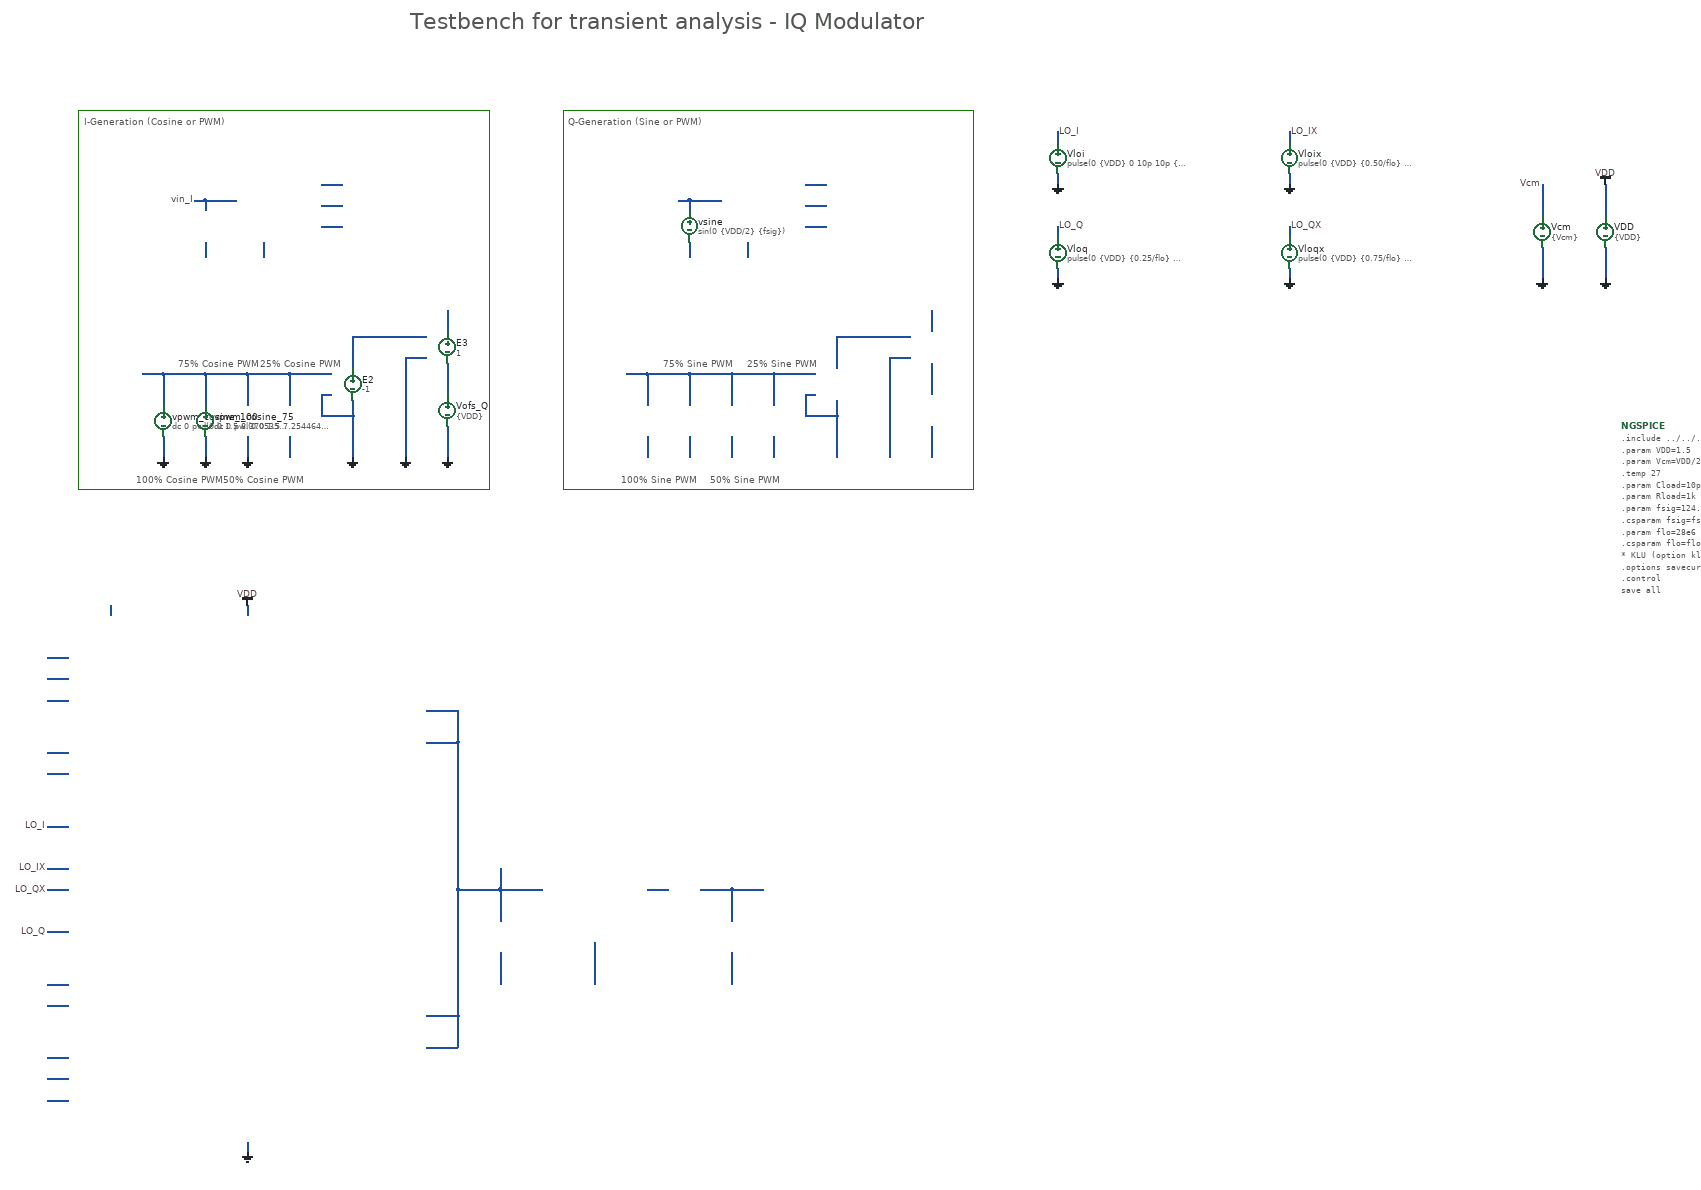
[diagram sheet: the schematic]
v {xschem version=3.4.8RC file_version=1.3}
G {}
K {}
V {}
S {}
F {}
E {}
B 2 1660 -1440 2460 -1040 {flags=graph
y1=-0.028
y2=2.632
ypos1=-0.028
ypos2=2.632
divy=5
subdivy=1
unity=1
x1=1.0032521e-05
x2=1.8057695e-05
divx=5
subdivx=1
xlabmag=1.0
ylabmag=1.0
node="LO_I
LO_Q
LO_IX
LO_QX"
color="4 7 12 21"
dataset=-1
unitx=1
logx=0
logy=0
linewidth_mult=3
autoload=0
digital=1}
B 2 1660 -1020 2460 -620 {flags=graph
y1=-0.39
y2=1.6
ypos1=0
ypos2=2
divy=5
subdivy=1
unity=1
x1=1.0032521e-05
x2=1.8057695e-05
divx=5
subdivx=1
xlabmag=1.0
ylabmag=1.0
node="vinp_I
vinn_I
vinp_Q
vinn_Q
vout_RF_filt"
color="4 7 12 18 21"
dataset=-1
unitx=1
logx=0
logy=0
linewidth_mult=3
autoload=0}
B 2 1660 -600 2460 -200 {flags=graph
y1=-0.052
y2=1.638
ypos1=0
ypos2=2
divy=5
subdivy=1
unity=1
x1=1.0032521e-05
x2=1.8057695e-05
divx=5
subdivx=1
xlabmag=1.0
ylabmag=1.0
node="vout_RF
vout_RF_filt"
color="4 7"
dataset=-1
unitx=1
logx=0
logy=0
linewidth_mult=3
autoload=0}
B 2 2540 -1440 3340 -1040 {flags=graph
y1=-0.086
y2=-0.0063
ypos1=0
ypos2=2
divy=5
subdivy=1
unity=1
x1=1.0032521e-05
x2=1.8057695e-05
divx=5
subdivx=1
xlabmag=1.0
ylabmag=1.0


dataset=-1
unitx=1
logx=0
logy=0
linewidth_mult=3
color=4
node=i(VDD)}
B 2 2540 -600 3340 -200 {flags=graph
y1=-0.00039
y2=0.00039
ypos1=0
ypos2=2
divy=5
subdivy=1
unity=1
x1=1.0032521e-05
x2=1.8057695e-05
divx=5
subdivx=1
xlabmag=1.0
ylabmag=1.0


dataset=-1
unitx=1
logx=0
logy=0
linewidth_mult=3
color=4
node=i(Vmeas)}
B 2 2540 -1020 3340 -620 {flags=graph
y1=0.25
y2=1.4
ypos1=0
ypos2=2
divy=5
subdivy=1
unity=1
x1=1.0032521e-05
x2=1.8057695e-05
divx=5
subdivx=1
xlabmag=1.0
ylabmag=1.0
node="x1.voutp_I_lpf
x1.voutn_I_lpf
x1.voutn_Q_lpf
x1.voutp_Q_lpf"
color="4 7 17 21"
dataset=-1
unitx=1
logx=0
logy=0
linewidth_mult=3
autoload=0}
B 4 240 -2200 1020 -1480 {fill = false
dash = 8}
B 4 1160 -2200 1940 -1480 {fill = false
dash = 8}
P 4 1 0 -2360 {}
T {Testbench for transient analysis - IQ Modulator} 870 -2380 0 0 1.5 1.5 {}
T {100% Cosine PWM} 350 -1510 0 0 0.25 0.25 {}
T {75% Cosine PWM} 430 -1730 0 0 0.25 0.25 {}
T {50% Cosine PWM} 515 -1510 0 0 0.25 0.25 {}
T {25% Cosine PWM} 585 -1730 0 0 0.25 0.25 {}
T {100% Sine PWM} 1270 -1510 0 0 0.25 0.25 {}
T {75% Sine PWM} 1350 -1730 0 0 0.25 0.25 {}
T {50% Sine PWM} 1440 -1510 0 0 0.25 0.25 {}
T {25% Sine PWM} 1510 -1730 0 0 0.25 0.25 {}
T {I-Generation (Cosine or PWM)} 250 -2190 0 0 0.4 0.4 {}
T {Q-Generation (Sine or PWM)} 1170 -2190 0 0 0.4 0.4 {}
N 560 -240 560 -220 {lab=GND}
N 180 -840 220 -840 {lab=LO_I}
N 180 -760 220 -760 {lab=LO_IX}
N 180 -640 220 -640 {lab=LO_Q}
N 180 -720 220 -720 {lab=LO_QX}
N 180 -500 220 -500 {lab=vinn_Q_sine}
N 180 -360 220 -360 {lab=vinp_Q_sine}
N 180 -1120 220 -1120 {lab=vinp_I_cosine}
N 180 -980 220 -980 {lab=vinn_I_cosine}
N 3140 -1940 3140 -1880 {lab=GND}
N 3140 -2060 3140 -2000 {lab=VDD}
N 3020 -1940 3020 -1880 {lab=GND}
N 3020 -2060 3020 -2000 {lab=Vcm}
N 2100 -1980 2100 -1960 {lab=LO_Q}
N 2100 -1900 2100 -1880 {lab=GND}
N 2540 -1980 2540 -1960 {lab=LO_QX}
N 2540 -1900 2540 -1880 {lab=GND}
N 2540 -2160 2540 -2140 {lab=LO_IX}
N 2540 -2080 2540 -2060 {lab=GND}
N 2100 -2160 2100 -2140 {lab=LO_I}
N 2100 -2080 2100 -2060 {lab=GND}
N 480 -1700 480 -1640 {lab=vinp_I_pwm}
N 480 -1580 480 -1540 {lab=GND}
N 400 -1580 400 -1540 {lab=GND}
N 400 -1700 400 -1640 {lab=vinp_I_pwm}
N 360 -1700 400 -1700 {lab=vinp_I_pwm}
N 400 -1700 480 -1700 {lab=vinp_I_pwm}
N 480 -1700 560 -1700 {lab=vinp_I_pwm}
N 760 -1620 760 -1540 {lab=GND}
N 700 -1660 720 -1660 {lab=GND}
N 700 -1660 700 -1620 {lab=GND}
N 700 -1620 760 -1620 {lab=GND}
N 940 -1820 940 -1780 {lab=vinn_I_pwm}
N 940 -1720 940 -1660 {lab=#net1}
N 940 -1600 940 -1540 {lab=GND}
N 860 -1730 900 -1730 {lab=GND}
N 860 -1730 860 -1540 {lab=GND}
N 760 -1770 900 -1770 {lab=#net2}
N 760 -1770 760 -1710 {lab=#net2}
N 560 -1700 560 -1640 {lab=vinp_I_pwm}
N 560 -1580 560 -1540 {lab=GND}
N 640 -1700 640 -1640 {lab=vinp_I_pwm}
N 640 -1580 640 -1540 {lab=GND}
N 560 -1700 640 -1700 {lab=vinp_I_pwm}
N 640 -1700 720 -1700 {lab=vinp_I_pwm}
N 1400 -1700 1400 -1640 {lab=vinp_Q_pwm}
N 1400 -1580 1400 -1540 {lab=GND}
N 1320 -1580 1320 -1540 {lab=GND}
N 1320 -1700 1320 -1640 {lab=vinp_Q_pwm}
N 1280 -1700 1320 -1700 {lab=vinp_Q_pwm}
N 1320 -1700 1400 -1700 {lab=vinp_Q_pwm}
N 1400 -1700 1480 -1700 {lab=vinp_Q_pwm}
N 1680 -1620 1680 -1540 {lab=GND}
N 1620 -1660 1640 -1660 {lab=GND}
N 1620 -1660 1620 -1620 {lab=GND}
N 1620 -1620 1680 -1620 {lab=GND}
N 1860 -1820 1860 -1780 {lab=vinn_Q_pwm}
N 1860 -1720 1860 -1660 {lab=#net3}
N 1860 -1600 1860 -1540 {lab=GND}
N 1780 -1730 1820 -1730 {lab=GND}
N 1780 -1730 1780 -1540 {lab=GND}
N 1680 -1770 1820 -1770 {lab=#net4}
N 1680 -1770 1680 -1710 {lab=#net4}
N 1480 -1700 1480 -1640 {lab=vinp_Q_pwm}
N 1480 -1580 1480 -1540 {lab=GND}
N 1560 -1700 1560 -1640 {lab=vinp_Q_pwm}
N 1560 -1580 1560 -1540 {lab=GND}
N 1480 -1700 1560 -1700 {lab=vinp_Q_pwm}
N 1560 -1700 1640 -1700 {lab=vinp_Q_pwm}
N 760 -1650 760 -1620 {lab=GND}
N 1680 -1650 1680 -1620 {lab=GND}
N 460 -2030 480 -2030 {lab=vin_I}
N 480 -2030 480 -2010 {lab=vin_I}
N 700 -2060 740 -2060 {lab=vinp_I_cosine}
N 700 -1980 740 -1980 {lab=vinn_I_cosine}
N 480 -2030 540 -2030 {lab=vin_I}
N 480 -1950 480 -1920 {lab=GND}
N 590 -1950 590 -1920 {lab=GND}
N 700 -2020 740 -2020 {lab=Vcm}
N 1380 -2030 1400 -2030 {lab=vin_Q}
N 1400 -2030 1400 -2010 {lab=vin_Q}
N 1620 -2060 1660 -2060 {lab=vinp_Q_sine}
N 1620 -1980 1660 -1980 {lab=vinn_Q_sine}
N 1400 -2030 1460 -2030 {lab=vin_Q}
N 1400 -1950 1400 -1920 {lab=GND}
N 1510 -1950 1510 -1920 {lab=GND}
N 1620 -2020 1660 -2020 {lab=Vcm}
N 1040 -760 1040 -720 {lab=vout_RF}
N 1220 -620 1220 -540 {lab=GND}
N 1480 -600 1480 -540 {lab=GND}
N 1480 -720 1480 -660 {lab=vout_RF_filt}
N 960 -720 1040 -720 {lab=vout_RF}
N 1040 -720 1040 -660 {lab=vout_RF}
N 1040 -600 1040 -540 {lab=GND}
N 1040 -720 1120 -720 {lab=vout_RF}
N 1320 -720 1360 -720 {lab=#net5}
N 1420 -720 1480 -720 {lab=vout_RF_filt}
N 1480 -720 1540 -720 {lab=vout_RF_filt}
N 560 -1260 560 -1240 {lab=VDD}
N 900 -1060 960 -1060 {lab=vout_RF}
N 960 -1000 960 -720 {lab=vout_RF}
N 900 -1000 960 -1000 {lab=vout_RF}
N 960 -1060 960 -1000 {lab=vout_RF}
N 900 -480 960 -480 {lab=vout_RF}
N 960 -720 960 -480 {lab=vout_RF}
N 900 -420 960 -420 {lab=vout_RF}
N 960 -480 960 -420 {lab=vout_RF}
N 300 -1260 300 -1240 {lab=VDD}
N 180 -1080 220 -1080 {lab=vinp_I_pwm}
N 180 -940 220 -940 {lab=vinn_I_pwm}
N 180 -540 220 -540 {lab=vinp_Q_pwm}
N 180 -400 220 -400 {lab=vinn_Q_pwm}
N 180 -320 220 -320 {lab=GND}
N 180 -1160 220 -1160 {lab=GND}
C {devices/code.sym} 3170 -1600 0 0 {name=NGSPICE
lock=false
only_toplevel=true 
value="
.include ../../../netlist/pex/iqmod_top_pex.spice
.param VDD=1.5
.param Vcm=VDD/2
.temp 27
.param Cload=10p
.param Rload=1k
.param fsig=124.600e3
.csparam fsig=fsig
.param flo=28e6
.csparam flo=flo
* KLU (option klu) did not converge on the old Magic full-RC PEX netlist with ngspice-47. On the KPEX 0.9.0 netlist KLU and Sparse 1.3 both converge
.options savecurrents method=gear reltol=1e-3 abstol=1e-12 gmin=1e-12 rshunt=1e12
.control

save all

* User Constants
* Increase tstop --> more FFT bins
* Decrease tstep --> higher fs/2 in FFT
let fmin = 0.1 * flo
let fmax = 5 * flo
let tstart = 1/fsig
let tstop = 2/fsig
let tstep = 0.1/flo

* Transient Operating Point Analysis
optran 0 0 0 $&tstep $&tstart 0

* Operating Point Analysis
* op
* remzerovec
* write @schname\\\\.raw
* set appendwrite

* Transient Analysis
tran $&tstep $&tstop $&tstart
write @schname\\\\.raw

* Plotting
plot vinp_I vinn_I vinp_Q vinn_Q
plot x1.voutp_I_lpf x1.voutn_I_lpf x1.voutp_Q_lpf x1.voutn_Q_lpf
plot LO_I LO_IX LO_Q LO_QX
plot vout_RF vout_RF_filt

* Calculation of Power Consumption & Efficiency
let PDD_inst = VDD * -i(VDD)
meas tran PDD_int INTEG PDD_inst from=tstart to=tstop
let PDD = 1/(tstop - tstart) * PDD_int * 1e3
echo PDD = $&PDD mW

let Pout_inst = v(vout_RF_filt) * i(Vmeas)
meas tran Pout_int INTEG Pout_inst from=tstart to=tstop
let Pout = 1/(tstop - tstart) * Pout_int * 1e3
echo Pout = $&Pout mW

let efficiency = Pout / PDD * 100
echo efficiency = $&efficiency %

* Write Data
unset appendwrite
set wr_vecnames
set wr_singlescale
wrdata ../plot_simulations/data/iqmod_top_tb_tran.txt v(vinp_Q) v(vinn_Q) v(vinp_I) v(vinn_I) v(LO_I) v(LO_IX) v(LO_Q) v(LO_QX) v(vout_RF) v(vout_RF_filt)

* FFT vout_RF
* setplot tran1
* linearize vout_RF
* set specwindow=hanning
* fft vout_RF
* setplot sp2

* let N = length(vout_RF)
* let fres = frequency[n-1]/n
* let fmin_idx = ceil(const.fmin/fres)
* let fmax_idx = ceil(const.fmax/fres)
* let vout_RF_spec = mag(vout_RF)
* let vout_RF_spec_slice = vout_RF_spec[fmin_idx,fmax_idx]
* let freq = frequency[fmin_idx,fmax_idx]
* meas sp vout_RF_max max vout_RF_spec_slice
* let vout_RF_spec_db = 20*log10(vout_RF_spec_slice/vout_RF_max)
* plot vout_RF_spec_db vs freq

* Write Data
* setscale freq
* unset appendwrite
* set wr_vecnames
* set wr_singlescale
* wrdata ../plot_simulations/data/iqmod_tb_tran_fft.txt v(vout_RF_spec_db)

* FFT vout_RF_filt
setplot tran1
linearize vout_RF_filt
set specwindow=hanning
fft vout_RF_filt
setplot sp2

let N = length(vout_RF_filt)
let fres = frequency[n-1]/n
let fmin_idx = ceil(const.fmin/fres)
let fmax_idx = ceil(const.fmax/fres)
let vout_RF_filt_spec = mag(vout_RF_filt)
let vout_RF_filt_spec_slice = vout_RF_filt_spec[fmin_idx,fmax_idx]
let freq = frequency[fmin_idx,fmax_idx]
meas sp vout_RF_filt_max max vout_RF_filt_spec_slice
let vout_RF_filt_spec_db = 20*log10(vout_RF_filt_spec_slice/vout_RF_filt_max)
plot vout_RF_filt_spec_db vs freq

* Write Data
setscale freq
unset appendwrite
set wr_vecnames
set wr_singlescale
wrdata ../plot_simulations/data/iqmod_tb_tran_fft_filt.txt v(vout_RF_filt_spec_db)

* Calc HD2, HD3
* let sig_idx = ceil(const.f_sig/fres)
* let hd2_idx = 2*sig_idx
* let hd3_idx = 3*sig_idx
* let sig_pwr = iod_spec[sig_idx-1]^2+iod_spec[sig_idx]^2+iod_spec[sig_idx+1]^2
* let hd2_pwr = iod_spec[hd2_idx-1]^2+iod_spec[hd2_idx]^2+iod_spec[hd2_idx+1]^2
* let hd3_pwr = iod_spec[hd3_idx-1]^2+iod_spec[hd3_idx]^2+iod_spec[hd3_idx+1]^2
* let hd2 = sqrt(hd2_pwr/sig_pwr)
* let hd3 = sqrt(hd3_pwr/sig_pwr)
* let hd2_dB = 20*log10(hd2)
* let hd3_dB = 20*log10(hd3)
* print hd2_dB
* print hd3_dB

*quit
.endc
"}
C {devices/launcher.sym} 2600 -1620 0 0 {name=h2
descr="Simulate" 
tclcommand="xschem save; xschem netlist; file mkdir $netlist_dir; write_data [save_params] $netlist_dir/[file rootname [file tail [xschem get current_name]]].save; xschem simulate"
}
C {devices/launcher.sym} 2600 -1500 0 0 {name=h1
descr="Load waves" 
tclcommand="xschem raw_read $netlist_dir/[file rootname [file tail [xschem get current_name]]].raw tran"
}
C {devices/launcher.sym} 2600 -1560 0 0 {name=h3
descr="Annotate OP" 
tclcommand="set show_hidden_texts 1; xschem annotate_op"
}
C {vdd.sym} 560 -1260 0 0 {name=l1 lab=VDD}
C {devices/gnd.sym} 560 -220 0 0 {name=l4 lab=GND}
C {devices/lab_wire.sym} 180 -840 0 0 {name=l11 sig_type=std_logic lab=LO_I}
C {devices/lab_wire.sym} 180 -760 0 0 {name=l12 sig_type=std_logic lab=LO_IX}
C {devices/lab_wire.sym} 180 -640 0 0 {name=l8 sig_type=std_logic lab=LO_Q}
C {devices/lab_wire.sym} 180 -720 0 0 {name=l22 sig_type=std_logic lab=LO_QX
}
C {devices/vsource.sym} 3140 -1970 0 0 {name=VDD value=\{VDD\}}
C {devices/gnd.sym} 3140 -1880 0 0 {name=l3 lab=GND}
C {vdd.sym} 3140 -2060 0 0 {name=l7 lab=VDD}
C {devices/gnd.sym} 2100 -2060 0 0 {name=l14 lab=GND}
C {devices/lab_wire.sym} 2100 -2160 0 1 {name=l15 sig_type=std_logic lab=LO_I}
C {devices/gnd.sym} 2540 -2060 0 0 {name=l9 lab=GND}
C {devices/lab_wire.sym} 2540 -2160 0 1 {name=l10 sig_type=std_logic lab=LO_IX}
C {devices/vsource.sym} 2100 -2110 0 0 {name=Vloi value="pulse(0 \{VDD\} 0 10p 10p \{0.25/flo\} \{1/flo\})"}
C {devices/vsource.sym} 2540 -2110 0 0 {name=Vloix value="pulse(0 \{VDD\} \{0.50/flo\} 10p 10p \{0.25/flo\} \{1/flo\})"}
C {devices/gnd.sym} 2100 -1880 0 0 {name=l23 lab=GND}
C {devices/lab_wire.sym} 2100 -1980 0 1 {name=l24 sig_type=std_logic lab=LO_Q}
C {devices/gnd.sym} 2540 -1880 0 0 {name=l27 lab=GND}
C {devices/lab_wire.sym} 2540 -1980 0 1 {name=l28 sig_type=std_logic lab=LO_QX}
C {devices/vsource.sym} 2540 -1930 0 0 {name=Vloqx value="pulse(0 \{VDD\} \{0.75/flo\} 10p 10p \{0.25/flo\} \{1/flo\})"}
C {devices/vsource.sym} 3020 -1970 0 0 {name=Vcm value=\{Vcm\}
}
C {devices/lab_pin.sym} 3020 -2060 1 0 {name=l34 sig_type=std_logic lab=Vcm}
C {devices/gnd.sym} 3020 -1880 0 0 {name=l40 lab=GND}
C {devices/vsource.sym} 2100 -1930 0 0 {name=Vloq value="pulse(0 \{VDD\} \{0.25/flo\} 10p 10p \{0.25/flo\} \{1/flo\})"}
C {devices/lab_pin.sym} 460 -2030 0 0 {name=l16 sig_type=std_logic lab=vin_I}
C {devices/vsource.sym} 1400 -1980 0 1 {name=vsine spice_ignore=false value="sin(0 \{VDD/2\} \{fsig\})"
}
C {devices/vcvs.sym} 760 -1680 0 0 {name=E2 value=-1}
C {devices/vsource.sym} 400 -1610 0 0 {name=vpwm_cosine_100 hide_texts=true value="dc 0 pwl(0.0 1.5 8.370535714285714e-09 1.5 8.928571428571428e-09 0.0 8.928571428571428e-09 0.0 9.486607142857142e-09 1.5 2.6227678571428568e-08 1.5 2.6785714285714285e-08 0.0 2.6785714285714285e-08 0.0 2.734375e-08 1.5 4.408482142857143e-08 1.5 4.464285714285714e-08 0.0 4.464285714285714e-08 0.0 4.5200892857142855e-08 1.5 6.194196428571429e-08 1.5 6.25e-08 0.0 6.25e-08 0.0 6.305803571428571e-08 1.5 7.979910714285714e-08 1.5 8.035714285714285e-08 0.0 8.035714285714285e-08 0.0 8.091517857142856e-08 1.5 9.765624999999999e-08 1.5 9.82142857142857e-08 0.0 9.82142857142857e-08 0.0 9.877232142857143e-08 1.5 1.1551339285714284e-07 1.5 1.1607142857142857e-07 0.0 1.1607142857142857e-07 0.0 1.1662946428571428e-07 1.5 1.333705357142857e-07 1.5 1.3392857142857142e-07 0.0 1.3392857142857142e-07 0.0 1.3448660714285714e-07 1.5 1.5122767857142855e-07 1.5 1.5178571428571427e-07 0.0 1.5178571428571427e-07 0.0 1.5234375e-07 1.5 1.6908482142857143e-07 1.5 1.6964285714285713e-07 0.0 1.6964285714285713e-07 0.0 1.7020089285714285e-07 1.5 1.8694196428571428e-07 1.5 1.8749999999999998e-07 0.0 1.8749999999999998e-07 0.0 1.880580357142857e-07 1.5 2.0479910714285713e-07 1.5 2.0535714285714283e-07 0.0 2.0535714285714283e-07 0.0 2.0591517857142855e-07 1.5 2.2265624999999999e-07 1.5 2.232142857142857e-07 0.0 2.232142857142857e-07 0.0 2.237723214285714e-07 1.5 2.4051339285714286e-07 1.5 2.4107142857142856e-07 0.0 2.4107142857142856e-07 0.0 2.4162946428571426e-07 1.5 2.583705357142857e-07 1.5 2.589285714285714e-07 0.0 2.589285714285714e-07 0.0 2.594866071428571e-07 1.5 2.7622767857142857e-07 1.5 2.7678571428571427e-07 0.0 2.7678571428571427e-07 0.0 2.7734374999999997e-07 1.5 2.940848214285714e-07 1.5 2.946428571428571e-07 0.0 2.946428571428571e-07 0.0 2.952008928571428e-07 1.5 3.119419642857143e-07 1.5 3.1249999999999997e-07 0.0 3.1249999999999997e-07 0.0 3.1305803571428567e-07 1.5 3.2979910714285713e-07 1.5 3.303571428571428e-07 0.0 3.303571428571428e-07 0.0 3.309151785714285e-07 1.5 3.4765625e-07 1.5 3.482142857142857e-07 0.0 3.482142857142857e-07 0.0 3.4877232142857143e-07 1.5 3.6551339285714283e-07 1.5 3.6607142857142853e-07 0.0 3.6607142857142853e-07 0.0 3.666294642857143e-07 1.5 3.833705357142857e-07 1.5 3.839285714285714e-07 0.0 3.839285714285714e-07 0.0 3.8448660714285713e-07 1.5 4.0122767857142854e-07 1.5 4.0178571428571424e-07 0.0 4.0178571428571424e-07 0.0 4.0234375e-07 1.5 4.190848214285714e-07 1.5 4.196428571428571e-07 0.0 4.196428571428571e-07 0.0 4.2020089285714284e-07 1.5 4.3694196428571424e-07 1.5 4.375e-07 0.0 4.375e-07 0.0 4.380580357142857e-07 1.5 4.547991071428571e-07 1.5 4.5535714285714285e-07 0.0 4.5535714285714285e-07 0.0 4.5591517857142854e-07 1.5 4.7265624999999995e-07 1.5 4.732142857142857e-07 0.0 4.732142857142857e-07 0.0 4.737723214285714e-07 1.5 4.905133928571428e-07 1.5 4.910714285714285e-07 0.0 4.910714285714285e-07 0.0 4.916294642857143e-07 1.5 5.083705357142857e-07 1.5 5.089285714285714e-07 0.0 5.089285714285714e-07 0.0 5.094866071428572e-07 1.5 5.262276785714285e-07 1.5 5.267857142857142e-07 0.0 5.267857142857142e-07 0.0 5.2734375e-07 1.5 5.440848214285714e-07 1.5 5.446428571428571e-07 0.0 5.446428571428571e-07 0.0 5.452008928571429e-07 1.5 5.619419642857142e-07 1.5 5.624999999999999e-07 0.0 5.624999999999999e-07 0.0 5.630580357142857e-07 1.5 5.797991071428571e-07 1.5 5.803571428571429e-07 0.0 5.803571428571429e-07 0.0 5.809151785714286e-07 1.5 5.976562499999999e-07 1.5 5.982142857142857e-07 0.0 5.982142857142857e-07 0.0 5.987723214285714e-07 1.5 6.155133928571428e-07 1.5 6.160714285714286e-07 0.0 6.160714285714286e-07 0.0 6.166294642857143e-07 1.5 6.333705357142856e-07 1.5 6.339285714285714e-07 0.0 6.339285714285714e-07 0.0 6.344866071428571e-07 1.5 6.506696428571428e-07 1.5 6.512276785714285e-07 0.0 6.5234375e-07 0.0 6.529017857142857e-07 1.5 6.685267857142856e-07 1.5 6.690848214285714e-07 0.0 6.702008928571428e-07 0.0 6.707589285714285e-07 1.5 6.863839285714285e-07 1.5 6.869419642857143e-07 0.0 6.880580357142857e-07 0.0 6.886160714285714e-07 1.5 7.042410714285713e-07 1.5 7.047991071428571e-07 0.0 7.059151785714285e-07 0.0 7.064732142857142e-07 1.5 7.220982142857142e-07 1.5 7.2265625e-07 0.0 7.237723214285714e-07 0.0 7.243303571428571e-07 1.5 7.39955357142857e-07 1.5 7.405133928571428e-07 0.0 7.416294642857142e-07 0.0 7.421874999999999e-07 1.5 7.578125e-07 1.5 7.583705357142857e-07 0.0 7.594866071428571e-07 0.0 7.600446428571428e-07 1.5 7.756696428571428e-07 1.5 7.762276785714285e-07 0.0 7.773437499999999e-07 0.0 7.779017857142856e-07 1.5 7.935267857142857e-07 1.5 7.940848214285714e-07 0.0 7.952008928571428e-07 0.0 7.957589285714285e-07 1.5 8.113839285714286e-07 1.5 8.119419642857143e-07 0.0 8.130580357142856e-07 0.0 8.136160714285713e-07 1.5 8.292410714285714e-07 1.5 8.297991071428571e-07 0.0 8.309151785714285e-07 0.0 8.314732142857142e-07 1.5 8.470982142857143e-07 1.5 8.4765625e-07 0.0 8.487723214285714e-07 0.0 8.49330357142857e-07 1.5 8.649553571428571e-07 1.5 8.655133928571428e-07 0.0 8.666294642857142e-07 0.0 8.671874999999999e-07 1.5 8.828125e-07 1.5 8.833705357142857e-07 0.0 8.844866071428571e-07 0.0 8.850446428571428e-07 1.5 9.006696428571428e-07 1.5 9.012276785714285e-07 0.0 9.023437499999999e-07 0.0 9.029017857142856e-07 1.5 9.185267857142857e-07 1.5 9.190848214285714e-07 0.0 9.202008928571428e-07 0.0 9.207589285714285e-07 1.5 9.358258928571428e-07 1.5 9.363839285714285e-07 0.0 9.386160714285713e-07 0.0 9.391741071428571e-07 1.5 9.536830357142856e-07 1.5 9.542410714285713e-07 0.0 9.564732142857143e-07 0.0 9.5703125e-07 1.5 9.715401785714285e-07 1.5 9.720982142857142e-07 0.0 9.74330357142857e-07 0.0 9.748883928571427e-07 1.5 9.893973214285713e-07 1.5 9.89955357142857e-07 0.0 9.921875e-07 0.0 9.927455357142857e-07 1.5 1.0072544642857142e-06 1.5 1.0078125e-06 0.0 1.0100446428571427e-06 0.0 1.0106026785714284e-06 1.5 1.025111607142857e-06 1.5 1.0256696428571427e-06 0.0 1.0279017857142857e-06 0.0 1.0284598214285714e-06 1.5 1.04296875e-06 1.5 1.0435267857142856e-06 0.0 1.0457589285714284e-06 0.0 1.0463169642857141e-06 1.5 1.0608258928571427e-06 1.5 1.0613839285714286e-06 0.0 1.0636160714285714e-06 0.0 1.064174107142857e-06 1.5 1.0786830357142856e-06 1.5 1.0792410714285713e-06 0.0 1.0814732142857141e-06 0.0 1.0820312499999998e-06 1.5 1.0965401785714284e-06 1.5 1.0970982142857143e-06 0.0 1.099330357142857e-06 0.0 1.0998883928571428e-06 1.5 1.1143973214285714e-06 1.5 1.114955357142857e-06 0.0 1.1171874999999998e-06 0.0 1.1177455357142855e-06 1.5 1.1322544642857143e-06 1.5 1.1328125e-06 0.0 1.1350446428571428e-06 0.0 1.1356026785714285e-06 1.5 1.1495535714285714e-06 1.5 1.150111607142857e-06 0.0 1.1534598214285712e-06 0.0 1.1540178571428572e-06 1.5 1.167410714285714e-06 1.5 1.16796875e-06 0.0 1.1713169642857142e-06 0.0 1.171875e-06 1.5 1.185267857142857e-06 1.5 1.1858258928571428e-06 0.0 1.1891741071428572e-06 0.0 1.1897321428571429e-06 1.5 1.2031249999999998e-06 1.5 1.2036830357142857e-06 0.0 1.20703125e-06 0.0 1.2075892857142856e-06 1.5 1.2209821428571428e-06 1.5 1.2215401785714285e-06 0.0 1.2248883928571429e-06 0.0 1.2254464285714286e-06 1.5 1.2388392857142857e-06 1.5 1.2393973214285714e-06 0.0 1.2427455357142856e-06 0.0 1.2433035714285713e-06 1.5 1.2566964285714285e-06 1.5 1.2572544642857142e-06 0.0 1.2606026785714286e-06 0.0 1.2611607142857143e-06 1.5 1.2745535714285714e-06 1.5 1.2751116071428571e-06 0.0 1.2784598214285713e-06 0.0 1.279017857142857e-06 1.5 1.2924107142857142e-06 1.5 1.2929687499999999e-06 0.0 1.2963169642857143e-06 0.0 1.296875e-06 1.5 1.3102678571428571e-06 1.5 1.3108258928571428e-06 0.0 1.314174107142857e-06 0.0 1.3147321428571427e-06 1.5 1.3281249999999999e-06 1.5 1.3286830357142856e-06 0.0 1.33203125e-06 0.0 1.3325892857142857e-06 1.5 1.3454241071428571e-06 1.5 1.3459821428571428e-06 0.0 1.3504464285714284e-06 0.0 1.3510044642857141e-06 1.5 1.3632812499999999e-06 1.5 1.3638392857142856e-06 0.0 1.3683035714285714e-06 0.0 1.368861607142857e-06 1.5 1.3811383928571428e-06 1.5 1.3816964285714285e-06 0.0 1.3861607142857141e-06 0.0 1.3867187499999998e-06 1.5 1.3989955357142856e-06 1.5 1.3995535714285713e-06 0.0 1.404017857142857e-06 0.0 1.4045758928571428e-06 1.5 1.4168526785714286e-06 1.5 1.4174107142857143e-06 0.0 1.4218749999999998e-06 0.0 1.4224330357142855e-06 1.5 1.4347098214285713e-06 1.5 1.435267857142857e-06 0.0 1.4397321428571428e-06 0.0 1.4402901785714285e-06 1.5 1.4525669642857143e-06 1.5 1.453125e-06 0.0 1.4575892857142855e-06 0.0 1.4581473214285712e-06 1.5 1.470424107142857e-06 1.5 1.4709821428571427e-06 0.0 1.4754464285714285e-06 0.0 1.4760044642857142e-06 1.5 1.48828125e-06 1.5 1.4888392857142857e-06 0.0 1.4933035714285712e-06 0.0 1.493861607142857e-06 1.5 1.5061383928571427e-06 1.5 1.5066964285714284e-06 0.0 1.5111607142857142e-06 0.0 1.51171875e-06 1.5 1.5234375e-06 1.5 1.5239955357142857e-06 0.0 1.5295758928571426e-06 0.0 1.5301339285714286e-06 1.5 1.5412946428571427e-06 1.5 1.5418526785714284e-06 0.0 1.5474330357142856e-06 0.0 1.5479910714285713e-06 1.5 1.5591517857142857e-06 1.5 1.5597098214285714e-06 0.0 1.5652901785714286e-06 0.0 1.5658482142857143e-06 1.5 1.5770089285714284e-06 1.5 1.5775669642857141e-06 0.0 1.5831473214285713e-06 0.0 1.583705357142857e-06 1.5 1.5948660714285714e-06 1.5 1.595424107142857e-06 0.0 1.6010044642857143e-06 0.0 1.6015625e-06 1.5 1.6127232142857141e-06 1.5 1.6132812499999998e-06 0.0 1.618861607142857e-06 0.0 1.6194196428571427e-06 1.5 1.630580357142857e-06 1.5 1.6311383928571428e-06 0.0 1.63671875e-06 0.0 1.6372767857142857e-06 1.5 1.6484374999999998e-06 1.5 1.6489955357142855e-06 0.0 1.6545758928571427e-06 0.0 1.6551339285714284e-06 1.5 1.6662946428571428e-06 1.5 1.6668526785714285e-06 0.0 1.6724330357142857e-06 0.0 1.6729910714285714e-06 1.5 1.6835937499999998e-06 1.5 1.6841517857142855e-06 0.0 1.6908482142857141e-06 0.0 1.6914062499999998e-06 1.5 1.7014508928571428e-06 1.5 1.7020089285714285e-06 0.0 1.708705357142857e-06 0.0 1.7092633928571428e-06 1.5 1.7193080357142855e-06 1.5 1.7198660714285712e-06 0.0 1.7265624999999998e-06 0.0 1.7271205357142855e-06 1.5 1.7371651785714285e-06 1.5 1.7377232142857142e-06 0.0 1.7444196428571428e-06 0.0 1.7449776785714285e-06 1.5 1.7550223214285713e-06 1.5 1.755580357142857e-06 0.0 1.7622767857142855e-06 0.0 1.7628348214285712e-06 1.5 1.7728794642857142e-06 1.5 1.7734375e-06 0.0 1.7801339285714285e-06 0.0 1.7806919642857142e-06 1.5 1.790736607142857e-06 1.5 1.7912946428571427e-06 0.0 1.7979910714285712e-06 0.0 1.798549107142857e-06 1.5 1.80859375e-06 1.5 1.8091517857142856e-06 0.0 1.8158482142857142e-06 0.0 1.8164062499999999e-06 1.5 1.8264508928571427e-06 1.5 1.8270089285714284e-06 0.0 1.833705357142857e-06 0.0 1.8342633928571426e-06 1.5 1.8443080357142856e-06 1.5 1.8448660714285713e-06 0.0 1.8521205357142856e-06 0.0 1.8526785714285713e-06 1.5 1.8616071428571427e-06 1.5 1.8621651785714284e-06 0.0 1.8699776785714283e-06 0.0 1.8705357142857143e-06 1.5 1.8794642857142856e-06 1.5 1.8800223214285713e-06 0.0 1.8878348214285713e-06 0.0 1.888392857142857e-06 1.5 1.8973214285714284e-06 1.5 1.897879464285714e-06 0.0 1.905691964285714e-06 0.0 1.90625e-06 1.5 1.9151785714285713e-06 1.5 1.915736607142857e-06 0.0 1.923549107142857e-06 0.0 1.924107142857143e-06 1.5 1.933035714285714e-06 1.5 1.93359375e-06 0.0 1.9414062499999998e-06 0.0 1.9419642857142857e-06 1.5 1.950892857142857e-06 1.5 1.9514508928571427e-06 0.0 1.959263392857143e-06 0.0 1.9598214285714284e-06 1.5 1.96875e-06 1.5 1.9693080357142855e-06 0.0 1.9771205357142857e-06 0.0 1.977678571428571e-06 1.5 1.9866071428571427e-06 1.5 1.9871651785714282e-06 0.0 1.9949776785714284e-06 0.0 1.9955357142857143e-06 1.5 2.0044642857142855e-06 1.5 2.0050223214285714e-06 0.0 2.013392857142857e-06 0.0 2.0139508928571426e-06 1.5 2.0217633928571428e-06 1.5 2.0223214285714282e-06 0.0 2.03125e-06 0.0 2.0318080357142857e-06 1.5 2.0396205357142855e-06 1.5 2.0401785714285714e-06 0.0 2.0491071428571426e-06 0.0 2.0496651785714285e-06 1.5 2.0574776785714282e-06 1.5 2.058035714285714e-06 0.0 2.0669642857142857e-06 0.0 2.0675223214285712e-06 1.5 2.0753348214285714e-06 1.5 2.075892857142857e-06 0.0 2.0848214285714285e-06 0.0 2.085379464285714e-06 1.5 2.093191964285714e-06 1.5 2.0937499999999996e-06 0.0 2.1026785714285712e-06 0.0 2.103236607142857e-06 1.5 2.111049107142857e-06 1.5 2.111607142857143e-06 0.0 2.120535714285714e-06 0.0 2.12109375e-06 1.5 2.1289062499999997e-06 1.5 2.1294642857142856e-06 0.0 2.138392857142857e-06 0.0 2.1389508928571426e-06 1.5 2.146763392857143e-06 1.5 2.1473214285714283e-06 0.0 2.15625e-06 0.0 2.1568080357142854e-06 1.5 2.1646205357142856e-06 1.5 2.1651785714285715e-06 0.0 2.1746651785714286e-06 0.0 2.175223214285714e-06 1.5 2.181919642857143e-06 1.5 2.1824776785714283e-06 0.0 2.1925223214285713e-06 0.0 2.1930803571428568e-06 1.5 2.1997767857142856e-06 1.5 2.200334821428571e-06 0.0 2.210379464285714e-06 0.0 2.2109375e-06 1.5 2.2176339285714283e-06 1.5 2.2181919642857142e-06 0.0 2.228236607142857e-06 0.0 2.2287946428571427e-06 1.5 2.235491071428571e-06 1.5 2.236049107142857e-06 0.0 2.24609375e-06 0.0 2.2466517857142854e-06 1.5 2.2533482142857142e-06 1.5 2.2539062499999997e-06 0.0 2.2639508928571427e-06 0.0 2.2645089285714286e-06 1.5 2.271205357142857e-06 1.5 2.271763392857143e-06 0.0 2.2818080357142855e-06 0.0 2.2823660714285714e-06 1.5 2.2890624999999997e-06 1.5 2.2896205357142856e-06 0.0 2.299665178571428e-06 0.0 2.300223214285714e-06 1.5 2.3069196428571425e-06 1.5 2.3074776785714284e-06 0.0 2.3175223214285714e-06 0.0 2.318080357142857e-06 1.5 2.3247767857142857e-06 1.5 2.325334821428571e-06 0.0 2.3359375e-06 0.0 2.3364955357142855e-06 1.5 2.3420758928571425e-06 1.5 2.3426339285714284e-06 0.0 2.3537946428571428e-06 0.0 2.3543526785714283e-06 1.5 2.3599330357142857e-06 1.5 2.360491071428571e-06 0.0 2.3716517857142855e-06 0.0 2.3722098214285714e-06 1.5 2.3777901785714284e-06 1.5 2.3783482142857143e-06 0.0 2.3895089285714283e-06 0.0 2.390066964285714e-06 1.5 2.395647321428571e-06 1.5 2.396205357142857e-06 0.0 2.4073660714285714e-06 0.0 2.407924107142857e-06 1.5 2.4135044642857143e-06 1.5 2.4140625e-06 0.0 2.425223214285714e-06 0.0 2.4257812499999997e-06 1.5 2.431361607142857e-06 1.5 2.4319196428571426e-06 0.0 2.443080357142857e-06 0.0 2.443638392857143e-06 1.5 2.44921875e-06 1.5 2.4497767857142857e-06 0.0 2.4609374999999997e-06 0.0 2.4614955357142856e-06 1.5 2.4670758928571426e-06 1.5 2.4676339285714285e-06 0.0 2.478794642857143e-06 0.0 2.4793526785714283e-06 1.5 2.4849330357142857e-06 1.5 2.4854910714285712e-06 0.0 2.4966517857142856e-06 0.0 2.497209821428571e-06 1.5 2.5022321428571426e-06 1.5 2.5027901785714285e-06 0.0 2.5150669642857143e-06 0.0 2.5156249999999997e-06 1.5 2.5200892857142857e-06 1.5 2.5206473214285712e-06 0.0 2.532924107142857e-06 0.0 2.5334821428571425e-06 1.5 2.5379464285714285e-06 1.5 2.538504464285714e-06 0.0 2.5507812499999997e-06 0.0 2.5513392857142857e-06 1.5 2.5558035714285712e-06 1.5 2.556361607142857e-06 0.0 2.5686383928571425e-06 0.0 2.5691964285714284e-06 1.5 2.573660714285714e-06 1.5 2.57421875e-06 0.0 2.5864955357142857e-06 0.0 2.587053571428571e-06 1.5 2.591517857142857e-06 1.5 2.5920758928571426e-06 0.0 2.6043526785714284e-06 0.0 2.604910714285714e-06 1.5 2.609375e-06 1.5 2.6099330357142854e-06 0.0 2.622209821428571e-06 0.0 2.622767857142857e-06 1.5 2.6272321428571426e-06 1.5 2.6277901785714286e-06 0.0 2.640066964285714e-06 0.0 2.640625e-06 1.5 2.6450892857142854e-06 1.5 2.6456473214285713e-06 0.0 2.657924107142857e-06 0.0 2.6584821428571426e-06 1.5 2.6629464285714286e-06 1.5 2.663504464285714e-06 0.0 2.6763392857142857e-06 0.0 2.6768973214285712e-06 1.5 2.6802455357142854e-06 1.5 2.6808035714285713e-06 0.0 2.6941964285714285e-06 0.0 2.694754464285714e-06 1.5 2.6981026785714286e-06 1.5 2.698660714285714e-06 0.0 2.7120535714285712e-06 0.0 2.712611607142857e-06 1.5 2.7159598214285713e-06 1.5 2.716517857142857e-06 0.0 2.729910714285714e-06 0.0 2.73046875e-06 1.5 2.733816964285714e-06 1.5 2.734375e-06 0.0 2.747767857142857e-06 0.0 2.7483258928571426e-06 1.5 2.751674107142857e-06 1.5 2.7522321428571427e-06 0.0 2.765625e-06 0.0 2.7661830357142854e-06 1.5 2.76953125e-06 1.5 2.7700892857142855e-06 0.0 2.7834821428571426e-06 0.0 2.7840401785714285e-06 1.5 2.7873883928571427e-06 1.5 2.7879464285714282e-06 0.0 2.8013392857142854e-06 0.0 2.8018973214285713e-06 1.5 2.8052455357142855e-06 1.5 2.8058035714285714e-06 0.0 2.8191964285714285e-06 0.0 2.819754464285714e-06 1.5 2.8231026785714282e-06 1.5 2.823660714285714e-06 0.0 2.8370535714285713e-06 0.0 2.8376116071428568e-06 1.5 2.8409598214285714e-06 1.5 2.841517857142857e-06 0.0 2.854910714285714e-06 0.0 2.85546875e-06 1.5 2.858816964285714e-06 1.5 2.8593749999999996e-06 0.0 2.8733258928571427e-06 0.0 2.873883928571428e-06 1.5 2.8761160714285714e-06 1.5 2.876674107142857e-06 0.0 2.8911830357142854e-06 0.0 2.8917410714285714e-06 1.5 2.893973214285714e-06 1.5 2.8945312499999996e-06 0.0 2.909040178571428e-06 0.0 2.909598214285714e-06 1.5 2.911830357142857e-06 1.5 2.912388392857143e-06 0.0 2.9268973214285714e-06 0.0 2.927455357142857e-06 1.5 2.9296874999999996e-06 1.5 2.9302455357142855e-06 0.0 2.944754464285714e-06 0.0 2.9453124999999996e-06 1.5 2.947544642857143e-06 1.5 2.9481026785714283e-06 0.0 2.962611607142857e-06 0.0 2.9631696428571428e-06 1.5 2.9654017857142856e-06 1.5 2.965959821428571e-06 0.0 2.9804687499999996e-06 0.0 2.9810267857142855e-06 1.5 2.9832589285714283e-06 1.5 2.983816964285714e-06 0.0 2.9983258928571428e-06 0.0 2.9988839285714283e-06 1.5 3.001116071428571e-06 1.5 3.001674107142857e-06 0.0 3.0161830357142855e-06 0.0 3.016741071428571e-06 1.5 3.0189732142857142e-06 1.5 3.0195312499999997e-06 0.0 3.0340401785714283e-06 0.0 3.034598214285714e-06 1.5 3.036830357142857e-06 1.5 3.0373883928571425e-06 0.0 3.051897321428571e-06 0.0 3.052455357142857e-06 1.5 3.0546874999999997e-06 1.5 3.0552455357142856e-06 0.0 3.069754464285714e-06 0.0 3.0703124999999997e-06 1.5 3.0725446428571425e-06 1.5 3.0731026785714284e-06 0.0 3.087611607142857e-06 0.0 3.088169642857143e-06 1.5 3.0898437499999997e-06 1.5 3.0904017857142856e-06 0.0 3.1060267857142856e-06 0.0 3.106584821428571e-06 1.5 3.1077008928571425e-06 1.5 3.1082589285714284e-06 0.0 3.1238839285714283e-06 0.0 3.1244419642857142e-06 1.5 3.1255580357142856e-06 1.5 3.126116071428571e-06 0.0 3.141741071428571e-06 0.0 3.142299107142857e-06 1.5 3.1434151785714284e-06 1.5 3.143973214285714e-06 0.0 3.1595982142857142e-06 0.0 3.1601562499999997e-06 1.5 3.161272321428571e-06 1.5 3.161830357142857e-06 0.0 3.177455357142857e-06 0.0 3.1780133928571425e-06 1.5 3.179129464285714e-06 1.5 3.1796874999999998e-06 0.0 3.1953124999999997e-06 0.0 3.1958705357142857e-06 1.5 3.196986607142857e-06 1.5 3.1975446428571425e-06 0.0 3.2131696428571425e-06 0.0 3.2137276785714284e-06 1.5 3.21484375e-06 1.5 3.2154017857142853e-06 0.0 3.2310267857142857e-06 0.0 3.231584821428571e-06 1.5 3.2327008928571425e-06 1.5 3.2332589285714284e-06 0.0 3.2488839285714284e-06 0.0 3.249441964285714e-06 1.5 3.2505580357142853e-06 1.5 3.251116071428571e-06 0.0 3.266741071428571e-06 0.0 3.267299107142857e-06 1.5 3.2684151785714285e-06 1.5 3.268973214285714e-06 0.0 3.284598214285714e-06 0.0 3.28515625e-06 1.5 3.286272321428571e-06 1.5 3.286830357142857e-06 0.0 3.302455357142857e-06 0.0 3.3030133928571426e-06 1.5 3.304129464285714e-06 1.5 3.3046875e-06 0.0 3.3203125e-06 0.0 3.3208705357142853e-06 1.5 3.3219866071428567e-06 1.5 3.3225446428571426e-06 0.0 3.3381696428571426e-06 0.0 3.3387276785714285e-06 1.5 3.33984375e-06 1.5 3.3404017857142854e-06 0.0 3.3560267857142853e-06 0.0 3.3565848214285712e-06 1.5 3.3577008928571426e-06 1.5 3.3582589285714285e-06 0.0 3.374441964285714e-06 0.0 3.375e-06 1.5 3.375e-06 1.5 3.3755580357142854e-06 0.0 3.3922991071428567e-06 0.0 3.3928571428571426e-06 1.5 3.3928571428571426e-06 1.5 3.3934151785714285e-06 0.0 3.41015625e-06 0.0 3.4107142857142854e-06 1.5 3.4107142857142854e-06 1.5 3.4112723214285713e-06 0.0 3.4280133928571426e-06 0.0 3.4285714285714285e-06 1.5 3.4285714285714285e-06 1.5 3.429129464285714e-06 0.0 3.4458705357142854e-06 0.0 3.4464285714285713e-06 1.5 3.4464285714285713e-06 1.5 3.4469866071428568e-06 0.0 3.463727678571428e-06 0.0 3.464285714285714e-06 1.5 3.464285714285714e-06 1.5 3.46484375e-06 0.0 3.4815848214285713e-06 0.0 3.4821428571428568e-06 1.5 3.4821428571428568e-06 1.5 3.4827008928571427e-06 0.0 3.499441964285714e-06 0.0 3.5e-06 1.5 3.5e-06 1.5 3.5005580357142854e-06 0.0 3.5172991071428568e-06 0.0 3.5178571428571427e-06 1.5 3.5178571428571427e-06 1.5 3.518415178571428e-06 0.0 3.53515625e-06 0.0 3.5357142857142854e-06 1.5 3.5357142857142854e-06 1.5 3.5362723214285714e-06 0.0 3.5530133928571427e-06 0.0 3.553571428571428e-06 1.5 3.553571428571428e-06 1.5 3.554129464285714e-06 0.0 3.5708705357142854e-06 0.0 3.5714285714285714e-06 1.5 3.5714285714285714e-06 1.5 3.571986607142857e-06 0.0 3.588727678571428e-06 0.0 3.589285714285714e-06 1.5 3.589285714285714e-06 1.5 3.5898437499999996e-06 0.0 3.6065848214285714e-06 0.0 3.607142857142857e-06 1.5 3.607142857142857e-06 1.5 3.6077008928571428e-06 0.0 3.624441964285714e-06 0.0 3.6249999999999996e-06 1.5 3.6249999999999996e-06 1.5 3.6255580357142855e-06 0.0 3.642299107142857e-06 0.0 3.6428571428571428e-06 1.5 3.6428571428571428e-06 1.5 3.6434151785714283e-06 0.0 3.6601562499999996e-06 0.0 3.6607142857142855e-06 1.5 3.6607142857142855e-06 1.5 3.661272321428571e-06 0.0 3.6780133928571428e-06 0.0 3.6785714285714283e-06 1.5 3.6785714285714283e-06 1.5 3.679129464285714e-06 0.0 3.6958705357142855e-06 0.0 3.696428571428571e-06 1.5 3.696428571428571e-06 1.5 3.696986607142857e-06 0.0 3.7137276785714283e-06 0.0 3.714285714285714e-06 1.5 3.714285714285714e-06 1.5 3.7148437499999997e-06 0.0 3.731584821428571e-06 0.0 3.732142857142857e-06 1.5 3.732142857142857e-06 1.5 3.7327008928571424e-06 0.0 3.749441964285714e-06 0.0 3.7499999999999997e-06 1.5 3.7499999999999997e-06 1.5 3.7505580357142856e-06 0.0 3.767299107142857e-06 0.0 3.7678571428571424e-06 1.5 3.7678571428571424e-06 1.5 3.7684151785714283e-06 0.0 3.7851562499999997e-06 0.0 3.7857142857142856e-06 1.5 3.7857142857142856e-06 1.5 3.786272321428571e-06 0.0 3.8030133928571424e-06 0.0 3.8035714285714283e-06 1.5 3.8035714285714283e-06 1.5 3.804129464285714e-06 0.0 3.820870535714286e-06 0.0 3.8214285714285715e-06 1.5 3.8214285714285715e-06 1.5 3.8219866071428566e-06 0.0 3.838727678571428e-06 0.0 3.839285714285714e-06 1.5 3.839285714285714e-06 1.5 3.83984375e-06 0.0 3.856584821428571e-06 0.0 3.857142857142857e-06 1.5 3.857142857142857e-06 1.5 3.857700892857143e-06 0.0 3.874441964285714e-06 0.0 3.874999999999999e-06 1.5 3.874999999999999e-06 1.5 3.875558035714285e-06 0.0 3.892299107142857e-06 0.0 3.8928571428571425e-06 1.5 3.8928571428571425e-06 1.5 3.893415178571428e-06 0.0 3.91015625e-06 0.0 3.910714285714286e-06 1.5 3.910714285714286e-06 1.5 3.9112723214285716e-06 0.0 3.928013392857143e-06 0.0 3.928571428571428e-06 1.5 3.928571428571428e-06 1.5 3.929129464285714e-06 0.0 3.945870535714285e-06 0.0 3.946428571428571e-06 1.5 3.946428571428571e-06 1.5 3.946986607142857e-06 0.0 3.963727678571428e-06 0.0 3.964285714285714e-06 1.5 3.964285714285714e-06 1.5 3.964843749999999e-06 0.0 3.981584821428571e-06 0.0 3.982142857142857e-06 1.5 3.982142857142857e-06 1.5 3.9827008928571426e-06 0.0 3.999441964285714e-06 0.0 4e-06 1.5 4e-06 1.5 4.000558035714286e-06 0.0 4.017299107142857e-06 0.0 4.017857142857143e-06 1.5 4.017857142857143e-06 1.5 4.018415178571428e-06 0.0 4.035156249999999e-06 0.0 4.035714285714285e-06 1.5 4.035714285714285e-06 1.5 4.036272321428571e-06 0.0 4.0530133928571426e-06 0.0 4.0535714285714285e-06 1.5 4.0535714285714285e-06 1.5 4.054129464285714e-06 0.0 4.070870535714286e-06 0.0 4.071428571428571e-06 1.5 4.071428571428571e-06 1.5 4.071986607142857e-06 0.0 4.088727678571428e-06 0.0 4.089285714285714e-06 1.5 4.089285714285714e-06 1.5 4.08984375e-06 0.0 4.106584821428571e-06 0.0 4.107142857142857e-06 1.5 4.107142857142857e-06 1.5 4.107700892857142e-06 0.0 4.124441964285714e-06 0.0 4.1249999999999995e-06 1.5 4.1249999999999995e-06 1.5 4.125558035714285e-06 0.0 4.142299107142857e-06 0.0 4.142857142857143e-06 1.5 4.142857142857143e-06 1.5 4.1434151785714285e-06 0.0 4.16015625e-06 0.0 4.160714285714286e-06 1.5 4.160714285714286e-06 1.5 4.161272321428571e-06 0.0 4.178013392857142e-06 0.0 4.178571428571428e-06 1.5 4.178571428571428e-06 1.5 4.179129464285714e-06 0.0 4.195870535714285e-06 0.0 4.196428571428571e-06 1.5 4.196428571428571e-06 1.5 4.196986607142857e-06 0.0 4.2137276785714286e-06 0.0 4.214285714285714e-06 1.5 4.214285714285714e-06 1.5 4.2148437499999995e-06 0.0 4.231584821428571e-06 0.0 4.232142857142857e-06 1.5 4.232142857142857e-06 1.5 4.232700892857143e-06 0.0 4.249441964285714e-06 0.0 4.25e-06 1.5 4.25e-06 1.5 4.250558035714285e-06 0.0 4.267299107142857e-06 0.0 4.267857142857142e-06 1.5 4.267857142857142e-06 1.5 4.268415178571428e-06 0.0 4.2851562499999996e-06 0.0 4.2857142857142855e-06 1.5 4.2857142857142855e-06 1.5 4.286272321428571e-06 0.0 4.303013392857143e-06 0.0 4.303571428571429e-06 1.5 4.303571428571429e-06 1.5 4.304129464285714e-06 0.0 4.320870535714285e-06 0.0 4.321428571428571e-06 1.5 4.321428571428571e-06 1.5 4.321986607142857e-06 0.0 4.338727678571428e-06 0.0 4.339285714285714e-06 1.5 4.339285714285714e-06 1.5 4.33984375e-06 0.0 4.356584821428571e-06 0.0 4.3571428571428564e-06 1.5 4.3571428571428564e-06 1.5 4.357700892857142e-06 0.0 4.374441964285714e-06 0.0 4.375e-06 1.5 4.375e-06 1.5 4.3755580357142855e-06 0.0 4.392299107142857e-06 0.0 4.392857142857143e-06 1.5 4.392857142857143e-06 1.5 4.393415178571428e-06 0.0 4.41015625e-06 0.0 4.410714285714285e-06 1.5 4.410714285714285e-06 1.5 4.411272321428571e-06 0.0 4.428013392857142e-06 0.0 4.428571428571428e-06 1.5 4.428571428571428e-06 1.5 4.429129464285714e-06 0.0 4.4458705357142855e-06 0.0 4.4464285714285715e-06 1.5 4.4464285714285715e-06 1.5 4.4469866071428565e-06 0.0 4.463727678571428e-06 0.0 4.464285714285714e-06 1.5 4.464285714285714e-06 1.5 4.46484375e-06 0.0 4.481584821428571e-06 0.0 4.482142857142857e-06 1.5 4.482142857142857e-06 1.5 4.482700892857143e-06 0.0 4.499441964285714e-06 0.0 4.499999999999999e-06 1.5 4.499999999999999e-06 1.5 4.500558035714285e-06 0.0 4.5172991071428565e-06 0.0 4.5178571428571424e-06 1.5 4.5178571428571424e-06 1.5 4.518415178571428e-06 0.0 4.53515625e-06 0.0 4.535714285714286e-06 1.5 4.535714285714286e-06 1.5 4.5362723214285715e-06 0.0 4.553013392857143e-06 0.0 4.553571428571428e-06 1.5 4.553571428571428e-06 1.5 4.554129464285714e-06 0.0 4.570870535714285e-06 0.0 4.571428571428571e-06 1.5 4.571428571428571e-06 1.5 4.571986607142857e-06 0.0 4.588727678571428e-06 0.0 4.589285714285714e-06 1.5 4.589285714285714e-06 1.5 4.589843749999999e-06 0.0 4.606584821428571e-06 0.0 4.607142857142857e-06 1.5 4.607142857142857e-06 1.5 4.6077008928571425e-06 0.0 4.624441964285714e-06 0.0 4.625e-06 1.5 4.625e-06 1.5 4.625558035714286e-06 0.0 4.642299107142857e-06 0.0 4.642857142857143e-06 1.5 4.642857142857143e-06 1.5 4.643415178571428e-06 0.0 4.659598214285714e-06 0.0 4.660156249999999e-06 1.5 4.661272321428571e-06 1.5 4.661830357142857e-06 0.0 4.677455357142857e-06 0.0 4.6780133928571425e-06 1.5 4.679129464285714e-06 1.5 4.679687499999999e-06 0.0 4.6953125e-06 0.0 4.695870535714286e-06 1.5 4.696986607142857e-06 1.5 4.6975446428571426e-06 0.0 4.713169642857142e-06 0.0 4.713727678571428e-06 1.5 4.71484375e-06 1.5 4.715401785714286e-06 0.0 4.731026785714285e-06 0.0 4.731584821428571e-06 1.5 4.732700892857142e-06 1.5 4.733258928571428e-06 0.0 4.7488839285714284e-06 0.0 4.749441964285714e-06 1.5 4.750558035714285e-06 1.5 4.751116071428571e-06 0.0 4.766741071428571e-06 0.0 4.767299107142857e-06 1.5 4.7684151785714285e-06 1.5 4.7689732142857136e-06 0.0 4.784598214285714e-06 0.0 4.78515625e-06 1.5 4.786272321428571e-06 1.5 4.786830357142857e-06 0.0 4.802455357142857e-06 0.0 4.803013392857142e-06 1.5 4.804129464285714e-06 1.5 4.8046875e-06 0.0 4.8203124999999994e-06 0.0 4.820870535714285e-06 1.5 4.821986607142857e-06 1.5 4.822544642857142e-06 0.0 4.838169642857143e-06 0.0 4.8387276785714285e-06 1.5 4.8398437499999995e-06 1.5 4.840401785714285e-06 0.0 4.856026785714286e-06 0.0 4.856584821428571e-06 1.5 4.857700892857143e-06 1.5 4.8582589285714286e-06 0.0 4.873883928571428e-06 0.0 4.874441964285714e-06 1.5 4.875558035714285e-06 1.5 4.876116071428571e-06 0.0 4.891741071428571e-06 0.0 4.892299107142857e-06 1.5 4.893415178571428e-06 1.5 4.893973214285714e-06 0.0 4.909598214285714e-06 0.0 4.9101562499999995e-06 1.5 4.911272321428571e-06 1.5 4.911830357142856e-06 0.0 4.927455357142857e-06 0.0 4.928013392857143e-06 1.5 4.929129464285714e-06 1.5 4.9296874999999995e-06 0.0 4.944754464285714e-06 0.0 4.9453125e-06 1.5 4.947544642857143e-06 1.5 4.948102678571429e-06 0.0 4.962611607142857e-06 0.0 4.963169642857142e-06 1.5 4.965401785714285e-06 1.5 4.965959821428571e-06 0.0 4.9804687499999995e-06 0.0 4.981026785714285e-06 1.5 4.983258928571428e-06 1.5 4.983816964285714e-06 0.0 4.998325892857143e-06 0.0 4.998883928571429e-06 1.5 5.001116071428571e-06 1.5 5.0016741071428564e-06 0.0 5.016183035714285e-06 0.0 5.016741071428571e-06 1.5 5.018973214285714e-06 1.5 5.01953125e-06 0.0 5.034040178571428e-06 0.0 5.034598214285714e-06 1.5 5.036830357142857e-06 1.5 5.037388392857143e-06 0.0 5.051897321428571e-06 0.0 5.052455357142856e-06 1.5 5.0546875e-06 1.5 5.055245535714285e-06 0.0 5.069754464285714e-06 0.0 5.0703125e-06 1.5 5.072544642857142e-06 1.5 5.073102678571428e-06 0.0 5.087611607142857e-06 0.0 5.088169642857143e-06 1.5 5.0904017857142855e-06 1.5 5.0909598214285714e-06 0.0 5.10546875e-06 0.0 5.106026785714285e-06 1.5 5.108258928571428e-06 1.5 5.108816964285714e-06 0.0 5.123325892857142e-06 0.0 5.123883928571428e-06 1.5 5.126116071428571e-06 1.5 5.126674107142857e-06 0.0 5.1411830357142855e-06 0.0 5.141741071428571e-06 1.5 5.143973214285714e-06 1.5 5.144531249999999e-06 0.0 5.158482142857143e-06 0.0 5.159040178571428e-06 1.5 5.1623883928571424e-06 1.5 5.162946428571428e-06 0.0 5.176339285714285e-06 0.0 5.176897321428571e-06 1.5 5.180245535714286e-06 1.5 5.180803571428571e-06 0.0 5.194196428571428e-06 0.0 5.194754464285714e-06 1.5 5.198102678571428e-06 1.5 5.198660714285714e-06 0.0 5.2120535714285714e-06 0.0 5.2126116071428565e-06 1.5 5.215959821428571e-06 1.5 5.216517857142857e-06 0.0 5.229910714285714e-06 0.0 5.23046875e-06 1.5 5.233816964285714e-06 1.5 5.234374999999999e-06 0.0 5.247767857142857e-06 0.0 5.248325892857143e-06 1.5 5.251674107142857e-06 1.5 5.2522321428571425e-06 0.0 5.265624999999999e-06 0.0 5.266183035714285e-06 1.5 5.26953125e-06 1.5 5.270089285714286e-06 0.0 5.283482142857142e-06 0.0 5.284040178571428e-06 1.5 5.287388392857142e-06 1.5 5.287946428571428e-06 0.0 5.301339285714286e-06 0.0 5.301897321428571e-06 1.5 5.305245535714285e-06 1.5 5.305803571428571e-06 0.0 5.319196428571428e-06 0.0 5.319754464285714e-06 1.5 5.3231026785714284e-06 1.5 5.3236607142857135e-06 0.0 5.337053571428571e-06 0.0 5.337611607142857e-06 1.5 5.340959821428571e-06 1.5 5.341517857142857e-06 0.0 5.354352678571428e-06 0.0 5.354910714285714e-06 1.5 5.359375e-06 1.5 5.359933035714286e-06 0.0 5.372209821428571e-06 0.0 5.3727678571428566e-06 1.5 5.377232142857142e-06 1.5 5.377790178571428e-06 0.0 5.390066964285714e-06 0.0 5.390625e-06 1.5 5.395089285714285e-06 1.5 5.395647321428571e-06 0.0 5.407924107142857e-06 0.0 5.408482142857142e-06 1.5 5.4129464285714285e-06 1.5 5.4135044642857136e-06 0.0 5.425781249999999e-06 0.0 5.426339285714285e-06 1.5 5.430803571428571e-06 1.5 5.431361607142857e-06 0.0 5.4436383928571425e-06 0.0 5.444196428571428e-06 1.5 5.448660714285714e-06 1.5 5.44921875e-06 0.0 5.461495535714286e-06 0.0 5.462053571428571e-06 1.5 5.466517857142857e-06 1.5 5.467075892857142e-06 0.0 5.479352678571428e-06 0.0 5.479910714285714e-06 1.5 5.4843749999999995e-06 1.5 5.484933035714285e-06 0.0 5.497209821428571e-06 0.0 5.497767857142857e-06 1.5 5.502232142857143e-06 1.5 5.5027901785714286e-06 0.0 5.5150669642857135e-06 0.0 5.515624999999999e-06 1.5 5.520089285714285e-06 1.5 5.520647321428571e-06 0.0 5.532366071428571e-06 0.0 5.532924107142857e-06 1.5 5.538504464285714e-06 1.5 5.5390625e-06 0.0 5.550223214285714e-06 0.0 5.55078125e-06 1.5 5.556361607142856e-06 1.5 5.556919642857142e-06 0.0 5.568080357142857e-06 0.0 5.568638392857142e-06 1.5 5.5742187499999995e-06 1.5 5.5747767857142855e-06 0.0 5.585937499999999e-06 0.0 5.586495535714285e-06 1.5 5.592075892857143e-06 1.5 5.592633928571428e-06 0.0 5.6037946428571426e-06 0.0 5.6043526785714285e-06 1.5 5.609933035714285e-06 1.5 5.610491071428571e-06 0.0 5.621651785714285e-06 0.0 5.622209821428571e-06 1.5 5.627790178571428e-06 1.5 5.628348214285714e-06 0.0 5.639508928571428e-06 0.0 5.640066964285714e-06 1.5 5.645647321428571e-06 1.5 5.6462053571428564e-06 0.0 5.657366071428571e-06 0.0 5.657924107142857e-06 1.5 5.663504464285714e-06 1.5 5.6640625e-06 0.0 5.6752232142857136e-06 0.0 5.6757812499999995e-06 1.5 5.681361607142857e-06 1.5 5.681919642857143e-06 0.0 5.693080357142857e-06 0.0 5.693638392857143e-06 1.5 5.699776785714285e-06 1.5 5.700334821428571e-06 0.0 5.710379464285714e-06 0.0 5.7109375e-06 1.5 5.717633928571428e-06 1.5 5.718191964285714e-06 0.0 5.728236607142856e-06 0.0 5.728794642857142e-06 1.5 5.735491071428571e-06 1.5 5.7360491071428565e-06 0.0 5.7460937499999995e-06 0.0 5.746651785714285e-06 1.5 5.753348214285714e-06 1.5 5.75390625e-06 0.0 5.763950892857143e-06 0.0 5.7645089285714286e-06 1.5 5.771205357142857e-06 1.5 5.771763392857143e-06 0.0 5.781808035714285e-06 0.0 5.782366071428571e-06 1.5 5.789062499999999e-06 1.5 5.789620535714285e-06 0.0 5.799665178571428e-06 0.0 5.800223214285714e-06 1.5 5.8069196428571424e-06 1.5 5.807477678571428e-06 0.0 5.817522321428571e-06 0.0 5.818080357142856e-06 1.5 5.824776785714286e-06 1.5 5.825334821428571e-06 0.0 5.835379464285714e-06 0.0 5.8359374999999996e-06 1.5 5.842633928571428e-06 1.5 5.843191964285714e-06 0.0 5.853236607142857e-06 0.0 5.853794642857143e-06 1.5 5.861049107142857e-06 1.5 5.861607142857142e-06 0.0 5.870535714285714e-06 0.0 5.87109375e-06 1.5 5.878906249999999e-06 1.5 5.879464285714285e-06 0.0 5.888392857142856e-06 0.0 5.888950892857142e-06 1.5 5.8967633928571425e-06 1.5 5.897321428571428e-06 0.0 5.9062499999999996e-06 0.0 5.9068080357142855e-06 1.5 5.914620535714286e-06 1.5 5.915178571428571e-06 0.0 5.924107142857143e-06 0.0 5.924665178571428e-06 1.5 5.932477678571428e-06 1.5 5.933035714285714e-06 0.0 5.941964285714285e-06 0.0 5.942522321428571e-06 1.5 5.950334821428571e-06 1.5 5.950892857142857e-06 0.0 5.959821428571428e-06 0.0 5.960379464285714e-06 1.5 5.9681919642857135e-06 1.5 5.968749999999999e-06 0.0 5.977678571428571e-06 0.0 5.9782366071428565e-06 1.5 5.986049107142857e-06 1.5 5.9866071428571426e-06 0.0 5.995535714285714e-06 0.0 5.99609375e-06 1.5 6.00390625e-06 1.5 6.004464285714285e-06 0.0 6.013392857142857e-06 0.0 6.013950892857143e-06 1.5 6.022321428571428e-06 1.5 6.022879464285714e-06 0.0 6.030691964285714e-06 0.0 6.031249999999999e-06 1.5 6.040178571428571e-06 1.5 6.040736607142856e-06 0.0 6.0485491071428565e-06 0.0 6.049107142857142e-06 1.5 6.0580357142857135e-06 1.5 6.0585937499999995e-06 0.0 6.06640625e-06 0.0 6.0669642857142856e-06 1.5 6.075892857142857e-06 1.5 6.076450892857143e-06 0.0 6.084263392857143e-06 0.0 6.084821428571428e-06 1.5 6.09375e-06 1.5 6.094308035714285e-06 0.0 6.102120535714285e-06 0.0 6.102678571428571e-06 1.5 6.111607142857142e-06 1.5 6.112165178571428e-06 0.0 6.119977678571428e-06 0.0 6.120535714285714e-06 1.5 6.129464285714285e-06 1.5 6.130022321428571e-06 0.0 6.137834821428571e-06 0.0 6.1383928571428565e-06 1.5 6.1473214285714286e-06 1.5 6.147879464285714e-06 0.0 6.155691964285714e-06 0.0 6.15625e-06 1.5 6.165178571428571e-06 1.5 6.165736607142857e-06 0.0 6.173549107142857e-06 0.0 6.174107142857142e-06 1.5 6.18359375e-06 1.5 6.184151785714285e-06 0.0 6.190848214285714e-06 0.0 6.191406249999999e-06 1.5 6.201450892857142e-06 1.5 6.202008928571428e-06 0.0 6.2087053571428566e-06 0.0 6.2092633928571425e-06 1.5 6.2193080357142854e-06 1.5 6.219866071428571e-06 0.0 6.2265625e-06 0.0 6.227120535714286e-06 1.5 6.237165178571428e-06 1.5 6.237723214285714e-06 0.0 6.244419642857142e-06 0.0 6.244977678571428e-06 1.5 6.255022321428571e-06 1.5 6.255580357142857e-06 0.0 6.262276785714285e-06 0.0 6.262834821428571e-06 1.5 6.272879464285714e-06 1.5 6.273437499999999e-06 0.0 6.280133928571428e-06 0.0 6.2806919642857135e-06 1.5 6.2907366071428564e-06 1.5 6.291294642857142e-06 0.0 6.297991071428571e-06 0.0 6.298549107142857e-06 1.5 6.30859375e-06 1.5 6.3091517857142855e-06 0.0 6.315848214285714e-06 0.0 6.31640625e-06 1.5 6.326450892857143e-06 1.5 6.327008928571428e-06 0.0 6.333705357142857e-06 0.0 6.334263392857142e-06 1.5 6.344866071428571e-06 1.5 6.345424107142857e-06 0.0 6.3510044642857135e-06 0.0 6.351562499999999e-06 1.5 6.362723214285714e-06 1.5 6.363281249999999e-06 0.0 6.368861607142857e-06 0.0 6.3694196428571426e-06 1.5 6.3805803571428565e-06 1.5 6.381138392857142e-06 0.0 6.38671875e-06 0.0 6.387276785714285e-06 1.5 6.3984375e-06 1.5 6.398995535714286e-06 0.0 6.404575892857142e-06 0.0 6.405133928571428e-06 1.5 6.416294642857142e-06 1.5 6.416852678571428e-06 0.0 6.422433035714285e-06 0.0 6.422991071428571e-06 1.5 6.434151785714285e-06 1.5 6.434709821428571e-06 0.0 6.4402901785714285e-06 0.0 6.4408482142857135e-06 1.5 6.452008928571428e-06 1.5 6.452566964285714e-06 0.0 6.458147321428571e-06 0.0 6.458705357142857e-06 1.5 6.469866071428571e-06 1.5 6.4704241071428566e-06 0.0 6.476004464285714e-06 0.0 6.4765625e-06 1.5 6.487723214285714e-06 1.5 6.48828125e-06 0.0 6.493861607142856e-06 0.0 6.494419642857142e-06 1.5 6.505580357142857e-06 1.5 6.506138392857142e-06 0.0 6.5111607142857136e-06 0.0 6.5117187499999995e-06 1.5 6.523995535714285e-06 1.5 6.524553571428571e-06 0.0 6.529017857142857e-06 0.0 6.529575892857143e-06 1.5 6.541852678571428e-06 1.5 6.5424107142857135e-06 0.0 6.546875e-06 0.0 6.547433035714285e-06 1.5 6.559709821428571e-06 1.5 6.560267857142857e-06 0.0 6.564732142857142e-06 0.0 6.565290178571428e-06 1.5 6.577566964285714e-06 1.5 6.578125e-06 0.0 6.582589285714285e-06 0.0 6.583147321428571e-06 1.5 6.595424107142857e-06 1.5 6.595982142857142e-06 0.0 6.600446428571428e-06 0.0 6.601004464285714e-06 1.5 6.613281249999999e-06 1.5 6.613839285714285e-06 0.0 6.618303571428571e-06 0.0 6.618861607142857e-06 1.5 6.6311383928571426e-06 1.5 6.6316964285714285e-06 0.0 6.636160714285714e-06 0.0 6.636718749999999e-06 1.5 6.648995535714285e-06 1.5 6.649553571428571e-06 0.0 6.654017857142856e-06 0.0 6.654575892857142e-06 1.5 6.666852678571428e-06 1.5 6.667410714285714e-06 0.0 6.6718749999999995e-06 0.0 6.6724330357142855e-06 1.5 6.684709821428571e-06 1.5 6.685267857142856e-06 0.0 6.689174107142857e-06 0.0 6.689732142857143e-06 1.5 6.7031249999999995e-06 1.5 6.703683035714285e-06 0.0 6.707031249999999e-06 0.0 6.707589285714285e-06 1.5 6.720982142857143e-06 1.5 6.721540178571428e-06 0.0 6.724888392857142e-06 0.0 6.725446428571428e-06 1.5 6.738839285714285e-06 1.5 6.739397321428571e-06 0.0 6.7427455357142855e-06 0.0 6.7433035714285705e-06 1.5 6.756696428571428e-06 1.5 6.757254464285714e-06 0.0 6.760602678571428e-06 0.0 6.761160714285714e-06 1.5 6.774553571428571e-06 1.5 6.775111607142856e-06 0.0 6.778459821428571e-06 0.0 6.779017857142857e-06 1.5 6.792410714285714e-06 1.5 6.7929687499999995e-06 0.0 6.796316964285714e-06 0.0 6.796874999999999e-06 1.5 6.810267857142857e-06 1.5 6.810825892857143e-06 0.0 6.8141741071428565e-06 0.0 6.814732142857142e-06 1.5 6.828124999999999e-06 1.5 6.828683035714285e-06 0.0 6.83203125e-06 0.0 6.8325892857142855e-06 1.5 6.845982142857142e-06 1.5 6.846540178571428e-06 0.0 6.849888392857142e-06 0.0 6.850446428571428e-06 1.5 6.8638392857142854e-06 1.5 6.864397321428571e-06 0.0 6.867745535714285e-06 0.0 6.868303571428571e-06 1.5 6.882254464285714e-06 1.5 6.8828125e-06 0.0 6.885044642857142e-06 0.0 6.885602678571428e-06 1.5 6.900111607142857e-06 1.5 6.900669642857143e-06 0.0 6.9029017857142855e-06 0.0 6.903459821428571e-06 1.5 6.917968749999999e-06 1.5 6.918526785714285e-06 0.0 6.920758928571428e-06 0.0 6.921316964285714e-06 1.5 6.935825892857142e-06 1.5 6.936383928571428e-06 0.0 6.938616071428571e-06 0.0 6.939174107142857e-06 1.5 6.9536830357142855e-06 1.5 6.9542410714285706e-06 0.0 6.956473214285713e-06 0.0 6.957031249999999e-06 1.5 6.971540178571428e-06 1.5 6.972098214285714e-06 0.0 6.9743303571428565e-06 0.0 6.9748883928571424e-06 1.5 6.989397321428571e-06 1.5 6.989955357142857e-06 0.0 6.9921875e-06 0.0 6.992745535714286e-06 1.5 7.007254464285714e-06 1.5 7.007812499999999e-06 0.0 7.010044642857142e-06 0.0 7.010602678571428e-06 1.5 7.0251116071428565e-06 1.5 7.025669642857142e-06 0.0 7.027901785714285e-06 0.0 7.028459821428571e-06 1.5 7.04296875e-06 1.5 7.043526785714286e-06 0.0 7.045758928571428e-06 0.0 7.0463169642857134e-06 1.5 7.060825892857142e-06 1.5 7.061383928571428e-06 0.0 7.063616071428571e-06 0.0 7.064174107142857e-06 1.5 7.078683035714285e-06 1.5 7.079241071428571e-06 0.0 7.081473214285714e-06 0.0 7.08203125e-06 1.5 7.096540178571428e-06 1.5 7.097098214285713e-06 0.0 7.099330357142857e-06 0.0 7.099888392857142e-06 1.5 7.1149553571428566e-06 1.5 7.1155133928571425e-06 0.0 7.1166294642857134e-06 0.0 7.117187499999999e-06 1.5 7.1328125e-06 1.5 7.133370535714285e-06 0.0 7.134486607142857e-06 0.0 7.1350446428571425e-06 1.5 7.150669642857142e-06 1.5 7.151227678571428e-06 0.0 7.15234375e-06 0.0 7.152901785714285e-06 1.5 7.168526785714285e-06 1.5 7.169084821428571e-06 0.0 7.170200892857142e-06 0.0 7.170758928571428e-06 1.5 7.186383928571428e-06 1.5 7.1869419642857135e-06 0.0 7.188058035714285e-06 0.0 7.188616071428571e-06 1.5 7.204241071428571e-06 1.5 7.204799107142857e-06 0.0 7.2059151785714284e-06 0.0 7.2064732142857135e-06 1.5 7.222098214285714e-06 1.5 7.22265625e-06 0.0 7.223772321428571e-06 0.0 7.224330357142857e-06 1.5 7.239955357142856e-06 1.5 7.240513392857142e-06 0.0 7.241629464285714e-06 0.0 7.2421875e-06 1.5 7.257812499999999e-06 1.5 7.258370535714285e-06 0.0 7.259486607142856e-06 0.0 7.260044642857142e-06 1.5 7.2756696428571426e-06 1.5 7.2762276785714285e-06 0.0 7.2773437499999994e-06 0.0 7.277901785714285e-06 1.5 7.293526785714285e-06 1.5 7.294084821428571e-06 0.0 7.295200892857143e-06 0.0 7.295758928571428e-06 1.5 7.311383928571428e-06 1.5 7.311941964285714e-06 0.0 7.313058035714285e-06 0.0 7.313616071428571e-06 1.5 7.329241071428571e-06 1.5 7.329799107142856e-06 0.0 7.330915178571428e-06 0.0 7.331473214285714e-06 1.5 7.3470982142857135e-06 1.5 7.3476562499999995e-06 0.0 7.348772321428571e-06 0.0 7.349330357142856e-06 1.5 7.364955357142857e-06 1.5 7.365513392857143e-06 0.0 7.366629464285714e-06 0.0 7.3671874999999995e-06 1.5 7.383370535714285e-06 1.5 7.383928571428571e-06 0.0 7.383928571428571e-06 0.0 7.384486607142857e-06 1.5 7.401227678571428e-06 1.5 7.401785714285714e-06 0.0 7.401785714285714e-06 0.0 7.402343749999999e-06 1.5 7.419084821428571e-06 1.5 7.419642857142856e-06 0.0 7.419642857142856e-06 0.0 7.420200892857142e-06 1.5 7.436941964285714e-06 1.5 7.4374999999999995e-06 0.0 7.4374999999999995e-06 0.0 7.4380580357142854e-06 1.5 7.454799107142857e-06 1.5 7.455357142857143e-06 0.0 7.455357142857143e-06 0.0 7.455915178571428e-06 1.5 7.472656249999999e-06 1.5 7.473214285714285e-06 0.0 7.473214285714285e-06 0.0 7.473772321428571e-06 1.5 7.490513392857142e-06 1.5 7.491071428571428e-06 0.0 7.491071428571428e-06 0.0 7.491629464285714e-06 1.5 7.5083705357142854e-06 1.5 7.5089285714285705e-06 0.0 7.5089285714285705e-06 0.0 7.509486607142856e-06 1.5 7.526227678571428e-06 1.5 7.526785714285714e-06 0.0 7.526785714285714e-06 0.0 7.52734375e-06 1.5 7.544084821428571e-06 1.5 7.544642857142857e-06 0.0 7.544642857142857e-06 0.0 7.545200892857142e-06 1.5 7.561941964285714e-06 1.5 7.562499999999999e-06 0.0 7.562499999999999e-06 0.0 7.563058035714285e-06 1.5 7.5797991071428564e-06 1.5 7.580357142857142e-06 0.0 7.580357142857142e-06 0.0 7.580915178571428e-06 1.5 7.59765625e-06 1.5 7.5982142857142855e-06 0.0 7.5982142857142855e-06 0.0 7.5987723214285706e-06 1.5 7.615513392857142e-06 1.5 7.616071428571428e-06 0.0 7.616071428571428e-06 0.0 7.616629464285714e-06 1.5 7.633370535714285e-06 1.5 7.63392857142857e-06 0.0 7.63392857142857e-06 0.0 7.634486607142857e-06 1.5 7.651227678571427e-06 1.5 7.651785714285714e-06 0.0 7.651785714285714e-06 0.0 7.65234375e-06 1.5 7.669084821428571e-06 1.5 7.669642857142856e-06 0.0 7.669642857142856e-06 0.0 7.670200892857142e-06 1.5 7.686941964285714e-06 1.5 7.687499999999999e-06 0.0 7.687499999999999e-06 0.0 7.688058035714286e-06 1.5 7.704799107142856e-06 1.5 7.705357142857143e-06 0.0 7.705357142857143e-06 0.0 7.705915178571428e-06 1.5 7.72265625e-06 1.5 7.723214285714285e-06 0.0 7.723214285714285e-06 0.0 7.72377232142857e-06 1.5 7.740513392857142e-06 1.5 7.741071428571427e-06 0.0 7.741071428571427e-06 0.0 7.741629464285714e-06 1.5 7.758370535714285e-06 1.5 7.758928571428571e-06 0.0 7.758928571428571e-06 0.0 7.759486607142857e-06 1.5 7.776227678571429e-06 1.5 7.776785714285714e-06 0.0 7.776785714285714e-06 0.0 7.777343749999999e-06 1.5 7.794084821428571e-06 1.5 7.794642857142856e-06 0.0 7.794642857142856e-06 0.0 7.795200892857143e-06 1.5 7.811941964285713e-06 1.5 7.8125e-06 0.0 7.8125e-06 0.0 7.813058035714285e-06 1.5 7.829799107142857e-06 1.5 7.830357142857142e-06 0.0 7.830357142857142e-06 0.0 7.830915178571428e-06 1.5 7.84765625e-06 1.5 7.848214285714285e-06 0.0 7.848214285714285e-06 0.0 7.848772321428572e-06 1.5 7.865513392857142e-06 1.5 7.866071428571429e-06 0.0 7.866071428571429e-06 0.0 7.866629464285714e-06 1.5 7.883370535714284e-06 1.5 7.883928571428571e-06 0.0 7.883928571428571e-06 0.0 7.884486607142856e-06 1.5 7.901227678571428e-06 1.5 7.901785714285713e-06 0.0 7.901785714285713e-06 0.0 7.90234375e-06 1.5 7.91908482142857e-06 1.5 7.919642857142856e-06 0.0 7.919642857142856e-06 0.0 7.920200892857143e-06 1.5 7.936941964285713e-06 1.5 7.9375e-06 0.0 7.9375e-06 0.0 7.938058035714285e-06 1.5 7.954799107142857e-06 1.5 7.955357142857142e-06 0.0 7.955357142857142e-06 0.0 7.955915178571427e-06 1.5 7.97265625e-06 1.5 7.973214285714284e-06 0.0 7.973214285714284e-06 0.0 7.973772321428571e-06 1.5 7.990513392857142e-06 1.5 7.991071428571428e-06 0.0 7.991071428571428e-06 0.0 7.991629464285714e-06 1.5 8.008370535714286e-06 1.5 8.00892857142857e-06 0.0 8.00892857142857e-06 0.0 8.009486607142856e-06 1.5 8.026227678571428e-06 1.5 8.026785714285713e-06 0.0 8.026785714285713e-06 0.0 8.02734375e-06 1.5 8.04408482142857e-06 1.5 8.044642857142857e-06 0.0 8.044642857142857e-06 0.0 8.045200892857142e-06 1.5 8.061941964285714e-06 1.5 8.0625e-06 0.0 8.0625e-06 0.0 8.063058035714285e-06 1.5 8.079799107142857e-06 1.5 8.080357142857142e-06 0.0 8.080357142857142e-06 0.0 8.080915178571429e-06 1.5 8.097656249999999e-06 1.5 8.098214285714286e-06 0.0 8.098214285714286e-06 0.0 8.098772321428571e-06 1.5 8.115513392857143e-06 1.5 8.116071428571428e-06 0.0 8.116071428571428e-06 0.0 8.116629464285713e-06 1.5 8.133370535714285e-06 1.5 8.13392857142857e-06 0.0 8.13392857142857e-06 0.0 8.134486607142857e-06 1.5 8.151227678571428e-06 1.5 8.151785714285714e-06 0.0 8.151785714285714e-06 0.0 8.15234375e-06 1.5 8.16908482142857e-06 1.5 8.169642857142857e-06 0.0 8.169642857142857e-06 0.0 8.170200892857142e-06 1.5 8.186941964285714e-06 1.5 8.187499999999999e-06 0.0 8.187499999999999e-06 0.0 8.188058035714286e-06 1.5 8.204799107142856e-06 1.5 8.205357142857141e-06 0.0 8.205357142857141e-06 0.0 8.205915178571428e-06 1.5 8.222656249999999e-06 1.5 8.223214285714285e-06 0.0 8.223214285714285e-06 0.0 8.22377232142857e-06 1.5 8.240513392857143e-06 1.5 8.241071428571428e-06 0.0 8.241071428571428e-06 0.0 8.241629464285715e-06 1.5 8.258370535714285e-06 1.5 8.25892857142857e-06 0.0 8.25892857142857e-06 0.0 8.259486607142857e-06 1.5 8.276227678571427e-06 1.5 8.276785714285714e-06 0.0 8.276785714285714e-06 0.0 8.27734375e-06 1.5 8.294084821428571e-06 1.5 8.294642857142856e-06 0.0 8.294642857142856e-06 0.0 8.295200892857142e-06 1.5 8.311941964285714e-06 1.5 8.312499999999999e-06 0.0 8.312499999999999e-06 0.0 8.313058035714286e-06 1.5 8.329799107142856e-06 1.5 8.330357142857143e-06 0.0 8.330357142857143e-06 0.0 8.330915178571428e-06 1.5 8.34765625e-06 1.5 8.348214285714285e-06 0.0 8.348214285714285e-06 0.0 8.34877232142857e-06 1.5 8.365513392857142e-06 1.5 8.366071428571427e-06 0.0 8.366071428571427e-06 0.0 8.366629464285714e-06 1.5 8.383370535714285e-06 1.5 8.383928571428571e-06 0.0 8.383928571428571e-06 0.0 8.384486607142857e-06 1.5 8.401227678571429e-06 1.5 8.401785714285714e-06 0.0 8.401785714285714e-06 0.0 8.402343749999999e-06 1.5 8.419084821428571e-06 1.5 8.419642857142856e-06 0.0 8.419642857142856e-06 0.0 8.420200892857143e-06 1.5 8.436941964285713e-06 1.5 8.4375e-06 0.0 8.4375e-06 0.0 8.438058035714285e-06 1.5 8.454799107142857e-06 1.5 8.455357142857142e-06 0.0 8.455357142857142e-06 0.0 8.455915178571427e-06 1.5 8.47265625e-06 1.5 8.473214285714285e-06 0.0 8.473214285714285e-06 0.0 8.473772321428572e-06 1.5 8.490513392857142e-06 1.5 8.491071428571429e-06 0.0 8.491071428571429e-06 0.0 8.491629464285714e-06 1.5 8.508370535714284e-06 1.5 8.508928571428571e-06 0.0 8.508928571428571e-06 0.0 8.509486607142856e-06 1.5 8.526227678571428e-06 1.5 8.526785714285713e-06 0.0 8.526785714285713e-06 0.0 8.52734375e-06 1.5 8.54408482142857e-06 1.5 8.544642857142856e-06 0.0 8.544642857142856e-06 0.0 8.545200892857142e-06 1.5 8.561941964285713e-06 1.5 8.5625e-06 0.0 8.5625e-06 0.0 8.563058035714285e-06 1.5 8.579799107142857e-06 1.5 8.580357142857142e-06 0.0 8.580357142857142e-06 0.0 8.580915178571427e-06 1.5 8.59765625e-06 1.5 8.598214285714284e-06 0.0 8.598214285714284e-06 0.0 8.598772321428571e-06 1.5 8.615513392857142e-06 1.5 8.616071428571428e-06 0.0 8.616071428571428e-06 0.0 8.616629464285713e-06 1.5 8.633370535714286e-06 1.5 8.63392857142857e-06 0.0 8.63392857142857e-06 0.0 8.634486607142856e-06 1.5 8.651227678571428e-06 1.5 8.651785714285713e-06 0.0 8.651785714285713e-06 0.0 8.65234375e-06 1.5 8.66908482142857e-06 1.5 8.669642857142857e-06 0.0 8.669642857142857e-06 0.0 8.670200892857142e-06 1.5 8.686383928571428e-06 1.5 8.686941964285714e-06 0.0 8.688058035714284e-06 0.0 8.688616071428571e-06 1.5 8.704241071428572e-06 1.5 8.704799107142857e-06 0.0 8.705915178571428e-06 0.0 8.706473214285714e-06 1.5 8.722098214285714e-06 1.5 8.722656249999999e-06 0.0 8.72377232142857e-06 0.0 8.724330357142856e-06 1.5 8.739955357142856e-06 1.5 8.740513392857143e-06 0.0 8.741629464285713e-06 0.0 8.7421875e-06 1.5 8.757812499999999e-06 1.5 8.758370535714285e-06 0.0 8.759486607142857e-06 0.0 8.760044642857142e-06 1.5 8.775669642857143e-06 1.5 8.776227678571428e-06 0.0 8.77734375e-06 0.0 8.777901785714285e-06 1.5 8.793526785714285e-06 1.5 8.79408482142857e-06 0.0 8.795200892857142e-06 0.0 8.795758928571429e-06 1.5 8.811383928571427e-06 1.5 8.811941964285714e-06 0.0 8.813058035714286e-06 0.0 8.813616071428571e-06 1.5 8.829241071428571e-06 1.5 8.829799107142856e-06 0.0 8.830915178571428e-06 0.0 8.831473214285713e-06 1.5 8.847098214285714e-06 1.5 8.847656249999999e-06 0.0 8.84877232142857e-06 0.0 8.849330357142857e-06 1.5 8.864955357142856e-06 1.5 8.865513392857143e-06 0.0 8.866629464285714e-06 0.0 8.8671875e-06 1.5 8.8828125e-06 1.5 8.883370535714285e-06 0.0 8.884486607142857e-06 0.0 8.885044642857142e-06 1.5 8.900669642857142e-06 1.5 8.901227678571427e-06 0.0 8.902343749999999e-06 0.0 8.902901785714286e-06 1.5 8.918526785714285e-06 1.5 8.919084821428571e-06 0.0 8.920200892857141e-06 0.0 8.920758928571428e-06 1.5 8.936383928571429e-06 1.5 8.936941964285714e-06 0.0 8.938058035714285e-06 0.0 8.93861607142857e-06 1.5 8.953683035714286e-06 1.5 8.954241071428571e-06 0.0 8.956473214285713e-06 0.0 8.95703125e-06 1.5 8.971540178571428e-06 1.5 8.972098214285713e-06 0.0 8.974330357142857e-06 0.0 8.974888392857142e-06 1.5 8.98939732142857e-06 1.5 8.989955357142857e-06 0.0 8.9921875e-06 0.0 8.992745535714284e-06 1.5 9.007254464285713e-06 1.5 9.0078125e-06 0.0 9.010044642857142e-06 0.0 9.010602678571428e-06 1.5 9.025111607142857e-06 1.5 9.025669642857142e-06 0.0 9.027901785714286e-06 0.0 9.02845982142857e-06 1.5 9.04296875e-06 1.5 9.043526785714286e-06 0.0 9.045758928571428e-06 0.0 9.046316964285713e-06 1.5 9.060825892857141e-06 1.5 9.061383928571428e-06 0.0 9.06361607142857e-06 0.0 9.064174107142857e-06 1.5 9.078683035714285e-06 1.5 9.07924107142857e-06 0.0 9.081473214285714e-06 0.0 9.08203125e-06 1.5 9.096540178571428e-06 1.5 9.097098214285713e-06 0.0 9.099330357142857e-06 0.0 9.099888392857142e-06 1.5 9.11439732142857e-06 1.5 9.114955357142857e-06 0.0 9.117187499999999e-06 0.0 9.117745535714286e-06 1.5 9.132254464285714e-06 1.5 9.1328125e-06 0.0 9.135044642857143e-06 0.0 9.135602678571428e-06 1.5 9.150111607142856e-06 1.5 9.150669642857142e-06 0.0 9.152901785714285e-06 0.0 9.15345982142857e-06 1.5 9.167968749999999e-06 1.5 9.168526785714286e-06 0.0 9.171316964285714e-06 0.0 9.171875e-06 1.5 9.185267857142856e-06 1.5 9.185825892857143e-06 0.0 9.189174107142857e-06 0.0 9.189732142857142e-06 1.5 9.203125e-06 1.5 9.203683035714285e-06 0.0 9.207031249999999e-06 0.0 9.207589285714286e-06 1.5 9.220982142857142e-06 1.5 9.221540178571427e-06 0.0 9.224888392857143e-06 0.0 9.225446428571428e-06 1.5 9.238839285714285e-06 1.5 9.239397321428571e-06 0.0 9.242745535714285e-06 0.0 9.24330357142857e-06 1.5 9.256696428571429e-06 1.5 9.257254464285714e-06 0.0 9.260602678571428e-06 0.0 9.261160714285714e-06 1.5 9.274553571428571e-06 1.5 9.275111607142856e-06 0.0 9.278459821428572e-06 0.0 9.279017857142857e-06 1.5 9.292410714285713e-06 1.5 9.29296875e-06 0.0 9.296316964285714e-06 0.0 9.296874999999999e-06 1.5 9.310267857142856e-06 1.5 9.310825892857142e-06 0.0 9.314174107142856e-06 0.0 9.314732142857143e-06 1.5 9.328125e-06 1.5 9.328683035714285e-06 0.0 9.332031249999999e-06 0.0 9.332589285714285e-06 1.5 9.345982142857142e-06 1.5 9.346540178571427e-06 0.0 9.349888392857143e-06 0.0 9.350446428571428e-06 1.5 9.36328125e-06 1.5 9.363839285714284e-06 0.0 9.36830357142857e-06 0.0 9.368861607142857e-06 1.5 9.381138392857142e-06 1.5 9.381696428571428e-06 0.0 9.386160714285714e-06 0.0 9.386718749999999e-06 1.5 9.398995535714286e-06 1.5 9.39955357142857e-06 0.0 9.404017857142856e-06 0.0 9.404575892857141e-06 1.5 9.416852678571428e-06 1.5 9.417410714285713e-06 0.0 9.421874999999999e-06 0.0 9.422433035714285e-06 1.5 9.43470982142857e-06 1.5 9.435267857142857e-06 0.0 9.439732142857143e-06 0.0 9.440290178571428e-06 1.5 9.452566964285714e-06 1.5 9.453125e-06 0.0 9.457589285714285e-06 0.0 9.45814732142857e-06 1.5 9.470424107142857e-06 1.5 9.470982142857142e-06 0.0 9.475446428571427e-06 0.0 9.476004464285714e-06 1.5 9.488281249999999e-06 1.5 9.488839285714286e-06 0.0 9.493303571428571e-06 0.0 9.493861607142856e-06 1.5 9.506138392857143e-06 1.5 9.506696428571428e-06 0.0 9.511160714285714e-06 0.0 9.511718749999999e-06 1.5 9.523995535714285e-06 1.5 9.52455357142857e-06 0.0 9.529017857142856e-06 0.0 9.529575892857143e-06 1.5 9.541294642857143e-06 1.5 9.541852678571428e-06 0.0 9.547433035714285e-06 0.0 9.54799107142857e-06 1.5 9.559151785714285e-06 1.5 9.55970982142857e-06 0.0 9.565290178571427e-06 0.0 9.565848214285714e-06 1.5 9.577008928571427e-06 1.5 9.577566964285714e-06 0.0 9.583147321428571e-06 0.0 9.583705357142856e-06 1.5 9.594866071428571e-06 1.5 9.595424107142856e-06 0.0 9.601004464285714e-06 0.0 9.601562499999999e-06 1.5 9.612723214285714e-06 1.5 9.613281249999999e-06 0.0 9.618861607142856e-06 0.0 9.619419642857143e-06 1.5 9.630580357142856e-06 1.5 9.631138392857143e-06 0.0 9.63671875e-06 0.0 9.637276785714285e-06 1.5 9.6484375e-06 1.5 9.648995535714285e-06 0.0 9.654575892857142e-06 0.0 9.655133928571427e-06 1.5 9.666294642857142e-06 1.5 9.666852678571427e-06 0.0 9.672433035714285e-06 0.0 9.672991071428571e-06 1.5 9.684151785714285e-06 1.5 9.684709821428571e-06 0.0 9.690290178571429e-06 0.0 9.690848214285714e-06 1.5 9.702008928571429e-06 1.5 9.702566964285714e-06 0.0 9.708147321428571e-06 0.0 9.708705357142856e-06 1.5 9.719308035714286e-06 1.5 9.719866071428571e-06 0.0 9.7265625e-06 0.0 9.727120535714285e-06 1.5 9.737165178571428e-06 1.5 9.737723214285713e-06 0.0 9.744419642857142e-06 0.0 9.744977678571427e-06 1.5 9.75502232142857e-06 1.5 9.755580357142857e-06 0.0 9.762276785714285e-06 0.0 9.762834821428572e-06 1.5 9.772879464285713e-06 1.5 9.7734375e-06 0.0 9.780133928571427e-06 0.0 9.780691964285714e-06 1.5 9.790736607142857e-06 1.5 9.791294642857142e-06 0.0 9.797991071428571e-06 0.0 9.798549107142856e-06 1.5 9.808593749999999e-06 1.5 9.809151785714284e-06 0.0 9.815848214285713e-06 0.0 9.816406249999998e-06 1.5 9.826450892857141e-06 1.5 9.827008928571428e-06 0.0 9.833705357142856e-06 0.0 9.834263392857142e-06 1.5 9.844308035714285e-06 1.5 9.84486607142857e-06 0.0 9.8515625e-06 0.0 9.852120535714285e-06 1.5 9.862165178571428e-06 1.5 9.862723214285713e-06 0.0 9.869419642857142e-06 0.0 9.869977678571427e-06 1.5 9.879464285714285e-06 1.5 9.88002232142857e-06 0.0 9.887834821428571e-06 0.0 9.888392857142856e-06 1.5 9.897321428571427e-06 1.5 9.897879464285714e-06 0.0 9.905691964285713e-06 0.0 9.906249999999999e-06 1.5 9.915178571428571e-06 1.5 9.915736607142856e-06 0.0 9.923549107142856e-06 0.0 9.924107142857143e-06 1.5 9.933035714285714e-06 1.5 9.933593749999999e-06 0.0 9.94140625e-06 0.0 9.941964285714285e-06 1.5 9.950892857142856e-06 1.5 9.951450892857143e-06 0.0 9.959263392857142e-06 0.0 9.959821428571427e-06 1.5 9.96875e-06 1.5 9.969308035714285e-06 0.0 9.977120535714284e-06 0.0 9.977678571428571e-06 1.5 9.986607142857142e-06 1.5 9.987165178571427e-06 0.0 9.994977678571428e-06 0.0 9.995535714285714e-06 1.5 1.0004464285714285e-05 1.5 1.0005022321428571e-05 0.0 1.001283482142857e-05 0.0 1.0013392857142856e-05 1.5 1.0022321428571427e-05 1.5 1.0022879464285714e-05 0.0 1.0030691964285713e-05 0.0 1.003125e-05 1.5 1.0039620535714284e-05 1.5 1.0040178571428571e-05 0.0 1.0049107142857142e-05 0.0 1.0049665178571427e-05 1.5 1.0057477678571428e-05 1.5 1.0058035714285713e-05 0.0 1.0066964285714285e-05 0.0 1.0067522321428571e-05 1.5 1.007533482142857e-05 1.5 1.0075892857142856e-05 0.0 1.0084821428571429e-05 0.0 1.0085379464285714e-05 1.5 1.0093191964285713e-05 1.5 1.009375e-05 0.0 1.0102678571428571e-05 0.0 1.0103236607142856e-05 1.5 1.0111049107142857e-05 1.5 1.0111607142857142e-05 0.0 1.0120535714285713e-05 0.0 1.012109375e-05 1.5 1.012890625e-05 1.5 1.0129464285714284e-05 0.0 1.0138392857142857e-05 0.0 1.0138950892857142e-05 1.5 1.0146763392857142e-05 1.5 1.0147321428571428e-05 0.0 1.015625e-05 0.0 1.0156808035714285e-05 1.5 1.0164620535714286e-05 1.5 1.016517857142857e-05 0.0 1.0174107142857142e-05 0.0 1.0174665178571429e-05 1.5 1.0182477678571428e-05 1.5 1.0183035714285713e-05 0.0 1.0192522321428571e-05 0.0 1.0193080357142856e-05 1.5 1.0199776785714285e-05 1.5 1.020033482142857e-05 0.0 1.0210379464285713e-05 0.0 1.02109375e-05 1.5 1.0217633928571428e-05 1.5 1.0218191964285714e-05 0.0 1.0228236607142856e-05 0.0 1.0228794642857142e-05 1.5 1.023549107142857e-05 1.5 1.0236049107142857e-05 0.0 1.024609375e-05 0.0 1.0246651785714285e-05 1.5 1.0253348214285714e-05 1.5 1.0253906249999999e-05 0.0 1.0263950892857142e-05 0.0 1.0264508928571429e-05 1.5 1.0271205357142856e-05 1.5 1.0271763392857143e-05 0.0 1.0281808035714284e-05 0.0 1.0282366071428571e-05 1.5 1.0289062499999999e-05 1.5 1.0289620535714285e-05 0.0 1.0299665178571428e-05 0.0 1.0300223214285713e-05 1.5 1.0306919642857143e-05 1.5 1.0307477678571428e-05 0.0 1.031752232142857e-05 0.0 1.0318080357142856e-05 1.5 1.0324776785714285e-05 1.5 1.032533482142857e-05 0.0 1.0335379464285713e-05 0.0 1.03359375e-05 1.5 1.0342633928571427e-05 1.5 1.0343191964285714e-05 0.0 1.0353236607142857e-05 0.0 1.0353794642857142e-05 1.5 1.0359933035714284e-05 1.5 1.0360491071428571e-05 0.0 1.0371651785714284e-05 0.0 1.0372209821428571e-05 1.5 1.0377790178571428e-05 1.5 1.0378348214285714e-05 0.0 1.0389508928571428e-05 0.0 1.0390066964285713e-05 1.5 1.039564732142857e-05 1.5 1.0396205357142856e-05 0.0 1.040736607142857e-05 0.0 1.0407924107142856e-05 1.5 1.0413504464285713e-05 1.5 1.04140625e-05 0.0 1.0425223214285713e-05 0.0 1.042578125e-05 1.5 1.0431361607142857e-05 1.5 1.0431919642857142e-05 0.0 1.0443080357142857e-05 0.0 1.0443638392857142e-05 1.5 1.044921875e-05 1.5 1.0449776785714285e-05 0.0 1.04609375e-05 0.0 1.0461495535714284e-05 1.5 1.0467075892857142e-05 1.5 1.0467633928571429e-05 0.0 1.0478794642857142e-05 0.0 1.0479352678571428e-05 1.5 1.0484933035714286e-05 1.5 1.0485491071428571e-05 0.0 1.0496651785714286e-05 0.0 1.049720982142857e-05 1.5 1.0502790178571428e-05 1.5 1.0503348214285713e-05 0.0 1.0514508928571428e-05 0.0 1.0515066964285713e-05 1.5 1.052064732142857e-05 1.5 1.0521205357142857e-05 0.0 1.0532924107142857e-05 0.0 1.0533482142857142e-05 1.5 1.0537946428571428e-05 1.5 1.0538504464285713e-05 0.0 1.055078125e-05 0.0 1.0551339285714284e-05 1.5 1.055580357142857e-05 1.5 1.0556361607142857e-05 0.0 1.0568638392857142e-05 0.0 1.0569196428571428e-05 1.5 1.0573660714285714e-05 1.5 1.0574218749999999e-05 0.0 1.0586495535714286e-05 0.0 1.058705357142857e-05 1.5 1.0591517857142856e-05 1.5 1.0592075892857141e-05 0.0 1.0604352678571428e-05 0.0 1.0604910714285713e-05 1.5 1.0609374999999999e-05 1.5 1.0609933035714285e-05 0.0 1.062220982142857e-05 0.0 1.0622767857142857e-05 1.5 1.0627232142857143e-05 1.5 1.0627790178571428e-05 0.0 1.0640066964285713e-05 0.0 1.0640625e-05 1.5 1.0645089285714285e-05 1.5 1.064564732142857e-05 0.0 1.0657924107142857e-05 0.0 1.0658482142857142e-05 1.5 1.0662946428571427e-05 1.5 1.0663504464285714e-05 0.0 1.0675781249999999e-05 0.0 1.0676339285714286e-05 1.5 1.0680803571428571e-05 1.5 1.0681361607142856e-05 0.0 1.0693638392857141e-05 0.0 1.0694196428571428e-05 1.5 1.0698660714285714e-05 1.5 1.0699218749999999e-05 0.0 1.071205357142857e-05 0.0 1.0712611607142857e-05 1.5 1.0715959821428571e-05 1.5 1.0716517857142856e-05 0.0 1.0729910714285713e-05 0.0 1.073046875e-05 1.5 1.0733816964285713e-05 1.5 1.0734375e-05 0.0 1.0747767857142857e-05 0.0 1.0748325892857142e-05 1.5 1.0751674107142856e-05 1.5 1.0752232142857142e-05 0.0 1.0765624999999999e-05 0.0 1.0766183035714284e-05 1.5 1.076953125e-05 1.5 1.0770089285714285e-05 0.0 1.0783482142857141e-05 0.0 1.0784040178571428e-05 1.5 1.0787388392857142e-05 1.5 1.0787946428571427e-05 0.0 1.0801339285714285e-05 0.0 1.080189732142857e-05 1.5 1.0805245535714284e-05 1.5 1.0805803571428571e-05 0.0 1.0819196428571428e-05 0.0 1.0819754464285713e-05 1.5 1.0823102678571428e-05 1.5 1.0823660714285713e-05 0.0 1.083705357142857e-05 0.0 1.0837611607142857e-05 1.5 1.084095982142857e-05 1.5 1.0841517857142856e-05 0.0 1.0854910714285714e-05 0.0 1.085546875e-05 1.5 1.0858816964285713e-05 1.5 1.0859375e-05 0.0 1.0872767857142856e-05 0.0 1.0873325892857141e-05 1.5 1.0876674107142857e-05 1.5 1.0877232142857142e-05 0.0 1.0890624999999999e-05 0.0 1.0891183035714286e-05 1.5 1.0893973214285714e-05 1.5 1.089453125e-05 0.0 1.0909040178571428e-05 0.0 1.0909598214285713e-05 1.5 1.0911830357142857e-05 1.5 1.0912388392857142e-05 0.0 1.092689732142857e-05 0.0 1.0927455357142857e-05 1.5 1.0929687499999999e-05 1.5 1.0930245535714286e-05 0.0 1.0944754464285714e-05 0.0 1.09453125e-05 1.5 1.0947544642857143e-05 1.5 1.0948102678571428e-05 0.0 1.0962611607142856e-05 0.0 1.0963169642857142e-05 1.5 1.0965401785714285e-05 1.5 1.096595982142857e-05 0.0 1.0980468749999999e-05 0.0 1.0981026785714286e-05 1.5 1.0983258928571428e-05 1.5 1.0983816964285714e-05 0.0 1.0998325892857143e-05 0.0 1.0998883928571428e-05 1.5 1.100111607142857e-05 1.5 1.1001674107142857e-05 0.0 1.1016183035714285e-05 0.0 1.101674107142857e-05 1.5 1.1018973214285714e-05 1.5 1.1019531249999999e-05 0.0 1.1034040178571427e-05 0.0 1.1034598214285714e-05 1.5 1.1036830357142856e-05 1.5 1.1037388392857141e-05 0.0 1.105189732142857e-05 0.0 1.1052455357142857e-05 1.5 1.1054687499999999e-05 1.5 1.1055245535714285e-05 0.0 1.1069754464285714e-05 0.0 1.1070312499999999e-05 1.5 1.1072544642857143e-05 1.5 1.1073102678571428e-05 0.0 1.1087611607142856e-05 0.0 1.1088169642857143e-05 1.5 1.1090401785714285e-05 1.5 1.109095982142857e-05 0.0 1.1105468749999998e-05 0.0 1.1106026785714285e-05 1.5 1.1108258928571427e-05 1.5 1.1108816964285714e-05 0.0 1.1123883928571428e-05 0.0 1.1124441964285714e-05 1.5 1.1125558035714284e-05 1.5 1.1126116071428571e-05 0.0 1.114174107142857e-05 0.0 1.1142299107142857e-05 1.5 1.1143415178571428e-05 1.5 1.1143973214285714e-05 0.0 1.1159598214285714e-05 0.0 1.1160156249999999e-05 1.5 1.116127232142857e-05 1.5 1.1161830357142856e-05 0.0 1.1177455357142856e-05 0.0 1.1178013392857141e-05 1.5 1.1179129464285713e-05 1.5 1.11796875e-05 0.0 1.1195312499999999e-05 0.0 1.1195870535714285e-05 1.5 1.1196986607142857e-05 1.5 1.1197544642857142e-05 0.0 1.1213169642857143e-05 0.0 1.1213727678571428e-05 1.5 1.121484375e-05 1.5 1.1215401785714284e-05 0.0 1.1231026785714285e-05 0.0 1.123158482142857e-05 1.5 1.1232700892857142e-05 1.5 1.1233258928571429e-05 0.0 1.1248883928571427e-05 0.0 1.1249441964285714e-05 1.5 1.1250558035714284e-05 1.5 1.125111607142857e-05 0.0 1.1266741071428571e-05 0.0 1.1267299107142856e-05 1.5 1.1268415178571428e-05 1.5 1.1268973214285713e-05 0.0 1.1284598214285714e-05 0.0 1.1285156249999999e-05 1.5 1.128627232142857e-05 1.5 1.1286830357142857e-05 0.0 1.1302455357142856e-05 0.0 1.1303013392857143e-05 1.5 1.1304129464285713e-05 1.5 1.13046875e-05 0.0 1.13203125e-05 0.0 1.1320870535714285e-05 1.5 1.1321986607142857e-05 1.5 1.1322544642857142e-05 0.0 1.1338169642857142e-05 0.0 1.1338727678571427e-05 1.5 1.1339843749999999e-05 1.5 1.1340401785714284e-05 0.0 1.1356026785714285e-05 0.0 1.1356584821428571e-05 1.5 1.1357700892857141e-05 1.5 1.1358258928571428e-05 0.0 1.1373883928571429e-05 0.0 1.1374441964285714e-05 1.5 1.1375558035714285e-05 1.5 1.137611607142857e-05 0.0 1.1391741071428571e-05 0.0 1.1392299107142856e-05 1.5 1.1392857142857143e-05 1.5 1.1393415178571428e-05 0.0 1.141015625e-05 0.0 1.1410714285714285e-05 1.5 1.1410714285714285e-05 1.5 1.141127232142857e-05 0.0 1.1428013392857142e-05 0.0 1.1428571428571427e-05 1.5 1.1428571428571427e-05 1.5 1.1429129464285714e-05 0.0 1.1445870535714285e-05 0.0 1.1446428571428571e-05 1.5 1.1446428571428571e-05 1.5 1.1446986607142856e-05 0.0 1.1463727678571427e-05 0.0 1.1464285714285714e-05 1.5 1.1464285714285714e-05 1.5 1.1464843749999999e-05 0.0 1.1481584821428571e-05 0.0 1.1482142857142856e-05 1.5 1.1482142857142856e-05 1.5 1.1482700892857143e-05 0.0 1.1499441964285713e-05 0.0 1.15e-05 1.5 1.15e-05 1.5 1.1500558035714285e-05 0.0 1.1517299107142856e-05 0.0 1.1517857142857142e-05 1.5 1.1517857142857142e-05 1.5 1.1518415178571427e-05 0.0 1.153515625e-05 0.0 1.1535714285714285e-05 1.5 1.1535714285714285e-05 1.5 1.1536272321428571e-05 0.0 1.1553013392857142e-05 0.0 1.1553571428571427e-05 1.5 1.1553571428571427e-05 1.5 1.1554129464285714e-05 0.0 1.1570870535714284e-05 0.0 1.1571428571428571e-05 1.5 1.1571428571428571e-05 1.5 1.1571986607142856e-05 0.0 1.1588727678571428e-05 0.0 1.1589285714285713e-05 1.5 1.1589285714285713e-05 1.5 1.1589843749999998e-05 0.0 1.160658482142857e-05 0.0 1.1607142857142856e-05 1.5 1.1607142857142856e-05 1.5 1.1607700892857142e-05 0.0 1.1624441964285713e-05 0.0 1.1625e-05 1.5 1.1625e-05 1.5 1.1625558035714285e-05 0.0 1.1642299107142857e-05 0.0 1.1642857142857142e-05 1.5 1.1642857142857142e-05 1.5 1.1643415178571427e-05 0.0 1.166015625e-05 0.0 1.1660714285714284e-05 1.5 1.1660714285714284e-05 1.5 1.1661272321428571e-05 0.0 1.1678013392857142e-05 0.0 1.1678571428571428e-05 1.5 1.1678571428571428e-05 1.5 1.1679129464285713e-05 0.0 1.1695870535714286e-05 0.0 1.169642857142857e-05 1.5 1.169642857142857e-05 1.5 1.1696986607142856e-05 0.0 1.1713727678571428e-05 0.0 1.1714285714285713e-05 1.5 1.1714285714285713e-05 1.5 1.171484375e-05 0.0 1.173158482142857e-05 0.0 1.1732142857142857e-05 1.5 1.1732142857142857e-05 1.5 1.1732700892857142e-05 0.0 1.1749441964285714e-05 0.0 1.175e-05 1.5 1.175e-05 1.5 1.1750558035714284e-05 0.0 1.1767299107142857e-05 0.0 1.1767857142857142e-05 1.5 1.1767857142857142e-05 1.5 1.1768415178571428e-05 0.0 1.1785156249999999e-05 0.0 1.1785714285714286e-05 1.5 1.1785714285714286e-05 1.5 1.178627232142857e-05 0.0 1.1803013392857141e-05 0.0 1.1803571428571428e-05 1.5 1.1803571428571428e-05 1.5 1.1804129464285713e-05 0.0 1.1820870535714285e-05 0.0 1.182142857142857e-05 1.5 1.182142857142857e-05 1.5 1.1821986607142857e-05 0.0 1.1838727678571428e-05 0.0 1.1839285714285713e-05 1.5 1.1839285714285713e-05 1.5 1.183984375e-05 0.0 1.185658482142857e-05 0.0 1.1857142857142857e-05 1.5 1.1857142857142857e-05 1.5 1.1857700892857142e-05 0.0 1.1874441964285714e-05 0.0 1.1874999999999999e-05 1.5 1.1874999999999999e-05 1.5 1.1875558035714284e-05 0.0 1.1892299107142856e-05 0.0 1.1892857142857141e-05 1.5 1.1892857142857141e-05 1.5 1.1893415178571428e-05 0.0 1.1910156249999999e-05 0.0 1.1910714285714285e-05 1.5 1.1910714285714285e-05 1.5 1.191127232142857e-05 0.0 1.1928013392857143e-05 0.0 1.1928571428571428e-05 1.5 1.1928571428571428e-05 1.5 1.1929129464285713e-05 0.0 1.1945870535714285e-05 0.0 1.194642857142857e-05 1.5 1.194642857142857e-05 1.5 1.1946986607142857e-05 0.0 1.1963727678571427e-05 0.0 1.1964285714285714e-05 1.5 1.1964285714285714e-05 1.5 1.1964843749999999e-05 0.0 1.1981584821428571e-05 0.0 1.1982142857142856e-05 1.5 1.1982142857142856e-05 1.5 1.1982700892857141e-05 0.0 1.1999441964285714e-05 0.0 1.1999999999999999e-05 1.5 1.1999999999999999e-05 1.5 1.2000558035714285e-05 0.0 1.2017299107142856e-05 0.0 1.2017857142857143e-05 1.5 1.2017857142857143e-05 1.5 1.2018415178571428e-05 0.0 1.203515625e-05 0.0 1.2035714285714285e-05 1.5 1.2035714285714285e-05 1.5 1.203627232142857e-05 0.0 1.2053013392857142e-05 0.0 1.2053571428571427e-05 1.5 1.2053571428571427e-05 1.5 1.2054129464285714e-05 0.0 1.2070870535714285e-05 0.0 1.2071428571428571e-05 1.5 1.2071428571428571e-05 1.5 1.2071986607142856e-05 0.0 1.2088727678571427e-05 0.0 1.2089285714285714e-05 1.5 1.2089285714285714e-05 1.5 1.2089843749999999e-05 0.0 1.2106584821428571e-05 0.0 1.2107142857142856e-05 1.5 1.2107142857142856e-05 1.5 1.2107700892857143e-05 0.0 1.2124441964285713e-05 0.0 1.2125e-05 1.5 1.2125e-05 1.5 1.2125558035714285e-05 0.0 1.2142299107142856e-05 0.0 1.2142857142857142e-05 1.5 1.2142857142857142e-05 1.5 1.2143415178571427e-05 0.0 1.216015625e-05 0.0 1.2160714285714285e-05 1.5 1.2160714285714285e-05 1.5 1.2161272321428571e-05 0.0 1.2178013392857142e-05 0.0 1.2178571428571427e-05 1.5 1.2178571428571427e-05 1.5 1.2179129464285714e-05 0.0 1.2195870535714284e-05 0.0 1.2196428571428571e-05 1.5 1.2196428571428571e-05 1.5 1.2196986607142856e-05 0.0 1.2213727678571428e-05 0.0 1.2214285714285713e-05 1.5 1.2214285714285713e-05 1.5 1.2214843749999998e-05 0.0 1.223158482142857e-05 0.0 1.2232142857142856e-05 1.5 1.2232142857142856e-05 1.5 1.2232700892857142e-05 0.0 1.2249441964285713e-05 0.0 1.225e-05 1.5 1.225e-05 1.5 1.2250558035714285e-05 0.0 1.2267299107142857e-05 0.0 1.2267857142857142e-05 1.5 1.2267857142857142e-05 1.5 1.2268415178571427e-05 0.0 1.228515625e-05 0.0 1.2285714285714284e-05 1.5 1.2285714285714284e-05 1.5 1.2286272321428571e-05 0.0 1.2303013392857142e-05 0.0 1.2303571428571428e-05 1.5 1.2303571428571428e-05 1.5 1.2304129464285713e-05 0.0 1.2320870535714286e-05 0.0 1.232142857142857e-05 1.5 1.232142857142857e-05 1.5 1.2321986607142856e-05 0.0 1.2338727678571428e-05 0.0 1.2339285714285713e-05 1.5 1.2339285714285713e-05 1.5 1.233984375e-05 0.0 1.235658482142857e-05 0.0 1.2357142857142857e-05 1.5 1.2357142857142857e-05 1.5 1.2357700892857142e-05 0.0 1.2374441964285714e-05 0.0 1.2375e-05 1.5 1.2375e-05 1.5 1.2375558035714284e-05 0.0 1.2392299107142857e-05 0.0 1.2392857142857142e-05 1.5 1.2392857142857142e-05 1.5 1.2393415178571428e-05 0.0 1.2410156249999999e-05 0.0 1.2410714285714286e-05 1.5 1.2410714285714286e-05 1.5 1.241127232142857e-05 0.0 1.2428013392857141e-05 0.0 1.2428571428571428e-05 1.5 1.2428571428571428e-05 1.5 1.2429129464285713e-05 0.0 1.2445870535714285e-05 0.0 1.244642857142857e-05 1.5 1.244642857142857e-05 1.5 1.2446986607142857e-05 0.0 1.2463727678571428e-05 0.0 1.2464285714285713e-05 1.5 1.2464285714285713e-05 1.5 1.246484375e-05 0.0 1.248158482142857e-05 0.0 1.2482142857142857e-05 1.5 1.2482142857142857e-05 1.5 1.2482700892857142e-05 0.0 1.2499441964285714e-05 0.0 1.2499999999999999e-05 1.5 1.2499999999999999e-05 1.5 1.2500558035714286e-05 0.0 1.2517299107142856e-05 0.0 1.2517857142857141e-05 1.5 1.2517857142857141e-05 1.5 1.2518415178571428e-05 0.0 1.2535156249999998e-05 0.0 1.2535714285714285e-05 1.5 1.2535714285714285e-05 1.5 1.253627232142857e-05 0.0 1.2553013392857143e-05 0.0 1.2553571428571428e-05 1.5 1.2553571428571428e-05 1.5 1.2554129464285713e-05 0.0 1.2570870535714285e-05 0.0 1.257142857142857e-05 1.5 1.257142857142857e-05 1.5 1.2571986607142857e-05 0.0 1.2588727678571427e-05 0.0 1.2589285714285714e-05 1.5 1.2589285714285714e-05 1.5 1.2589843749999999e-05 0.0 1.2606584821428571e-05 0.0 1.2607142857142856e-05 1.5 1.2607142857142856e-05 1.5 1.2607700892857141e-05 0.0 1.2624441964285713e-05 0.0 1.2624999999999999e-05 1.5 1.2624999999999999e-05 1.5 1.2625558035714285e-05 0.0 1.2642299107142856e-05 0.0 1.2642857142857143e-05 1.5 1.2642857142857143e-05 1.5 1.2643415178571428e-05 0.0 1.266015625e-05 0.0 1.2660714285714285e-05 1.5 1.2660714285714285e-05 1.5 1.266127232142857e-05 0.0 1.2678013392857142e-05 0.0 1.2678571428571427e-05 1.5 1.2678571428571427e-05 1.5 1.2679129464285714e-05 0.0 1.26953125e-05 0.0 1.2695870535714284e-05 1.5 1.2696986607142856e-05 1.5 1.2697544642857141e-05 0.0 1.2713169642857142e-05 0.0 1.2713727678571428e-05 1.5 1.2714843749999999e-05 1.5 1.2715401785714285e-05 0.0 1.2731026785714284e-05 0.0 1.273158482142857e-05 1.5 1.2732700892857143e-05 1.5 1.2733258928571428e-05 0.0 1.2748883928571428e-05 0.0 1.2749441964285713e-05 1.5 1.2750558035714285e-05 1.5 1.275111607142857e-05 0.0 1.276674107142857e-05 0.0 1.2767299107142855e-05 1.5 1.2768415178571427e-05 1.5 1.2768973214285714e-05 0.0 1.2784598214285713e-05 0.0 1.278515625e-05 1.5 1.2786272321428571e-05 1.5 1.2786830357142856e-05 0.0 1.2802455357142857e-05 0.0 1.2803013392857142e-05 1.5 1.2804129464285714e-05 1.5 1.2804687499999999e-05 0.0 1.2820312499999999e-05 0.0 1.2820870535714284e-05 1.5 1.2821986607142856e-05 1.5 1.2822544642857143e-05 0.0 1.2838169642857141e-05 0.0 1.2838727678571428e-05 1.5 1.2839843749999998e-05 1.5 1.2840401785714285e-05 0.0 1.2856026785714285e-05 0.0 1.285658482142857e-05 1.5 1.2857700892857142e-05 1.5 1.2858258928571427e-05 0.0 1.2873883928571428e-05 0.0 1.2874441964285713e-05 1.5 1.2875558035714285e-05 1.5 1.287611607142857e-05 0.0 1.289174107142857e-05 0.0 1.2892299107142857e-05 1.5 1.2893415178571427e-05 1.5 1.2893973214285714e-05 0.0 1.2909598214285714e-05 0.0 1.2910156249999999e-05 1.5 1.2911272321428571e-05 1.5 1.2911830357142856e-05 0.0 1.2927455357142856e-05 0.0 1.2928013392857141e-05 1.5 1.2929129464285713e-05 1.5 1.2929687499999998e-05 0.0 1.2945312499999999e-05 0.0 1.2945870535714285e-05 1.5 1.2946986607142856e-05 1.5 1.2947544642857142e-05 0.0 1.2962611607142856e-05 0.0 1.2963169642857143e-05 1.5 1.2965401785714285e-05 1.5 1.296595982142857e-05 0.0 1.2980468749999998e-05 0.0 1.2981026785714285e-05 1.5 1.2983258928571427e-05 1.5 1.2983816964285714e-05 0.0 1.2998325892857142e-05 0.0 1.2998883928571427e-05 1.5 1.3001116071428571e-05 1.5 1.3001674107142856e-05 0.0 1.3016183035714285e-05 0.0 1.301674107142857e-05 1.5 1.3018973214285713e-05 1.5 1.3019531249999998e-05 0.0 1.3034040178571427e-05 0.0 1.3034598214285714e-05 1.5 1.3036830357142856e-05 1.5 1.3037388392857142e-05 0.0 1.3051897321428571e-05 0.0 1.3052455357142856e-05 1.5 1.30546875e-05 1.5 1.3055245535714285e-05 0.0 1.3069754464285713e-05 0.0 1.3070312499999998e-05 1.5 1.3072544642857142e-05 1.5 1.3073102678571427e-05 0.0 1.3087611607142856e-05 0.0 1.3088169642857142e-05 1.5 1.3090401785714284e-05 1.5 1.3090959821428571e-05 0.0 1.310546875e-05 0.0 1.3106026785714285e-05 1.5 1.3108258928571428e-05 1.5 1.3108816964285713e-05 0.0 1.3123325892857142e-05 0.0 1.3123883928571427e-05 1.5 1.312611607142857e-05 1.5 1.3126674107142856e-05 0.0 1.3141183035714284e-05 0.0 1.3141741071428571e-05 1.5 1.3143973214285713e-05 1.5 1.314453125e-05 0.0 1.3159040178571428e-05 0.0 1.3159598214285713e-05 1.5 1.3161830357142857e-05 1.5 1.3162388392857142e-05 0.0 1.317689732142857e-05 0.0 1.3177455357142856e-05 1.5 1.31796875e-05 1.5 1.3180245535714284e-05 0.0 1.3194196428571428e-05 0.0 1.3194754464285713e-05 1.5 1.3198102678571428e-05 1.5 1.3198660714285713e-05 0.0 1.321205357142857e-05 0.0 1.3212611607142857e-05 1.5 1.321595982142857e-05 1.5 1.3216517857142856e-05 0.0 1.3229910714285713e-05 0.0 1.323046875e-05 1.5 1.3233816964285713e-05 1.5 1.3234375e-05 0.0 1.3247767857142857e-05 0.0 1.3248325892857142e-05 1.5 1.3251674107142855e-05 1.5 1.3252232142857142e-05 0.0 1.3265624999999999e-05 0.0 1.3266183035714284e-05 1.5 1.326953125e-05 1.5 1.3270089285714284e-05 0.0 1.3283482142857141e-05 0.0 1.3284040178571428e-05 1.5 1.3287388392857142e-05 1.5 1.3287946428571427e-05 0.0 1.3301339285714285e-05 0.0 1.330189732142857e-05 1.5 1.3305245535714284e-05 1.5 1.330580357142857e-05 0.0 1.3319196428571428e-05 0.0 1.3319754464285713e-05 1.5 1.3323102678571428e-05 1.5 1.3323660714285713e-05 0.0 1.333705357142857e-05 0.0 1.3337611607142857e-05 1.5 1.334095982142857e-05 1.5 1.3341517857142855e-05 0.0 1.3354910714285714e-05 0.0 1.3355468749999999e-05 1.5 1.3358816964285713e-05 1.5 1.3359375e-05 0.0 1.3372767857142856e-05 0.0 1.3373325892857141e-05 1.5 1.3377232142857142e-05 1.5 1.3377790178571427e-05 0.0 1.3390066964285713e-05 0.0 1.3390624999999999e-05 1.5 1.3395089285714284e-05 1.5 1.3395647321428571e-05 0.0 1.3407924107142856e-05 0.0 1.3408482142857143e-05 1.5 1.3412946428571428e-05 1.5 1.3413504464285713e-05 0.0 1.342578125e-05 0.0 1.3426339285714285e-05 1.5 1.343080357142857e-05 1.5 1.3431361607142856e-05 0.0 1.3443638392857142e-05 0.0 1.3444196428571427e-05 1.5 1.3448660714285713e-05 1.5 1.344921875e-05 0.0 1.3461495535714284e-05 0.0 1.3462053571428571e-05 1.5 1.3466517857142857e-05 1.5 1.3467075892857142e-05 0.0 1.3479352678571427e-05 0.0 1.3479910714285714e-05 1.5 1.3484374999999999e-05 1.5 1.3484933035714284e-05 0.0 1.349720982142857e-05 0.0 1.3497767857142856e-05 1.5 1.3502232142857141e-05 1.5 1.3502790178571428e-05 0.0 1.3515066964285713e-05 0.0 1.3515625e-05 1.5 1.3520089285714285e-05 1.5 1.352064732142857e-05 0.0 1.3532924107142855e-05 0.0 1.3533482142857142e-05 1.5 1.3537946428571428e-05 1.5 1.3538504464285713e-05 0.0 1.355078125e-05 0.0 1.3551339285714285e-05 1.5 1.3556361607142857e-05 1.5 1.3556919642857142e-05 0.0 1.3568080357142857e-05 0.0 1.3568638392857142e-05 1.5 1.357421875e-05 1.5 1.3574776785714284e-05 0.0 1.3585937499999999e-05 0.0 1.3586495535714284e-05 1.5 1.3592075892857142e-05 1.5 1.3592633928571428e-05 0.0 1.3603794642857141e-05 0.0 1.3604352678571428e-05 1.5 1.3609933035714286e-05 1.5 1.361049107142857e-05 0.0 1.3621651785714285e-05 0.0 1.362220982142857e-05 1.5 1.3627790178571428e-05 1.5 1.3628348214285713e-05 0.0 1.3639508928571428e-05 0.0 1.3640066964285713e-05 1.5 1.364564732142857e-05 1.5 1.3646205357142857e-05 0.0 1.365736607142857e-05 0.0 1.3657924107142857e-05 1.5 1.3663504464285712e-05 1.5 1.36640625e-05 0.0 1.3675223214285714e-05 0.0 1.3675781249999999e-05 1.5 1.3681361607142857e-05 1.5 1.3681919642857142e-05 0.0 1.3693080357142856e-05 0.0 1.3693638392857141e-05 1.5 1.3699218749999999e-05 1.5 1.3699776785714284e-05 0.0 1.3710937499999999e-05 0.0 1.3711495535714285e-05 1.5 1.3717075892857141e-05 1.5 1.3717633928571428e-05 0.0 1.3728236607142856e-05 0.0 1.3728794642857143e-05 1.5 1.373549107142857e-05 1.5 1.3736049107142857e-05 0.0 1.3746093749999998e-05 0.0 1.3746651785714285e-05 1.5 1.3753348214285713e-05 1.5 1.375390625e-05 0.0 1.3763950892857142e-05 0.0 1.3764508928571427e-05 1.5 1.3771205357142857e-05 1.5 1.3771763392857142e-05 0.0 1.3781808035714285e-05 0.0 1.378236607142857e-05 1.5 1.3789062499999999e-05 1.5 1.3789620535714284e-05 0.0 1.3799665178571427e-05 0.0 1.3800223214285714e-05 1.5 1.3806919642857141e-05 1.5 1.3807477678571428e-05 0.0 1.3817522321428571e-05 0.0 1.3818080357142856e-05 1.5 1.3824776785714285e-05 1.5 1.382533482142857e-05 0.0 1.3835379464285713e-05 0.0 1.3835937499999998e-05 1.5 1.3842633928571428e-05 1.5 1.3843191964285713e-05 0.0 1.3853236607142856e-05 0.0 1.3853794642857142e-05 1.5 1.386049107142857e-05 1.5 1.3861049107142857e-05 0.0 1.387109375e-05 0.0 1.3871651785714285e-05 1.5 1.3878348214285714e-05 1.5 1.3878906249999999e-05 0.0 1.3888392857142857e-05 0.0 1.3888950892857142e-05 1.5 1.3896763392857141e-05 1.5 1.3897321428571428e-05 0.0 1.390625e-05 0.0 1.3906808035714284e-05 1.5 1.3914620535714285e-05 1.5 1.391517857142857e-05 0.0 1.3924107142857142e-05 0.0 1.3924665178571428e-05 1.5 1.3932477678571428e-05 1.5 1.3933035714285713e-05 0.0 1.3941964285714286e-05 0.0 1.394252232142857e-05 1.5 1.395033482142857e-05 1.5 1.3950892857142857e-05 0.0 1.3959821428571428e-05 0.0 1.3960379464285713e-05 1.5 1.3968191964285714e-05 1.5 1.3968749999999999e-05 0.0 1.397767857142857e-05 0.0 1.3978236607142857e-05 1.5 1.3986049107142856e-05 1.5 1.3986607142857141e-05 0.0 1.3995535714285713e-05 0.0 1.399609375e-05 1.5 1.4003906249999999e-05 1.5 1.4004464285714285e-05 0.0 1.4013392857142857e-05 0.0 1.4013950892857142e-05 1.5 1.4021763392857143e-05 1.5 1.4022321428571428e-05 0.0 1.4031249999999999e-05 0.0 1.4031808035714284e-05 1.5 1.4039620535714285e-05 1.5 1.404017857142857e-05 0.0 1.4048549107142856e-05 0.0 1.4049107142857141e-05 1.5 1.4058035714285714e-05 1.5 1.4058593749999999e-05 0.0 1.4066406249999998e-05 0.0 1.4066964285714285e-05 1.5 1.4075892857142856e-05 1.5 1.4076450892857141e-05 0.0 1.4084263392857142e-05 0.0 1.4084821428571428e-05 1.5 1.4093749999999999e-05 1.5 1.4094308035714285e-05 0.0 1.4102120535714285e-05 0.0 1.410267857142857e-05 1.5 1.4111607142857141e-05 1.5 1.4112165178571428e-05 0.0 1.4119977678571427e-05 0.0 1.4120535714285714e-05 1.5 1.4129464285714285e-05 1.5 1.413002232142857e-05 0.0 1.4137834821428571e-05 0.0 1.4138392857142856e-05 1.5 1.4147321428571427e-05 1.5 1.4147879464285714e-05 0.0 1.4155691964285713e-05 0.0 1.4156249999999999e-05 1.5 1.416517857142857e-05 1.5 1.4165736607142856e-05 0.0 1.4173549107142856e-05 0.0 1.4174107142857143e-05 1.5 1.4183035714285714e-05 1.5 1.4183593749999999e-05 0.0 1.419140625e-05 0.0 1.4191964285714285e-05 1.5 1.4200892857142856e-05 1.5 1.4201450892857141e-05 0.0 1.4208705357142855e-05 0.0 1.4209263392857142e-05 1.5 1.4219308035714285e-05 1.5 1.421986607142857e-05 0.0 1.42265625e-05 0.0 1.4227120535714284e-05 1.5 1.4237165178571427e-05 1.5 1.4237723214285712e-05 0.0 1.4244419642857142e-05 0.0 1.4244977678571427e-05 1.5 1.425502232142857e-05 1.5 1.4255580357142856e-05 0.0 1.4262276785714284e-05 0.0 1.426283482142857e-05 1.5 1.4272879464285714e-05 1.5 1.4273437499999999e-05 0.0 1.4280133928571428e-05 0.0 1.4280691964285713e-05 1.5 1.4290736607142856e-05 1.5 1.4291294642857141e-05 0.0 1.429799107142857e-05 0.0 1.4298549107142855e-05 1.5 1.4308593749999998e-05 1.5 1.4309151785714285e-05 0.0 1.4315848214285713e-05 0.0 1.431640625e-05 1.5 1.4326450892857142e-05 1.5 1.4327008928571427e-05 0.0 1.4333705357142857e-05 0.0 1.4334263392857142e-05 1.5 1.4344308035714285e-05 1.5 1.434486607142857e-05 0.0 1.4351562499999999e-05 0.0 1.4352120535714284e-05 1.5 1.4362165178571427e-05 1.5 1.4362723214285714e-05 0.0 1.4368861607142856e-05 0.0 1.4369419642857141e-05 1.5 1.4380580357142856e-05 1.5 1.4381138392857141e-05 0.0 1.4386718749999999e-05 0.0 1.4387276785714285e-05 1.5 1.4398437499999998e-05 1.5 1.4398995535714285e-05 0.0 1.4404575892857143e-05 0.0 1.4405133928571428e-05 1.5 1.4416294642857142e-05 1.5 1.4416852678571428e-05 0.0 1.4422433035714285e-05 0.0 1.442299107142857e-05 1.5 1.4434151785714285e-05 1.5 1.443470982142857e-05 0.0 1.4440290178571427e-05 0.0 1.4440848214285714e-05 1.5 1.4452008928571427e-05 1.5 1.4452566964285714e-05 0.0 1.445814732142857e-05 0.0 1.4458705357142856e-05 1.5 1.4469866071428571e-05 1.5 1.4470424107142856e-05 0.0 1.4476004464285714e-05 0.0 1.4476562499999999e-05 1.5 1.4487723214285713e-05 1.5 1.4488281249999999e-05 0.0 1.4493861607142856e-05 0.0 1.4494419642857141e-05 1.5 1.4505580357142856e-05 1.5 1.4506138392857143e-05 0.0 1.4511718749999998e-05 0.0 1.4512276785714285e-05 1.5 1.4523437499999998e-05 1.5 1.4523995535714285e-05 0.0 1.4529575892857142e-05 0.0 1.4530133928571427e-05 1.5 1.4541852678571427e-05 1.5 1.4542410714285714e-05 0.0 1.4546875e-05 0.0 1.4547433035714285e-05 1.5 1.4559709821428571e-05 1.5 1.4560267857142856e-05 0.0 1.4564732142857142e-05 0.0 1.4565290178571427e-05 1.5 1.4577566964285714e-05 1.5 1.4578124999999999e-05 0.0 1.4582589285714284e-05 0.0 1.4583147321428571e-05 1.5 1.4595424107142856e-05 1.5 1.4595982142857143e-05 0.0 1.4600446428571428e-05 0.0 1.4601004464285713e-05 1.5 1.4613281249999998e-05 1.5 1.4613839285714285e-05 0.0 1.461830357142857e-05 0.0 1.4618861607142856e-05 1.5 1.4631138392857142e-05 1.5 1.4631696428571427e-05 0.0 1.4636160714285713e-05 0.0 1.463671875e-05 1.5 1.4648995535714285e-05 1.5 1.464955357142857e-05 0.0 1.4654017857142857e-05 0.0 1.4654575892857142e-05 1.5 1.4666852678571427e-05 1.5 1.4667410714285714e-05 0.0 1.4671875e-05 0.0 1.4672433035714284e-05 1.5 1.4684709821428571e-05 1.5 1.4685267857142856e-05 0.0 1.4689732142857142e-05 0.0 1.4690290178571428e-05 1.5 1.4702566964285713e-05 1.5 1.4703124999999998e-05 0.0 1.4707589285714284e-05 0.0 1.470814732142857e-05 1.5 1.4720982142857142e-05 1.5 1.4721540178571427e-05 0.0 1.4724888392857141e-05 0.0 1.4725446428571428e-05 1.5 1.4738839285714285e-05 1.5 1.473939732142857e-05 0.0 1.4742745535714285e-05 0.0 1.474330357142857e-05 1.5 1.4756696428571427e-05 1.5 1.4757254464285714e-05 0.0 1.4760602678571427e-05 0.0 1.4761160714285712e-05 1.5 1.4774553571428571e-05 1.5 1.4775111607142856e-05 0.0 1.477845982142857e-05 0.0 1.4779017857142857e-05 1.5 1.4792410714285713e-05 1.5 1.4792968749999998e-05 0.0 1.4796316964285714e-05 0.0 1.4796874999999999e-05 1.5 1.4810267857142856e-05 1.5 1.4810825892857142e-05 0.0 1.4814174107142856e-05 0.0 1.4814732142857141e-05 1.5 1.4828125e-05 1.5 1.4828683035714285e-05 0.0 1.4832031249999998e-05 0.0 1.4832589285714285e-05 1.5 1.4845982142857142e-05 1.5 1.4846540178571427e-05 0.0 1.4849888392857142e-05 0.0 1.4850446428571427e-05 1.5 1.4863839285714284e-05 1.5 1.4864397321428571e-05 0.0 1.4867745535714285e-05 0.0 1.486830357142857e-05 1.5 1.4881696428571428e-05 1.5 1.4882254464285713e-05 0.0 1.4885602678571427e-05 0.0 1.4886160714285714e-05 1.5 1.489955357142857e-05 1.5 1.4900111607142856e-05 0.0 1.4903459821428571e-05 0.0 1.4904017857142856e-05 1.5 1.491796875e-05 1.5 1.4918526785714285e-05 0.0 1.4920758928571427e-05 0.0 1.4921316964285713e-05 1.5 1.4935825892857142e-05 1.5 1.4936383928571427e-05 0.0 1.493861607142857e-05 0.0 1.4939174107142856e-05 1.5 1.4953683035714284e-05 1.5 1.4954241071428571e-05 0.0 1.4956473214285713e-05 0.0 1.495703125e-05 1.5 1.4971540178571428e-05 1.5 1.4972098214285713e-05 0.0 1.4974330357142855e-05 0.0 1.4974888392857142e-05 1.5 1.498939732142857e-05 1.5 1.4989955357142856e-05 0.0 1.49921875e-05 0.0 1.4992745535714284e-05 1.5 1.5007254464285713e-05 1.5 1.50078125e-05 0.0 1.5010044642857142e-05 0.0 1.5010602678571427e-05 1.5 1.5025111607142855e-05 1.5 1.5025669642857142e-05 0.0 1.5027901785714284e-05 0.0 1.502845982142857e-05 1.5 1.504296875e-05 1.5 1.5043526785714284e-05 0.0 1.5045758928571428e-05 0.0 1.5046316964285713e-05 1.5 1.5060825892857142e-05 1.5 1.5061383928571427e-05 0.0 1.506361607142857e-05 0.0 1.5064174107142855e-05 1.5 1.5078683035714284e-05 1.5 1.507924107142857e-05 0.0 1.5081473214285713e-05 0.0 1.508203125e-05 1.5 1.5096540178571428e-05 1.5 1.5097098214285713e-05 0.0 1.5099330357142857e-05 0.0 1.5099888392857142e-05 1.5 1.511439732142857e-05 1.5 1.5114955357142855e-05 0.0 1.5117187499999999e-05 0.0 1.5117745535714284e-05 1.5 1.51328125e-05 1.5 1.5133370535714284e-05 0.0 1.5134486607142856e-05 0.0 1.5135044642857141e-05 1.5 1.5150669642857142e-05 1.5 1.5151227678571427e-05 0.0 1.5152343749999999e-05 0.0 1.5152901785714285e-05 1.5 1.5168526785714284e-05 1.5 1.516908482142857e-05 0.0 1.5170200892857143e-05 0.0 1.5170758928571428e-05 1.5 1.5186383928571428e-05 1.5 1.5186941964285713e-05 0.0 1.5188058035714285e-05 0.0 1.518861607142857e-05 1.5 1.520424107142857e-05 1.5 1.5204799107142855e-05 0.0 1.5205915178571427e-05 0.0 1.5206473214285714e-05 1.5 1.5222098214285713e-05 1.5 1.522265625e-05 0.0 1.522377232142857e-05 0.0 1.5224330357142856e-05 1.5 1.5239955357142857e-05 1.5 1.5240513392857142e-05 0.0 1.5241629464285714e-05 0.0 1.5242187499999999e-05 1.5 1.5257812499999999e-05 1.5 1.5258370535714284e-05 0.0 1.5259486607142856e-05 0.0 1.5260044642857143e-05 1.5 1.527566964285714e-05 1.5 1.5276227678571428e-05 0.0 1.5277343749999998e-05 0.0 1.5277901785714285e-05 1.5 1.5293526785714284e-05 1.5 1.529408482142857e-05 0.0 1.529520089285714e-05 0.0 1.5295758928571427e-05 1.5 1.5311383928571426e-05 1.5 1.5311941964285713e-05 0.0 1.5313058035714286e-05 0.0 1.531361607142857e-05 1.5 1.5329241071428572e-05 1.5 1.5329799107142855e-05 0.0 1.533091517857143e-05 0.0 1.5331473214285712e-05 1.5 1.5347098214285714e-05 1.5 1.5347656249999997e-05 0.0 1.534877232142857e-05 0.0 1.5349330357142858e-05 1.5 1.5364955357142856e-05 1.5 1.5365513392857143e-05 0.0 1.5366629464285713e-05 0.0 1.53671875e-05 1.5 1.53828125e-05 1.5 1.5383370535714285e-05 0.0 1.5384486607142856e-05 0.0 1.5385044642857142e-05 1.5 1.540066964285714e-05 1.5 1.5401227678571428e-05 0.0 1.5402343749999998e-05 0.0 1.5402901785714285e-05 1.5 1.541908482142857e-05 1.5 1.5419642857142857e-05 0.0 1.5419642857142857e-05 0.0 1.542020089285714e-05 1.5 1.5436941964285712e-05 1.5 1.54375e-05 0.0 1.54375e-05 0.0 1.5438058035714286e-05 1.5 1.5454799107142855e-05 1.5 1.545535714285714e-05 0.0 1.545535714285714e-05 0.0 1.5455915178571428e-05 1.5 1.547265625e-05 1.5 1.5473214285714284e-05 0.0 1.5473214285714284e-05 0.0 1.547377232142857e-05 1.5 1.5490513392857143e-05 1.5 1.5491071428571426e-05 0.0 1.5491071428571426e-05 0.0 1.5491629464285713e-05 1.5 1.5508370535714285e-05 1.5 1.5508928571428572e-05 0.0 1.5508928571428572e-05 0.0 1.5509486607142855e-05 1.5 1.5526227678571427e-05 1.5 1.5526785714285714e-05 0.0 1.5526785714285714e-05 0.0 1.5527343749999998e-05 1.5 1.554408482142857e-05 1.5 1.5544642857142856e-05 0.0 1.5544642857142856e-05 0.0 1.5545200892857143e-05 1.5 1.5561941964285712e-05 1.5 1.55625e-05 0.0 1.55625e-05 0.0 1.5563058035714286e-05 1.5 1.5579799107142854e-05 1.5 1.558035714285714e-05 0.0 1.558035714285714e-05 0.0 1.5580915178571428e-05 1.5 1.559765625e-05 1.5 1.5598214285714283e-05 0.0 1.5598214285714283e-05 0.0 1.559877232142857e-05 1.5 1.5615513392857142e-05 1.5 1.5616071428571426e-05 0.0 1.5616071428571426e-05 0.0 1.5616629464285713e-05 1.5 1.5633370535714285e-05 1.5 1.563392857142857e-05 0.0 1.563392857142857e-05 0.0 1.5634486607142855e-05 1.5 1.5651227678571427e-05 1.5 1.5651785714285714e-05 0.0 1.5651785714285714e-05 0.0 1.565234375e-05 1.5 1.566908482142857e-05 1.5 1.5669642857142856e-05 0.0 1.5669642857142856e-05 0.0 1.5670200892857143e-05 1.5 1.5686941964285712e-05 1.5 1.56875e-05 0.0 1.56875e-05 0.0 1.5688058035714285e-05 1.5 1.5704799107142857e-05 1.5 1.570535714285714e-05 0.0 1.570535714285714e-05 0.0 1.5705915178571428e-05 1.5 1.572265625e-05 1.5 1.5723214285714283e-05 0.0 1.5723214285714283e-05 0.0 1.572377232142857e-05 1.5 1.5740513392857142e-05 1.5 1.574107142857143e-05 0.0 1.574107142857143e-05 0.0 1.5741629464285712e-05 1.5 1.5758370535714284e-05 1.5 1.575892857142857e-05 0.0 1.575892857142857e-05 0.0 1.5759486607142855e-05 1.5 1.5776227678571427e-05 1.5 1.5776785714285713e-05 0.0 1.5776785714285713e-05 0.0 1.577734375e-05 1.5 1.579408482142857e-05 1.5 1.5794642857142856e-05 0.0 1.5794642857142856e-05 0.0 1.5795200892857143e-05 1.5 1.5811941964285715e-05 1.5 1.5812499999999998e-05 0.0 1.5812499999999998e-05 0.0 1.5813058035714285e-05 1.5 1.5829799107142857e-05 1.5 1.583035714285714e-05 0.0 1.583035714285714e-05 0.0 1.5830915178571427e-05 1.5 1.584765625e-05 1.5 1.5848214285714286e-05 0.0 1.5848214285714286e-05 0.0 1.584877232142857e-05 1.5 1.5865513392857142e-05 1.5 1.586607142857143e-05 0.0 1.586607142857143e-05 0.0 1.5866629464285712e-05 1.5 1.5883370535714284e-05 1.5 1.588392857142857e-05 0.0 1.588392857142857e-05 0.0 1.5884486607142858e-05 1.5 1.5901227678571426e-05 1.5 1.5901785714285713e-05 0.0 1.5901785714285713e-05 0.0 1.590234375e-05 1.5 1.591908482142857e-05 1.5 1.5919642857142855e-05 0.0 1.5919642857142855e-05 0.0 1.5920200892857142e-05 1.5 1.5936941964285714e-05 1.5 1.5937499999999998e-05 0.0 1.5937499999999998e-05 0.0 1.5938058035714285e-05 1.5 1.5954799107142857e-05 1.5 1.595535714285714e-05 0.0 1.595535714285714e-05 0.0 1.5955915178571427e-05 1.5 1.597265625e-05 1.5 1.5973214285714286e-05 0.0 1.5973214285714286e-05 0.0 1.597377232142857e-05 1.5 1.599051339285714e-05 1.5 1.5991071428571428e-05 0.0 1.5991071428571428e-05 0.0 1.599162946428571e-05 1.5 1.6008370535714284e-05 1.5 1.600892857142857e-05 0.0 1.600892857142857e-05 0.0 1.6009486607142857e-05 1.5 1.6026227678571426e-05 1.5 1.6026785714285713e-05 0.0 1.6026785714285713e-05 0.0 1.602734375e-05 1.5 1.6044084821428572e-05 1.5 1.6044642857142855e-05 0.0 1.6044642857142855e-05 0.0 1.6045200892857142e-05 1.5 1.6061941964285714e-05 1.5 1.6062499999999997e-05 0.0 1.6062499999999997e-05 0.0 1.6063058035714284e-05 1.5 1.6079799107142856e-05 1.5 1.6080357142857143e-05 0.0 1.6080357142857143e-05 0.0 1.6080915178571426e-05 1.5 1.609765625e-05 1.5 1.6098214285714285e-05 0.0 1.6098214285714285e-05 0.0 1.609877232142857e-05 1.5 1.611551339285714e-05 1.5 1.6116071428571428e-05 0.0 1.6116071428571428e-05 0.0 1.6116629464285715e-05 1.5 1.6133370535714283e-05 1.5 1.613392857142857e-05 0.0 1.613392857142857e-05 0.0 1.6134486607142857e-05 1.5 1.615122767857143e-05 1.5 1.6151785714285712e-05 0.0 1.6151785714285712e-05 0.0 1.615234375e-05 1.5 1.616908482142857e-05 1.5 1.6169642857142855e-05 0.0 1.6169642857142855e-05 0.0 1.617020089285714e-05 1.5 1.6186941964285714e-05 1.5 1.61875e-05 0.0 1.61875e-05 0.0 1.6188058035714284e-05 1.5 1.6204799107142856e-05 1.5 1.6205357142857143e-05 0.0 1.6205357142857143e-05 0.0 1.6205915178571426e-05 1.5 1.622265625e-05 1.5 1.6223214285714285e-05 0.0 1.6223214285714285e-05 0.0 1.6223772321428572e-05 1.5 1.624051339285714e-05 1.5 1.6241071428571427e-05 0.0 1.6241071428571427e-05 0.0 1.6241629464285714e-05 1.5 1.6258370535714283e-05 1.5 1.625892857142857e-05 0.0 1.625892857142857e-05 0.0 1.6259486607142856e-05 1.5 1.627622767857143e-05 1.5 1.6276785714285712e-05 0.0 1.6276785714285712e-05 0.0 1.627734375e-05 1.5 1.629408482142857e-05 1.5 1.6294642857142854e-05 0.0 1.6294642857142854e-05 0.0 1.629520089285714e-05 1.5 1.6311941964285713e-05 1.5 1.63125e-05 0.0 1.63125e-05 0.0 1.6313058035714283e-05 1.5 1.6329799107142856e-05 1.5 1.6330357142857142e-05 0.0 1.6330357142857142e-05 0.0 1.6330915178571426e-05 1.5 1.6347656249999998e-05 1.5 1.6348214285714285e-05 0.0 1.6348214285714285e-05 0.0 1.634877232142857e-05 1.5 1.636551339285714e-05 1.5 1.6366071428571427e-05 0.0 1.6366071428571427e-05 0.0 1.6366629464285714e-05 1.5 1.6383370535714286e-05 1.5 1.638392857142857e-05 0.0 1.638392857142857e-05 0.0 1.6384486607142856e-05 1.5 1.640122767857143e-05 1.5 1.6401785714285712e-05 0.0 1.6401785714285712e-05 0.0 1.640234375e-05 1.5 1.641908482142857e-05 1.5 1.6419642857142857e-05 0.0 1.6419642857142857e-05 0.0 1.642020089285714e-05 1.5 1.6436941964285713e-05 1.5 1.64375e-05 0.0 1.64375e-05 0.0 1.6438058035714283e-05 1.5 1.6454799107142855e-05 1.5 1.6455357142857142e-05 0.0 1.6455357142857142e-05 0.0 1.645591517857143e-05 1.5 1.6472656249999998e-05 1.5 1.6473214285714284e-05 0.0 1.6473214285714284e-05 0.0 1.647377232142857e-05 1.5 1.6490513392857143e-05 1.5 1.6491071428571427e-05 0.0 1.6491071428571427e-05 0.0 1.6491629464285713e-05 1.5 1.6508370535714286e-05 1.5 1.650892857142857e-05 0.0 1.650892857142857e-05 0.0 1.6509486607142856e-05 1.5 1.6526227678571428e-05 1.5 1.6526785714285715e-05 0.0 1.6526785714285715e-05 0.0 1.6527343749999998e-05 1.5 1.654408482142857e-05 1.5 1.6544642857142857e-05 0.0 1.6544642857142857e-05 0.0 1.654520089285714e-05 1.5 1.6561941964285713e-05 1.5 1.65625e-05 0.0 1.65625e-05 0.0 1.6563058035714286e-05 1.5 1.6579799107142855e-05 1.5 1.6580357142857142e-05 0.0 1.6580357142857142e-05 0.0 1.658091517857143e-05 1.5 1.6597656249999997e-05 1.5 1.6598214285714284e-05 0.0 1.6598214285714284e-05 0.0 1.659877232142857e-05 1.5 1.6615513392857143e-05 1.5 1.6616071428571426e-05 0.0 1.6616071428571426e-05 0.0 1.6616629464285713e-05 1.5 1.6633370535714285e-05 1.5 1.663392857142857e-05 0.0 1.663392857142857e-05 0.0 1.6634486607142855e-05 1.5 1.6651227678571428e-05 1.5 1.6651785714285714e-05 0.0 1.6651785714285714e-05 0.0 1.6652343749999998e-05 1.5 1.666908482142857e-05 1.5 1.6669642857142857e-05 0.0 1.6669642857142857e-05 0.0 1.667020089285714e-05 1.5 1.6686941964285712e-05 1.5 1.66875e-05 0.0 1.66875e-05 0.0 1.6688058035714286e-05 1.5 1.670424107142857e-05 1.5 1.6704799107142855e-05 0.0 1.6705915178571428e-05 0.0 1.670647321428571e-05 1.5 1.6722098214285714e-05 1.5 1.672265625e-05 0.0 1.672377232142857e-05 0.0 1.6724330357142857e-05 1.5 1.6739955357142856e-05 1.5 1.6740513392857143e-05 0.0 1.6741629464285713e-05 0.0 1.67421875e-05 1.5 1.6757812499999998e-05 1.5 1.6758370535714285e-05 0.0 1.6759486607142855e-05 0.0 1.6760044642857142e-05 1.5 1.677566964285714e-05 1.5 1.6776227678571427e-05 0.0 1.6777343749999997e-05 0.0 1.6777901785714284e-05 1.5 1.6793526785714283e-05 1.5 1.679408482142857e-05 0.0 1.6795200892857143e-05 0.0 1.6795758928571426e-05 1.5 1.681138392857143e-05 1.5 1.6811941964285712e-05 0.0 1.6813058035714285e-05 0.0 1.681361607142857e-05 1.5 1.682924107142857e-05 1.5 1.6829799107142854e-05 0.0 1.6830915178571428e-05 0.0 1.6831473214285715e-05 1.5 1.6847098214285713e-05 1.5 1.684765625e-05 0.0 1.684877232142857e-05 0.0 1.6849330357142857e-05 1.5 1.6864955357142856e-05 1.5 1.6865513392857142e-05 0.0 1.6866629464285712e-05 0.0 1.68671875e-05 1.5 1.6882812499999998e-05 1.5 1.6883370535714285e-05 0.0 1.6884486607142855e-05 0.0 1.688504464285714e-05 1.5 1.690066964285714e-05 1.5 1.6901227678571427e-05 0.0 1.690234375e-05 0.0 1.6902901785714284e-05 1.5 1.6918526785714286e-05 1.5 1.691908482142857e-05 0.0 1.6920200892857143e-05 0.0 1.6920758928571426e-05 1.5 1.6936383928571428e-05 1.5 1.693694196428571e-05 0.0 1.6938058035714285e-05 0.0 1.6938616071428572e-05 1.5 1.695424107142857e-05 1.5 1.6954799107142857e-05 0.0 1.6955915178571427e-05 0.0 1.6956473214285714e-05 1.5 1.6972098214285713e-05 1.5 1.697265625e-05 0.0 1.697377232142857e-05 0.0 1.6974330357142857e-05 1.5 1.6989397321428572e-05 1.5 1.6989955357142855e-05 0.0 1.69921875e-05 0.0 1.6992745535714286e-05 1.5 1.7007254464285714e-05 1.5 1.7007812499999998e-05 0.0 1.701004464285714e-05 0.0 1.7010602678571428e-05 1.5 1.7025111607142856e-05 1.5 1.7025669642857143e-05 0.0 1.7027901785714283e-05 0.0 1.702845982142857e-05 1.5 1.704296875e-05 1.5 1.7043526785714286e-05 0.0 1.7045758928571426e-05 0.0 1.7046316964285713e-05 1.5 1.706082589285714e-05 1.5 1.7061383928571428e-05 0.0 1.706361607142857e-05 0.0 1.7064174107142855e-05 1.5 1.7078683035714283e-05 1.5 1.707924107142857e-05 0.0 1.7081473214285714e-05 0.0 1.7082031249999997e-05 1.5 1.7096540178571426e-05 1.5 1.7097098214285713e-05 0.0 1.7099330357142856e-05 0.0 1.7099888392857143e-05 1.5 1.711439732142857e-05 1.5 1.7114955357142855e-05 0.0 1.71171875e-05 0.0 1.7117745535714285e-05 1.5 1.7132254464285714e-05 1.5 1.7132812499999997e-05 0.0 1.713504464285714e-05 0.0 1.7135602678571428e-05 1.5 1.7150111607142856e-05 1.5 1.7150669642857143e-05 0.0 1.7152901785714283e-05 0.0 1.715345982142857e-05 1.5 1.716796875e-05 1.5 1.7168526785714285e-05 0.0 1.717075892857143e-05 0.0 1.7171316964285712e-05 1.5 1.718582589285714e-05 1.5 1.7186383928571428e-05 0.0 1.718861607142857e-05 0.0 1.7189174107142855e-05 1.5 1.7203125e-05 1.5 1.7203683035714283e-05 0.0 1.720703125e-05 0.0 1.7207589285714284e-05 1.5 1.7220982142857142e-05 1.5 1.722154017857143e-05 0.0 1.7224888392857143e-05 0.0 1.7225446428571426e-05 1.5 1.7238839285714284e-05 1.5 1.723939732142857e-05 0.0 1.7242745535714285e-05 0.0 1.724330357142857e-05 1.5 1.7256696428571427e-05 1.5 1.7257254464285713e-05 0.0 1.7260602678571427e-05 0.0 1.7261160714285714e-05 1.5 1.727455357142857e-05 1.5 1.7275111607142856e-05 0.0 1.727845982142857e-05 0.0 1.7279017857142856e-05 1.5 1.7292410714285715e-05 1.5 1.7292968749999998e-05 0.0 1.7296316964285712e-05 0.0 1.7296875e-05 1.5 1.7310267857142857e-05 1.5 1.731082589285714e-05 0.0 1.7314174107142858e-05 0.0 1.731473214285714e-05 1.5 1.7328125e-05 1.5 1.7328683035714286e-05 0.0 1.733203125e-05 0.0 1.7332589285714283e-05 1.5 1.7345982142857142e-05 1.5 1.734654017857143e-05 0.0 1.7349888392857142e-05 0.0 1.735044642857143e-05 1.5 1.7363839285714284e-05 1.5 1.736439732142857e-05 0.0 1.7367745535714285e-05 0.0 1.736830357142857e-05 1.5 1.7381696428571426e-05 1.5 1.7382254464285713e-05 0.0 1.7385602678571427e-05 0.0 1.7386160714285714e-05 1.5 1.7398995535714285e-05 1.5 1.739955357142857e-05 0.0 1.7404017857142856e-05 0.0 1.7404575892857143e-05 1.5 1.7416852678571428e-05 1.5 1.7417410714285714e-05 0.0 1.7421874999999998e-05 0.0 1.7422433035714285e-05 1.5 1.743470982142857e-05 1.5 1.7435267857142857e-05 0.0 1.743973214285714e-05 0.0 1.7440290178571427e-05 1.5 1.7452566964285712e-05 1.5 1.7453125e-05 0.0 1.7457589285714283e-05 0.0 1.745814732142857e-05 1.5 1.7470424107142855e-05 1.5 1.747098214285714e-05 0.0 1.747544642857143e-05 0.0 1.7476004464285712e-05 1.5 1.748828125e-05 1.5 1.7488839285714284e-05 0.0 1.749330357142857e-05 0.0 1.7493861607142854e-05 1.5 1.7506138392857143e-05 1.5 1.7506696428571426e-05 0.0 1.7511160714285713e-05 0.0 1.751171875e-05 1.5 1.7523995535714285e-05 1.5 1.7524553571428572e-05 0.0 1.7529017857142856e-05 0.0 1.7529575892857142e-05 1.5 1.7541852678571427e-05 1.5 1.7542410714285714e-05 0.0 1.7546874999999998e-05 0.0 1.7547433035714285e-05 1.5 1.755970982142857e-05 1.5 1.7560267857142856e-05 0.0 1.756473214285714e-05 0.0 1.7565290178571427e-05 1.5 1.757700892857143e-05 1.5 1.7577566964285712e-05 0.0 1.758314732142857e-05 0.0 1.7583705357142856e-05 1.5 1.759486607142857e-05 1.5 1.7595424107142854e-05 0.0 1.760100446428571e-05 0.0 1.76015625e-05 1.5 1.7612723214285713e-05 1.5 1.761328125e-05 0.0 1.7618861607142857e-05 0.0 1.761941964285714e-05 1.5 1.7630580357142856e-05 1.5 1.7631138392857142e-05 0.0 1.763671875e-05 0.0 1.7637276785714283e-05 1.5 1.7648437499999998e-05 1.5 1.7648995535714285e-05 0.0 1.7654575892857142e-05 0.0 1.765513392857143e-05 1.5 1.766629464285714e-05 1.5 1.7666852678571427e-05 0.0 1.7672433035714284e-05 0.0 1.767299107142857e-05 1.5 1.7684151785714286e-05 1.5 1.768470982142857e-05 0.0 1.7690290178571427e-05 0.0 1.7690848214285713e-05 1.5 1.7702008928571428e-05 1.5 1.770256696428571e-05 0.0 1.770814732142857e-05 0.0 1.7708705357142856e-05 1.5 1.771986607142857e-05 1.5 1.7720424107142857e-05 0.0 1.7726004464285715e-05 0.0 1.7726562499999998e-05 1.5 1.7737165178571426e-05 1.5 1.7737723214285713e-05 0.0 1.774441964285714e-05 0.0 1.7744977678571427e-05 1.5 1.7755022321428572e-05 1.5 1.7755580357142855e-05 0.0 1.7762276785714286e-05 0.0 1.776283482142857e-05 1.5 1.7772879464285714e-05 1.5 1.7773437499999997e-05 0.0 1.778013392857143e-05 0.0 1.7780691964285712e-05 1.5 1.7790736607142856e-05 1.5 1.7791294642857143e-05 0.0 1.779799107142857e-05 0.0 1.7798549107142857e-05 1.5 1.780859375e-05 1.5 1.7809151785714286e-05 0.0 1.7815848214285713e-05 0.0 1.781640625e-05 1.5 1.782645089285714e-05 1.5 1.7827008928571428e-05 0.0 1.7833705357142855e-05 0.0 1.7834263392857142e-05 1.5 1.7844308035714283e-05 1.5 1.784486607142857e-05 0.0 1.7851562499999998e-05 0.0 1.7852120535714284e-05 1.5 1.7862165178571426e-05 1.5 1.7862723214285712e-05 0.0 1.786941964285714e-05 0.0 1.7869977678571427e-05 1.5 1.788002232142857e-05 1.5 1.7880580357142855e-05 0.0 1.7887276785714286e-05 0.0 1.788783482142857e-05 1.5 1.7897321428571427e-05 1.5 1.7897879464285714e-05 0.0 1.790569196428571e-05 0.0 1.7906249999999998e-05 1.5 1.791517857142857e-05 1.5 1.7915736607142856e-05 0.0 1.7923549107142857e-05 0.0 1.792410714285714e-05 1.5 1.793303571428571e-05 1.5 1.793359375e-05 0.0 1.794140625e-05 0.0 1.7941964285714283e-05 1.5 1.7950892857142857e-05 1.5 1.795145089285714e-05 0.0 1.7959263392857142e-05 0.0 1.795982142857143e-05 1.5 1.796875e-05 1.5 1.7969308035714283e-05 0.0 1.7977120535714284e-05 0.0 1.797767857142857e-05 1.5 1.7986607142857142e-05 1.5 1.798716517857143e-05 0.0 1.7994977678571426e-05 0.0 1.7995535714285713e-05 1.5 1.8004464285714284e-05 1.5 1.800502232142857e-05 0.0 1.801283482142857e-05 0.0 1.8013392857142856e-05 1.5 1.8022321428571427e-05 1.5 1.8022879464285713e-05 0.0 1.8030691964285714e-05 0.0 1.8031249999999998e-05 1.5 1.804017857142857e-05 1.5 1.8040736607142856e-05 0.0 1.8048549107142857e-05 0.0 1.804910714285714e-05 1.5 1.8057477678571428e-05 1.5 1.805803571428571e-05 0.0 1.8066964285714286e-05 0.0 1.806752232142857e-05 1.5 1.807533482142857e-05 1.5 1.8075892857142857e-05 0.0 1.8084821428571428e-05 0.0 1.808537946428571e-05 1.5 1.8093191964285713e-05 1.5 1.809375e-05 0.0 1.810267857142857e-05 0.0 1.8103236607142857e-05 1.5 1.8111049107142855e-05 1.5 1.811160714285714e-05 0.0 1.8120535714285713e-05 0.0 1.812109375e-05 1.5 1.8128906249999997e-05 1.5 1.8129464285714284e-05 0.0 1.8138392857142855e-05 0.0 1.8138950892857142e-05 1.5 1.8146763392857143e-05 1.5 1.8147321428571426e-05 0.0 1.8156249999999997e-05 0.0 1.8156808035714284e-05 1.5 1.8164620535714285e-05 1.5 1.816517857142857e-05 0.0 1.8174107142857143e-05 0.0 1.8174665178571427e-05 1.5 1.8182477678571428e-05 1.5 1.8183035714285714e-05 0.0 1.8191964285714286e-05 0.0 1.819252232142857e-05 1.5 1.820033482142857e-05 1.5 1.8200892857142857e-05 0.0 1.8209821428571428e-05 0.0 1.8210379464285715e-05 1.5 1.821763392857143e-05 1.5 1.8218191964285712e-05 0.0 1.8228236607142857e-05 0.0 1.822879464285714e-05 1.5 1.823549107142857e-05 1.5 1.8236049107142855e-05 0.0 1.824609375e-05 0.0 1.8246651785714286e-05 1.5 1.8253348214285714e-05 1.5 1.825390625e-05 0.0 1.826395089285714e-05 0.0 1.826450892857143e-05 1.5 1.8271205357142856e-05 1.5 1.8271763392857143e-05 0.0 1.8281808035714284e-05 0.0 1.828236607142857e-05 1.5 1.8289062499999998e-05 1.5 1.8289620535714285e-05 0.0 1.8299665178571426e-05 0.0 1.8300223214285713e-05 1.5 1.830691964285714e-05 1.5 1.8307477678571427e-05 0.0 1.831752232142857e-05 0.0 1.8318080357142855e-05 1.5 1.8324776785714283e-05 1.5 1.832533482142857e-05 0.0 1.8335379464285714e-05 0.0 1.8335937499999998e-05 1.5 1.834263392857143e-05 1.5 1.8343191964285712e-05 0.0 1.8353236607142857e-05 0.0 1.835379464285714e-05 1.5 1.836049107142857e-05 1.5 1.8361049107142854e-05 0.0 1.837109375e-05 0.0 1.8371651785714286e-05 1.5 1.8378348214285713e-05 1.5 1.837890625e-05 0.0 1.8389508928571428e-05 0.0 1.839006696428571e-05 1.5 1.839564732142857e-05 1.5 1.8396205357142855e-05 0.0 1.840736607142857e-05 0.0 1.8407924107142857e-05 1.5 1.8413504464285714e-05 1.5 1.8414062499999998e-05 0.0 1.8425223214285713e-05 0.0 1.842578125e-05 1.5 1.8431361607142857e-05 1.5 1.843191964285714e-05 0.0 1.8443080357142855e-05 0.0 1.844363839285714e-05 1.5 1.844921875e-05 1.5 1.8449776785714286e-05 0.0 1.8460937499999997e-05 0.0 1.8461495535714284e-05 1.5 1.846707589285714e-05 1.5 1.8467633928571428e-05 0.0 1.8478794642857143e-05 0.0 1.8479352678571426e-05 1.5 1.8484933035714284e-05 1.5 1.848549107142857e-05 0.0 1.8496651785714285e-05 0.0 1.849720982142857e-05 1.5 1.8502790178571426e-05 1.5 1.8503348214285713e-05 0.0 1.8514508928571428e-05 0.0 1.8515066964285714e-05 1.5 1.8520647321428572e-05 1.5 1.8521205357142855e-05 0.0 1.853236607142857e-05 0.0 1.8532924107142857e-05 1.5 1.8538504464285714e-05 1.5 1.8539062499999997e-05 0.0 1.855078125e-05 0.0 1.8551339285714286e-05 1.5 1.855580357142857e-05 1.5 1.8556361607142856e-05 0.0 1.856863839285714e-05 0.0 1.8569196428571428e-05 1.5 1.8573660714285712e-05 1.5 1.857421875e-05 0.0 1.8586495535714284e-05 0.0 1.858705357142857e-05 1.5 1.8591517857142854e-05 1.5 1.859207589285714e-05 0.0 1.8604352678571426e-05 0.0 1.8604910714285713e-05 1.5 1.8609375e-05 1.5 1.8609933035714283e-05 0.0 1.8622209821428572e-05 0.0 1.8622767857142855e-05 1.5 1.8627232142857142e-05 1.5 1.8627790178571426e-05 0.0 1.8640066964285714e-05 0.0 1.8640624999999997e-05 1.5 1.8645089285714285e-05 1.5 1.864564732142857e-05 0.0 1.8657924107142856e-05 0.0 1.8658482142857143e-05 1.5 1.8662946428571427e-05 1.5 1.8663504464285714e-05 0.0 1.867578125e-05 0.0 1.8676339285714285e-05 1.5 1.868080357142857e-05 1.5 1.8681361607142856e-05 0.0 1.869363839285714e-05 0.0 1.8694196428571428e-05 1.5 1.869866071428571e-05 1.5 1.869921875e-05 0.0 1.8711495535714283e-05 0.0 1.871205357142857e-05 1.5 1.8716517857142857e-05 1.5 1.871707589285714e-05 0.0 1.8729910714285712e-05 0.0 1.873046875e-05 1.5 1.8733816964285713e-05 1.5 1.8734375e-05 0.0 1.8747767857142855e-05 0.0 1.874832589285714e-05 1.5 1.8751674107142855e-05 1.5 1.8752232142857142e-05 0.0 1.8765624999999997e-05 0.0 1.8766183035714284e-05 1.5 1.8769531249999998e-05 1.5 1.8770089285714284e-05 0.0 1.8783482142857143e-05 0.0 1.8784040178571426e-05 1.5 1.878738839285714e-05 1.5 1.8787946428571427e-05 0.0 1.8801339285714285e-05 0.0 1.880189732142857e-05 1.5 1.8805245535714286e-05 1.5 1.880580357142857e-05 0.0 1.8819196428571427e-05 0.0 1.8819754464285714e-05 1.5 1.8823102678571428e-05 1.5 1.882366071428571e-05 0.0 1.883705357142857e-05 0.0 1.8837611607142856e-05 1.5 1.884095982142857e-05 1.5 1.8841517857142857e-05 0.0 1.8854910714285712e-05 0.0 1.885546875e-05 1.5 1.8858816964285713e-05 1.5 1.8859375e-05 0.0 1.8872767857142854e-05 0.0 1.887332589285714e-05 1.5 1.8876674107142855e-05 1.5 1.887723214285714e-05 0.0 1.8890625e-05 0.0 1.8891183035714283e-05 1.5 1.8894531249999997e-05 1.5 1.8895089285714284e-05 0.0 1.8908482142857142e-05 0.0 1.8909040178571426e-05 1.5 1.8912388392857143e-05 1.5 1.8912946428571426e-05 0.0 1.892689732142857e-05 0.0 1.8927455357142855e-05 1.5 1.89296875e-05 1.5 1.8930245535714285e-05 0.0 1.8944754464285714e-05 0.0 1.8945312499999997e-05 1.5 1.894754464285714e-05 1.5 1.8948102678571428e-05 0.0 1.8962611607142856e-05 0.0 1.8963169642857143e-05 1.5 1.8965401785714283e-05 1.5 1.896595982142857e-05 0.0 1.898046875e-05 0.0 1.8981026785714285e-05 1.5 1.898325892857143e-05 1.5 1.8983816964285712e-05 0.0 1.899832589285714e-05 0.0 1.8998883928571428e-05 1.5 1.900111607142857e-05 1.5 1.9001674107142855e-05 0.0 1.9016183035714283e-05 0.0 1.901674107142857e-05 1.5 1.9018973214285713e-05 1.5 1.901953125e-05 0.0 1.903404017857143e-05 0.0 1.9034598214285712e-05 1.5 1.9036830357142856e-05 1.5 1.9037388392857143e-05 0.0 1.905189732142857e-05 0.0 1.9052455357142855e-05 1.5 1.9054687499999998e-05 1.5 1.9055245535714285e-05 0.0 1.9069754464285713e-05 0.0 1.90703125e-05 1.5 1.907254464285714e-05 1.5 1.9073102678571427e-05 0.0 1.9087611607142856e-05 0.0 1.9088169642857143e-05 1.5 1.9090401785714283e-05 1.5 1.909095982142857e-05 0.0 1.9105468749999998e-05 0.0 1.9106026785714285e-05 1.5 1.910825892857143e-05 1.5 1.9108816964285712e-05 0.0 1.912332589285714e-05 0.0 1.9123883928571427e-05 1.5 1.912611607142857e-05 1.5 1.9126674107142854e-05 0.0 1.914174107142857e-05 0.0 1.9142299107142856e-05 1.5 1.9143415178571426e-05 1.5 1.9143973214285713e-05 0.0 1.9159598214285712e-05 0.0 1.916015625e-05 1.5 1.916127232142857e-05 1.5 1.9161830357142855e-05 0.0 1.9177455357142854e-05 0.0 1.917801339285714e-05 1.5 1.9179129464285714e-05 1.5 1.9179687499999998e-05 0.0 1.91953125e-05 0.0 1.9195870535714283e-05 1.5 1.9196986607142857e-05 1.5 1.919754464285714e-05 0.0 1.9213169642857142e-05 0.0 1.9213727678571426e-05 1.5 1.921484375e-05 1.5 1.9215401785714286e-05 0.0 1.9231026785714285e-05 0.0 1.923158482142857e-05 1.5 1.923270089285714e-05 1.5 1.9233258928571428e-05 0.0 1.9248883928571427e-05 0.0 1.9249441964285714e-05 1.5 1.9250558035714284e-05 1.5 1.925111607142857e-05 0.0 1.926674107142857e-05 0.0 1.9267299107142856e-05 1.5 1.9268415178571426e-05 1.5 1.9268973214285713e-05 0.0 1.928459821428571e-05 0.0 1.9285156249999998e-05 1.5 1.928627232142857e-05 1.5 1.9286830357142855e-05 0.0 1.9302455357142857e-05 0.0 1.930301339285714e-05 1.5 1.9304129464285714e-05 1.5 1.9304687499999997e-05 0.0 1.93203125e-05 0.0 1.9320870535714283e-05 1.5 1.9321986607142856e-05 1.5 1.9322544642857143e-05 0.0 1.9338169642857142e-05 0.0 1.933872767857143e-05 1.5 1.933984375e-05 1.5 1.9340401785714285e-05 0.0 1.9356026785714284e-05 0.0 1.935658482142857e-05 1.5 1.935770089285714e-05 1.5 1.9358258928571428e-05 0.0 1.9373883928571426e-05 0.0 1.9374441964285713e-05 1.5 1.9375558035714283e-05 1.5 1.937611607142857e-05 0.0 1.939174107142857e-05 0.0 1.9392299107142856e-05 1.5 1.9393415178571426e-05 1.5 1.9393973214285712e-05 0.0 1.9409598214285715e-05 0.0 1.9410156249999998e-05 1.5 1.941127232142857e-05 1.5 1.9411830357142855e-05 0.0 1.942801339285714e-05 0.0 1.9428571428571427e-05 1.5 1.9428571428571427e-05 1.5 1.9429129464285714e-05 0.0 1.9445870535714286e-05 0.0 1.944642857142857e-05 1.5 1.944642857142857e-05 1.5 1.9446986607142856e-05 0.0 1.9463727678571428e-05 0.0 1.946428571428571e-05 1.5 1.946428571428571e-05 1.5 1.946484375e-05 0.0 1.948158482142857e-05 0.0 1.9482142857142857e-05 1.5 1.9482142857142857e-05 1.5 1.948270089285714e-05 0.0 1.9499441964285713e-05 0.0 1.95e-05 1.5 1.95e-05 1.5 1.9500558035714283e-05 0.0 1.9517299107142855e-05 0.0 1.9517857142857142e-05 1.5 1.9517857142857142e-05 1.5 1.951841517857143e-05 0.0 1.9535156249999998e-05 0.0 1.9535714285714284e-05 1.5 1.9535714285714284e-05 1.5 1.953627232142857e-05 0.0 1.955301339285714e-05 0.0 1.9553571428571427e-05 1.5 1.9553571428571427e-05 1.5 1.9554129464285713e-05 0.0 1.9570870535714286e-05 0.0 1.957142857142857e-05 1.5 1.957142857142857e-05 1.5 1.9571986607142856e-05 0.0 1.9588727678571428e-05 0.0 1.958928571428571e-05 1.5 1.958928571428571e-05 1.5 1.9589843749999998e-05 0.0 1.960658482142857e-05 0.0 1.9607142857142857e-05 1.5 1.9607142857142857e-05 1.5 1.960770089285714e-05 0.0 1.9624441964285713e-05 0.0 1.9625e-05 1.5 1.9625e-05 1.5 1.9625558035714283e-05 0.0 1.9642299107142855e-05 0.0 1.964285714285714e-05 1.5 1.964285714285714e-05 1.5 1.964341517857143e-05 0.0 1.9660156249999997e-05 0.0 1.9660714285714284e-05 1.5 1.9660714285714284e-05 1.5 1.966127232142857e-05 0.0 1.9678013392857143e-05 0.0 1.9678571428571426e-05 1.5 1.9678571428571426e-05 1.5 1.9679129464285713e-05 0.0 1.9695870535714285e-05 0.0 1.969642857142857e-05 1.5 1.969642857142857e-05 1.5 1.9696986607142855e-05 0.0 1.9713727678571428e-05 0.0 1.9714285714285714e-05 1.5 1.9714285714285714e-05 1.5 1.9714843749999998e-05 0.0 1.973158482142857e-05 0.0 1.9732142857142857e-05 1.5 1.9732142857142857e-05 1.5 1.973270089285714e-05 0.0 1.9749441964285712e-05 0.0 1.975e-05 1.5 1.975e-05 1.5 1.9750558035714286e-05 0.0 1.9767299107142855e-05 0.0 1.976785714285714e-05 1.5 1.976785714285714e-05 1.5 1.9768415178571428e-05 0.0 1.978515625e-05 0.0 1.9785714285714284e-05 1.5 1.9785714285714284e-05 1.5 1.978627232142857e-05 0.0 1.9803013392857143e-05 0.0 1.9803571428571426e-05 1.5 1.9803571428571426e-05 1.5 1.9804129464285713e-05 0.0 1.9820870535714285e-05 0.0 1.982142857142857e-05 1.5 1.982142857142857e-05 1.5 1.9821986607142855e-05 0.0 1.9838727678571427e-05 0.0 1.9839285714285714e-05 1.5 1.9839285714285714e-05 1.5 1.9839843749999997e-05 0.0 1.985658482142857e-05 0.0 1.9857142857142856e-05 1.5 1.9857142857142856e-05 1.5 1.9857700892857143e-05 0.0 1.9874441964285712e-05 0.0 1.9875e-05 1.5 1.9875e-05 1.5 1.9875558035714285e-05 0.0 1.9892299107142854e-05 0.0 1.989285714285714e-05 1.5 1.989285714285714e-05 1.5 1.9893415178571428e-05 0.0 1.991015625e-05 0.0 1.9910714285714283e-05 1.5 1.9910714285714283e-05 1.5 1.991127232142857e-05 0.0 1.9928013392857142e-05 0.0 1.9928571428571426e-05 1.5 1.9928571428571426e-05 1.5 1.9929129464285712e-05 0.0 1.9945870535714285e-05 0.0 1.994642857142857e-05 1.5 1.994642857142857e-05 1.5 1.9946986607142855e-05 0.0 1.9963727678571427e-05 0.0 1.9964285714285714e-05 1.5 1.9964285714285714e-05 1.5 1.9964843749999997e-05 0.0 1.998158482142857e-05 0.0 1.9982142857142856e-05 1.5 1.9982142857142856e-05 1.5 1.9982700892857143e-05 0.0 1.999944196428571e-05 0.0 1.9999999999999998e-05 1.5 1.9999999999999998e-05 1.5 2.0000558035714285e-05 0.0 2.0017299107142857e-05 0.0 2.001785714285714e-05 1.5 2.001785714285714e-05 1.5 2.0018415178571427e-05 0.0 2.003515625e-05 0.0 2.0035714285714283e-05 1.5 2.0035714285714283e-05 1.5 2.003627232142857e-05 0.0 2.0053013392857142e-05 0.0 2.005357142857143e-05 1.5 2.005357142857143e-05 1.5 2.0054129464285712e-05 0.0 2.0070870535714284e-05 0.0 2.007142857142857e-05 1.5 2.007142857142857e-05 1.5 2.0071986607142854e-05 0.0 2.0088727678571426e-05 0.0 2.0089285714285713e-05 1.5 2.0089285714285713e-05 1.5 2.008984375e-05 0.0 2.010658482142857e-05 0.0 2.0107142857142856e-05 1.5 2.0107142857142856e-05 1.5 2.0107700892857142e-05 0.0 2.0124441964285715e-05 0.0 2.0124999999999998e-05 1.5 2.0124999999999998e-05 1.5 2.0125558035714285e-05 0.0 2.0142299107142857e-05 0.0 2.014285714285714e-05 1.5 2.014285714285714e-05 1.5 2.0143415178571427e-05 0.0 2.016015625e-05 0.0 2.0160714285714286e-05 1.5 2.0160714285714286e-05 1.5 2.016127232142857e-05 0.0 2.017801339285714e-05 0.0 2.0178571428571428e-05 1.5 2.0178571428571428e-05 1.5 2.017912946428571e-05 0.0 2.0195870535714284e-05 0.0 2.019642857142857e-05 1.5 2.019642857142857e-05 1.5 2.0196986607142857e-05 0.0 2.0213727678571426e-05 0.0 2.0214285714285713e-05 1.5 2.0214285714285713e-05 1.5 2.021484375e-05 0.0 2.023158482142857e-05 0.0 2.0232142857142855e-05 1.5 2.0232142857142855e-05 1.5 2.0232700892857142e-05 0.0 2.0249441964285714e-05 0.0 2.0249999999999998e-05 1.5 2.0249999999999998e-05 1.5 2.0250558035714284e-05 0.0 2.0267299107142857e-05 0.0 2.026785714285714e-05 1.5 2.026785714285714e-05 1.5 2.0268415178571427e-05 0.0 2.028515625e-05 0.0 2.0285714285714286e-05 1.5 2.0285714285714286e-05 1.5 2.028627232142857e-05 0.0 2.030301339285714e-05 0.0 2.0303571428571428e-05 1.5 2.0303571428571428e-05 1.5 2.030412946428571e-05 0.0 2.0320870535714283e-05 0.0 2.032142857142857e-05 1.5 2.032142857142857e-05 1.5 2.0321986607142857e-05 0.0 2.0338727678571426e-05 0.0 2.0339285714285713e-05 1.5 2.0339285714285713e-05 1.5 2.033984375e-05 0.0 2.035658482142857e-05 0.0 2.0357142857142855e-05 1.5 2.0357142857142855e-05 1.5 2.035770089285714e-05 0.0 2.0374441964285714e-05 0.0 2.0374999999999997e-05 1.5 2.0374999999999997e-05 1.5 2.0375558035714284e-05 0.0 2.0392299107142856e-05 0.0 2.0392857142857143e-05 1.5 2.0392857142857143e-05 1.5 2.0393415178571426e-05 0.0 2.041015625e-05 0.0 2.0410714285714285e-05 1.5 2.0410714285714285e-05 1.5 2.041127232142857e-05 0.0 2.042801339285714e-05 0.0 2.0428571428571428e-05 1.5 2.0428571428571428e-05 1.5 2.0429129464285714e-05 0.0 2.0445870535714283e-05 0.0 2.044642857142857e-05 1.5 2.044642857142857e-05 1.5 2.0446986607142857e-05 0.0 2.0463727678571425e-05 0.0 2.0464285714285712e-05 1.5 2.0464285714285712e-05 1.5 2.046484375e-05 0.0 2.048158482142857e-05 0.0 2.0482142857142855e-05 1.5 2.0482142857142855e-05 1.5 2.048270089285714e-05 0.0 2.0499441964285713e-05 0.0 2.0499999999999997e-05 1.5 2.0499999999999997e-05 1.5 2.0500558035714284e-05 0.0 2.0517299107142856e-05 0.0 2.0517857142857143e-05 1.5 2.0517857142857143e-05 1.5 2.0518415178571426e-05 0.0 2.0535156249999998e-05 0.0 2.0535714285714285e-05 1.5 2.0535714285714285e-05 1.5 2.053627232142857e-05 0.0 2.055301339285714e-05 0.0 2.0553571428571427e-05 1.5 2.0553571428571427e-05 1.5 2.0554129464285714e-05 0.0 2.0570870535714283e-05 0.0 2.057142857142857e-05 1.5 2.057142857142857e-05 1.5 2.0571986607142856e-05 0.0 2.058872767857143e-05 0.0 2.0589285714285712e-05 1.5 2.0589285714285712e-05 1.5 2.058984375e-05 0.0 2.060658482142857e-05 0.0 2.0607142857142854e-05 1.5 2.0607142857142854e-05 1.5 2.060770089285714e-05 0.0 2.0624441964285713e-05 0.0 2.0625e-05 1.5 2.0625e-05 1.5 2.0625558035714283e-05 0.0 2.0642299107142855e-05 0.0 2.0642857142857142e-05 1.5 2.0642857142857142e-05 1.5 2.0643415178571426e-05 0.0 2.0660156249999998e-05 0.0 2.0660714285714285e-05 1.5 2.0660714285714285e-05 1.5 2.066127232142857e-05 0.0 2.067801339285714e-05 0.0 2.0678571428571427e-05 1.5 2.0678571428571427e-05 1.5 2.0679129464285714e-05 0.0 2.0695870535714286e-05 0.0 2.069642857142857e-05 1.5 2.069642857142857e-05 1.5 2.0696986607142856e-05 0.0 2.071316964285714e-05 0.0 2.0713727678571428e-05 1.5 2.0714843749999998e-05 1.5 2.0715401785714285e-05 0.0 2.0731026785714284e-05 0.0 2.073158482142857e-05 1.5 2.073270089285714e-05 1.5 2.0733258928571427e-05 0.0 2.0748883928571426e-05 0.0 2.0749441964285713e-05 1.5 2.0750558035714283e-05 1.5 2.075111607142857e-05 0.0 2.076674107142857e-05 0.0 2.0767299107142855e-05 1.5 2.076841517857143e-05 1.5 2.0768973214285712e-05 0.0 2.0784598214285714e-05 0.0 2.0785156249999997e-05 1.5 2.078627232142857e-05 1.5 2.0786830357142854e-05 0.0 2.0802455357142856e-05 0.0 2.080301339285714e-05 1.5 2.0804129464285713e-05 1.5 2.08046875e-05 0.0 2.08203125e-05 0.0 2.0820870535714285e-05 1.5 2.0821986607142856e-05 1.5 2.0822544642857142e-05 0.0 2.083816964285714e-05 0.0 2.0838727678571428e-05 1.5 2.0839843749999998e-05 1.5 2.0840401785714285e-05 0.0 2.0856026785714283e-05 0.0 2.085658482142857e-05 1.5 2.085770089285714e-05 1.5 2.0858258928571427e-05 0.0 2.0873883928571426e-05 0.0 2.0874441964285712e-05 1.5 2.0875558035714283e-05 1.5 2.087611607142857e-05 0.0 2.089174107142857e-05 0.0 2.0892299107142855e-05 1.5 2.0893415178571428e-05 1.5 2.089397321428571e-05 0.0 2.0909598214285714e-05 0.0 2.0910156249999997e-05 1.5 2.091127232142857e-05 1.5 2.0911830357142854e-05 0.0 2.0927455357142856e-05 0.0 2.0928013392857143e-05 1.5 2.0929129464285713e-05 1.5 2.09296875e-05 0.0 2.09453125e-05 0.0 2.0945870535714285e-05 1.5 2.0946986607142855e-05 1.5 2.0947544642857142e-05 0.0 2.096316964285714e-05 0.0 2.0963727678571427e-05 1.5 2.0964843749999998e-05 1.5 2.0965401785714284e-05 0.0 2.0981026785714283e-05 0.0 2.098158482142857e-05 1.5 2.098270089285714e-05 1.5 2.0983258928571427e-05 0.0 2.0998325892857142e-05 0.0 2.099888392857143e-05 1.5 2.100111607142857e-05 1.5 2.1001674107142856e-05 0.0 2.1016183035714284e-05 0.0 2.101674107142857e-05 1.5 2.101897321428571e-05 1.5 2.1019531249999998e-05 0.0 2.1034040178571427e-05 0.0 2.1034598214285713e-05 1.5 2.1036830357142857e-05 1.5 2.103738839285714e-05 0.0 2.105189732142857e-05 0.0 2.1052455357142856e-05 1.5 2.10546875e-05 1.5 2.1055245535714283e-05 0.0 2.106975446428571e-05 0.0 2.1070312499999998e-05 1.5 2.107254464285714e-05 1.5 2.107310267857143e-05 0.0 2.1087611607142857e-05 0.0 2.108816964285714e-05 1.5 2.1090401785714284e-05 1.5 2.109095982142857e-05 0.0 2.110546875e-05 0.0 2.1106026785714283e-05 1.5 2.1108258928571426e-05 1.5 2.1108816964285713e-05 0.0 2.112332589285714e-05 0.0 2.112388392857143e-05 1.5 2.112611607142857e-05 1.5 2.1126674107142855e-05 0.0 2.1141183035714284e-05 0.0 2.114174107142857e-05 1.5 2.1143973214285714e-05 1.5 2.1144531249999998e-05 0.0 2.1159040178571426e-05 0.0 2.1159598214285713e-05 1.5 2.1161830357142857e-05 1.5 2.116238839285714e-05 0.0 2.117689732142857e-05 0.0 2.1177455357142855e-05 1.5 2.11796875e-05 1.5 2.1180245535714286e-05 0.0 2.1194754464285714e-05 0.0 2.1195312499999998e-05 1.5 2.119754464285714e-05 1.5 2.1198102678571428e-05 0.0 2.121205357142857e-05 0.0 2.1212611607142857e-05 1.5 2.121595982142857e-05 1.5 2.1216517857142857e-05 0.0 2.1229910714285712e-05 0.0 2.123046875e-05 1.5 2.1233816964285713e-05 1.5 2.1234375e-05 0.0 2.1247767857142855e-05 0.0 2.124832589285714e-05 1.5 2.1251674107142855e-05 1.5 2.1252232142857142e-05 0.0 2.1265624999999997e-05 0.0 2.1266183035714284e-05 1.5 2.1269531249999997e-05 1.5 2.1270089285714284e-05 0.0 2.1283482142857143e-05 0.0 2.1284040178571426e-05 1.5 2.128738839285714e-05 1.5 2.1287946428571426e-05 0.0 2.1301339285714285e-05 0.0 2.1301897321428568e-05 1.5 2.1305245535714285e-05 1.5 2.130580357142857e-05 0.0 2.1319196428571427e-05 0.0 2.1319754464285714e-05 1.5 2.1323102678571428e-05 1.5 2.132366071428571e-05 0.0 2.133705357142857e-05 0.0 2.1337611607142856e-05 1.5 2.134095982142857e-05 1.5 2.1341517857142857e-05 0.0 2.1354910714285712e-05 0.0 2.135546875e-05 1.5 2.1358816964285712e-05 1.5 2.1359375e-05 0.0 2.1372767857142854e-05 0.0 2.137332589285714e-05 1.5 2.1376674107142855e-05 1.5 2.137723214285714e-05 0.0 2.1390625e-05 0.0 2.1391183035714283e-05 1.5 2.1394531249999997e-05 1.5 2.1395089285714284e-05 0.0 2.1407924107142855e-05 0.0 2.1408482142857142e-05 1.5 2.1412946428571426e-05 1.5 2.1413504464285713e-05 0.0 2.1425781249999998e-05 0.0 2.1426339285714285e-05 1.5 2.143080357142857e-05 1.5 2.1431361607142855e-05 0.0 2.144363839285714e-05 0.0 2.1444196428571427e-05 1.5 2.1448660714285714e-05 1.5 2.1449218749999997e-05 0.0 2.1461495535714286e-05 0.0 2.146205357142857e-05 1.5 2.1466517857142856e-05 1.5 2.146707589285714e-05 0.0 2.1479352678571428e-05 0.0 2.147991071428571e-05 1.5 2.1484375e-05 1.5 2.1484933035714286e-05 0.0 2.149720982142857e-05 0.0 2.1497767857142857e-05 1.5 2.150223214285714e-05 1.5 2.1502790178571428e-05 0.0 2.1515066964285713e-05 0.0 2.1515625e-05 1.5 2.1520089285714283e-05 1.5 2.152064732142857e-05 0.0 2.1532924107142855e-05 0.0 2.1533482142857142e-05 1.5 2.1537946428571426e-05 1.5 2.1538504464285712e-05 0.0 2.1550781249999997e-05 0.0 2.1551339285714284e-05 1.5 2.155580357142857e-05 1.5 2.1556361607142855e-05 0.0 2.156863839285714e-05 0.0 2.1569196428571426e-05 1.5 2.1573660714285714e-05 1.5 2.1574218749999997e-05 0.0 2.15859375e-05 0.0 2.1586495535714285e-05 1.5 2.1592075892857143e-05 1.5 2.1592633928571426e-05 0.0 2.160379464285714e-05 0.0 2.1604352678571428e-05 1.5 2.1609933035714285e-05 1.5 2.161049107142857e-05 0.0 2.1621651785714283e-05 0.0 2.162220982142857e-05 1.5 2.1627790178571427e-05 1.5 2.1628348214285714e-05 0.0 2.1639508928571426e-05 0.0 2.1640066964285712e-05 1.5 2.164564732142857e-05 1.5 2.1646205357142857e-05 0.0 2.165736607142857e-05 0.0 2.1657924107142855e-05 1.5 2.1663504464285712e-05 1.5 2.16640625e-05 0.0 2.1675223214285714e-05 0.0 2.1675781249999997e-05 1.5 2.1681361607142854e-05 1.5 2.168191964285714e-05 0.0 2.1693080357142856e-05 0.0 2.1693638392857143e-05 1.5 2.1699218749999997e-05 1.5 2.1699776785714284e-05 0.0 2.17109375e-05 0.0 2.1711495535714285e-05 1.5 2.1717075892857142e-05 1.5 2.1717633928571426e-05 0.0 2.172879464285714e-05 0.0 2.1729352678571427e-05 1.5 2.1734933035714285e-05 1.5 2.1735491071428568e-05 0.0 2.1746651785714283e-05 0.0 2.174720982142857e-05 1.5 2.1753348214285714e-05 1.5 2.1753906249999997e-05 0.0 2.1763950892857142e-05 0.0 2.176450892857143e-05 1.5 2.1771205357142856e-05 1.5 2.1771763392857143e-05 0.0 2.1781808035714284e-05 0.0 2.178236607142857e-05 1.5 2.17890625e-05 1.5 2.1789620535714285e-05 0.0 2.1799665178571427e-05 0.0 2.1800223214285713e-05 1.5 2.180691964285714e-05 1.5 2.1807477678571428e-05 0.0 2.181752232142857e-05 0.0 2.1818080357142856e-05 1.5 2.1824776785714283e-05 1.5 2.182533482142857e-05 0.0 2.183537946428571e-05 0.0 2.1835937499999998e-05 1.5 2.1842633928571426e-05 1.5 2.1843191964285712e-05 0.0 2.1853236607142857e-05 0.0 2.185379464285714e-05 1.5 2.186049107142857e-05 1.5 2.1861049107142855e-05 0.0 2.187109375e-05 0.0 2.1871651785714283e-05 1.5 2.1878348214285714e-05 1.5 2.1878906249999997e-05 0.0 2.188895089285714e-05 0.0 2.188950892857143e-05 1.5 2.1896205357142856e-05 1.5 2.1896763392857143e-05 0.0 2.1906808035714284e-05 0.0 2.190736607142857e-05 1.5 2.1914620535714285e-05 1.5 2.191517857142857e-05 0.0 2.1924107142857143e-05 0.0 2.1924665178571426e-05 1.5 2.1932477678571427e-05 1.5 2.1933035714285714e-05 0.0 2.1941964285714285e-05 0.0 2.194252232142857e-05 1.5 2.195033482142857e-05 1.5 2.1950892857142856e-05 0.0 2.1959821428571428e-05 0.0 2.1960379464285714e-05 1.5 2.1968191964285712e-05 1.5 2.196875e-05 0.0 2.197767857142857e-05 0.0 2.1978236607142857e-05 1.5 2.1986049107142854e-05 1.5 2.198660714285714e-05 0.0 2.1995535714285712e-05 0.0 2.199609375e-05 1.5 2.200390625e-05 1.5 2.2004464285714283e-05 0.0 2.2013392857142854e-05 0.0 2.201395089285714e-05 1.5 2.2021763392857142e-05 1.5 2.2022321428571426e-05 0.0 2.2031249999999997e-05 0.0 2.2031808035714284e-05 1.5 2.2039620535714285e-05 1.5 2.204017857142857e-05 0.0 2.2049107142857143e-05 0.0 2.2049665178571426e-05 1.5 2.2057477678571427e-05 1.5 2.2058035714285714e-05 0.0 2.2066964285714285e-05 0.0 2.2067522321428568e-05 1.5 2.2075892857142856e-05 1.5 2.2076450892857143e-05 0.0 2.208426339285714e-05 0.0 2.2084821428571427e-05 1.5 2.209375e-05 1.5 2.2094308035714285e-05 0.0 2.2102120535714283e-05 0.0 2.210267857142857e-05 1.5 2.211160714285714e-05 1.5 2.2112165178571427e-05 0.0 2.211997767857143e-05 0.0 2.2120535714285712e-05 1.5 2.2129464285714283e-05 1.5 2.213002232142857e-05 0.0 2.213783482142857e-05 0.0 2.2138392857142854e-05 1.5 2.214732142857143e-05 1.5 2.2147879464285712e-05 0.0 2.2155691964285713e-05 0.0 2.215625e-05 1.5 2.216517857142857e-05 1.5 2.2165736607142854e-05 0.0 2.2173549107142855e-05 0.0 2.2174107142857142e-05 1.5 2.2183035714285713e-05 1.5 2.218359375e-05 0.0 2.2191406249999998e-05 0.0 2.2191964285714284e-05 1.5 2.2200892857142856e-05 1.5 2.2201450892857142e-05 0.0 2.220926339285714e-05 0.0 2.2209821428571427e-05 1.5 2.2218749999999998e-05 1.5 2.2219308035714285e-05 0.0 2.2227120535714286e-05 0.0 2.222767857142857e-05 1.5 2.2237165178571427e-05 1.5 2.2237723214285714e-05 0.0 2.224441964285714e-05 0.0 2.2244977678571428e-05 1.5 2.225502232142857e-05 1.5 2.2255580357142856e-05 0.0 2.2262276785714284e-05 0.0 2.226283482142857e-05 1.5 2.2272879464285712e-05 1.5 2.22734375e-05 0.0 2.2280133928571426e-05 0.0 2.2280691964285713e-05 1.5 2.2290736607142854e-05 1.5 2.229129464285714e-05 0.0 2.2297991071428568e-05 0.0 2.2298549107142855e-05 1.5 2.230859375e-05 1.5 2.2309151785714283e-05 0.0 2.2315848214285714e-05 0.0 2.2316406249999997e-05 1.5 2.2326450892857142e-05 1.5 2.2327008928571425e-05 0.0 2.2333705357142856e-05 0.0 2.233426339285714e-05 1.5 2.2344308035714284e-05 1.5 2.234486607142857e-05 0.0 2.23515625e-05 0.0 2.2352120535714285e-05 1.5 2.2362165178571427e-05 1.5 2.2362723214285713e-05 0.0 2.236941964285714e-05 0.0 2.2369977678571428e-05 1.5 2.238002232142857e-05 1.5 2.2380580357142856e-05 0.0 2.2387276785714283e-05 0.0 2.238783482142857e-05 1.5 2.2398437499999998e-05 1.5 2.2398995535714285e-05 0.0 2.2404575892857142e-05 0.0 2.2405133928571426e-05 1.5 2.241629464285714e-05 1.5 2.2416852678571427e-05 0.0 2.2422433035714285e-05 0.0 2.242299107142857e-05 1.5 2.2434151785714283e-05 1.5 2.243470982142857e-05 0.0 2.2440290178571427e-05 0.0 2.2440848214285714e-05 1.5 2.245200892857143e-05 1.5 2.2452566964285712e-05 0.0 2.245814732142857e-05 0.0 2.2458705357142856e-05 1.5 2.246986607142857e-05 1.5 2.2470424107142854e-05 0.0 2.247600446428571e-05 0.0 2.24765625e-05 1.5 2.2487723214285713e-05 1.5 2.248828125e-05 0.0 2.2493861607142854e-05 0.0 2.249441964285714e-05 1.5 2.2505580357142855e-05 1.5 2.2506138392857142e-05 0.0 2.251171875e-05 0.0 2.2512276785714283e-05 1.5 2.2523437499999998e-05 1.5 2.2523995535714285e-05 0.0 2.2529575892857142e-05 0.0 2.2530133928571425e-05 1.5 2.254129464285714e-05 1.5 2.2541852678571427e-05 0.0 2.2547433035714284e-05 0.0 2.254799107142857e-05 1.5 2.2559151785714286e-05 1.5 2.255970982142857e-05 0.0 2.256473214285714e-05 0.0 2.2565290178571427e-05 1.5 2.257756696428571e-05 1.5 2.2578124999999998e-05 0.0 2.2582589285714286e-05 0.0 2.258314732142857e-05 1.5 2.2595424107142857e-05 1.5 2.259598214285714e-05 0.0 2.2600446428571428e-05 0.0 2.260100446428571e-05 1.5 2.261328125e-05 1.5 2.2613839285714283e-05 0.0 2.261830357142857e-05 0.0 2.2618861607142857e-05 1.5 2.2631138392857142e-05 1.5 2.263169642857143e-05 0.0 2.2636160714285712e-05 0.0 2.263671875e-05 1.5 2.2648995535714284e-05 1.5 2.264955357142857e-05 0.0 2.2654017857142855e-05 0.0 2.265457589285714e-05 1.5 2.2666852678571426e-05 1.5 2.2667410714285713e-05 0.0 2.2671874999999997e-05 0.0 2.2672433035714284e-05 1.5 2.268470982142857e-05 1.5 2.2685267857142856e-05 0.0 2.2689732142857143e-05 0.0 2.2690290178571426e-05 1.5 2.270256696428571e-05 1.5 2.2703124999999998e-05 0.0 2.2707589285714285e-05 0.0 2.270814732142857e-05 1.5 2.2720424107142857e-05 1.5 2.272098214285714e-05 0.0 2.2725446428571427e-05 0.0 2.2726004464285714e-05 1.5 2.273828125e-05 1.5 2.2738839285714283e-05 0.0 2.2742745535714283e-05 0.0 2.274330357142857e-05 1.5 2.2756696428571428e-05 1.5 2.275725446428571e-05 0.0 2.2760602678571425e-05 0.0 2.2761160714285712e-05 1.5 2.277455357142857e-05 1.5 2.2775111607142854e-05 0.0 2.277845982142857e-05 0.0 2.2779017857142854e-05 1.5 2.2792410714285713e-05 1.5 2.279296875e-05 0.0 2.2796316964285713e-05 0.0 2.2796874999999997e-05 1.5 2.2810267857142855e-05 1.5 2.2810825892857142e-05 0.0 2.2814174107142856e-05 0.0 2.2814732142857142e-05 1.5 2.2828124999999998e-05 1.5 2.2828683035714284e-05 0.0 2.2832031249999998e-05 0.0 2.2832589285714285e-05 1.5 2.284598214285714e-05 1.5 2.2846540178571427e-05 0.0 2.284988839285714e-05 0.0 2.2850446428571427e-05 1.5 2.2863839285714286e-05 1.5 2.286439732142857e-05 0.0 2.2867745535714283e-05 0.0 2.286830357142857e-05 1.5 2.2881696428571428e-05 1.5 2.288225446428571e-05 0.0 2.288560267857143e-05 0.0 2.2886160714285712e-05 1.5 2.289955357142857e-05 1.5 2.2900111607142857e-05 0.0 2.290345982142857e-05 0.0 2.2904017857142854e-05 1.5 2.2917410714285713e-05 1.5 2.291796875e-05 0.0 2.2921316964285713e-05 0.0 2.2921875e-05 1.5 2.293582589285714e-05 1.5 2.293638392857143e-05 0.0 2.293861607142857e-05 0.0 2.2939174107142855e-05 1.5 2.2953683035714284e-05 1.5 2.295424107142857e-05 0.0 2.295647321428571e-05 0.0 2.2957031249999998e-05 1.5 2.2971540178571426e-05 1.5 2.2972098214285713e-05 0.0 2.2974330357142857e-05 0.0 2.297488839285714e-05 1.5 2.298939732142857e-05 1.5 2.2989955357142855e-05 0.0 2.29921875e-05 0.0 2.2992745535714286e-05 1.5 2.3007254464285714e-05 1.5 2.3007812499999998e-05 0.0 2.301004464285714e-05 0.0 2.3010602678571428e-05 1.5 2.3025111607142857e-05 1.5 2.302566964285714e-05 0.0 2.3027901785714284e-05 0.0 2.302845982142857e-05 1.5 2.304296875e-05 1.5 2.3043526785714286e-05 0.0 2.3045758928571426e-05 0.0 2.3046316964285713e-05 1.5 2.306082589285714e-05 1.5 2.3061383928571428e-05 0.0 2.3063616071428568e-05 0.0 2.3064174107142855e-05 1.5 2.3078683035714284e-05 1.5 2.307924107142857e-05 0.0 2.3081473214285714e-05 0.0 2.3082031249999997e-05 1.5 2.3096540178571426e-05 1.5 2.3097098214285713e-05 0.0 2.3099330357142856e-05 0.0 2.309988839285714e-05 1.5 2.3114397321428568e-05 1.5 2.3114955357142855e-05 0.0 2.31171875e-05 0.0 2.3117745535714285e-05 1.5 2.3132254464285714e-05 1.5 2.3132812499999997e-05 0.0 2.313504464285714e-05 0.0 2.3135602678571428e-05 1.5 2.3150111607142856e-05 1.5 2.315066964285714e-05 0.0 2.3152901785714283e-05 0.0 2.315345982142857e-05 1.5 2.3168526785714285e-05 1.5 2.316908482142857e-05 0.0 2.3170200892857142e-05 0.0 2.3170758928571426e-05 1.5 2.3186383928571428e-05 1.5 2.318694196428571e-05 0.0 2.3188058035714285e-05 0.0 2.318861607142857e-05 1.5 2.320424107142857e-05 1.5 2.3204799107142857e-05 0.0 2.3205915178571427e-05 0.0 2.3206473214285714e-05 1.5 2.3222098214285712e-05 1.5 2.322265625e-05 0.0 2.322377232142857e-05 0.0 2.3224330357142856e-05 1.5 2.3239955357142855e-05 1.5 2.324051339285714e-05 0.0 2.324162946428571e-05 0.0 2.3242187499999998e-05 1.5 2.3257812499999997e-05 1.5 2.3258370535714284e-05 0.0 2.3259486607142854e-05 0.0 2.326004464285714e-05 1.5 2.3275669642857143e-05 1.5 2.3276227678571426e-05 0.0 2.327734375e-05 0.0 2.3277901785714283e-05 1.5 2.3293526785714285e-05 1.5 2.329408482142857e-05 0.0 2.3295200892857142e-05 0.0 2.3295758928571425e-05 1.5 2.3311383928571427e-05 1.5 2.3311941964285714e-05 0.0 2.3313058035714284e-05 0.0 2.331361607142857e-05 1.5 2.332924107142857e-05 1.5 2.3329799107142856e-05 0.0 2.3330915178571427e-05 0.0 2.3331473214285713e-05 1.5 2.3347098214285712e-05 1.5 2.334765625e-05 0.0 2.334877232142857e-05 0.0 2.3349330357142856e-05 1.5 2.3364955357142854e-05 1.5 2.336551339285714e-05 0.0 2.336662946428571e-05 0.0 2.3367187499999998e-05 1.5 2.33828125e-05 1.5 2.3383370535714283e-05 0.0 2.3384486607142857e-05 0.0 2.338504464285714e-05 1.5 2.3400669642857142e-05 1.5 2.3401227678571426e-05 0.0 2.340234375e-05 0.0 2.3402901785714283e-05 1.5 2.3418526785714285e-05 1.5 2.341908482142857e-05 0.0 2.342020089285714e-05 0.0 2.3420758928571428e-05 1.5 2.3436941964285714e-05 1.5 2.3437499999999997e-05 0.0 2.3437499999999997e-05 0.0 2.3438058035714284e-05 1.5 2.3454799107142856e-05 1.5 2.3455357142857143e-05 0.0 2.3455357142857143e-05 0.0 2.3455915178571426e-05 1.5 2.347265625e-05 1.5 2.3473214285714285e-05 0.0 2.3473214285714285e-05 0.0 2.347377232142857e-05 1.5 2.349051339285714e-05 1.5 2.3491071428571427e-05 0.0 2.3491071428571427e-05 0.0 2.3491629464285714e-05 1.5 2.3508370535714283e-05 1.5 2.350892857142857e-05 0.0 2.350892857142857e-05 0.0 2.3509486607142857e-05 1.5 2.3526227678571425e-05 1.5 2.3526785714285712e-05 0.0 2.3526785714285712e-05 0.0 2.352734375e-05 1.5 2.354408482142857e-05 1.5 2.3544642857142854e-05 0.0 2.3544642857142854e-05 0.0 2.354520089285714e-05 1.5 2.3561941964285713e-05 1.5 2.3562499999999997e-05 0.0 2.3562499999999997e-05 0.0 2.3563058035714284e-05 1.5 2.3579799107142856e-05 1.5 2.3580357142857142e-05 0.0 2.3580357142857142e-05 0.0 2.3580915178571426e-05 1.5 2.3597656249999998e-05 1.5 2.3598214285714285e-05 0.0 2.3598214285714285e-05 0.0 2.3598772321428568e-05 1.5 2.361551339285714e-05 1.5 2.3616071428571427e-05 0.0 2.3616071428571427e-05 0.0 2.3616629464285714e-05 1.5 2.3633370535714283e-05 1.5 2.363392857142857e-05 0.0 2.363392857142857e-05 0.0 2.3634486607142856e-05 1.5 2.365122767857143e-05 1.5 2.3651785714285712e-05 0.0 2.3651785714285712e-05 0.0 2.365234375e-05 1.5 2.366908482142857e-05 1.5 2.3669642857142854e-05 0.0 2.3669642857142854e-05 0.0 2.367020089285714e-05 1.5 2.3686941964285713e-05 1.5 2.36875e-05 0.0 2.36875e-05 0.0 2.3688058035714283e-05 1.5 2.3704799107142855e-05 1.5 2.3705357142857142e-05 0.0 2.3705357142857142e-05 0.0 2.3705915178571425e-05 1.5 2.3722656249999998e-05 1.5 2.3723214285714284e-05 0.0 2.3723214285714284e-05 0.0 2.372377232142857e-05 1.5 2.374051339285714e-05 1.5 2.3741071428571427e-05 0.0 2.3741071428571427e-05 0.0 2.3741629464285714e-05 1.5 2.3758370535714282e-05 1.5 2.375892857142857e-05 0.0 2.375892857142857e-05 0.0 2.3759486607142856e-05 1.5 2.3776227678571428e-05 1.5 2.377678571428571e-05 0.0 2.377678571428571e-05 0.0 2.3777343749999998e-05 1.5 2.379408482142857e-05 1.5 2.3794642857142857e-05 0.0 2.3794642857142857e-05 0.0 2.379520089285714e-05 1.5 2.3811941964285713e-05 1.5 2.38125e-05 0.0 2.38125e-05 0.0 2.3813058035714283e-05 1.5 2.3829799107142855e-05 1.5 2.3830357142857142e-05 0.0 2.3830357142857142e-05 0.0 2.383091517857143e-05 1.5 2.3847656249999997e-05 1.5 2.3848214285714284e-05 0.0 2.3848214285714284e-05 0.0 2.384877232142857e-05 1.5 2.386551339285714e-05 1.5 2.3866071428571426e-05 0.0 2.3866071428571426e-05 0.0 2.3866629464285713e-05 1.5 2.3883370535714285e-05 1.5 2.388392857142857e-05 0.0 2.388392857142857e-05 0.0 2.3884486607142855e-05 1.5 2.3901227678571428e-05 1.5 2.390178571428571e-05 0.0 2.390178571428571e-05 0.0 2.3902343749999998e-05 1.5 2.391908482142857e-05 1.5 2.3919642857142857e-05 0.0 2.3919642857142857e-05 0.0 2.392020089285714e-05 1.5 2.3936941964285712e-05 1.5 2.39375e-05 0.0 2.39375e-05 0.0 2.3938058035714282e-05 1.5 2.3954799107142855e-05 1.5 2.395535714285714e-05 0.0 2.395535714285714e-05 0.0 2.3955915178571428e-05 1.5 2.3972656249999997e-05 1.5 2.3973214285714284e-05 0.0 2.3973214285714284e-05 0.0 2.397377232142857e-05 1.5 2.3990513392857143e-05 1.5 2.3991071428571426e-05 0.0 2.3991071428571426e-05 0.0 2.3991629464285713e-05 1.5 2.4008370535714285e-05 1.5 2.400892857142857e-05 0.0 2.400892857142857e-05 0.0 2.4009486607142855e-05 1.5 2.4026227678571427e-05 1.5 2.4026785714285714e-05 0.0 2.4026785714285714e-05 0.0 2.4027343749999997e-05 1.5 2.404408482142857e-05 1.5 2.4044642857142856e-05 0.0 2.4044642857142856e-05 0.0 2.404520089285714e-05 1.5 2.4061941964285712e-05 1.5 2.40625e-05 0.0 2.40625e-05 0.0 2.4063058035714285e-05 1.5 2.4079799107142854e-05 1.5 2.408035714285714e-05 0.0 2.408035714285714e-05 0.0 2.4080915178571428e-05 1.5 2.4097656249999997e-05 1.5 2.4098214285714283e-05 0.0 2.4098214285714283e-05 0.0 2.409877232142857e-05 1.5 2.4115513392857142e-05 1.5 2.4116071428571426e-05 0.0 2.4116071428571426e-05 0.0 2.4116629464285712e-05 1.5 2.4133370535714285e-05 1.5 2.4133928571428568e-05 0.0 2.4133928571428568e-05 0.0 2.4134486607142855e-05 1.5 2.4151227678571427e-05 1.5 2.4151785714285714e-05 0.0 2.4151785714285714e-05 0.0 2.4152343749999997e-05 1.5 2.416908482142857e-05 1.5 2.4169642857142856e-05 0.0 2.4169642857142856e-05 0.0 2.417020089285714e-05 1.5 2.418694196428571e-05 1.5 2.41875e-05 0.0 2.41875e-05 0.0 2.4188058035714285e-05 1.5 2.4204799107142854e-05 1.5 2.420535714285714e-05 0.0 2.420535714285714e-05 0.0 2.4205915178571427e-05 1.5 2.422265625e-05 1.5 2.4223214285714283e-05 0.0 2.4223214285714283e-05 0.0 2.422377232142857e-05 1.5 2.4240513392857142e-05 1.5 2.4241071428571425e-05 0.0 2.4241071428571425e-05 0.0 2.4241629464285712e-05 1.5 2.4258370535714284e-05 1.5 2.425892857142857e-05 0.0 2.425892857142857e-05 0.0 2.4259486607142854e-05 1.5 2.4276227678571427e-05 1.5 2.4276785714285713e-05 0.0 2.4276785714285713e-05 0.0 2.4277343749999997e-05 1.5 2.429408482142857e-05 1.5 2.4294642857142856e-05 0.0 2.4294642857142856e-05 0.0 2.4295200892857142e-05 1.5 2.431194196428571e-05 1.5 2.4312499999999998e-05 0.0 2.4312499999999998e-05 0.0 2.4313058035714285e-05 1.5 2.4329799107142857e-05 1.5 2.433035714285714e-05 0.0 2.433035714285714e-05 0.0 2.4330915178571427e-05 1.5 2.434765625e-05 1.5 2.4348214285714283e-05 0.0 2.4348214285714283e-05 0.0 2.434877232142857e-05 1.5 2.436551339285714e-05 1.5 2.436607142857143e-05 0.0 2.436607142857143e-05 0.0 2.4366629464285712e-05 1.5 2.4383370535714284e-05 1.5 2.438392857142857e-05 0.0 2.438392857142857e-05 0.0 2.4384486607142854e-05 1.5 2.4401227678571426e-05 1.5 2.4401785714285713e-05 0.0 2.4401785714285713e-05 0.0 2.440234375e-05 1.5 2.441908482142857e-05 1.5 2.4419642857142855e-05 0.0 2.4419642857142855e-05 0.0 2.4420200892857142e-05 1.5 2.443694196428571e-05 1.5 2.4437499999999998e-05 0.0 2.4437499999999998e-05 0.0 2.4438058035714284e-05 1.5 2.4454799107142857e-05 1.5 2.445535714285714e-05 0.0 2.445535714285714e-05 0.0 2.4455915178571427e-05 1.5 2.447265625e-05 1.5 2.4473214285714282e-05 0.0 2.4473214285714282e-05 0.0 2.447377232142857e-05 1.5 2.449051339285714e-05 1.5 2.4491071428571428e-05 0.0 2.4491071428571428e-05 0.0 2.449162946428571e-05 1.5 2.4508370535714284e-05 1.5 2.450892857142857e-05 0.0 2.450892857142857e-05 0.0 2.4509486607142854e-05 1.5 2.4526227678571426e-05 1.5 2.4526785714285713e-05 0.0 2.4526785714285713e-05 0.0 2.452734375e-05 1.5 2.4544084821428568e-05 1.5 2.4544642857142855e-05 0.0 2.4544642857142855e-05 0.0 2.4545200892857142e-05 1.5 2.4561941964285714e-05 1.5 2.4562499999999997e-05 0.0 2.4562499999999997e-05 0.0 2.4563058035714284e-05 1.5 2.4579799107142856e-05 1.5 2.458035714285714e-05 0.0 2.458035714285714e-05 0.0 2.4580915178571426e-05 1.5 2.459765625e-05 1.5 2.4598214285714285e-05 0.0 2.4598214285714285e-05 0.0 2.459877232142857e-05 1.5 2.461551339285714e-05 1.5 2.4616071428571428e-05 0.0 2.4616071428571428e-05 0.0 2.461662946428571e-05 1.5 2.4633370535714283e-05 1.5 2.463392857142857e-05 0.0 2.463392857142857e-05 0.0 2.4634486607142857e-05 1.5 2.4651227678571426e-05 1.5 2.4651785714285712e-05 0.0 2.4651785714285712e-05 0.0 2.465234375e-05 1.5 2.466908482142857e-05 1.5 2.4669642857142855e-05 0.0 2.4669642857142855e-05 0.0 2.467020089285714e-05 1.5 2.4686941964285714e-05 1.5 2.4687499999999997e-05 0.0 2.4687499999999997e-05 0.0 2.4688058035714284e-05 1.5 2.4704799107142856e-05 1.5 2.4705357142857143e-05 0.0 2.4705357142857143e-05 0.0 2.4705915178571426e-05 1.5 2.472209821428571e-05 1.5 2.4722656249999998e-05 0.0 2.472377232142857e-05 0.0 2.4724330357142855e-05 1.5 2.4739955357142854e-05 1.5 2.474051339285714e-05 0.0 2.4741629464285714e-05 0.0 2.4742187499999997e-05 1.5 2.47578125e-05 1.5 2.4758370535714283e-05 0.0 2.4759486607142856e-05 0.0 2.476004464285714e-05 1.5 2.4775669642857142e-05 1.5 2.4776227678571425e-05 0.0 2.477734375e-05 0.0 2.4777901785714286e-05 1.5 2.4793526785714284e-05 1.5 2.479408482142857e-05 0.0 2.479520089285714e-05 0.0 2.4795758928571428e-05 1.5 2.4811383928571427e-05 1.5 2.4811941964285713e-05 0.0 2.4813058035714283e-05 0.0 2.481361607142857e-05 1.5 2.482924107142857e-05 1.5 2.4829799107142856e-05 0.0 2.4830915178571426e-05 0.0 2.4831473214285712e-05 1.5 2.484709821428571e-05 1.5 2.4847656249999998e-05 0.0 2.4848772321428568e-05 0.0 2.4849330357142855e-05 1.5 2.4864955357142857e-05 1.5 2.486551339285714e-05 0.0 2.4866629464285714e-05 0.0 2.4867187499999997e-05 1.5 2.48828125e-05 1.5 2.4883370535714283e-05 0.0 2.4884486607142856e-05 0.0 2.488504464285714e-05 1.5 2.490066964285714e-05 1.5 2.4901227678571428e-05 0.0 2.490234375e-05 0.0 2.4902901785714285e-05 1.5 2.4918526785714284e-05 1.5 2.491908482142857e-05 0.0 2.492020089285714e-05 0.0 2.4920758928571427e-05 1.5 2.4936383928571426e-05 1.5 2.4936941964285713e-05 0.0 2.4938058035714283e-05 0.0 2.493861607142857e-05 1.5 2.495424107142857e-05 1.5 2.4954799107142855e-05 0.0 2.4955915178571425e-05 0.0 2.4956473214285712e-05 1.5 2.497209821428571e-05 1.5 2.4972656249999998e-05 0.0 2.497377232142857e-05 0.0 2.4974330357142854e-05 1.5 2.4989955357142857e-05 1.5 2.499051339285714e-05 0.0 2.4991629464285713e-05 0.0 2.4992187499999997e-05 1.5 2.5007254464285712e-05 1.5 2.50078125e-05 0.0 2.5010044642857142e-05 0.0 2.5010602678571426e-05 1.5 2.5025111607142854e-05 1.5 2.502566964285714e-05 0.0 2.5027901785714285e-05 0.0 2.5028459821428568e-05 1.5 2.5042968749999997e-05 1.5 2.5043526785714283e-05 0.0 2.5045758928571427e-05 0.0 2.5046316964285714e-05 1.5 2.5060825892857142e-05 1.5 2.5061383928571426e-05 0.0 2.506361607142857e-05 0.0 2.5064174107142856e-05 1.5 2.5078683035714285e-05 1.5 2.5079241071428568e-05 0.0 2.5081473214285712e-05 0.0 2.508203125e-05 1.5 2.5096540178571427e-05 1.5 2.5097098214285714e-05 0.0 2.5099330357142854e-05 0.0 2.509988839285714e-05 1.5 2.511439732142857e-05 1.5 2.5114955357142856e-05 0.0 2.51171875e-05 0.0 2.5117745535714283e-05 1.5 2.5132254464285712e-05 1.5 2.51328125e-05 0.0 2.5135044642857142e-05 0.0 2.5135602678571426e-05 1.5 2.5150111607142854e-05 1.5 2.515066964285714e-05 0.0 2.5152901785714284e-05 0.0 2.515345982142857e-05 1.5 2.516796875e-05 1.5 2.5168526785714283e-05 0.0 2.5170758928571427e-05 0.0 2.5171316964285714e-05 1.5 2.5185825892857142e-05 1.5 2.5186383928571425e-05 0.0 2.518861607142857e-05 0.0 2.5189174107142856e-05 1.5 2.5203683035714284e-05 1.5 2.520424107142857e-05 0.0 2.520647321428571e-05 0.0 2.5207031249999998e-05 1.5 2.522098214285714e-05 1.5 2.5221540178571427e-05 0.0 2.522488839285714e-05 0.0 2.5225446428571427e-05 1.5 2.5238839285714282e-05 1.5 2.523939732142857e-05 0.0 2.5242745535714283e-05 0.0 2.524330357142857e-05 1.5 2.5256696428571428e-05 1.5 2.525725446428571e-05 0.0 2.5260602678571425e-05 0.0 2.5261160714285712e-05 1.5 2.527455357142857e-05 1.5 2.5275111607142854e-05 0.0 2.527845982142857e-05 0.0 2.5279017857142854e-05 1.5 2.5292410714285713e-05 1.5 2.529296875e-05 0.0 2.5296316964285713e-05 0.0 2.5296874999999997e-05 1.5 2.5310267857142855e-05 1.5 2.5310825892857142e-05 0.0 2.5314174107142856e-05 0.0 2.5314732142857142e-05 1.5 2.5328124999999997e-05 1.5 2.5328683035714284e-05 0.0 2.5332031249999998e-05 0.0 2.5332589285714285e-05 1.5 2.534598214285714e-05 1.5 2.5346540178571426e-05 0.0 2.534988839285714e-05 0.0 2.5350446428571427e-05 1.5 2.5363839285714285e-05 1.5 2.536439732142857e-05 0.0 2.5367745535714282e-05 0.0 2.536830357142857e-05 1.5 2.5381696428571428e-05 1.5 2.538225446428571e-05 0.0 2.5385602678571428e-05 0.0 2.538616071428571e-05 1.5 2.539955357142857e-05 1.5 2.5400111607142857e-05 0.0 2.540345982142857e-05 0.0 2.5404017857142854e-05 1.5 2.5416852678571426e-05 1.5 2.5417410714285712e-05 0.0 2.5421875e-05 0.0 2.5422433035714283e-05 1.5 2.543470982142857e-05 1.5 2.5435267857142855e-05 0.0 2.5439732142857142e-05 0.0 2.5440290178571425e-05 1.5 2.5452566964285714e-05 1.5 2.5453124999999997e-05 0.0 2.5457589285714284e-05 0.0 2.545814732142857e-05 1.5 2.5470424107142856e-05 1.5 2.5470982142857143e-05 0.0 2.5475446428571427e-05 0.0 2.5476004464285713e-05 1.5 2.5488281249999998e-05 1.5 2.5488839285714285e-05 0.0 2.549330357142857e-05 0.0 2.5493861607142856e-05 1.5 2.550613839285714e-05 1.5 2.5506696428571427e-05 0.0 2.551116071428571e-05 0.0 2.5511718749999998e-05 1.5 2.5523995535714283e-05 1.5 2.552455357142857e-05 0.0 2.5529017857142857e-05 0.0 2.552957589285714e-05 1.5 2.5541852678571425e-05 1.5 2.5542410714285712e-05 0.0 2.5546875e-05 0.0 2.5547433035714283e-05 1.5 2.555970982142857e-05 1.5 2.5560267857142854e-05 0.0 2.556473214285714e-05 0.0 2.556529017857143e-05 1.5 2.5577566964285713e-05 1.5 2.5578124999999997e-05 0.0 2.5582589285714284e-05 0.0 2.558314732142857e-05 1.5 2.559486607142857e-05 1.5 2.5595424107142856e-05 0.0 2.5601004464285713e-05 0.0 2.56015625e-05 1.5 2.561272321428571e-05 1.5 2.5613281249999998e-05 0.0 2.5618861607142855e-05 0.0 2.5619419642857142e-05 1.5 2.5630580357142857e-05 1.5 2.563113839285714e-05 0.0 2.5636718749999998e-05 0.0 2.5637276785714284e-05 1.5 2.56484375e-05 1.5 2.5648995535714283e-05 0.0 2.565457589285714e-05 0.0 2.5655133928571427e-05 1.5 2.566629464285714e-05 1.5 2.5666852678571428e-05 0.0 2.5672433035714282e-05 0.0 2.567299107142857e-05 1.5 2.5684151785714284e-05 1.5 2.568470982142857e-05 0.0 2.5690290178571428e-05 0.0 2.569084821428571e-05 1.5 2.5702008928571426e-05 1.5 2.5702566964285713e-05 0.0 2.570814732142857e-05 0.0 2.5708705357142854e-05 1.5 2.571986607142857e-05 1.5 2.5720424107142855e-05 0.0 2.5726004464285713e-05 0.0 2.57265625e-05 1.5 2.573772321428571e-05 1.5 2.5738281249999998e-05 0.0 2.5743861607142855e-05 0.0 2.5744419642857142e-05 1.5 2.5755580357142856e-05 1.5 2.575613839285714e-05 0.0 2.5762276785714284e-05 0.0 2.576283482142857e-05 1.5 2.5772879464285712e-05 1.5 2.57734375e-05 0.0 2.5780133928571426e-05 0.0 2.5780691964285713e-05 1.5 2.5790736607142854e-05 1.5 2.579129464285714e-05 0.0 2.579799107142857e-05 0.0 2.5798549107142855e-05 1.5 2.5808593749999997e-05 1.5 2.5809151785714283e-05 0.0 2.581584821428571e-05 0.0 2.5816406249999998e-05 1.5 2.5826450892857142e-05 1.5 2.5827008928571426e-05 0.0 2.5833705357142857e-05 0.0 2.583426339285714e-05 1.5 2.5844308035714285e-05 1.5 2.5844866071428568e-05 0.0 2.58515625e-05 0.0 2.5852120535714282e-05 1.5 2.5862165178571427e-05 1.5 2.5862723214285714e-05 0.0 2.586941964285714e-05 0.0 2.5869977678571428e-05 1.5 2.588002232142857e-05 1.5 2.5880580357142856e-05 0.0 2.5887276785714284e-05 0.0 2.588783482142857e-05 1.5 2.5897879464285712e-05 1.5 2.58984375e-05 0.0 2.5905133928571426e-05 0.0 2.5905691964285713e-05 1.5 2.5915736607142854e-05 1.5 2.591629464285714e-05 0.0 2.5923549107142855e-05 0.0 2.5924107142857142e-05 1.5 2.5933035714285713e-05 1.5 2.593359375e-05 0.0 2.5941406249999997e-05 0.0 2.5941964285714284e-05 1.5 2.5950892857142855e-05 1.5 2.5951450892857142e-05 0.0 2.595926339285714e-05 0.0 2.5959821428571426e-05 1.5 2.5968749999999998e-05 1.5 2.5969308035714284e-05 0.0 2.5977120535714285e-05 0.0 2.597767857142857e-05 1.5 2.598660714285714e-05 1.5 2.5987165178571427e-05 0.0 2.5994977678571428e-05 0.0 2.599553571428571e-05 1.5 2.6004464285714282e-05 1.5 2.600502232142857e-05 0.0 2.601283482142857e-05 0.0 2.6013392857142857e-05 1.5 2.6022321428571428e-05 1.5 2.602287946428571e-05 0.0 2.6030691964285712e-05 0.0 2.603125e-05 1.5 2.604017857142857e-05 1.5 2.6040736607142854e-05 0.0 2.6048549107142855e-05 0.0 2.604910714285714e-05 1.5 2.6058035714285713e-05 1.5 2.605859375e-05 0.0 2.6066406249999997e-05 0.0 2.6066964285714284e-05 1.5 2.6075892857142855e-05 1.5 2.6076450892857142e-05 0.0 2.6084821428571426e-05 0.0 2.6085379464285713e-05 1.5 2.6093191964285714e-05 1.5 2.6093749999999997e-05 0.0 2.610267857142857e-05 0.0 2.6103236607142855e-05 1.5 2.6111049107142856e-05 1.5 2.611160714285714e-05 0.0 2.612053571428571e-05 0.0 2.6121093749999998e-05 1.5 2.612890625e-05 1.5 2.6129464285714285e-05 0.0 2.6138392857142856e-05 0.0 2.613895089285714e-05 1.5 2.614676339285714e-05 1.5 2.6147321428571428e-05 0.0 2.615625e-05 0.0 2.6156808035714282e-05 1.5 2.6164620535714283e-05 1.5 2.616517857142857e-05 0.0 2.617410714285714e-05 0.0 2.6174665178571428e-05 1.5 2.6182477678571426e-05 1.5 2.6183035714285712e-05 0.0 2.6191964285714283e-05 0.0 2.619252232142857e-05 1.5 2.6200334821428568e-05 1.5 2.6200892857142855e-05 0.0 2.6209821428571426e-05 0.0 2.6210379464285713e-05 1.5 2.6218191964285714e-05 1.5 2.6218749999999997e-05 0.0 2.6227678571428568e-05 0.0 2.6228236607142855e-05 1.5 2.6236049107142856e-05 1.5 2.6236607142857143e-05 0.0 2.6246093749999997e-05 0.0 2.6246651785714284e-05 1.5 2.625334821428571e-05 1.5 2.6253906249999998e-05 0.0 2.626395089285714e-05 0.0 2.6264508928571426e-05 1.5 2.6271205357142854e-05 1.5 2.627176339285714e-05 0.0 2.6281808035714285e-05 0.0 2.628236607142857e-05 1.5 2.62890625e-05 1.5 2.6289620535714283e-05 0.0 2.6299665178571428e-05 0.0 2.630022321428571e-05 1.5 2.6306919642857142e-05 1.5 2.6307477678571425e-05 0.0 2.631752232142857e-05 0.0 2.6318080357142857e-05 1.5 2.6324776785714284e-05 1.5 2.632533482142857e-05 0.0 2.6335379464285712e-05 0.0 2.63359375e-05 1.5 2.6342633928571426e-05 1.5 2.6343191964285713e-05 0.0 2.6353236607142855e-05 0.0 2.635379464285714e-05 1.5 2.636049107142857e-05 1.5 2.6361049107142856e-05 0.0 2.6371093749999997e-05 0.0 2.6371651785714284e-05 1.5 2.637834821428571e-05 1.5 2.6378906249999998e-05 0.0 2.6388950892857143e-05 0.0 2.6389508928571426e-05 1.5 2.6396205357142857e-05 1.5 2.639676339285714e-05 0.0 2.6407366071428568e-05 0.0 2.6407924107142855e-05 1.5 2.6413504464285712e-05 1.5 2.64140625e-05 0.0 2.6425223214285714e-05 0.0 2.6425781249999997e-05 1.5 2.6431361607142855e-05 1.5 2.643191964285714e-05 0.0 2.6443080357142856e-05 0.0 2.644363839285714e-05 1.5 2.6449218749999997e-05 1.5 2.6449776785714284e-05 0.0 2.64609375e-05 0.0 2.6461495535714285e-05 1.5 2.646707589285714e-05 1.5 2.6467633928571426e-05 0.0 2.647879464285714e-05 0.0 2.6479352678571428e-05 1.5 2.6484933035714285e-05 1.5 2.648549107142857e-05 0.0 2.6496651785714283e-05 0.0 2.649720982142857e-05 1.5 2.6502790178571427e-05 1.5 2.650334821428571e-05 0.0 2.6514508928571426e-05 0.0 2.6515066964285712e-05 1.5 2.652064732142857e-05 1.5 2.6521205357142856e-05 0.0 2.6532366071428568e-05 0.0 2.6532924107142855e-05 1.5 2.6538504464285712e-05 1.5 2.65390625e-05 0.0 2.6550223214285714e-05 0.0 2.6550781249999997e-05 1.5 2.6556361607142854e-05 1.5 2.655691964285714e-05 0.0 2.6568080357142856e-05 0.0 2.656863839285714e-05 1.5 2.6574218749999997e-05 1.5 2.6574776785714283e-05 0.0 2.6586495535714285e-05 0.0 2.658705357142857e-05 1.5 2.6591517857142856e-05 1.5 2.6592075892857142e-05 0.0 2.6604352678571427e-05 0.0 2.660491071428571e-05 1.5 2.6609374999999998e-05 1.5 2.6609933035714285e-05 0.0 2.662220982142857e-05 0.0 2.6622767857142856e-05 1.5 2.662723214285714e-05 1.5 2.6627790178571427e-05 0.0 2.6640066964285712e-05 0.0 2.6640625e-05 1.5 2.6645089285714283e-05 1.5 2.664564732142857e-05 0.0 2.6657924107142854e-05 0.0 2.665848214285714e-05 1.5 2.666294642857143e-05 1.5 2.666350446428571e-05 0.0 2.6675781249999997e-05 0.0 2.6676339285714283e-05 1.5 2.668080357142857e-05 1.5 2.6681361607142854e-05 0.0 2.6693638392857142e-05 0.0 2.6694196428571426e-05 1.5 2.6698660714285713e-05 1.5 2.669921875e-05 0.0 2.6711495535714285e-05 0.0 2.6712053571428568e-05 1.5 2.6716517857142855e-05 1.5 2.6717075892857142e-05 0.0 2.6729352678571427e-05 0.0 2.6729910714285714e-05 1.5 2.6734374999999998e-05 1.5 2.6734933035714284e-05 0.0 2.674720982142857e-05 0.0 2.6747767857142856e-05 1.5 2.675223214285714e-05 1.5 2.6752790178571427e-05 0.0 2.6765625e-05 0.0 2.6766183035714285e-05 1.5 2.676953125e-05 1.5 2.6770089285714282e-05 0.0 2.678348214285714e-05 0.0 2.6784040178571427e-05 1.5 2.678738839285714e-05 1.5 2.6787946428571428e-05 0.0 2.6801339285714283e-05 0.0 2.680189732142857e-05 1.5 2.6805245535714284e-05 1.5 2.680580357142857e-05 0.0 2.6819196428571425e-05 0.0 2.6819754464285712e-05 1.5 2.6823102678571426e-05 1.5 2.6823660714285713e-05 0.0 2.683705357142857e-05 0.0 2.6837611607142854e-05 1.5 2.6840959821428568e-05 1.5 2.6841517857142855e-05 0.0 2.6854910714285713e-05 0.0 2.6855468749999997e-05 1.5 2.6858816964285714e-05 1.5 2.6859374999999997e-05 0.0 2.6872767857142856e-05 0.0 2.6873325892857142e-05 1.5 2.6876674107142856e-05 1.5 2.687723214285714e-05 0.0 2.6890624999999998e-05 0.0 2.6891183035714285e-05 1.5 2.689453125e-05 1.5 2.6895089285714285e-05 0.0 2.690848214285714e-05 0.0 2.6909040178571427e-05 1.5 2.691238839285714e-05 1.5 2.6912946428571428e-05 0.0 2.6926339285714283e-05 0.0 2.692689732142857e-05 1.5 2.6930245535714283e-05 1.5 2.693080357142857e-05 0.0 2.6944196428571425e-05 0.0 2.6944754464285712e-05 1.5 2.6947544642857142e-05 1.5 2.6948102678571426e-05 0.0 2.6962611607142854e-05 0.0 2.696316964285714e-05 1.5 2.6965401785714284e-05 1.5 2.6965959821428568e-05 0.0 2.6980468749999996e-05 0.0 2.6981026785714283e-05 1.5 2.6983258928571427e-05 1.5 2.6983816964285714e-05 0.0 2.6998325892857142e-05 0.0 2.6998883928571425e-05 1.5 2.700111607142857e-05 1.5 2.7001674107142856e-05 0.0 2.7016183035714284e-05 0.0 2.7016741071428568e-05 1.5 2.701897321428571e-05 1.5 2.7019531249999998e-05 0.0 2.7034040178571427e-05 0.0 2.7034598214285714e-05 1.5 2.7036830357142854e-05 1.5 2.703738839285714e-05 0.0 2.705189732142857e-05 0.0 2.7052455357142856e-05 1.5 2.70546875e-05 1.5 2.7055245535714283e-05 0.0 2.706975446428571e-05 0.0 2.7070312499999998e-05 1.5 2.7072544642857142e-05 1.5 2.7073102678571425e-05 0.0 2.7087611607142854e-05 0.0 2.708816964285714e-05 1.5 2.7090401785714284e-05 1.5 2.709095982142857e-05 0.0 2.710546875e-05 0.0 2.7106026785714283e-05 1.5 2.7108258928571426e-05 1.5 2.7108816964285713e-05 0.0 2.7123325892857142e-05 0.0 2.7123883928571425e-05 1.5 2.712611607142857e-05 1.5 2.7126674107142856e-05 0.0 2.7141183035714284e-05 0.0 2.714174107142857e-05 1.5 2.714397321428571e-05 1.5 2.7144531249999998e-05 0.0 2.7159040178571426e-05 0.0 2.7159598214285713e-05 1.5 2.7161830357142857e-05 1.5 2.716238839285714e-05 0.0 2.7177455357142855e-05 0.0 2.7178013392857142e-05 1.5 2.7179129464285712e-05 1.5 2.71796875e-05 0.0 2.7195312499999998e-05 0.0 2.7195870535714285e-05 1.5 2.7196986607142855e-05 1.5 2.719754464285714e-05 0.0 2.721316964285714e-05 0.0 2.7213727678571427e-05 1.5 2.7214843749999997e-05 1.5 2.7215401785714284e-05 0.0 2.7231026785714282e-05 0.0 2.723158482142857e-05 1.5 2.723270089285714e-05 1.5 2.7233258928571426e-05 0.0 2.7248883928571428e-05 0.0 2.724944196428571e-05 1.5 2.7250558035714285e-05 1.5 2.725111607142857e-05 0.0 2.726674107142857e-05 0.0 2.7267299107142854e-05 1.5 2.7268415178571427e-05 1.5 2.726897321428571e-05 0.0 2.7284598214285713e-05 0.0 2.728515625e-05 1.5 2.728627232142857e-05 1.5 2.7286830357142856e-05 0.0 2.7302455357142855e-05 0.0 2.7303013392857142e-05 1.5 2.7304129464285712e-05 1.5 2.73046875e-05 0.0 2.7320312499999997e-05 0.0 2.7320870535714284e-05 1.5 2.7321986607142854e-05 1.5 2.732254464285714e-05 0.0 2.733816964285714e-05 0.0 2.7338727678571427e-05 1.5 2.7339843749999997e-05 1.5 2.7340401785714283e-05 0.0 2.7356026785714282e-05 0.0 2.735658482142857e-05 1.5 2.7357700892857142e-05 1.5 2.7358258928571426e-05 0.0 2.7373883928571428e-05 0.0 2.737444196428571e-05 1.5 2.7375558035714285e-05 1.5 2.7376116071428568e-05 0.0 2.739174107142857e-05 0.0 2.7392299107142854e-05 1.5 2.7393415178571427e-05 1.5 2.7393973214285714e-05 0.0 2.7409598214285712e-05 0.0 2.741015625e-05 1.5 2.741127232142857e-05 1.5 2.7411830357142856e-05 0.0 2.7427455357142855e-05 0.0 2.742801339285714e-05 1.5 2.742912946428571e-05 1.5 2.74296875e-05 0.0 2.7445870535714284e-05 0.0 2.744642857142857e-05 1.5 2.744642857142857e-05 1.5 2.7446986607142854e-05 0.0 2.7463727678571426e-05 0.0 2.7464285714285713e-05 1.5 2.7464285714285713e-05 1.5 2.746484375e-05 0.0 2.748158482142857e-05 0.0 2.7482142857142855e-05 1.5 2.7482142857142855e-05 1.5 2.7482700892857142e-05 0.0 2.749944196428571e-05 0.0 2.7499999999999998e-05 1.5 2.7499999999999998e-05 1.5 2.7500558035714284e-05 0.0 2.7517299107142857e-05 0.0 2.751785714285714e-05 1.5 2.751785714285714e-05 1.5 2.7518415178571427e-05 0.0 2.753515625e-05 0.0 2.7535714285714282e-05 1.5 2.7535714285714282e-05 1.5 2.753627232142857e-05 0.0 2.755301339285714e-05 0.0 2.7553571428571428e-05 1.5 2.7553571428571428e-05 1.5 2.755412946428571e-05 0.0 2.7570870535714284e-05 0.0 2.757142857142857e-05 1.5 2.757142857142857e-05 1.5 2.7571986607142854e-05 0.0 2.7588727678571426e-05 0.0 2.7589285714285713e-05 1.5 2.7589285714285713e-05 1.5 2.758984375e-05 0.0 2.7606584821428568e-05 0.0 2.7607142857142855e-05 1.5 2.7607142857142855e-05 1.5 2.760770089285714e-05 0.0 2.7624441964285714e-05 0.0 2.7624999999999997e-05 1.5 2.7624999999999997e-05 1.5 2.7625558035714284e-05 0.0 2.7642299107142856e-05 0.0 2.764285714285714e-05 1.5 2.764285714285714e-05 1.5 2.7643415178571426e-05 0.0 2.766015625e-05 0.0 2.7660714285714285e-05 1.5 2.7660714285714285e-05 1.5 2.766127232142857e-05 0.0 2.767801339285714e-05 0.0 2.7678571428571428e-05 1.5 2.7678571428571428e-05 1.5 2.767912946428571e-05 0.0 2.7695870535714283e-05 0.0 2.769642857142857e-05 1.5 2.769642857142857e-05 1.5 2.7696986607142857e-05 0.0 2.7713727678571425e-05 0.0 2.7714285714285712e-05 1.5 2.7714285714285712e-05 1.5 2.771484375e-05 0.0 2.7731584821428568e-05 0.0 2.7732142857142855e-05 1.5 2.7732142857142855e-05 1.5 2.773270089285714e-05 0.0 2.7749441964285714e-05 0.0 2.7749999999999997e-05 1.5 2.7749999999999997e-05 1.5 2.7750558035714284e-05 0.0 2.7767299107142856e-05 0.0 2.776785714285714e-05 1.5 2.776785714285714e-05 1.5 2.7768415178571426e-05 0.0 2.7785156249999998e-05 0.0 2.7785714285714285e-05 1.5 2.7785714285714285e-05 1.5 2.7786272321428568e-05 0.0 2.780301339285714e-05 0.0 2.7803571428571427e-05 1.5 2.7803571428571427e-05 1.5 2.780412946428571e-05 0.0 2.7820870535714283e-05 0.0 2.782142857142857e-05 1.5 2.782142857142857e-05 1.5 2.7821986607142856e-05 0.0 2.7838727678571425e-05 0.0 2.7839285714285712e-05 1.5 2.7839285714285712e-05 1.5 2.783984375e-05 0.0 2.785658482142857e-05 0.0 2.7857142857142854e-05 1.5 2.7857142857142854e-05 1.5 2.785770089285714e-05 0.0 2.7874441964285713e-05 0.0 2.7874999999999997e-05 1.5 2.7874999999999997e-05 1.5 2.7875558035714283e-05 0.0 2.7892299107142855e-05 0.0 2.7892857142857142e-05 1.5 2.7892857142857142e-05 1.5 2.7893415178571426e-05 0.0 2.7910156249999998e-05 0.0 2.7910714285714285e-05 1.5 2.7910714285714285e-05 1.5 2.7911272321428568e-05 0.0 2.792801339285714e-05 0.0 2.7928571428571427e-05 1.5 2.7928571428571427e-05 1.5 2.7929129464285714e-05 0.0 2.7945870535714282e-05 0.0 2.794642857142857e-05 1.5 2.794642857142857e-05 1.5 2.7946986607142856e-05 0.0 2.7963727678571428e-05 0.0 2.796428571428571e-05 1.5 2.796428571428571e-05 1.5 2.7964843749999998e-05 0.0 2.798158482142857e-05 0.0 2.7982142857142854e-05 1.5 2.7982142857142854e-05 1.5 2.798270089285714e-05 0.0 2.7999441964285713e-05 0.0 2.8e-05 1.5 2.8e-05 1.5 2.8000558035714283e-05 0.0 2.8017299107142855e-05 0.0 2.8017857142857142e-05 1.5 2.8017857142857142e-05 1.5 2.8018415178571425e-05 0.0 2.8035156249999997e-05 0.0 2.8035714285714284e-05 1.5 2.8035714285714284e-05 1.5 2.803627232142857e-05 0.0 2.805301339285714e-05 0.0 2.8053571428571427e-05 1.5 2.8053571428571427e-05 1.5 2.8054129464285713e-05 0.0 2.8070870535714282e-05 0.0 2.807142857142857e-05 1.5 2.807142857142857e-05 1.5 2.8071986607142856e-05 0.0 2.8088727678571428e-05 0.0 2.808928571428571e-05 1.5 2.808928571428571e-05 1.5 2.8089843749999998e-05 0.0 2.810658482142857e-05 0.0 2.8107142857142854e-05 1.5 2.8107142857142854e-05 1.5 2.810770089285714e-05 0.0 2.8124441964285712e-05 0.0 2.8125e-05 1.5 2.8125e-05 1.5 2.8125558035714283e-05 0.0 2.8142299107142855e-05 0.0 2.814285714285714e-05 1.5 2.814285714285714e-05 1.5 2.8143415178571425e-05 0.0 2.8160156249999997e-05 0.0 2.8160714285714284e-05 1.5 2.8160714285714284e-05 1.5 2.816127232142857e-05 0.0 2.817801339285714e-05 0.0 2.8178571428571426e-05 1.5 2.8178571428571426e-05 1.5 2.8179129464285713e-05 0.0 2.8195870535714285e-05 0.0 2.819642857142857e-05 1.5 2.819642857142857e-05 1.5 2.8196986607142855e-05 0.0 2.8213727678571427e-05 0.0 2.821428571428571e-05 1.5 2.821428571428571e-05 1.5 2.8214843749999998e-05 0.0 2.823158482142857e-05 0.0 2.8232142857142857e-05 1.5 2.8232142857142857e-05 1.5 2.823270089285714e-05 0.0 2.8249441964285712e-05 0.0 2.825e-05 1.5 2.825e-05 1.5 2.8250558035714282e-05 0.0 2.8267299107142854e-05 0.0 2.826785714285714e-05 1.5 2.826785714285714e-05 1.5 2.8268415178571428e-05 0.0 2.8285156249999997e-05 0.0 2.8285714285714284e-05 1.5 2.8285714285714284e-05 1.5 2.828627232142857e-05 0.0 2.8303013392857142e-05 0.0 2.8303571428571426e-05 1.5 2.8303571428571426e-05 1.5 2.8304129464285713e-05 0.0 2.8320870535714285e-05 0.0 2.8321428571428568e-05 1.5 2.8321428571428568e-05 1.5 2.8321986607142855e-05 0.0 2.8338727678571427e-05 0.0 2.8339285714285714e-05 1.5 2.8339285714285714e-05 1.5 2.8339843749999997e-05 0.0 2.835658482142857e-05 0.0 2.8357142857142856e-05 1.5 2.8357142857142856e-05 1.5 2.835770089285714e-05 0.0 2.8374441964285712e-05 0.0 2.8375e-05 1.5 2.8375e-05 1.5 2.8375558035714285e-05 0.0 2.8392299107142854e-05 0.0 2.839285714285714e-05 1.5 2.839285714285714e-05 1.5 2.8393415178571428e-05 0.0 2.8410156249999996e-05 0.0 2.8410714285714283e-05 1.5 2.8410714285714283e-05 1.5 2.841127232142857e-05 0.0 2.8428013392857142e-05 0.0 2.8428571428571426e-05 1.5 2.8428571428571426e-05 1.5 2.8429129464285712e-05 0.0 2.8445870535714284e-05 0.0 2.8446428571428568e-05 1.5 2.8446428571428568e-05 1.5 2.8446986607142855e-05 0.0 2.8463727678571427e-05 0.0 2.8464285714285714e-05 1.5 2.8464285714285714e-05 1.5 2.8464843749999997e-05 0.0 2.848158482142857e-05 0.0 2.8482142857142856e-05 1.5 2.8482142857142856e-05 1.5 2.848270089285714e-05 0.0 2.849944196428571e-05 0.0 2.8499999999999998e-05 1.5 2.8499999999999998e-05 1.5 2.8500558035714285e-05 0.0 2.8517299107142854e-05 0.0 2.851785714285714e-05 1.5 2.851785714285714e-05 1.5 2.8518415178571427e-05 0.0 2.853515625e-05 0.0 2.8535714285714283e-05 1.5 2.8535714285714283e-05 1.5 2.853627232142857e-05 0.0 2.8553013392857142e-05 0.0 2.8553571428571425e-05 1.5 2.8553571428571425e-05 1.5 2.8554129464285712e-05 0.0 2.8570870535714284e-05 0.0 2.857142857142857e-05 1.5 2.857142857142857e-05 1.5 2.8571986607142854e-05 0.0 2.8588727678571426e-05 0.0 2.8589285714285713e-05 1.5 2.8589285714285713e-05 1.5 2.8589843749999997e-05 0.0 2.860658482142857e-05 0.0 2.8607142857142856e-05 1.5 2.8607142857142856e-05 1.5 2.8607700892857142e-05 0.0 2.862444196428571e-05 0.0 2.8624999999999998e-05 1.5 2.8624999999999998e-05 1.5 2.8625558035714285e-05 0.0 2.8642299107142853e-05 0.0 2.864285714285714e-05 1.5 2.864285714285714e-05 1.5 2.8643415178571427e-05 0.0 2.866015625e-05 0.0 2.8660714285714282e-05 1.5 2.8660714285714282e-05 1.5 2.866127232142857e-05 0.0 2.867801339285714e-05 0.0 2.8678571428571428e-05 1.5 2.8678571428571428e-05 1.5 2.867912946428571e-05 0.0 2.8695870535714284e-05 0.0 2.869642857142857e-05 1.5 2.869642857142857e-05 1.5 2.8696986607142854e-05 0.0 2.8713727678571426e-05 0.0 2.8714285714285713e-05 1.5 2.8714285714285713e-05 1.5 2.871484375e-05 0.0 2.873158482142857e-05 0.0 2.8732142857142855e-05 1.5 2.8732142857142855e-05 1.5 2.8732700892857142e-05 0.0 2.8748883928571427e-05 0.0 2.874944196428571e-05 1.5 2.8750558035714284e-05 1.5 2.875111607142857e-05 0.0 2.876674107142857e-05 0.0 2.8767299107142856e-05 1.5 2.8768415178571427e-05 1.5 2.8768973214285713e-05 0.0 2.8784598214285712e-05 0.0 2.878515625e-05 1.5 2.878627232142857e-05 1.5 2.8786830357142856e-05 0.0 2.8802455357142854e-05 0.0 2.880301339285714e-05 1.5 2.880412946428571e-05 1.5 2.8804687499999998e-05 0.0 2.8820312499999997e-05 0.0 2.8820870535714283e-05 1.5 2.8821986607142854e-05 1.5 2.882254464285714e-05 0.0 2.8838169642857142e-05 0.0 2.8838727678571426e-05 1.5 2.883984375e-05 1.5 2.8840401785714283e-05 0.0 2.8856026785714285e-05 0.0 2.8856584821428568e-05 1.5 2.885770089285714e-05 1.5 2.8858258928571425e-05 0.0 2.8873883928571427e-05 0.0 2.8874441964285714e-05 1.5 2.8875558035714284e-05 1.5 2.887611607142857e-05 0.0 2.889174107142857e-05 0.0 2.8892299107142856e-05 1.5 2.8893415178571426e-05 1.5 2.8893973214285713e-05 0.0 2.890959821428571e-05 0.0 2.891015625e-05 1.5 2.891127232142857e-05 1.5 2.8911830357142855e-05 0.0 2.8927455357142854e-05 0.0 2.892801339285714e-05 1.5 2.892912946428571e-05 1.5 2.8929687499999998e-05 0.0 2.8945312499999996e-05 0.0 2.8945870535714283e-05 1.5 2.8946986607142857e-05 1.5 2.894754464285714e-05 0.0 2.8963169642857142e-05 0.0 2.8963727678571425e-05 1.5 2.896484375e-05 1.5 2.8965401785714282e-05 0.0 2.8981026785714284e-05 0.0 2.8981584821428568e-05 1.5 2.898270089285714e-05 1.5 2.8983258928571428e-05 0.0 2.8998883928571427e-05 0.0 2.8999441964285713e-05 1.5 2.9000558035714284e-05 1.5 2.900111607142857e-05 0.0 2.9016183035714282e-05 0.0 2.901674107142857e-05 1.5 2.9018973214285713e-05 1.5 2.901953125e-05 0.0 2.9034040178571428e-05 0.0 2.903459821428571e-05 1.5 2.9036830357142855e-05 1.5 2.9037388392857142e-05 0.0 2.905189732142857e-05 0.0 2.9052455357142854e-05 1.5 2.9054687499999997e-05 1.5 2.9055245535714284e-05 0.0 2.9069754464285713e-05 0.0 2.90703125e-05 1.5 2.907254464285714e-05 1.5 2.9073102678571426e-05 0.0 2.9087611607142855e-05 0.0 2.908816964285714e-05 1.5 2.9090401785714285e-05 1.5 2.909095982142857e-05 0.0 2.9105468749999997e-05 0.0 2.9106026785714284e-05 1.5 2.9108258928571428e-05 1.5 2.910881696428571e-05 0.0 2.912332589285714e-05 0.0 2.9123883928571426e-05 1.5 2.912611607142857e-05 1.5 2.9126674107142857e-05 0.0 2.9141183035714285e-05 0.0 2.914174107142857e-05 1.5 2.9143973214285712e-05 1.5 2.914453125e-05 0.0 2.9159040178571428e-05 0.0 2.915959821428571e-05 1.5 2.9161830357142855e-05 1.5 2.916238839285714e-05 0.0 2.917689732142857e-05 0.0 2.9177455357142857e-05 1.5 2.9179687499999997e-05 1.5 2.9180245535714284e-05 0.0 2.9194754464285712e-05 0.0 2.91953125e-05 1.5 2.919754464285714e-05 1.5 2.9198102678571426e-05 0.0 2.9212611607142855e-05 0.0 2.921316964285714e-05 1.5 2.9215401785714285e-05 1.5 2.921595982142857e-05 0.0 2.9230468749999997e-05 0.0 2.9231026785714284e-05 1.5 2.9233258928571427e-05 1.5 2.923381696428571e-05 0.0 2.9247767857142856e-05 0.0 2.924832589285714e-05 1.5 2.9251674107142856e-05 1.5 2.925223214285714e-05 0.0 2.9265624999999998e-05 0.0 2.9266183035714285e-05 1.5 2.926953125e-05 1.5 2.9270089285714282e-05 0.0 2.928348214285714e-05 0.0 2.9284040178571427e-05 1.5 2.928738839285714e-05 1.5 2.9287946428571428e-05 0.0 2.9301339285714283e-05 0.0 2.930189732142857e-05 1.5 2.9305245535714283e-05 1.5 2.930580357142857e-05 0.0 2.9319196428571425e-05 0.0 2.9319754464285712e-05 1.5 2.9323102678571426e-05 1.5 2.9323660714285712e-05 0.0 2.933705357142857e-05 0.0 2.9337611607142854e-05 1.5 2.9340959821428568e-05 1.5 2.9341517857142855e-05 0.0 2.9354910714285713e-05 0.0 2.9355468749999997e-05 1.5 2.9358816964285714e-05 1.5 2.9359374999999997e-05 0.0 2.9372767857142855e-05 0.0 2.9373325892857142e-05 1.5 2.9376674107142856e-05 1.5 2.937723214285714e-05 0.0 2.9390624999999998e-05 0.0 2.9391183035714285e-05 1.5 2.939453125e-05 1.5 2.9395089285714285e-05 0.0 2.940848214285714e-05 0.0 2.9409040178571427e-05 1.5 2.941238839285714e-05 1.5 2.9412946428571427e-05 0.0 2.9426339285714282e-05 0.0 2.942689732142857e-05 1.5 2.943080357142857e-05 1.5 2.9431361607142856e-05 0.0 2.944363839285714e-05 0.0 2.9444196428571425e-05 1.5 2.9448660714285712e-05 1.5 2.944921875e-05 0.0 2.9461495535714284e-05 0.0 2.946205357142857e-05 1.5 2.9466517857142854e-05 1.5 2.946707589285714e-05 0.0 2.9479352678571426e-05 0.0 2.9479910714285713e-05 1.5 2.9484374999999997e-05 1.5 2.9484933035714283e-05 0.0 2.949720982142857e-05 0.0 2.9497767857142855e-05 1.5 2.9502232142857142e-05 1.5 2.9502790178571426e-05 0.0 2.951506696428571e-05 0.0 2.9515624999999997e-05 1.5 2.9520089285714285e-05 1.5 2.9520647321428568e-05 0.0 2.9532924107142856e-05 0.0 2.953348214285714e-05 1.5 2.9537946428571427e-05 1.5 2.9538504464285714e-05 0.0 2.955078125e-05 0.0 2.9551339285714282e-05 1.5 2.955580357142857e-05 1.5 2.9556361607142856e-05 0.0 2.956863839285714e-05 0.0 2.9569196428571428e-05 1.5 2.9573660714285712e-05 1.5 2.957421875e-05 0.0 2.9586495535714283e-05 0.0 2.958705357142857e-05 1.5 2.9591517857142854e-05 1.5 2.959207589285714e-05 0.0 2.9604352678571426e-05 0.0 2.9604910714285712e-05 1.5 2.9609933035714283e-05 1.5 2.961049107142857e-05 0.0 2.9621651785714285e-05 0.0 2.9622209821428568e-05 1.5 2.9627790178571425e-05 1.5 2.9628348214285712e-05 0.0 2.9639508928571427e-05 0.0 2.9640066964285714e-05 1.5 2.9645647321428568e-05 1.5 2.9646205357142855e-05 0.0 2.965736607142857e-05 0.0 2.9657924107142856e-05 1.5 2.9663504464285713e-05 1.5 2.9664062499999997e-05 0.0 2.967522321428571e-05 0.0 2.967578125e-05 1.5 2.9681361607142856e-05 1.5 2.968191964285714e-05 0.0 2.9693080357142854e-05 0.0 2.969363839285714e-05 1.5 2.9699218749999998e-05 1.5 2.9699776785714285e-05 0.0 2.9710937499999996e-05 0.0 2.9711495535714283e-05 1.5 2.971707589285714e-05 1.5 2.9717633928571427e-05 0.0 2.9728794642857142e-05 0.0 2.9729352678571425e-05 1.5 2.9734933035714283e-05 1.5 2.973549107142857e-05 0.0 2.9746651785714284e-05 0.0 2.9747209821428568e-05 1.5 2.9752790178571425e-05 1.5 2.9753348214285712e-05 0.0 2.9764508928571427e-05 0.0 2.9765066964285713e-05 1.5 2.977064732142857e-05 1.5 2.9771205357142854e-05 0.0 2.9781808035714282e-05 0.0 2.978236607142857e-05 1.5 2.9789062499999996e-05 1.5 2.9789620535714283e-05 0.0 2.9799665178571428e-05 0.0 2.980022321428571e-05 1.5 2.9806919642857142e-05 1.5 2.9807477678571426e-05 0.0 2.981752232142857e-05 0.0 2.9818080357142854e-05 1.5 2.9824776785714285e-05 1.5 2.9825334821428568e-05 0.0 2.9835379464285713e-05 0.0 2.98359375e-05 1.5 2.9842633928571427e-05 1.5 2.9843191964285714e-05 0.0 2.9853236607142855e-05 0.0 2.985379464285714e-05 1.5 2.986049107142857e-05 1.5 2.9861049107142856e-05 0.0 2.9871093749999997e-05 0.0 2.9871651785714284e-05 1.5 2.987834821428571e-05 1.5 2.9878906249999998e-05 0.0 2.988895089285714e-05 0.0 2.9889508928571426e-05 1.5 2.9896205357142854e-05 1.5 2.989676339285714e-05 0.0 2.9906808035714285e-05 0.0 2.990736607142857e-05 1.5 2.99140625e-05 1.5 2.9914620535714283e-05 0.0 2.9924665178571428e-05 0.0 2.992522321428571e-05 1.5 2.9931919642857142e-05 1.5 2.9932477678571425e-05 0.0 2.9941964285714283e-05 0.0 2.994252232142857e-05 1.5 2.995033482142857e-05 1.5 2.9950892857142854e-05 0.0 2.9959821428571425e-05 0.0 2.9960379464285712e-05 1.5 2.9968191964285713e-05 1.5 2.9968749999999997e-05 0.0 2.9977678571428568e-05 0.0 2.9978236607142855e-05 1.5 2.9986049107142856e-05 1.5 2.9986607142857142e-05 0.0 2.9995535714285713e-05 0.0 2.9996093749999997e-05 1.5 3.0003906249999998e-05 1.5 3.0004464285714285e-05 0.0 3.0013392857142856e-05 0.0 3.001395089285714e-05 1.5 3.002176339285714e-05 1.5 3.0022321428571427e-05 0.0 3.0031249999999998e-05 0.0 3.0031808035714285e-05 1.5 3.0039620535714283e-05 1.5 3.004017857142857e-05 0.0 3.004910714285714e-05 0.0 3.0049665178571427e-05 1.5 3.0057477678571425e-05 1.5 3.005803571428571e-05 0.0 3.0066964285714283e-05 0.0 3.006752232142857e-05 1.5 3.007533482142857e-05 1.5 3.0075892857142854e-05 0.0 3.0084821428571425e-05 0.0 3.0085379464285712e-05 1.5 3.0093191964285713e-05 1.5 3.0093749999999996e-05 0.0 3.0102120535714284e-05 0.0 3.010267857142857e-05 1.5 3.0111607142857142e-05 1.5 3.0112165178571425e-05 0.0 3.0119977678571426e-05 0.0 3.0120535714285713e-05 1.5 3.0129464285714284e-05 1.5 3.0130022321428568e-05 0.0 3.013783482142857e-05 0.0 3.0138392857142855e-05 1.5 3.0147321428571427e-05 1.5 3.0147879464285713e-05 0.0 3.015569196428571e-05 0.0 3.0156249999999998e-05 1.5 3.016517857142857e-05 1.5 3.0165736607142856e-05 0.0 3.0173549107142853e-05 0.0 3.017410714285714e-05 1.5 3.018303571428571e-05 1.5 3.0183593749999998e-05 0.0 3.019140625e-05 0.0 3.0191964285714282e-05 1.5 3.0200892857142854e-05 1.5 3.020145089285714e-05 0.0 3.020926339285714e-05 0.0 3.0209821428571425e-05 1.5 3.021875e-05 1.5 3.0219308035714283e-05 0.0 3.0227120535714284e-05 0.0 3.022767857142857e-05 1.5 3.023660714285714e-05 1.5 3.0237165178571425e-05 0.0 3.0244977678571426e-05 0.0 3.0245535714285713e-05 1.5 3.0254464285714284e-05 1.5 3.025502232142857e-05 0.0 3.0262276785714285e-05 0.0 3.026283482142857e-05 1.5 3.0272879464285713e-05 1.5 3.0273437499999996e-05 0.0 3.0280133928571427e-05 0.0 3.028069196428571e-05 1.5 3.0290736607142855e-05 1.5 3.0291294642857142e-05 0.0 3.029799107142857e-05 0.0 3.0298549107142856e-05 1.5 3.0308593749999998e-05 1.5 3.0309151785714284e-05 0.0 3.0315848214285712e-05 0.0 3.031640625e-05 1.5 3.032645089285714e-05 1.5 3.0327008928571427e-05 0.0 3.0333705357142854e-05 0.0 3.033426339285714e-05 1.5 3.0344308035714282e-05 1.5 3.034486607142857e-05 0.0 3.0351562499999997e-05 0.0 3.0352120535714283e-05 1.5 3.0362165178571428e-05 1.5 3.036272321428571e-05 0.0 3.0369419642857142e-05 0.0 3.0369977678571426e-05 1.5 3.038002232142857e-05 1.5 3.0380580357142854e-05 0.0 3.0387276785714285e-05 0.0 3.0387834821428568e-05 1.5 3.0397879464285713e-05 1.5 3.03984375e-05 0.0 3.0405133928571427e-05 0.0 3.0405691964285714e-05 1.5 3.0415736607142855e-05 1.5 3.0416294642857142e-05 0.0 3.0422433035714283e-05 0.0 3.042299107142857e-05 1.5 3.0434151785714284e-05 1.5 3.043470982142857e-05 0.0 3.0440290178571425e-05 0.0 3.044084821428571e-05 1.5 3.0452008928571426e-05 1.5 3.0452566964285713e-05 0.0 3.045814732142857e-05 0.0 3.0458705357142854e-05 1.5 3.046986607142857e-05 1.5 3.0470424107142855e-05 0.0 3.0476004464285713e-05 0.0 3.0476562499999996e-05 1.5 3.048772321428571e-05 1.5 3.0488281249999998e-05 0.0 3.0493861607142855e-05 0.0 3.0494419642857142e-05 1.5 3.0505580357142853e-05 1.5 3.050613839285714e-05 0.0 3.0511718749999998e-05 0.0 3.0512276785714284e-05 1.5 3.05234375e-05 1.5 3.052399553571428e-05 0.0 3.052957589285714e-05 0.0 3.0530133928571427e-05 1.5 3.054129464285714e-05 1.5 3.0541852678571425e-05 0.0 3.0547433035714286e-05 0.0 3.054799107142857e-05 1.5 3.0559151785714284e-05 1.5 3.055970982142857e-05 0.0 3.056529017857143e-05 0.0 3.056584821428571e-05 1.5 3.0577008928571426e-05 1.5 3.057756696428571e-05 0.0 3.058314732142857e-05 0.0 3.0583705357142854e-05 1.5 3.059542410714285e-05 1.5 3.059598214285714e-05 0.0 3.060044642857143e-05 0.0 3.060100446428571e-05 1.5 3.061328125e-05 1.5 3.0613839285714284e-05 0.0 3.061830357142857e-05 0.0 3.0618861607142855e-05 1.5 3.063113839285714e-05 1.5 3.0631696428571427e-05 0.0 3.0636160714285714e-05 0.0 3.063671875e-05 1.5 3.0648995535714285e-05 1.5 3.064955357142857e-05 0.0 3.0654017857142856e-05 0.0 3.065457589285714e-05 1.5 3.066685267857143e-05 1.5 3.066741071428571e-05 0.0 3.0671875e-05 0.0 3.067243303571428e-05 1.5 3.068470982142857e-05 1.5 3.0685267857142854e-05 0.0 3.068973214285714e-05 0.0 3.0690290178571424e-05 1.5 3.070256696428571e-05 1.5 3.0703124999999996e-05 0.0 3.070758928571428e-05 0.0 3.0708147321428566e-05 1.5 3.0720424107142855e-05 1.5 3.072098214285714e-05 0.0 3.0725446428571425e-05 0.0 3.072600446428571e-05 1.5 3.073828125e-05 1.5 3.073883928571428e-05 0.0 3.074330357142857e-05 0.0 3.074386160714286e-05 1.5 3.075613839285714e-05 1.5 3.075669642857143e-05 0.0 3.076116071428571e-05 0.0 3.076171875e-05 1.5 3.077455357142857e-05 1.5 3.0775111607142855e-05 0.0 3.077845982142857e-05 0.0 3.077901785714285e-05 1.5 3.0792410714285714e-05 1.5 3.079296875e-05 0.0 3.079631696428571e-05 0.0 3.0796874999999995e-05 1.5 3.0810267857142857e-05 1.5 3.081082589285714e-05 0.0 3.0814174107142854e-05 0.0 3.0814732142857144e-05 1.5 3.0828125e-05 1.5 3.082868303571428e-05 0.0 3.0832031249999996e-05 0.0 3.0832589285714286e-05 1.5 3.084598214285714e-05 1.5 3.0846540178571425e-05 0.0 3.084988839285714e-05 0.0 3.085044642857143e-05 1.5 3.0863839285714284e-05 1.5 3.086439732142857e-05 0.0 3.086774553571428e-05 0.0 3.086830357142857e-05 1.5 3.0881696428571426e-05 1.5 3.088225446428571e-05 0.0 3.088560267857143e-05 0.0 3.088616071428571e-05 1.5 3.089955357142857e-05 1.5 3.090011160714286e-05 0.0 3.090345982142857e-05 0.0 3.0904017857142855e-05 1.5 3.091741071428571e-05 1.5 3.091796875e-05 0.0 3.0921316964285714e-05 0.0 3.0921875e-05 1.5 3.093526785714285e-05 1.5 3.093582589285714e-05 0.0 3.093917410714286e-05 0.0 3.093973214285714e-05 1.5 3.0953124999999995e-05 1.5 3.0953683035714285e-05 0.0 3.095703125e-05 0.0 3.095758928571428e-05 1.5 3.097154017857143e-05 1.5 3.097209821428571e-05 0.0 3.097433035714286e-05 0.0 3.097488839285714e-05 1.5 3.098939732142857e-05 1.5 3.098995535714285e-05 0.0 3.09921875e-05 0.0 3.0992745535714284e-05 1.5 3.100725446428571e-05 1.5 3.1007812499999996e-05 0.0 3.101004464285714e-05 0.0 3.1010602678571426e-05 1.5 3.1025111607142855e-05 1.5 3.102566964285714e-05 0.0 3.1027901785714285e-05 0.0 3.102845982142857e-05 1.5 3.104296875e-05 1.5 3.104352678571428e-05 0.0 3.104575892857143e-05 0.0 3.104631696428571e-05 1.5 3.106082589285714e-05 1.5 3.106138392857143e-05 0.0 3.106361607142857e-05 0.0 3.106417410714285e-05 1.5 3.107868303571428e-05 1.5 3.107924107142857e-05 0.0 3.108147321428571e-05 0.0 3.1082031249999995e-05 1.5 3.1096540178571424e-05 1.5 3.1097098214285714e-05 0.0 3.1099330357142854e-05 0.0 3.109988839285714e-05 1.5 3.1114397321428566e-05 1.5 3.1114955357142856e-05 0.0 3.1117187499999997e-05 0.0 3.111774553571429e-05 1.5 3.1132254464285715e-05 1.5 3.11328125e-05 0.0 3.113504464285714e-05 0.0 3.113560267857143e-05 1.5 3.115011160714286e-05 1.5 3.115066964285714e-05 0.0 3.115290178571428e-05 0.0 3.115345982142857e-05 1.5 3.116796875e-05 1.5 3.116852678571428e-05 0.0 3.1170758928571424e-05 0.0 3.1171316964285714e-05 1.5 3.1186383928571426e-05 1.5 3.118694196428571e-05 0.0 3.118805803571428e-05 0.0 3.1188616071428566e-05 1.5 3.120424107142857e-05 1.5 3.120479910714286e-05 0.0 3.1205915178571425e-05 0.0 3.1206473214285715e-05 1.5 3.122209821428571e-05 1.5 3.122265625e-05 0.0 3.122377232142857e-05 0.0 3.122433035714286e-05 1.5 3.123995535714285e-05 1.5 3.124051339285714e-05 0.0 3.124162946428571e-05 0.0 3.12421875e-05 1.5 3.1257812499999995e-05 1.5 3.1258370535714285e-05 0.0 3.125948660714285e-05 0.0 3.126004464285714e-05 1.5 3.127566964285714e-05 1.5 3.127622767857143e-05 0.0 3.127734375e-05 0.0 3.1277901785714284e-05 1.5 3.1293526785714286e-05 1.5 3.129408482142857e-05 0.0 3.129520089285714e-05 0.0 3.1295758928571427e-05 1.5 3.131138392857143e-05 1.5 3.131194196428571e-05 0.0 3.1313058035714286e-05 0.0 3.131361607142857e-05 1.5 3.132924107142857e-05 1.5 3.1329799107142854e-05 0.0 3.133091517857143e-05 0.0 3.133147321428571e-05 1.5 3.134709821428571e-05 1.5 3.134765625e-05 0.0 3.134877232142857e-05 0.0 3.1349330357142854e-05 1.5 3.1364955357142856e-05 1.5 3.136551339285714e-05 0.0 3.136662946428571e-05 0.0 3.1367187499999996e-05 1.5 3.13828125e-05 1.5 3.138337053571428e-05 0.0 3.1384486607142855e-05 0.0 3.138504464285714e-05 1.5 3.140066964285714e-05 1.5 3.1401227678571424e-05 0.0 3.140234375e-05 0.0 3.140290178571428e-05 1.5 3.141852678571428e-05 1.5 3.1419084821428566e-05 0.0 3.142020089285714e-05 0.0 3.142075892857143e-05 1.5 3.1436383928571425e-05 1.5 3.1436941964285715e-05 0.0 3.143805803571428e-05 0.0 3.143861607142857e-05 1.5 3.145424107142857e-05 1.5 3.145479910714286e-05 0.0 3.1455915178571424e-05 0.0 3.1456473214285714e-05 1.5 3.147265625e-05 1.5 3.147321428571428e-05 0.0 3.147321428571428e-05 0.0 3.1473772321428566e-05 1.5 3.149051339285714e-05 1.5 3.1491071428571425e-05 0.0 3.1491071428571425e-05 0.0 3.149162946428571e-05 1.5 3.1508370535714284e-05 1.5 3.150892857142857e-05 0.0 3.150892857142857e-05 0.0 3.150948660714286e-05 1.5 3.152622767857143e-05 1.5 3.152678571428571e-05 0.0 3.152678571428571e-05 0.0 3.152734375e-05 1.5 3.154408482142857e-05 1.5 3.154464285714285e-05 0.0 3.154464285714285e-05 0.0 3.154520089285714e-05 1.5 3.156194196428571e-05 1.5 3.1562499999999995e-05 0.0 3.1562499999999995e-05 0.0 3.1563058035714285e-05 1.5 3.1579799107142854e-05 1.5 3.1580357142857144e-05 0.0 3.1580357142857144e-05 0.0 3.158091517857143e-05 1.5 3.1597656249999996e-05 1.5 3.1598214285714286e-05 0.0 3.1598214285714286e-05 0.0 3.159877232142857e-05 1.5 3.161551339285714e-05 1.5 3.161607142857143e-05 0.0 3.161607142857143e-05 0.0 3.161662946428571e-05 1.5 3.163337053571428e-05 1.5 3.163392857142857e-05 0.0 3.163392857142857e-05 0.0 3.1634486607142854e-05 1.5 3.165122767857142e-05 1.5 3.165178571428571e-05 0.0 3.165178571428571e-05 0.0 3.1652343749999996e-05 1.5 3.166908482142857e-05 1.5 3.1669642857142855e-05 0.0 3.1669642857142855e-05 0.0 3.167020089285714e-05 1.5 3.1686941964285714e-05 1.5 3.16875e-05 0.0 3.16875e-05 0.0 3.168805803571428e-05 1.5 3.170479910714286e-05 1.5 3.170535714285714e-05 0.0 3.170535714285714e-05 0.0 3.1705915178571423e-05 1.5 3.172265625e-05 1.5 3.172321428571428e-05 0.0 3.172321428571428e-05 0.0 3.172377232142857e-05 1.5 3.174051339285714e-05 1.5 3.1741071428571425e-05 0.0 3.1741071428571425e-05 0.0 3.1741629464285715e-05 1.5 3.1758370535714284e-05 1.5 3.175892857142857e-05 0.0 3.175892857142857e-05 0.0 3.175948660714286e-05 1.5 3.1776227678571426e-05 1.5 3.177678571428571e-05 0.0 3.177678571428571e-05 0.0 3.177734375e-05 1.5 3.179408482142857e-05 1.5 3.179464285714285e-05 0.0 3.179464285714285e-05 0.0 3.179520089285714e-05 1.5 3.181194196428571e-05 1.5 3.18125e-05 0.0 3.18125e-05 0.0 3.1813058035714284e-05 1.5 3.182979910714285e-05 1.5 3.183035714285714e-05 0.0 3.183035714285714e-05 0.0 3.1830915178571426e-05 1.5 3.1847656249999995e-05 1.5 3.1848214285714285e-05 0.0 3.1848214285714285e-05 0.0 3.184877232142857e-05 1.5 3.186551339285714e-05 1.5 3.186607142857143e-05 0.0 3.186607142857143e-05 0.0 3.186662946428571e-05 1.5 3.188337053571429e-05 1.5 3.188392857142857e-05 0.0 3.188392857142857e-05 0.0 3.1884486607142853e-05 1.5 3.190122767857143e-05 1.5 3.190178571428571e-05 0.0 3.190178571428571e-05 0.0 3.1902343749999996e-05 1.5 3.191908482142857e-05 1.5 3.1919642857142855e-05 0.0 3.1919642857142855e-05 0.0 3.192020089285714e-05 1.5 3.1936941964285714e-05 1.5 3.19375e-05 0.0 3.19375e-05 0.0 3.193805803571428e-05 1.5 3.1954799107142856e-05 1.5 3.195535714285714e-05 0.0 3.195535714285714e-05 0.0 3.195591517857143e-05 1.5 3.197265625e-05 1.5 3.197321428571428e-05 0.0 3.197321428571428e-05 0.0 3.197377232142857e-05 1.5 3.199051339285714e-05 1.5 3.1991071428571424e-05 0.0 3.1991071428571424e-05 0.0 3.1991629464285714e-05 1.5 3.200837053571428e-05 1.5 3.2008928571428566e-05 0.0 3.2008928571428566e-05 0.0 3.2009486607142856e-05 1.5 3.2026227678571425e-05 1.5 3.202678571428571e-05 0.0 3.202678571428571e-05 0.0 3.202734375e-05 1.5 3.204408482142857e-05 1.5 3.204464285714286e-05 0.0 3.204464285714286e-05 0.0 3.204520089285714e-05 1.5 3.206194196428571e-05 1.5 3.20625e-05 0.0 3.20625e-05 0.0 3.2063058035714283e-05 1.5 3.207979910714285e-05 1.5 3.208035714285714e-05 0.0 3.208035714285714e-05 0.0 3.2080915178571426e-05 1.5 3.2097656249999995e-05 1.5 3.2098214285714285e-05 0.0 3.2098214285714285e-05 0.0 3.209877232142857e-05 1.5 )"
}
C {devices/vsource.sym} 480 -1610 0 0 {name=vpwm_cosine_75 hide_texts=true value="dc 0 pwl(0.0 1.5 7.2544642857142855e-09 1.5 7.8125e-09 0.0 1.0044642857142856e-08 0.0 1.060267857142857e-08 1.5 2.511160714285714e-08 1.5 2.5669642857142854e-08 0.0 2.7901785714285714e-08 0.0 2.8459821428571428e-08 1.5 4.296875e-08 1.5 4.352678571428571e-08 0.0 4.5758928571428566e-08 0.0 4.6316964285714284e-08 1.5 6.082589285714285e-08 1.5 6.138392857142856e-08 0.0 6.361607142857142e-08 0.0 6.417410714285714e-08 1.5 7.86830357142857e-08 1.5 7.924107142857143e-08 0.0 8.147321428571428e-08 0.0 8.203125e-08 1.5 9.654017857142857e-08 1.5 9.709821428571428e-08 0.0 9.933035714285714e-08 0.0 9.988839285714285e-08 1.5 1.1439732142857142e-07 1.5 1.1495535714285713e-07 0.0 1.1718749999999999e-07 0.0 1.177455357142857e-07 1.5 1.3225446428571427e-07 1.5 1.328125e-07 0.0 1.3504464285714284e-07 0.0 1.3560267857142857e-07 1.5 1.5011160714285713e-07 1.5 1.5066964285714285e-07 0.0 1.529017857142857e-07 0.0 1.5345982142857142e-07 1.5 1.6796874999999998e-07 1.5 1.685267857142857e-07 0.0 1.7075892857142855e-07 0.0 1.7131696428571427e-07 1.5 1.8582589285714283e-07 1.5 1.8638392857142856e-07 0.0 1.8861607142857143e-07 0.0 1.8917410714285712e-07 1.5 2.036830357142857e-07 1.5 2.042410714285714e-07 0.0 2.0647321428571428e-07 0.0 2.0703124999999998e-07 1.5 2.2154017857142856e-07 1.5 2.2209821428571426e-07 0.0 2.2433035714285713e-07 0.0 2.2488839285714283e-07 1.5 2.393973214285714e-07 1.5 2.399553571428571e-07 0.0 2.4218749999999996e-07 0.0 2.427455357142857e-07 1.5 2.5725446428571427e-07 1.5 2.5781249999999997e-07 0.0 2.6004464285714286e-07 0.0 2.6060267857142856e-07 1.5 2.751116071428571e-07 1.5 2.756696428571428e-07 0.0 2.779017857142857e-07 0.0 2.784598214285714e-07 1.5 2.9296875e-07 1.5 2.9352678571428567e-07 0.0 2.9575892857142857e-07 0.0 2.9631696428571427e-07 1.5 3.1082589285714283e-07 1.5 3.113839285714285e-07 0.0 3.136160714285714e-07 0.0 3.141741071428571e-07 1.5 3.286830357142857e-07 1.5 3.2924107142857143e-07 0.0 3.3147321428571427e-07 0.0 3.3203124999999997e-07 1.5 3.4654017857142853e-07 1.5 3.470982142857143e-07 0.0 3.493303571428571e-07 0.0 3.498883928571428e-07 1.5 3.643973214285714e-07 1.5 3.6495535714285714e-07 0.0 3.671875e-07 0.0 3.677455357142857e-07 1.5 3.8225446428571424e-07 1.5 3.828125e-07 0.0 3.8504464285714283e-07 0.0 3.8560267857142853e-07 1.5 4.001116071428571e-07 1.5 4.0066964285714284e-07 0.0 4.029017857142857e-07 0.0 4.034598214285714e-07 1.5 4.1796875e-07 1.5 4.185267857142857e-07 0.0 4.2075892857142854e-07 0.0 4.2131696428571423e-07 1.5 4.3582589285714285e-07 1.5 4.3638392857142855e-07 0.0 4.386160714285714e-07 0.0 4.391741071428571e-07 1.5 4.536830357142857e-07 1.5 4.542410714285714e-07 0.0 4.5647321428571424e-07 0.0 4.5703125e-07 1.5 4.7154017857142855e-07 1.5 4.7209821428571425e-07 0.0 4.743303571428571e-07 0.0 4.7488839285714284e-07 1.5 4.893973214285714e-07 1.5 4.899553571428571e-07 0.0 4.921875e-07 0.0 4.927455357142857e-07 1.5 5.072544642857143e-07 1.5 5.078125e-07 0.0 5.100446428571429e-07 0.0 5.106026785714285e-07 1.5 5.251116071428571e-07 1.5 5.256696428571428e-07 0.0 5.279017857142857e-07 0.0 5.284598214285714e-07 1.5 5.4296875e-07 1.5 5.435267857142857e-07 0.0 5.457589285714286e-07 0.0 5.463169642857143e-07 1.5 5.608258928571428e-07 1.5 5.613839285714285e-07 0.0 5.636160714285714e-07 0.0 5.641741071428571e-07 1.5 5.786830357142857e-07 1.5 5.792410714285714e-07 0.0 5.814732142857143e-07 0.0 5.8203125e-07 1.5 5.965401785714285e-07 1.5 5.970982142857142e-07 0.0 5.993303571428571e-07 0.0 5.998883928571428e-07 1.5 6.143973214285714e-07 1.5 6.149553571428571e-07 0.0 6.171875e-07 0.0 6.177455357142857e-07 1.5 6.322544642857142e-07 1.5 6.328124999999999e-07 0.0 6.350446428571428e-07 0.0 6.356026785714285e-07 1.5 6.501116071428571e-07 1.5 6.506696428571428e-07 0.0 6.529017857142857e-07 0.0 6.534598214285714e-07 1.5 6.679687499999999e-07 1.5 6.685267857142856e-07 0.0 6.707589285714285e-07 0.0 6.713169642857142e-07 1.5 6.858258928571428e-07 1.5 6.863839285714285e-07 0.0 6.886160714285714e-07 0.0 6.891741071428571e-07 1.5 7.036830357142856e-07 1.5 7.042410714285713e-07 0.0 7.064732142857142e-07 0.0 7.070312499999999e-07 1.5 7.215401785714285e-07 1.5 7.220982142857142e-07 0.0 7.243303571428571e-07 0.0 7.248883928571428e-07 1.5 7.393973214285713e-07 1.5 7.39955357142857e-07 0.0 7.421874999999999e-07 0.0 7.427455357142856e-07 1.5 7.566964285714285e-07 1.5 7.572544642857142e-07 0.0 7.606026785714285e-07 0.0 7.611607142857142e-07 1.5 7.745535714285713e-07 1.5 7.75111607142857e-07 0.0 7.784598214285713e-07 0.0 7.79017857142857e-07 1.5 7.924107142857142e-07 1.5 7.929687499999999e-07 0.0 7.963169642857142e-07 0.0 7.96875e-07 1.5 8.102678571428571e-07 1.5 8.108258928571428e-07 0.0 8.14174107142857e-07 0.0 8.147321428571428e-07 1.5 8.281249999999999e-07 1.5 8.286830357142856e-07 0.0 8.320312499999999e-07 0.0 8.325892857142857e-07 1.5 8.459821428571428e-07 1.5 8.465401785714286e-07 0.0 8.498883928571427e-07 0.0 8.504464285714286e-07 1.5 8.638392857142856e-07 1.5 8.643973214285714e-07 0.0 8.677455357142856e-07 0.0 8.683035714285714e-07 1.5 8.816964285714285e-07 1.5 8.822544642857143e-07 0.0 8.856026785714286e-07 0.0 8.861607142857143e-07 1.5 8.995535714285713e-07 1.5 9.001116071428571e-07 0.0 9.034598214285714e-07 0.0 9.040178571428571e-07 1.5 9.174107142857142e-07 1.5 9.1796875e-07 0.0 9.213169642857143e-07 0.0 9.21875e-07 1.5 9.352678571428571e-07 1.5 9.358258928571428e-07 0.0 9.391741071428571e-07 0.0 9.397321428571428e-07 1.5 9.53125e-07 1.5 9.536830357142856e-07 0.0 9.5703125e-07 0.0 9.575892857142857e-07 1.5 9.709821428571428e-07 1.5 9.715401785714285e-07 0.0 9.748883928571427e-07 0.0 9.754464285714284e-07 1.5 9.888392857142856e-07 1.5 9.893973214285713e-07 0.0 9.927455357142857e-07 0.0 9.933035714285714e-07 1.5 1.0066964285714285e-06 1.5 1.0072544642857142e-06 0.0 1.0106026785714284e-06 0.0 1.0111607142857141e-06 1.5 1.0245535714285713e-06 1.5 1.025111607142857e-06 0.0 1.0284598214285714e-06 0.0 1.029017857142857e-06 1.5 1.0424107142857142e-06 1.5 1.04296875e-06 0.0 1.0463169642857141e-06 0.0 1.0468749999999998e-06 1.5 1.060267857142857e-06 1.5 1.0608258928571427e-06 0.0 1.064174107142857e-06 0.0 1.0647321428571428e-06 1.5 1.0775669642857143e-06 1.5 1.078125e-06 0.0 1.0825892857142857e-06 0.0 1.0831473214285714e-06 1.5 1.095424107142857e-06 1.5 1.0959821428571427e-06 0.0 1.1004464285714285e-06 0.0 1.1010044642857142e-06 1.5 1.11328125e-06 1.5 1.1138392857142857e-06 0.0 1.1183035714285714e-06 0.0 1.1188616071428571e-06 1.5 1.1311383928571427e-06 1.5 1.1316964285714284e-06 0.0 1.1361607142857142e-06 0.0 1.1367187499999999e-06 1.5 1.1489955357142857e-06 1.5 1.1495535714285714e-06 0.0 1.1540178571428572e-06 0.0 1.1545758928571428e-06 1.5 1.1668526785714284e-06 1.5 1.167410714285714e-06 0.0 1.171875e-06 0.0 1.1724330357142856e-06 1.5 1.1847098214285714e-06 1.5 1.185267857142857e-06 0.0 1.1897321428571429e-06 0.0 1.1902901785714286e-06 1.5 1.2025669642857141e-06 1.5 1.2031249999999998e-06 0.0 1.2075892857142856e-06 0.0 1.2081473214285713e-06 1.5 1.220424107142857e-06 1.5 1.2209821428571428e-06 0.0 1.2254464285714286e-06 0.0 1.2260044642857143e-06 1.5 1.2382812499999998e-06 1.5 1.2388392857142857e-06 0.0 1.2433035714285713e-06 0.0 1.243861607142857e-06 1.5 1.2561383928571428e-06 1.5 1.2566964285714285e-06 0.0 1.2611607142857143e-06 0.0 1.26171875e-06 1.5 1.2739955357142855e-06 1.5 1.2745535714285714e-06 0.0 1.279017857142857e-06 0.0 1.2795758928571427e-06 1.5 1.2918526785714285e-06 1.5 1.2924107142857142e-06 0.0 1.296875e-06 0.0 1.2974330357142857e-06 1.5 1.3097098214285714e-06 1.5 1.3102678571428571e-06 0.0 1.3147321428571427e-06 0.0 1.3152901785714284e-06 1.5 1.3275669642857142e-06 1.5 1.3281249999999999e-06 0.0 1.3325892857142857e-06 0.0 1.3331473214285714e-06 1.5 1.3448660714285712e-06 1.5 1.3454241071428571e-06 0.0 1.3510044642857141e-06 0.0 1.3515624999999998e-06 1.5 1.3627232142857142e-06 1.5 1.3632812499999999e-06 0.0 1.368861607142857e-06 0.0 1.3694196428571428e-06 1.5 1.380580357142857e-06 1.5 1.3811383928571428e-06 0.0 1.3867187499999998e-06 0.0 1.3872767857142855e-06 1.5 1.3984375e-06 1.5 1.3989955357142856e-06 0.0 1.4045758928571428e-06 0.0 1.4051339285714285e-06 1.5 1.4162946428571429e-06 1.5 1.4168526785714286e-06 0.0 1.4224330357142855e-06 0.0 1.4229910714285712e-06 1.5 1.4341517857142856e-06 1.5 1.4347098214285713e-06 0.0 1.4402901785714285e-06 0.0 1.4408482142857142e-06 1.5 1.4520089285714286e-06 1.5 1.4525669642857143e-06 0.0 1.4581473214285712e-06 0.0 1.458705357142857e-06 1.5 1.4698660714285713e-06 1.5 1.470424107142857e-06 0.0 1.4760044642857142e-06 0.0 1.4765624999999999e-06 1.5 1.4877232142857143e-06 1.5 1.48828125e-06 0.0 1.493861607142857e-06 0.0 1.4944196428571429e-06 1.5 1.505580357142857e-06 1.5 1.5061383928571427e-06 0.0 1.51171875e-06 0.0 1.5122767857142856e-06 1.5 1.5234375e-06 1.5 1.5239955357142857e-06 0.0 1.5295758928571426e-06 0.0 1.5301339285714286e-06 1.5 1.5412946428571427e-06 1.5 1.5418526785714284e-06 0.0 1.5474330357142856e-06 0.0 1.5479910714285713e-06 1.5 1.5591517857142857e-06 1.5 1.5597098214285714e-06 0.0 1.5652901785714286e-06 0.0 1.5658482142857143e-06 1.5 1.5764508928571427e-06 1.5 1.5770089285714284e-06 0.0 1.583705357142857e-06 0.0 1.5842633928571427e-06 1.5 1.5943080357142857e-06 1.5 1.5948660714285714e-06 0.0 1.6015625e-06 0.0 1.6021205357142857e-06 1.5 1.6121651785714284e-06 1.5 1.6127232142857141e-06 0.0 1.6194196428571427e-06 0.0 1.6199776785714284e-06 1.5 1.6300223214285714e-06 1.5 1.630580357142857e-06 0.0 1.6372767857142857e-06 0.0 1.6378348214285714e-06 1.5 1.6478794642857141e-06 1.5 1.6484374999999998e-06 0.0 1.6551339285714284e-06 0.0 1.6556919642857141e-06 1.5 1.665736607142857e-06 1.5 1.6662946428571428e-06 0.0 1.6729910714285714e-06 0.0 1.673549107142857e-06 1.5 1.6835937499999998e-06 1.5 1.6841517857142855e-06 0.0 1.6908482142857141e-06 0.0 1.6914062499999998e-06 1.5 1.7014508928571428e-06 1.5 1.7020089285714285e-06 0.0 1.708705357142857e-06 0.0 1.7092633928571428e-06 1.5 1.7193080357142855e-06 1.5 1.7198660714285712e-06 0.0 1.7265624999999998e-06 0.0 1.7271205357142855e-06 1.5 1.7371651785714285e-06 1.5 1.7377232142857142e-06 0.0 1.7444196428571428e-06 0.0 1.7449776785714285e-06 1.5 1.7550223214285713e-06 1.5 1.755580357142857e-06 0.0 1.7622767857142855e-06 0.0 1.7628348214285712e-06 1.5 1.7728794642857142e-06 1.5 1.7734375e-06 0.0 1.7801339285714285e-06 0.0 1.7806919642857142e-06 1.5 1.790736607142857e-06 1.5 1.7912946428571427e-06 0.0 1.798549107142857e-06 0.0 1.7991071428571426e-06 1.5 1.8080357142857142e-06 1.5 1.80859375e-06 0.0 1.8164062499999999e-06 0.0 1.8169642857142856e-06 1.5 1.825892857142857e-06 1.5 1.8264508928571427e-06 0.0 1.8342633928571426e-06 0.0 1.8348214285714283e-06 1.5 1.84375e-06 1.5 1.8443080357142856e-06 0.0 1.8521205357142856e-06 0.0 1.8526785714285713e-06 1.5 1.8616071428571427e-06 1.5 1.8621651785714284e-06 0.0 1.8699776785714283e-06 0.0 1.8705357142857143e-06 1.5 1.8794642857142856e-06 1.5 1.8800223214285713e-06 0.0 1.8878348214285713e-06 0.0 1.888392857142857e-06 1.5 1.8973214285714284e-06 1.5 1.897879464285714e-06 0.0 1.905691964285714e-06 0.0 1.90625e-06 1.5 1.9151785714285713e-06 1.5 1.915736607142857e-06 0.0 1.923549107142857e-06 0.0 1.924107142857143e-06 1.5 1.933035714285714e-06 1.5 1.93359375e-06 0.0 1.9414062499999998e-06 0.0 1.9419642857142857e-06 1.5 1.950892857142857e-06 1.5 1.9514508928571427e-06 0.0 1.959263392857143e-06 0.0 1.9598214285714284e-06 1.5 1.96875e-06 1.5 1.9693080357142855e-06 0.0 1.9771205357142857e-06 0.0 1.977678571428571e-06 1.5 1.9866071428571427e-06 1.5 1.9871651785714282e-06 0.0 1.9949776785714284e-06 0.0 1.9955357142857143e-06 1.5 2.0044642857142855e-06 1.5 2.0050223214285714e-06 0.0 2.013392857142857e-06 0.0 2.0139508928571426e-06 1.5 2.0217633928571428e-06 1.5 2.0223214285714282e-06 0.0 2.03125e-06 0.0 2.0318080357142857e-06 1.5 2.0396205357142855e-06 1.5 2.0401785714285714e-06 0.0 2.0491071428571426e-06 0.0 2.0496651785714285e-06 1.5 2.0574776785714282e-06 1.5 2.058035714285714e-06 0.0 2.0669642857142857e-06 0.0 2.0675223214285712e-06 1.5 2.0753348214285714e-06 1.5 2.075892857142857e-06 0.0 2.0848214285714285e-06 0.0 2.085379464285714e-06 1.5 2.093191964285714e-06 1.5 2.0937499999999996e-06 0.0 2.1026785714285712e-06 0.0 2.103236607142857e-06 1.5 2.111049107142857e-06 1.5 2.111607142857143e-06 0.0 2.120535714285714e-06 0.0 2.12109375e-06 1.5 2.1289062499999997e-06 1.5 2.1294642857142856e-06 0.0 2.138392857142857e-06 0.0 2.1389508928571426e-06 1.5 2.146763392857143e-06 1.5 2.1473214285714283e-06 0.0 2.15625e-06 0.0 2.1568080357142854e-06 1.5 2.1646205357142856e-06 1.5 2.1651785714285715e-06 0.0 2.1741071428571426e-06 0.0 2.1746651785714286e-06 1.5 2.1824776785714283e-06 1.5 2.1830357142857142e-06 0.0 2.1919642857142854e-06 0.0 2.1925223214285713e-06 1.5 2.200334821428571e-06 1.5 2.200892857142857e-06 0.0 2.2098214285714286e-06 0.0 2.210379464285714e-06 1.5 2.2181919642857142e-06 1.5 2.2187499999999997e-06 0.0 2.228236607142857e-06 0.0 2.2287946428571427e-06 1.5 2.235491071428571e-06 1.5 2.236049107142857e-06 0.0 2.24609375e-06 0.0 2.2466517857142854e-06 1.5 2.2533482142857142e-06 1.5 2.2539062499999997e-06 0.0 2.2639508928571427e-06 0.0 2.2645089285714286e-06 1.5 2.271205357142857e-06 1.5 2.271763392857143e-06 0.0 2.2818080357142855e-06 0.0 2.2823660714285714e-06 1.5 2.2890624999999997e-06 1.5 2.2896205357142856e-06 0.0 2.299665178571428e-06 0.0 2.300223214285714e-06 1.5 2.3069196428571425e-06 1.5 2.3074776785714284e-06 0.0 2.3175223214285714e-06 0.0 2.318080357142857e-06 1.5 2.3247767857142857e-06 1.5 2.325334821428571e-06 0.0 2.335379464285714e-06 0.0 2.3359375e-06 1.5 2.3426339285714284e-06 1.5 2.3431919642857143e-06 0.0 2.353236607142857e-06 0.0 2.3537946428571428e-06 1.5 2.360491071428571e-06 1.5 2.361049107142857e-06 0.0 2.37109375e-06 0.0 2.3716517857142855e-06 1.5 2.3783482142857143e-06 1.5 2.37890625e-06 0.0 2.3889508928571428e-06 0.0 2.3895089285714283e-06 1.5 2.396205357142857e-06 1.5 2.3967633928571425e-06 0.0 2.4068080357142855e-06 0.0 2.4073660714285714e-06 1.5 2.4140625e-06 1.5 2.4146205357142857e-06 0.0 2.4246651785714283e-06 0.0 2.425223214285714e-06 1.5 2.4319196428571426e-06 1.5 2.4324776785714285e-06 0.0 2.443080357142857e-06 0.0 2.443638392857143e-06 1.5 2.44921875e-06 1.5 2.4497767857142857e-06 0.0 2.4609374999999997e-06 0.0 2.4614955357142856e-06 1.5 2.4670758928571426e-06 1.5 2.4676339285714285e-06 0.0 2.478794642857143e-06 0.0 2.4793526785714283e-06 1.5 2.4849330357142857e-06 1.5 2.4854910714285712e-06 0.0 2.4966517857142856e-06 0.0 2.497209821428571e-06 1.5 2.5027901785714285e-06 1.5 2.503348214285714e-06 0.0 2.5145089285714283e-06 0.0 2.5150669642857143e-06 1.5 2.5206473214285712e-06 1.5 2.521205357142857e-06 0.0 2.532366071428571e-06 0.0 2.532924107142857e-06 1.5 2.538504464285714e-06 1.5 2.5390625e-06 0.0 2.5502232142857143e-06 0.0 2.5507812499999997e-06 1.5 2.556361607142857e-06 1.5 2.5569196428571426e-06 0.0 2.568080357142857e-06 0.0 2.5686383928571425e-06 1.5 2.57421875e-06 1.5 2.5747767857142854e-06 0.0 2.5859374999999998e-06 0.0 2.5864955357142857e-06 1.5 2.5920758928571426e-06 1.5 2.5926339285714285e-06 0.0 2.6037946428571425e-06 0.0 2.6043526785714284e-06 1.5 2.6099330357142854e-06 1.5 2.6104910714285713e-06 0.0 2.6216517857142857e-06 0.0 2.622209821428571e-06 1.5 2.6277901785714286e-06 1.5 2.628348214285714e-06 0.0 2.6395089285714284e-06 0.0 2.640066964285714e-06 1.5 2.6456473214285713e-06 1.5 2.6462053571428568e-06 0.0 2.657366071428571e-06 0.0 2.657924107142857e-06 1.5 2.663504464285714e-06 1.5 2.6640625e-06 0.0 2.67578125e-06 0.0 2.6763392857142857e-06 1.5 2.6808035714285713e-06 1.5 2.681361607142857e-06 0.0 2.6936383928571426e-06 0.0 2.6941964285714285e-06 1.5 2.698660714285714e-06 1.5 2.69921875e-06 0.0 2.7114955357142853e-06 0.0 2.7120535714285712e-06 1.5 2.716517857142857e-06 1.5 2.7170758928571427e-06 0.0 2.7293526785714285e-06 0.0 2.729910714285714e-06 1.5 2.734375e-06 1.5 2.7349330357142855e-06 0.0 2.7472098214285712e-06 0.0 2.747767857142857e-06 1.5 2.7522321428571427e-06 1.5 2.752790178571428e-06 0.0 2.765066964285714e-06 0.0 2.765625e-06 1.5 2.7700892857142855e-06 1.5 2.7706473214285714e-06 0.0 2.782924107142857e-06 0.0 2.7834821428571426e-06 1.5 2.7879464285714282e-06 1.5 2.788504464285714e-06 0.0 2.80078125e-06 0.0 2.8013392857142854e-06 1.5 2.8058035714285714e-06 1.5 2.806361607142857e-06 0.0 2.8186383928571426e-06 0.0 2.8191964285714285e-06 1.5 2.823660714285714e-06 1.5 2.8242187499999996e-06 0.0 2.8364955357142854e-06 0.0 2.8370535714285713e-06 1.5 2.841517857142857e-06 1.5 2.8420758928571428e-06 0.0 2.8543526785714286e-06 0.0 2.854910714285714e-06 1.5 2.8593749999999996e-06 1.5 2.8599330357142855e-06 0.0 2.8722098214285713e-06 0.0 2.872767857142857e-06 1.5 2.877232142857143e-06 1.5 2.8777901785714283e-06 0.0 2.890066964285714e-06 0.0 2.890625e-06 1.5 2.8950892857142855e-06 1.5 2.895647321428571e-06 0.0 2.907924107142857e-06 0.0 2.9084821428571427e-06 1.5 2.9129464285714283e-06 1.5 2.913504464285714e-06 0.0 2.92578125e-06 0.0 2.9263392857142855e-06 1.5 2.930803571428571e-06 1.5 2.931361607142857e-06 0.0 2.944196428571428e-06 0.0 2.944754464285714e-06 1.5 2.9481026785714283e-06 1.5 2.948660714285714e-06 0.0 2.9620535714285714e-06 0.0 2.962611607142857e-06 1.5 2.965959821428571e-06 1.5 2.966517857142857e-06 0.0 2.979910714285714e-06 0.0 2.9804687499999996e-06 1.5 2.983816964285714e-06 1.5 2.9843749999999997e-06 0.0 2.997767857142857e-06 0.0 2.9983258928571428e-06 1.5 3.001674107142857e-06 1.5 3.0022321428571424e-06 0.0 3.0156249999999996e-06 0.0 3.0161830357142855e-06 1.5 3.0195312499999997e-06 1.5 3.0200892857142856e-06 0.0 3.0334821428571428e-06 0.0 3.0340401785714283e-06 1.5 3.0373883928571425e-06 1.5 3.0379464285714284e-06 0.0 3.0513392857142855e-06 0.0 3.051897321428571e-06 1.5 3.0552455357142856e-06 1.5 3.055803571428571e-06 0.0 3.0691964285714283e-06 0.0 3.069754464285714e-06 1.5 3.0731026785714284e-06 1.5 3.0736607142857143e-06 0.0 3.087053571428571e-06 0.0 3.087611607142857e-06 1.5 3.090959821428571e-06 1.5 3.091517857142857e-06 0.0 3.104910714285714e-06 0.0 3.1054687499999997e-06 1.5 3.108816964285714e-06 1.5 3.1093749999999998e-06 0.0 3.122767857142857e-06 0.0 3.1233258928571424e-06 1.5 3.126674107142857e-06 1.5 3.1272321428571425e-06 0.0 3.1406249999999997e-06 0.0 3.1411830357142856e-06 1.5 3.1445312499999998e-06 1.5 3.1450892857142857e-06 0.0 3.1584821428571424e-06 0.0 3.1590401785714283e-06 1.5 3.1623883928571425e-06 1.5 3.1629464285714284e-06 0.0 3.1763392857142856e-06 0.0 3.176897321428571e-06 1.5 3.1802455357142857e-06 1.5 3.180803571428571e-06 0.0 3.1941964285714283e-06 0.0 3.1947544642857143e-06 1.5 3.1981026785714284e-06 1.5 3.198660714285714e-06 0.0 3.212053571428571e-06 0.0 3.212611607142857e-06 1.5 3.215959821428571e-06 1.5 3.216517857142857e-06 0.0 3.2299107142857143e-06 0.0 3.2304687499999997e-06 1.5 3.233816964285714e-06 1.5 3.234375e-06 0.0 3.247767857142857e-06 0.0 3.2483258928571425e-06 1.5 3.251674107142857e-06 1.5 3.2522321428571426e-06 0.0 3.2661830357142857e-06 0.0 3.266741071428571e-06 1.5 3.268973214285714e-06 1.5 3.26953125e-06 0.0 3.2840401785714284e-06 0.0 3.284598214285714e-06 1.5 3.286830357142857e-06 1.5 3.2873883928571426e-06 0.0 3.301897321428571e-06 0.0 3.302455357142857e-06 1.5 3.3046875e-06 1.5 3.3052455357142853e-06 0.0 3.319754464285714e-06 0.0 3.3203125e-06 1.5 3.3225446428571426e-06 1.5 3.3231026785714285e-06 0.0 3.337611607142857e-06 0.0 3.3381696428571426e-06 1.5 3.3404017857142854e-06 1.5 3.3409598214285713e-06 0.0 3.35546875e-06 0.0 3.3560267857142853e-06 1.5 3.3582589285714285e-06 1.5 3.358816964285714e-06 0.0 3.3733258928571426e-06 0.0 3.3738839285714285e-06 1.5 3.3761160714285713e-06 1.5 3.3766741071428568e-06 0.0 3.3911830357142853e-06 0.0 3.3917410714285712e-06 1.5 3.393973214285714e-06 1.5 3.39453125e-06 0.0 3.4090401785714285e-06 0.0 3.409598214285714e-06 1.5 3.4118303571428568e-06 1.5 3.4123883928571427e-06 0.0 3.4268973214285712e-06 0.0 3.4274553571428567e-06 1.5 3.4296875e-06 1.5 3.4302455357142854e-06 0.0 3.444754464285714e-06 0.0 3.4453125e-06 1.5 3.4475446428571427e-06 1.5 3.448102678571428e-06 0.0 3.4626116071428567e-06 0.0 3.4631696428571426e-06 1.5 3.4654017857142854e-06 1.5 3.4659598214285713e-06 0.0 3.48046875e-06 0.0 3.4810267857142854e-06 1.5 3.483258928571428e-06 1.5 3.483816964285714e-06 0.0 3.4983258928571426e-06 0.0 3.498883928571428e-06 1.5 3.5011160714285713e-06 1.5 3.501674107142857e-06 0.0 3.5161830357142854e-06 0.0 3.5167410714285713e-06 1.5 3.518973214285714e-06 1.5 3.5195312499999996e-06 0.0 3.534040178571428e-06 0.0 3.534598214285714e-06 1.5 3.536830357142857e-06 1.5 3.5373883928571427e-06 0.0 3.5518973214285713e-06 0.0 3.552455357142857e-06 1.5 3.5546874999999996e-06 1.5 3.5552455357142855e-06 0.0 3.569754464285714e-06 0.0 3.5703124999999995e-06 1.5 3.5725446428571428e-06 1.5 3.5731026785714282e-06 0.0 3.587611607142857e-06 0.0 3.5881696428571427e-06 1.5 3.5904017857142855e-06 1.5 3.590959821428571e-06 0.0 3.6054687499999995e-06 0.0 3.6060267857142855e-06 1.5 3.6082589285714282e-06 1.5 3.608816964285714e-06 0.0 3.6233258928571427e-06 0.0 3.623883928571428e-06 1.5 3.626116071428571e-06 1.5 3.626674107142857e-06 0.0 3.6411830357142855e-06 0.0 3.6417410714285714e-06 1.5 3.643973214285714e-06 1.5 3.6445312499999996e-06 0.0 3.659040178571428e-06 0.0 3.659598214285714e-06 1.5 3.661830357142857e-06 1.5 3.6623883928571424e-06 0.0 3.676897321428571e-06 0.0 3.677455357142857e-06 1.5 3.6796874999999997e-06 1.5 3.6802455357142856e-06 0.0 3.694754464285714e-06 0.0 3.6953124999999996e-06 1.5 3.6975446428571424e-06 1.5 3.6981026785714283e-06 0.0 3.712611607142857e-06 0.0 3.7131696428571428e-06 1.5 3.7154017857142856e-06 1.5 3.715959821428571e-06 0.0 3.7304687499999996e-06 0.0 3.7310267857142855e-06 1.5 3.7332589285714283e-06 1.5 3.7338169642857142e-06 0.0 3.748325892857143e-06 0.0 3.7488839285714283e-06 1.5 3.751116071428571e-06 1.5 3.751674107142857e-06 0.0 3.7661830357142855e-06 0.0 3.766741071428571e-06 1.5 3.768973214285714e-06 1.5 3.7695312499999997e-06 0.0 3.7840401785714283e-06 0.0 3.784598214285714e-06 1.5 3.786830357142857e-06 1.5 3.7873883928571425e-06 0.0 3.801897321428571e-06 0.0 3.802455357142857e-06 1.5 3.8046874999999997e-06 1.5 3.8052455357142856e-06 0.0 3.819754464285714e-06 0.0 3.8203125e-06 1.5 3.8225446428571425e-06 1.5 3.823102678571428e-06 0.0 3.837611607142857e-06 0.0 3.838169642857143e-06 1.5 3.840401785714286e-06 1.5 3.8409598214285716e-06 0.0 3.85546875e-06 0.0 3.856026785714285e-06 1.5 3.858258928571428e-06 1.5 3.858816964285714e-06 0.0 3.8733258928571424e-06 0.0 3.873883928571428e-06 1.5 3.876116071428571e-06 1.5 3.876674107142857e-06 0.0 3.891183035714286e-06 0.0 3.8917410714285715e-06 1.5 3.893973214285714e-06 1.5 3.894531249999999e-06 0.0 3.909040178571428e-06 0.0 3.909598214285714e-06 1.5 3.911830357142857e-06 1.5 3.9123883928571425e-06 0.0 3.926897321428571e-06 0.0 3.927455357142857e-06 1.5 3.9296875e-06 1.5 3.930245535714286e-06 0.0 3.944754464285714e-06 0.0 3.945312499999999e-06 1.5 3.947544642857143e-06 1.5 3.948102678571428e-06 0.0 3.962611607142857e-06 0.0 3.9631696428571425e-06 1.5 3.965401785714285e-06 1.5 3.965959821428571e-06 0.0 3.98046875e-06 0.0 3.981026785714286e-06 1.5 3.9832589285714285e-06 1.5 3.983816964285714e-06 0.0 3.998325892857143e-06 0.0 3.998883928571428e-06 1.5 4.001116071428571e-06 1.5 4.001674107142857e-06 0.0 4.016183035714285e-06 0.0 4.016741071428571e-06 1.5 4.018973214285714e-06 1.5 4.01953125e-06 0.0 4.0340401785714284e-06 0.0 4.034598214285714e-06 1.5 4.036830357142857e-06 1.5 4.037388392857142e-06 0.0 4.051897321428571e-06 0.0 4.052455357142857e-06 1.5 4.0546874999999995e-06 1.5 4.055245535714285e-06 0.0 4.069754464285714e-06 0.0 4.0703125e-06 1.5 4.072544642857143e-06 1.5 4.0731026785714285e-06 0.0 4.087611607142857e-06 0.0 4.088169642857142e-06 1.5 4.090401785714286e-06 1.5 4.090959821428571e-06 0.0 4.105468749999999e-06 0.0 4.106026785714285e-06 1.5 4.108258928571428e-06 1.5 4.108816964285714e-06 0.0 4.123325892857143e-06 0.0 4.1238839285714285e-06 1.5 4.126116071428571e-06 1.5 4.126674107142857e-06 0.0 4.141183035714286e-06 0.0 4.141741071428571e-06 1.5 4.143973214285714e-06 1.5 4.1445312499999995e-06 0.0 4.159040178571428e-06 0.0 4.159598214285714e-06 1.5 4.161830357142857e-06 1.5 4.162388392857143e-06 0.0 4.176897321428571e-06 0.0 4.177455357142857e-06 1.5 4.1796875e-06 1.5 4.180245535714285e-06 0.0 4.1947544642857136e-06 0.0 4.1953124999999995e-06 1.5 4.197544642857142e-06 1.5 4.198102678571428e-06 0.0 4.212611607142857e-06 0.0 4.213169642857143e-06 1.5 4.2154017857142854e-06 1.5 4.215959821428571e-06 0.0 4.23046875e-06 0.0 4.231026785714286e-06 1.5 4.233258928571429e-06 1.5 4.233816964285714e-06 0.0 4.248325892857142e-06 0.0 4.248883928571428e-06 1.5 4.251116071428571e-06 1.5 4.251674107142857e-06 0.0 4.266183035714285e-06 0.0 4.266741071428571e-06 1.5 4.268973214285714e-06 1.5 4.26953125e-06 0.0 4.284040178571429e-06 0.0 4.284598214285714e-06 1.5 4.2868303571428564e-06 1.5 4.287388392857142e-06 0.0 4.301897321428571e-06 0.0 4.302455357142857e-06 1.5 4.3046875e-06 1.5 4.3052455357142855e-06 0.0 4.319754464285714e-06 0.0 4.3203125e-06 1.5 4.322544642857143e-06 1.5 4.323102678571429e-06 0.0 4.337611607142857e-06 0.0 4.338169642857142e-06 1.5 4.340401785714285e-06 1.5 4.340959821428571e-06 0.0 4.3554687499999996e-06 0.0 4.3560267857142855e-06 1.5 4.358258928571428e-06 1.5 4.358816964285714e-06 0.0 4.373325892857143e-06 0.0 4.373883928571429e-06 1.5 4.3761160714285714e-06 1.5 4.3766741071428565e-06 0.0 4.391183035714285e-06 0.0 4.391741071428571e-06 1.5 4.393973214285714e-06 1.5 4.39453125e-06 0.0 4.409040178571428e-06 0.0 4.409598214285714e-06 1.5 4.411830357142857e-06 1.5 4.412388392857143e-06 0.0 4.426897321428571e-06 0.0 4.4274553571428565e-06 1.5 4.4296875e-06 1.5 4.430245535714285e-06 0.0 4.444754464285714e-06 0.0 4.4453125e-06 1.5 4.447544642857142e-06 1.5 4.448102678571428e-06 0.0 4.462611607142857e-06 0.0 4.463169642857143e-06 1.5 4.465401785714286e-06 1.5 4.4659598214285715e-06 0.0 4.48046875e-06 0.0 4.481026785714285e-06 1.5 4.483258928571428e-06 1.5 4.483816964285714e-06 0.0 4.498325892857142e-06 0.0 4.498883928571428e-06 1.5 4.501116071428571e-06 1.5 4.501674107142857e-06 0.0 4.5161830357142856e-06 0.0 4.5167410714285715e-06 1.5 4.518973214285714e-06 1.5 4.519531249999999e-06 0.0 4.534040178571428e-06 0.0 4.534598214285714e-06 1.5 4.536830357142857e-06 1.5 4.5373883928571425e-06 0.0 4.551897321428571e-06 0.0 4.552455357142857e-06 1.5 4.5546875e-06 1.5 4.555245535714286e-06 0.0 4.569754464285714e-06 0.0 4.570312499999999e-06 1.5 4.572544642857143e-06 1.5 4.573102678571428e-06 0.0 4.5876116071428565e-06 0.0 4.5881696428571425e-06 1.5 4.590401785714285e-06 1.5 4.590959821428571e-06 0.0 4.60546875e-06 0.0 4.606026785714286e-06 1.5 4.608258928571428e-06 1.5 4.608816964285714e-06 0.0 4.623325892857143e-06 0.0 4.623883928571428e-06 1.5 4.626116071428571e-06 1.5 4.626674107142857e-06 0.0 4.641183035714285e-06 0.0 4.641741071428571e-06 1.5 4.643973214285714e-06 1.5 4.64453125e-06 0.0 4.659040178571428e-06 0.0 4.659598214285714e-06 1.5 4.661830357142857e-06 1.5 4.662388392857142e-06 0.0 4.676897321428571e-06 0.0 4.677455357142857e-06 1.5 4.679687499999999e-06 1.5 4.680245535714285e-06 0.0 4.694754464285714e-06 0.0 4.6953125e-06 1.5 4.6975446428571426e-06 1.5 4.6981026785714285e-06 0.0 4.712611607142857e-06 0.0 4.713169642857142e-06 1.5 4.715401785714286e-06 1.5 4.715959821428571e-06 0.0 4.730468749999999e-06 0.0 4.731026785714285e-06 1.5 4.733258928571428e-06 1.5 4.733816964285714e-06 0.0 4.7483258928571425e-06 0.0 4.7488839285714284e-06 1.5 4.751116071428571e-06 1.5 4.751674107142857e-06 0.0 4.765625e-06 0.0 4.766183035714286e-06 1.5 4.7695312499999995e-06 1.5 4.770089285714285e-06 0.0 4.783482142857142e-06 0.0 4.784040178571428e-06 1.5 4.787388392857143e-06 1.5 4.7879464285714285e-06 0.0 4.801339285714285e-06 0.0 4.801897321428571e-06 1.5 4.805245535714285e-06 1.5 4.805803571428571e-06 0.0 4.8191964285714285e-06 0.0 4.8197544642857135e-06 1.5 4.823102678571428e-06 1.5 4.823660714285714e-06 0.0 4.837053571428571e-06 0.0 4.837611607142857e-06 1.5 4.840959821428571e-06 1.5 4.841517857142857e-06 0.0 4.854910714285714e-06 0.0 4.85546875e-06 1.5 4.858816964285714e-06 1.5 4.8593749999999995e-06 0.0 4.872767857142857e-06 0.0 4.873325892857142e-06 1.5 4.876674107142857e-06 1.5 4.877232142857143e-06 0.0 4.8906249999999994e-06 0.0 4.891183035714285e-06 1.5 4.89453125e-06 1.5 4.895089285714285e-06 0.0 4.908482142857143e-06 0.0 4.9090401785714285e-06 1.5 4.912388392857142e-06 1.5 4.912946428571428e-06 0.0 4.926339285714285e-06 0.0 4.926897321428571e-06 1.5 4.9302455357142855e-06 1.5 4.930803571428571e-06 0.0 4.944196428571428e-06 0.0 4.944754464285714e-06 1.5 4.948102678571429e-06 1.5 4.948660714285714e-06 0.0 4.962053571428571e-06 0.0 4.962611607142857e-06 1.5 4.965959821428571e-06 1.5 4.966517857142857e-06 0.0 4.979910714285714e-06 0.0 4.9804687499999995e-06 1.5 4.983816964285714e-06 1.5 4.984375e-06 0.0 4.997767857142857e-06 0.0 4.998325892857143e-06 1.5 5.0016741071428564e-06 1.5 5.002232142857142e-06 0.0 5.015625e-06 0.0 5.016183035714285e-06 1.5 5.01953125e-06 1.5 5.0200892857142855e-06 0.0 5.033482142857142e-06 0.0 5.034040178571428e-06 1.5 5.037388392857143e-06 1.5 5.037946428571428e-06 0.0 5.0513392857142854e-06 0.0 5.051897321428571e-06 1.5 5.055245535714285e-06 1.5 5.055803571428571e-06 0.0 5.069196428571429e-06 0.0 5.069754464285714e-06 1.5 5.073102678571428e-06 1.5 5.073660714285714e-06 0.0 5.087053571428571e-06 0.0 5.087611607142857e-06 1.5 5.0915178571428565e-06 1.5 5.092075892857142e-06 0.0 5.104352678571428e-06 0.0 5.104910714285714e-06 1.5 5.109375e-06 1.5 5.109933035714286e-06 0.0 5.122209821428571e-06 0.0 5.122767857142856e-06 1.5 5.127232142857143e-06 1.5 5.127790178571428e-06 0.0 5.140066964285714e-06 0.0 5.140625e-06 1.5 5.145089285714285e-06 1.5 5.145647321428571e-06 0.0 5.157924107142857e-06 0.0 5.158482142857143e-06 1.5 5.162946428571428e-06 1.5 5.163504464285714e-06 0.0 5.17578125e-06 0.0 5.176339285714285e-06 1.5 5.180803571428571e-06 1.5 5.1813616071428566e-06 0.0 5.193638392857142e-06 0.0 5.194196428571428e-06 1.5 5.198660714285714e-06 1.5 5.19921875e-06 0.0 5.2114955357142855e-06 0.0 5.2120535714285714e-06 1.5 5.216517857142857e-06 1.5 5.217075892857142e-06 0.0 5.229352678571428e-06 0.0 5.229910714285714e-06 1.5 5.234374999999999e-06 1.5 5.234933035714285e-06 0.0 5.247209821428571e-06 0.0 5.247767857142857e-06 1.5 5.2522321428571425e-06 1.5 5.252790178571428e-06 0.0 5.265066964285714e-06 0.0 5.265624999999999e-06 1.5 5.270089285714286e-06 1.5 5.270647321428571e-06 0.0 5.2829241071428565e-06 0.0 5.283482142857142e-06 1.5 5.287946428571428e-06 1.5 5.288504464285714e-06 0.0 5.30078125e-06 0.0 5.301339285714286e-06 1.5 5.305803571428571e-06 1.5 5.306361607142857e-06 0.0 5.318638392857143e-06 0.0 5.319196428571428e-06 1.5 5.3236607142857135e-06 1.5 5.324218749999999e-06 0.0 5.336495535714285e-06 0.0 5.337053571428571e-06 1.5 5.341517857142857e-06 1.5 5.3420758928571426e-06 0.0 5.3537946428571424e-06 0.0 5.354352678571428e-06 1.5 5.359933035714286e-06 1.5 5.360491071428571e-06 0.0 5.371651785714286e-06 0.0 5.372209821428571e-06 1.5 5.377790178571428e-06 1.5 5.378348214285714e-06 0.0 5.389508928571428e-06 0.0 5.390066964285714e-06 1.5 5.395647321428571e-06 1.5 5.396205357142857e-06 0.0 5.407366071428571e-06 0.0 5.407924107142857e-06 1.5 5.4135044642857136e-06 1.5 5.4140624999999995e-06 0.0 5.425223214285714e-06 0.0 5.425781249999999e-06 1.5 5.431361607142857e-06 1.5 5.431919642857143e-06 0.0 5.443080357142857e-06 0.0 5.4436383928571425e-06 1.5 5.44921875e-06 1.5 5.449776785714285e-06 0.0 5.4609375e-06 0.0 5.461495535714286e-06 1.5 5.467075892857142e-06 1.5 5.467633928571428e-06 0.0 5.478794642857142e-06 0.0 5.479352678571428e-06 1.5 5.484933035714285e-06 1.5 5.485491071428571e-06 0.0 5.496651785714285e-06 0.0 5.497209821428571e-06 1.5 5.5027901785714286e-06 1.5 5.503348214285714e-06 0.0 5.514508928571428e-06 0.0 5.5150669642857135e-06 1.5 5.520647321428571e-06 1.5 5.521205357142857e-06 0.0 5.532366071428571e-06 0.0 5.532924107142857e-06 1.5 5.538504464285714e-06 1.5 5.5390625e-06 0.0 5.550223214285714e-06 0.0 5.55078125e-06 1.5 5.556361607142856e-06 1.5 5.556919642857142e-06 0.0 5.568080357142857e-06 0.0 5.568638392857142e-06 1.5 5.5742187499999995e-06 1.5 5.5747767857142855e-06 0.0 5.5853794642857135e-06 0.0 5.585937499999999e-06 1.5 5.592633928571428e-06 1.5 5.593191964285714e-06 0.0 5.603236607142857e-06 0.0 5.6037946428571426e-06 1.5 5.610491071428571e-06 1.5 5.611049107142857e-06 0.0 5.62109375e-06 0.0 5.621651785714285e-06 1.5 5.628348214285714e-06 1.5 5.628906249999999e-06 0.0 5.638950892857142e-06 0.0 5.639508928571428e-06 1.5 5.6462053571428564e-06 1.5 5.646763392857142e-06 0.0 5.656808035714285e-06 0.0 5.657366071428571e-06 1.5 5.6640625e-06 1.5 5.6646205357142855e-06 0.0 5.6746651785714285e-06 0.0 5.6752232142857136e-06 1.5 5.681919642857143e-06 1.5 5.682477678571428e-06 0.0 5.692522321428571e-06 0.0 5.693080357142857e-06 1.5 5.699776785714285e-06 1.5 5.700334821428571e-06 0.0 5.710379464285714e-06 0.0 5.7109375e-06 1.5 5.717633928571428e-06 1.5 5.718191964285714e-06 0.0 5.728236607142856e-06 0.0 5.728794642857142e-06 1.5 5.735491071428571e-06 1.5 5.7360491071428565e-06 0.0 5.7460937499999995e-06 0.0 5.746651785714285e-06 1.5 5.753348214285714e-06 1.5 5.75390625e-06 0.0 5.763950892857143e-06 0.0 5.7645089285714286e-06 1.5 5.771205357142857e-06 1.5 5.771763392857143e-06 0.0 5.781808035714285e-06 0.0 5.782366071428571e-06 1.5 5.789062499999999e-06 1.5 5.789620535714285e-06 0.0 5.799665178571428e-06 0.0 5.800223214285714e-06 1.5 5.807477678571428e-06 1.5 5.808035714285714e-06 0.0 5.816964285714285e-06 0.0 5.817522321428571e-06 1.5 5.825334821428571e-06 1.5 5.8258928571428566e-06 0.0 5.834821428571428e-06 0.0 5.835379464285714e-06 1.5 5.843191964285714e-06 1.5 5.84375e-06 0.0 5.852678571428571e-06 0.0 5.853236607142857e-06 1.5 5.861049107142857e-06 1.5 5.861607142857142e-06 0.0 5.870535714285714e-06 0.0 5.87109375e-06 1.5 5.878906249999999e-06 1.5 5.879464285714285e-06 0.0 5.888392857142856e-06 0.0 5.888950892857142e-06 1.5 5.8967633928571425e-06 1.5 5.897321428571428e-06 0.0 5.9062499999999996e-06 0.0 5.9068080357142855e-06 1.5 5.914620535714286e-06 1.5 5.915178571428571e-06 0.0 5.924107142857143e-06 0.0 5.924665178571428e-06 1.5 5.932477678571428e-06 1.5 5.933035714285714e-06 0.0 5.941964285714285e-06 0.0 5.942522321428571e-06 1.5 5.950334821428571e-06 1.5 5.950892857142857e-06 0.0 5.959821428571428e-06 0.0 5.960379464285714e-06 1.5 5.9681919642857135e-06 1.5 5.968749999999999e-06 0.0 5.977678571428571e-06 0.0 5.9782366071428565e-06 1.5 5.986049107142857e-06 1.5 5.9866071428571426e-06 0.0 5.995535714285714e-06 0.0 5.99609375e-06 1.5 6.00390625e-06 1.5 6.004464285714285e-06 0.0 6.013392857142857e-06 0.0 6.013950892857143e-06 1.5 6.022321428571428e-06 1.5 6.022879464285714e-06 0.0 6.030691964285714e-06 0.0 6.031249999999999e-06 1.5 6.040178571428571e-06 1.5 6.040736607142856e-06 0.0 6.0485491071428565e-06 0.0 6.049107142857142e-06 1.5 6.0580357142857135e-06 1.5 6.0585937499999995e-06 0.0 6.06640625e-06 0.0 6.0669642857142856e-06 1.5 6.075892857142857e-06 1.5 6.076450892857143e-06 0.0 6.084263392857143e-06 0.0 6.084821428571428e-06 1.5 6.09375e-06 1.5 6.094308035714285e-06 0.0 6.102120535714285e-06 0.0 6.102678571428571e-06 1.5 6.111607142857142e-06 1.5 6.112165178571428e-06 0.0 6.119977678571428e-06 0.0 6.120535714285714e-06 1.5 6.129464285714285e-06 1.5 6.130022321428571e-06 0.0 6.137834821428571e-06 0.0 6.1383928571428565e-06 1.5 6.1473214285714286e-06 1.5 6.147879464285714e-06 0.0 6.155691964285714e-06 0.0 6.15625e-06 1.5 6.165178571428571e-06 1.5 6.165736607142857e-06 0.0 6.173549107142857e-06 0.0 6.174107142857142e-06 1.5 6.183035714285714e-06 1.5 6.18359375e-06 0.0 6.191406249999999e-06 0.0 6.191964285714285e-06 1.5 6.200892857142856e-06 1.5 6.201450892857142e-06 0.0 6.2092633928571425e-06 0.0 6.209821428571428e-06 1.5 6.2187499999999995e-06 1.5 6.2193080357142854e-06 0.0 6.227120535714286e-06 0.0 6.227678571428571e-06 1.5 6.237165178571428e-06 1.5 6.237723214285714e-06 0.0 6.244419642857142e-06 0.0 6.244977678571428e-06 1.5 6.255022321428571e-06 1.5 6.255580357142857e-06 0.0 6.262276785714285e-06 0.0 6.262834821428571e-06 1.5 6.272879464285714e-06 1.5 6.273437499999999e-06 0.0 6.280133928571428e-06 0.0 6.2806919642857135e-06 1.5 6.2907366071428564e-06 1.5 6.291294642857142e-06 0.0 6.297991071428571e-06 0.0 6.298549107142857e-06 1.5 6.30859375e-06 1.5 6.3091517857142855e-06 0.0 6.315848214285714e-06 0.0 6.31640625e-06 1.5 6.326450892857143e-06 1.5 6.327008928571428e-06 0.0 6.333705357142857e-06 0.0 6.334263392857142e-06 1.5 6.344308035714285e-06 1.5 6.344866071428571e-06 0.0 6.351562499999999e-06 0.0 6.352120535714285e-06 1.5 6.362165178571428e-06 1.5 6.362723214285714e-06 0.0 6.3694196428571426e-06 0.0 6.3699776785714285e-06 1.5 6.380022321428571e-06 1.5 6.3805803571428565e-06 0.0 6.387276785714285e-06 0.0 6.387834821428571e-06 1.5 6.397879464285714e-06 1.5 6.3984375e-06 0.0 6.405133928571428e-06 0.0 6.405691964285714e-06 1.5 6.415736607142857e-06 1.5 6.416294642857142e-06 0.0 6.422991071428571e-06 0.0 6.423549107142856e-06 1.5 6.433593749999999e-06 1.5 6.434151785714285e-06 0.0 6.4408482142857135e-06 0.0 6.4414062499999994e-06 1.5 6.4514508928571424e-06 1.5 6.452008928571428e-06 0.0 6.458147321428571e-06 0.0 6.458705357142857e-06 1.5 6.469866071428571e-06 1.5 6.4704241071428566e-06 0.0 6.476004464285714e-06 0.0 6.4765625e-06 1.5 6.487723214285714e-06 1.5 6.48828125e-06 0.0 6.493861607142856e-06 0.0 6.494419642857142e-06 1.5 6.505580357142857e-06 1.5 6.506138392857142e-06 0.0 6.5117187499999995e-06 0.0 6.512276785714285e-06 1.5 6.523437499999999e-06 1.5 6.523995535714285e-06 0.0 6.529575892857143e-06 0.0 6.530133928571428e-06 1.5 6.5412946428571425e-06 1.5 6.541852678571428e-06 0.0 6.547433035714285e-06 0.0 6.547991071428571e-06 1.5 6.559151785714286e-06 1.5 6.559709821428571e-06 0.0 6.565290178571428e-06 0.0 6.565848214285714e-06 1.5 6.577008928571428e-06 1.5 6.577566964285714e-06 0.0 6.583147321428571e-06 0.0 6.583705357142856e-06 1.5 6.594866071428571e-06 1.5 6.595424107142857e-06 0.0 6.601004464285714e-06 0.0 6.6015624999999995e-06 1.5 6.6127232142857135e-06 1.5 6.613281249999999e-06 0.0 6.618861607142857e-06 0.0 6.619419642857143e-06 1.5 6.630580357142857e-06 1.5 6.6311383928571426e-06 0.0 6.636718749999999e-06 0.0 6.637276785714285e-06 1.5 6.6484375e-06 1.5 6.648995535714285e-06 0.0 6.654575892857142e-06 0.0 6.655133928571428e-06 1.5 6.666294642857142e-06 1.5 6.666852678571428e-06 0.0 6.6724330357142855e-06 0.0 6.672991071428571e-06 1.5 6.684151785714285e-06 1.5 6.684709821428571e-06 0.0 6.689732142857143e-06 0.0 6.690290178571428e-06 1.5 6.7025669642857135e-06 1.5 6.7031249999999995e-06 0.0 6.707589285714285e-06 0.0 6.708147321428571e-06 1.5 6.720424107142857e-06 1.5 6.720982142857143e-06 0.0 6.725446428571428e-06 0.0 6.726004464285714e-06 1.5 6.73828125e-06 1.5 6.738839285714285e-06 0.0 6.7433035714285705e-06 0.0 6.7438616071428564e-06 1.5 6.756138392857142e-06 1.5 6.756696428571428e-06 0.0 6.761160714285714e-06 0.0 6.76171875e-06 1.5 6.773995535714285e-06 1.5 6.774553571428571e-06 0.0 6.779017857142857e-06 0.0 6.779575892857143e-06 1.5 6.791852678571428e-06 1.5 6.792410714285714e-06 0.0 6.796874999999999e-06 0.0 6.797433035714285e-06 1.5 6.809709821428571e-06 1.5 6.810267857142857e-06 0.0 6.814732142857142e-06 0.0 6.815290178571428e-06 1.5 6.827566964285714e-06 1.5 6.828124999999999e-06 0.0 6.8325892857142855e-06 0.0 6.833147321428571e-06 1.5 6.845424107142856e-06 1.5 6.845982142857142e-06 0.0 6.850446428571428e-06 0.0 6.851004464285714e-06 1.5 6.8632812499999995e-06 1.5 6.8638392857142854e-06 0.0 6.868303571428571e-06 0.0 6.868861607142857e-06 1.5 6.881138392857143e-06 1.5 6.881696428571428e-06 0.0 6.886160714285714e-06 0.0 6.886718749999999e-06 1.5 6.898995535714285e-06 1.5 6.899553571428571e-06 0.0 6.9040178571428565e-06 0.0 6.9045758928571424e-06 1.5 6.916852678571428e-06 1.5 6.917410714285714e-06 0.0 6.921875e-06 0.0 6.922433035714286e-06 1.5 6.9347098214285705e-06 1.5 6.9352678571428564e-06 0.0 6.939732142857142e-06 0.0 6.940290178571428e-06 1.5 6.953125e-06 1.5 6.9536830357142855e-06 0.0 6.957031249999999e-06 0.0 6.957589285714285e-06 1.5 6.970982142857143e-06 1.5 6.971540178571428e-06 0.0 6.9748883928571424e-06 0.0 6.975446428571428e-06 1.5 6.988839285714285e-06 1.5 6.989397321428571e-06 0.0 6.992745535714286e-06 0.0 6.993303571428571e-06 1.5 7.006696428571428e-06 1.5 7.007254464285714e-06 0.0 7.010602678571428e-06 0.0 7.011160714285714e-06 1.5 7.024553571428571e-06 1.5 7.0251116071428565e-06 0.0 7.028459821428571e-06 0.0 7.029017857142857e-06 1.5 7.042410714285714e-06 1.5 7.04296875e-06 0.0 7.0463169642857134e-06 0.0 7.046874999999999e-06 1.5 7.060267857142857e-06 1.5 7.060825892857142e-06 0.0 7.064174107142857e-06 0.0 7.0647321428571425e-06 1.5 7.078124999999999e-06 1.5 7.078683035714285e-06 0.0 7.08203125e-06 0.0 7.082589285714285e-06 1.5 7.095982142857142e-06 1.5 7.096540178571428e-06 0.0 7.099888392857142e-06 0.0 7.100446428571428e-06 1.5 7.113839285714286e-06 1.5 7.114397321428571e-06 0.0 7.117745535714285e-06 0.0 7.118303571428571e-06 1.5 7.131696428571428e-06 1.5 7.132254464285714e-06 0.0 7.1356026785714284e-06 0.0 7.1361607142857135e-06 1.5 7.149553571428571e-06 1.5 7.150111607142857e-06 0.0 7.153459821428571e-06 0.0 7.154017857142857e-06 1.5 7.167410714285713e-06 1.5 7.167968749999999e-06 0.0 7.171316964285714e-06 0.0 7.171875e-06 1.5 7.185267857142857e-06 1.5 7.1858258928571425e-06 0.0 7.189174107142856e-06 0.0 7.189732142857142e-06 1.5 7.203125e-06 1.5 7.203683035714285e-06 0.0 7.207031249999999e-06 0.0 7.207589285714285e-06 1.5 7.220982142857142e-06 1.5 7.221540178571428e-06 0.0 7.224888392857143e-06 0.0 7.225446428571428e-06 1.5 7.238839285714285e-06 1.5 7.239397321428571e-06 0.0 7.242745535714285e-06 0.0 7.243303571428571e-06 1.5 7.256696428571428e-06 1.5 7.2572544642857135e-06 0.0 7.260602678571428e-06 0.0 7.261160714285714e-06 1.5 7.274553571428571e-06 1.5 7.275111607142857e-06 0.0 7.277901785714285e-06 0.0 7.278459821428571e-06 1.5 7.29296875e-06 1.5 7.293526785714285e-06 0.0 7.295758928571428e-06 0.0 7.296316964285714e-06 1.5 7.310825892857142e-06 1.5 7.311383928571428e-06 0.0 7.313616071428571e-06 0.0 7.314174107142857e-06 1.5 7.328683035714285e-06 1.5 7.329241071428571e-06 0.0 7.331473214285714e-06 0.0 7.332031249999999e-06 1.5 7.346540178571428e-06 1.5 7.3470982142857135e-06 0.0 7.349330357142856e-06 0.0 7.349888392857142e-06 1.5 7.364397321428571e-06 1.5 7.364955357142857e-06 0.0 7.3671874999999995e-06 0.0 7.367745535714285e-06 1.5 7.382254464285714e-06 1.5 7.3828125e-06 0.0 7.385044642857143e-06 0.0 7.385602678571428e-06 1.5 7.400111607142856e-06 1.5 7.400669642857142e-06 0.0 7.402901785714285e-06 0.0 7.403459821428571e-06 1.5 7.4179687499999995e-06 1.5 7.418526785714285e-06 0.0 7.420758928571428e-06 0.0 7.421316964285714e-06 1.5 7.435825892857143e-06 1.5 7.436383928571428e-06 0.0 7.4386160714285705e-06 0.0 7.439174107142856e-06 1.5 7.453683035714285e-06 1.5 7.454241071428571e-06 0.0 7.456473214285714e-06 0.0 7.4570312499999996e-06 1.5 7.471540178571428e-06 1.5 7.472098214285714e-06 0.0 7.474330357142857e-06 0.0 7.474888392857143e-06 1.5 7.489397321428571e-06 1.5 7.489955357142856e-06 0.0 7.492187499999999e-06 0.0 7.492745535714285e-06 1.5 7.507254464285714e-06 1.5 7.5078124999999995e-06 0.0 7.510044642857142e-06 0.0 7.510602678571428e-06 1.5 7.525111607142857e-06 1.5 7.525669642857143e-06 0.0 7.5279017857142855e-06 0.0 7.5284598214285706e-06 1.5 7.542968749999999e-06 1.5 7.543526785714285e-06 0.0 7.545758928571428e-06 0.0 7.546316964285714e-06 1.5 7.560825892857142e-06 1.5 7.561383928571428e-06 0.0 7.563616071428571e-06 0.0 7.564174107142857e-06 1.5 7.5786830357142855e-06 1.5 7.5792410714285705e-06 0.0 7.581473214285714e-06 0.0 7.582031249999999e-06 1.5 7.596540178571428e-06 1.5 7.597098214285714e-06 0.0 7.5993303571428565e-06 0.0 7.599888392857142e-06 1.5 7.614397321428571e-06 1.5 7.614955357142857e-06 0.0 7.6171875e-06 0.0 7.6177455357142856e-06 1.5 7.632254464285713e-06 1.5 7.6328125e-06 0.0 7.635044642857142e-06 0.0 7.635602678571429e-06 1.5 7.650111607142857e-06 1.5 7.650669642857142e-06 0.0 7.652901785714286e-06 0.0 7.653459821428571e-06 1.5 7.66796875e-06 1.5 7.668526785714285e-06 0.0 7.670758928571428e-06 0.0 7.671316964285713e-06 1.5 7.685825892857142e-06 1.5 7.686383928571429e-06 0.0 7.68861607142857e-06 0.0 7.689174107142857e-06 1.5 7.703683035714286e-06 1.5 7.704241071428571e-06 0.0 7.706473214285713e-06 0.0 7.70703125e-06 1.5 7.721540178571428e-06 1.5 7.722098214285713e-06 0.0 7.724330357142857e-06 0.0 7.724888392857142e-06 1.5 7.73939732142857e-06 1.5 7.739955357142857e-06 0.0 7.7421875e-06 0.0 7.742745535714284e-06 1.5 7.757254464285713e-06 1.5 7.7578125e-06 0.0 7.760044642857142e-06 0.0 7.760602678571428e-06 1.5 7.775111607142857e-06 1.5 7.775669642857142e-06 0.0 7.777901785714286e-06 0.0 7.77845982142857e-06 1.5 7.79296875e-06 1.5 7.793526785714284e-06 0.0 7.795758928571428e-06 0.0 7.796316964285713e-06 1.5 7.810825892857142e-06 1.5 7.811383928571428e-06 0.0 7.81361607142857e-06 0.0 7.814174107142857e-06 1.5 7.828683035714286e-06 1.5 7.82924107142857e-06 0.0 7.831473214285714e-06 0.0 7.83203125e-06 1.5 7.846540178571428e-06 1.5 7.847098214285713e-06 0.0 7.849330357142857e-06 0.0 7.849888392857142e-06 1.5 7.86439732142857e-06 1.5 7.864955357142857e-06 0.0 7.867187499999999e-06 0.0 7.867745535714286e-06 1.5 7.882254464285714e-06 1.5 7.8828125e-06 0.0 7.885044642857143e-06 0.0 7.885602678571428e-06 1.5 7.900111607142857e-06 1.5 7.900669642857142e-06 0.0 7.902901785714285e-06 0.0 7.90345982142857e-06 1.5 7.917968749999999e-06 1.5 7.918526785714286e-06 0.0 7.920758928571428e-06 0.0 7.921316964285714e-06 1.5 7.935825892857143e-06 1.5 7.936383928571428e-06 0.0 7.938616071428572e-06 0.0 7.939174107142857e-06 1.5 7.953683035714285e-06 1.5 7.95424107142857e-06 0.0 7.956473214285714e-06 0.0 7.957031249999999e-06 1.5 7.971540178571428e-06 1.5 7.972098214285714e-06 0.0 7.974330357142856e-06 0.0 7.974888392857143e-06 1.5 7.989397321428572e-06 1.5 7.989955357142857e-06 0.0 7.992187499999999e-06 0.0 7.992745535714285e-06 1.5 8.007254464285714e-06 1.5 8.007812499999999e-06 0.0 8.010044642857143e-06 0.0 8.010602678571428e-06 1.5 8.025111607142856e-06 1.5 8.025669642857143e-06 0.0 8.027901785714285e-06 0.0 8.028459821428572e-06 1.5 8.04296875e-06 1.5 8.043526785714285e-06 0.0 8.045758928571427e-06 0.0 8.046316964285714e-06 1.5 8.060825892857143e-06 1.5 8.061383928571428e-06 0.0 8.063616071428571e-06 0.0 8.064174107142856e-06 1.5 8.078683035714285e-06 1.5 8.079241071428572e-06 0.0 8.081473214285714e-06 0.0 8.082031249999999e-06 1.5 8.096540178571427e-06 1.5 8.097098214285714e-06 0.0 8.099330357142856e-06 0.0 8.099888392857143e-06 1.5 8.114397321428571e-06 1.5 8.114955357142856e-06 0.0 8.1171875e-06 0.0 8.117745535714285e-06 1.5 8.132254464285714e-06 1.5 8.132812499999999e-06 0.0 8.135044642857142e-06 0.0 8.135602678571427e-06 1.5 8.150111607142856e-06 1.5 8.150669642857143e-06 0.0 8.152901785714285e-06 0.0 8.153459821428571e-06 1.5 8.16796875e-06 1.5 8.168526785714285e-06 0.0 8.170758928571429e-06 0.0 8.171316964285714e-06 1.5 8.185825892857142e-06 1.5 8.186383928571427e-06 0.0 8.188616071428571e-06 0.0 8.189174107142856e-06 1.5 8.203683035714285e-06 1.5 8.204241071428571e-06 0.0 8.206473214285713e-06 0.0 8.20703125e-06 1.5 8.221540178571429e-06 1.5 8.222098214285714e-06 0.0 8.224330357142857e-06 0.0 8.224888392857142e-06 1.5 8.239397321428571e-06 1.5 8.239955357142856e-06 0.0 8.2421875e-06 0.0 8.242745535714285e-06 1.5 8.257254464285713e-06 1.5 8.2578125e-06 0.0 8.260044642857142e-06 0.0 8.260602678571429e-06 1.5 8.275111607142857e-06 1.5 8.275669642857142e-06 0.0 8.277901785714286e-06 0.0 8.278459821428571e-06 1.5 8.29296875e-06 1.5 8.293526785714285e-06 0.0 8.295758928571428e-06 0.0 8.296316964285713e-06 1.5 8.310825892857142e-06 1.5 8.311383928571429e-06 0.0 8.31361607142857e-06 0.0 8.314174107142857e-06 1.5 8.328683035714286e-06 1.5 8.329241071428571e-06 0.0 8.331473214285713e-06 0.0 8.33203125e-06 1.5 8.346540178571428e-06 1.5 8.347098214285713e-06 0.0 8.349330357142857e-06 0.0 8.349888392857142e-06 1.5 8.36439732142857e-06 1.5 8.364955357142857e-06 0.0 8.3671875e-06 0.0 8.367745535714284e-06 1.5 8.382254464285713e-06 1.5 8.3828125e-06 0.0 8.385044642857142e-06 0.0 8.385602678571428e-06 1.5 8.400111607142857e-06 1.5 8.400669642857142e-06 0.0 8.402901785714286e-06 0.0 8.40345982142857e-06 1.5 8.41796875e-06 1.5 8.418526785714284e-06 0.0 8.420758928571428e-06 0.0 8.421316964285713e-06 1.5 8.435825892857142e-06 1.5 8.436383928571428e-06 0.0 8.43861607142857e-06 0.0 8.439174107142857e-06 1.5 8.453683035714286e-06 1.5 8.45424107142857e-06 0.0 8.456473214285714e-06 0.0 8.45703125e-06 1.5 8.471540178571428e-06 1.5 8.472098214285713e-06 0.0 8.474330357142857e-06 0.0 8.474888392857142e-06 1.5 8.48939732142857e-06 1.5 8.489955357142857e-06 0.0 8.492187499999999e-06 0.0 8.492745535714286e-06 1.5 8.507254464285714e-06 1.5 8.5078125e-06 0.0 8.510044642857143e-06 0.0 8.510602678571428e-06 1.5 8.525111607142857e-06 1.5 8.525669642857142e-06 0.0 8.527901785714285e-06 0.0 8.52845982142857e-06 1.5 8.542968749999999e-06 1.5 8.543526785714286e-06 0.0 8.545758928571428e-06 0.0 8.546316964285714e-06 1.5 8.560825892857143e-06 1.5 8.561383928571428e-06 0.0 8.563616071428572e-06 0.0 8.564174107142857e-06 1.5 8.578683035714285e-06 1.5 8.57924107142857e-06 0.0 8.581473214285714e-06 0.0 8.582031249999999e-06 1.5 8.596540178571428e-06 1.5 8.597098214285714e-06 0.0 8.599330357142856e-06 0.0 8.599888392857143e-06 1.5 8.614397321428572e-06 1.5 8.614955357142857e-06 0.0 8.617187499999999e-06 0.0 8.617745535714285e-06 1.5 8.632254464285714e-06 1.5 8.632812499999999e-06 0.0 8.635044642857143e-06 0.0 8.635602678571428e-06 1.5 8.650111607142856e-06 1.5 8.650669642857143e-06 0.0 8.652901785714285e-06 0.0 8.653459821428572e-06 1.5 8.66796875e-06 1.5 8.668526785714285e-06 0.0 8.670758928571427e-06 0.0 8.671316964285714e-06 1.5 8.685825892857143e-06 1.5 8.686383928571428e-06 0.0 8.688616071428571e-06 0.0 8.689174107142856e-06 1.5 8.703683035714285e-06 1.5 8.704241071428572e-06 0.0 8.706473214285714e-06 0.0 8.707031249999999e-06 1.5 8.721540178571427e-06 1.5 8.722098214285714e-06 0.0 8.724330357142856e-06 0.0 8.724888392857143e-06 1.5 8.739397321428571e-06 1.5 8.739955357142856e-06 0.0 8.7421875e-06 0.0 8.742745535714285e-06 1.5 8.757254464285714e-06 1.5 8.757812499999999e-06 0.0 8.760044642857142e-06 0.0 8.760602678571427e-06 1.5 8.77455357142857e-06 1.5 8.775111607142856e-06 0.0 8.778459821428571e-06 0.0 8.779017857142856e-06 1.5 8.792410714285713e-06 1.5 8.79296875e-06 0.0 8.796316964285714e-06 0.0 8.796874999999999e-06 1.5 8.810267857142857e-06 1.5 8.810825892857142e-06 0.0 8.814174107142856e-06 0.0 8.814732142857143e-06 1.5 8.828125e-06 1.5 8.828683035714285e-06 0.0 8.83203125e-06 0.0 8.832589285714285e-06 1.5 8.845982142857142e-06 1.5 8.846540178571429e-06 0.0 8.849888392857142e-06 0.0 8.850446428571427e-06 1.5 8.863839285714286e-06 1.5 8.86439732142857e-06 0.0 8.867745535714285e-06 0.0 8.868303571428571e-06 1.5 8.881696428571428e-06 1.5 8.882254464285713e-06 0.0 8.885602678571429e-06 0.0 8.886160714285714e-06 1.5 8.89955357142857e-06 1.5 8.900111607142857e-06 0.0 8.903459821428571e-06 0.0 8.904017857142856e-06 1.5 8.917410714285714e-06 1.5 8.91796875e-06 0.0 8.921316964285713e-06 0.0 8.921875e-06 1.5 8.935267857142857e-06 1.5 8.935825892857142e-06 0.0 8.939174107142857e-06 0.0 8.939732142857142e-06 1.5 8.953124999999999e-06 1.5 8.953683035714286e-06 0.0 8.95703125e-06 0.0 8.957589285714285e-06 1.5 8.970982142857141e-06 1.5 8.971540178571428e-06 0.0 8.974888392857142e-06 0.0 8.975446428571429e-06 1.5 8.988839285714285e-06 1.5 8.98939732142857e-06 0.0 8.992745535714284e-06 0.0 8.993303571428571e-06 1.5 9.006696428571428e-06 1.5 9.007254464285713e-06 0.0 9.010602678571428e-06 0.0 9.011160714285713e-06 1.5 9.02455357142857e-06 1.5 9.025111607142857e-06 0.0 9.02845982142857e-06 0.0 9.029017857142856e-06 1.5 9.042410714285714e-06 1.5 9.04296875e-06 0.0 9.046316964285713e-06 0.0 9.046875e-06 1.5 9.060267857142856e-06 1.5 9.060825892857141e-06 0.0 9.064174107142857e-06 0.0 9.064732142857142e-06 1.5 9.078124999999999e-06 1.5 9.078683035714285e-06 0.0 9.08203125e-06 0.0 9.082589285714284e-06 1.5 9.095982142857143e-06 1.5 9.096540178571428e-06 0.0 9.100446428571428e-06 0.0 9.101004464285713e-06 1.5 9.11328125e-06 1.5 9.113839285714285e-06 0.0 9.11830357142857e-06 0.0 9.118861607142856e-06 1.5 9.131138392857142e-06 1.5 9.131696428571427e-06 0.0 9.136160714285713e-06 0.0 9.13671875e-06 1.5 9.148995535714285e-06 1.5 9.149553571428571e-06 0.0 9.154017857142857e-06 0.0 9.154575892857142e-06 1.5 9.166852678571429e-06 1.5 9.167410714285714e-06 0.0 9.171875e-06 0.0 9.172433035714284e-06 1.5 9.184709821428571e-06 1.5 9.185267857142856e-06 0.0 9.189732142857142e-06 0.0 9.190290178571428e-06 1.5 9.202566964285713e-06 1.5 9.203125e-06 0.0 9.207589285714286e-06 0.0 9.20814732142857e-06 1.5 9.220424107142856e-06 1.5 9.220982142857142e-06 0.0 9.225446428571428e-06 0.0 9.226004464285713e-06 1.5 9.23828125e-06 1.5 9.238839285714285e-06 0.0 9.24330357142857e-06 0.0 9.243861607142857e-06 1.5 9.256138392857142e-06 1.5 9.256696428571429e-06 0.0 9.261160714285714e-06 0.0 9.26171875e-06 1.5 9.273995535714284e-06 1.5 9.274553571428571e-06 0.0 9.279017857142857e-06 0.0 9.279575892857142e-06 1.5 9.291852678571428e-06 1.5 9.292410714285713e-06 0.0 9.296874999999999e-06 0.0 9.297433035714286e-06 1.5 9.30970982142857e-06 1.5 9.310267857142856e-06 0.0 9.314732142857143e-06 0.0 9.315290178571428e-06 1.5 9.327566964285713e-06 1.5 9.328125e-06 0.0 9.332589285714285e-06 0.0 9.33314732142857e-06 1.5 9.345424107142857e-06 1.5 9.345982142857142e-06 0.0 9.350446428571428e-06 0.0 9.351004464285714e-06 1.5 9.36328125e-06 1.5 9.363839285714284e-06 0.0 9.368861607142857e-06 0.0 9.369419642857142e-06 1.5 9.380580357142857e-06 1.5 9.381138392857142e-06 0.0 9.386718749999999e-06 0.0 9.387276785714286e-06 1.5 9.398437499999999e-06 1.5 9.398995535714286e-06 0.0 9.404575892857141e-06 0.0 9.405133928571428e-06 1.5 9.416294642857143e-06 1.5 9.416852678571428e-06 0.0 9.422433035714285e-06 0.0 9.42299107142857e-06 1.5 9.434151785714285e-06 1.5 9.43470982142857e-06 0.0 9.440290178571428e-06 0.0 9.440848214285713e-06 1.5 9.452008928571428e-06 1.5 9.452566964285714e-06 0.0 9.45814732142857e-06 0.0 9.458705357142857e-06 1.5 9.469866071428572e-06 1.5 9.470424107142857e-06 0.0 9.476004464285714e-06 0.0 9.476562499999999e-06 1.5 9.487723214285714e-06 1.5 9.488281249999999e-06 0.0 9.493861607142856e-06 0.0 9.494419642857141e-06 1.5 9.505580357142856e-06 1.5 9.506138392857143e-06 0.0 9.511718749999999e-06 0.0 9.512276785714285e-06 1.5 9.523437499999999e-06 1.5 9.523995535714285e-06 0.0 9.529575892857143e-06 0.0 9.530133928571428e-06 1.5 9.541294642857143e-06 1.5 9.541852678571428e-06 0.0 9.547433035714285e-06 0.0 9.54799107142857e-06 1.5 9.559151785714285e-06 1.5 9.55970982142857e-06 0.0 9.565290178571427e-06 0.0 9.565848214285714e-06 1.5 9.577008928571427e-06 1.5 9.577566964285714e-06 0.0 9.583147321428571e-06 0.0 9.583705357142856e-06 1.5 9.594866071428571e-06 1.5 9.595424107142856e-06 0.0 9.601562499999999e-06 0.0 9.602120535714286e-06 1.5 9.612165178571428e-06 1.5 9.612723214285714e-06 0.0 9.619419642857143e-06 0.0 9.619977678571428e-06 1.5 9.63002232142857e-06 1.5 9.630580357142856e-06 0.0 9.637276785714285e-06 0.0 9.63783482142857e-06 1.5 9.647879464285713e-06 1.5 9.6484375e-06 0.0 9.655133928571427e-06 0.0 9.655691964285714e-06 1.5 9.665736607142857e-06 1.5 9.666294642857142e-06 0.0 9.672991071428571e-06 0.0 9.673549107142856e-06 1.5 9.68359375e-06 1.5 9.684151785714285e-06 0.0 9.690848214285714e-06 0.0 9.691406249999999e-06 1.5 9.701450892857142e-06 1.5 9.702008928571429e-06 0.0 9.708705357142856e-06 0.0 9.709263392857143e-06 1.5 9.719308035714286e-06 1.5 9.719866071428571e-06 0.0 9.7265625e-06 0.0 9.727120535714285e-06 1.5 9.737165178571428e-06 1.5 9.737723214285713e-06 0.0 9.744419642857142e-06 0.0 9.744977678571427e-06 1.5 9.75502232142857e-06 1.5 9.755580357142857e-06 0.0 9.762276785714285e-06 0.0 9.762834821428572e-06 1.5 9.772879464285713e-06 1.5 9.7734375e-06 0.0 9.780133928571427e-06 0.0 9.780691964285714e-06 1.5 9.790736607142857e-06 1.5 9.791294642857142e-06 0.0 9.797991071428571e-06 0.0 9.798549107142856e-06 1.5 9.808593749999999e-06 1.5 9.809151785714284e-06 0.0 9.815848214285713e-06 0.0 9.816406249999998e-06 1.5 9.825892857142856e-06 1.5 9.826450892857141e-06 0.0 9.834263392857142e-06 0.0 9.834821428571428e-06 1.5 9.843749999999999e-06 1.5 9.844308035714285e-06 0.0 9.852120535714285e-06 0.0 9.85267857142857e-06 1.5 9.861607142857143e-06 1.5 9.862165178571428e-06 0.0 9.869977678571427e-06 0.0 9.870535714285714e-06 1.5 9.879464285714285e-06 1.5 9.88002232142857e-06 0.0 9.887834821428571e-06 0.0 9.888392857142856e-06 1.5 9.897321428571427e-06 1.5 9.897879464285714e-06 0.0 9.905691964285713e-06 0.0 9.906249999999999e-06 1.5 9.915178571428571e-06 1.5 9.915736607142856e-06 0.0 9.923549107142856e-06 0.0 9.924107142857143e-06 1.5 9.933035714285714e-06 1.5 9.933593749999999e-06 0.0 9.94140625e-06 0.0 9.941964285714285e-06 1.5 9.950892857142856e-06 1.5 9.951450892857143e-06 0.0 9.959263392857142e-06 0.0 9.959821428571427e-06 1.5 9.96875e-06 1.5 9.969308035714285e-06 0.0 9.977120535714284e-06 0.0 9.977678571428571e-06 1.5 9.986607142857142e-06 1.5 9.987165178571427e-06 0.0 9.994977678571428e-06 0.0 9.995535714285714e-06 1.5 1.0004464285714285e-05 1.5 1.0005022321428571e-05 0.0 1.001283482142857e-05 0.0 1.0013392857142856e-05 1.5 1.0022321428571427e-05 1.5 1.0022879464285714e-05 0.0 1.0030691964285713e-05 0.0 1.003125e-05 1.5 1.0039620535714284e-05 1.5 1.0040178571428571e-05 0.0 1.0049107142857142e-05 0.0 1.0049665178571427e-05 1.5 1.0057477678571428e-05 1.5 1.0058035714285713e-05 0.0 1.0066964285714285e-05 0.0 1.0067522321428571e-05 1.5 1.007533482142857e-05 1.5 1.0075892857142856e-05 0.0 1.0084821428571429e-05 0.0 1.0085379464285714e-05 1.5 1.0093191964285713e-05 1.5 1.009375e-05 0.0 1.0102678571428571e-05 0.0 1.0103236607142856e-05 1.5 1.0111049107142857e-05 1.5 1.0111607142857142e-05 0.0 1.0120535714285713e-05 0.0 1.012109375e-05 1.5 1.012890625e-05 1.5 1.0129464285714284e-05 0.0 1.0138392857142857e-05 0.0 1.0138950892857142e-05 1.5 1.0146763392857142e-05 1.5 1.0147321428571428e-05 0.0 1.015625e-05 0.0 1.0156808035714285e-05 1.5 1.0164620535714286e-05 1.5 1.016517857142857e-05 0.0 1.0174107142857142e-05 0.0 1.0174665178571429e-05 1.5 1.0182477678571428e-05 1.5 1.0183035714285713e-05 0.0 1.0191964285714284e-05 0.0 1.0192522321428571e-05 1.5 1.020033482142857e-05 1.5 1.0200892857142857e-05 0.0 1.0209821428571428e-05 0.0 1.0210379464285713e-05 1.5 1.0218191964285714e-05 1.5 1.021875e-05 0.0 1.022767857142857e-05 0.0 1.0228236607142856e-05 1.5 1.0236049107142857e-05 1.5 1.0236607142857142e-05 0.0 1.024609375e-05 0.0 1.0246651785714285e-05 1.5 1.0253348214285714e-05 1.5 1.0253906249999999e-05 0.0 1.0263950892857142e-05 0.0 1.0264508928571429e-05 1.5 1.0271205357142856e-05 1.5 1.0271763392857143e-05 0.0 1.0281808035714284e-05 0.0 1.0282366071428571e-05 1.5 1.0289062499999999e-05 1.5 1.0289620535714285e-05 0.0 1.0299665178571428e-05 0.0 1.0300223214285713e-05 1.5 1.0306919642857143e-05 1.5 1.0307477678571428e-05 0.0 1.031752232142857e-05 0.0 1.0318080357142856e-05 1.5 1.0324776785714285e-05 1.5 1.032533482142857e-05 0.0 1.0335379464285713e-05 0.0 1.03359375e-05 1.5 1.0342633928571427e-05 1.5 1.0343191964285714e-05 0.0 1.0353236607142857e-05 0.0 1.0353794642857142e-05 1.5 1.0360491071428571e-05 1.5 1.0361049107142856e-05 0.0 1.037109375e-05 0.0 1.0371651785714284e-05 1.5 1.0378348214285714e-05 1.5 1.0378906249999999e-05 0.0 1.0388950892857142e-05 0.0 1.0389508928571428e-05 1.5 1.0396205357142856e-05 1.5 1.0396763392857143e-05 0.0 1.0406808035714286e-05 0.0 1.040736607142857e-05 1.5 1.04140625e-05 1.5 1.0414620535714285e-05 0.0 1.0424665178571428e-05 0.0 1.0425223214285713e-05 1.5 1.0431919642857142e-05 1.5 1.0432477678571427e-05 0.0 1.044252232142857e-05 0.0 1.0443080357142857e-05 1.5 1.0449776785714285e-05 1.5 1.0450334821428571e-05 0.0 1.0460379464285714e-05 0.0 1.04609375e-05 1.5 1.0467075892857142e-05 1.5 1.0467633928571429e-05 0.0 1.0478794642857142e-05 0.0 1.0479352678571428e-05 1.5 1.0484933035714286e-05 1.5 1.0485491071428571e-05 0.0 1.0496651785714286e-05 0.0 1.049720982142857e-05 1.5 1.0502790178571428e-05 1.5 1.0503348214285713e-05 0.0 1.0514508928571428e-05 0.0 1.0515066964285713e-05 1.5 1.052064732142857e-05 1.5 1.0521205357142857e-05 0.0 1.053236607142857e-05 0.0 1.0532924107142857e-05 1.5 1.0538504464285713e-05 1.5 1.05390625e-05 0.0 1.0550223214285714e-05 0.0 1.055078125e-05 1.5 1.0556361607142857e-05 1.5 1.0556919642857142e-05 0.0 1.0568080357142857e-05 0.0 1.0568638392857142e-05 1.5 1.0574218749999999e-05 1.5 1.0574776785714284e-05 0.0 1.0585937499999999e-05 0.0 1.0586495535714286e-05 1.5 1.0592075892857141e-05 1.5 1.0592633928571428e-05 0.0 1.0603794642857141e-05 0.0 1.0604352678571428e-05 1.5 1.0609933035714285e-05 1.5 1.061049107142857e-05 0.0 1.0621651785714285e-05 0.0 1.062220982142857e-05 1.5 1.0627790178571428e-05 1.5 1.0628348214285713e-05 0.0 1.0639508928571428e-05 0.0 1.0640066964285713e-05 1.5 1.064564732142857e-05 1.5 1.0646205357142857e-05 0.0 1.065736607142857e-05 0.0 1.0657924107142857e-05 1.5 1.0663504464285714e-05 1.5 1.06640625e-05 0.0 1.0675223214285714e-05 0.0 1.0675781249999999e-05 1.5 1.0681361607142856e-05 1.5 1.0681919642857141e-05 0.0 1.0693080357142856e-05 0.0 1.0693638392857141e-05 1.5 1.0699218749999999e-05 1.5 1.0699776785714286e-05 0.0 1.0711495535714285e-05 0.0 1.071205357142857e-05 1.5 1.0716517857142856e-05 1.5 1.0717075892857143e-05 0.0 1.0729352678571428e-05 0.0 1.0729910714285713e-05 1.5 1.0734375e-05 1.5 1.0734933035714285e-05 0.0 1.074720982142857e-05 0.0 1.0747767857142857e-05 1.5 1.0752232142857142e-05 1.5 1.0752790178571427e-05 0.0 1.0765066964285714e-05 0.0 1.0765624999999999e-05 1.5 1.0770089285714285e-05 1.5 1.0770647321428571e-05 0.0 1.0782924107142856e-05 0.0 1.0783482142857141e-05 1.5 1.0787946428571427e-05 1.5 1.0788504464285714e-05 0.0 1.0800781249999999e-05 0.0 1.0801339285714285e-05 1.5 1.0805803571428571e-05 1.5 1.0806361607142856e-05 0.0 1.0818638392857143e-05 0.0 1.0819196428571428e-05 1.5 1.0823660714285713e-05 1.5 1.0824218749999998e-05 0.0 1.0836495535714285e-05 0.0 1.083705357142857e-05 1.5 1.0841517857142856e-05 1.5 1.0842075892857142e-05 0.0 1.0854352678571427e-05 0.0 1.0854910714285714e-05 1.5 1.0859375e-05 1.5 1.0859933035714285e-05 0.0 1.0872209821428571e-05 0.0 1.0872767857142856e-05 1.5 1.0877232142857142e-05 1.5 1.0877790178571427e-05 0.0 1.0890066964285714e-05 0.0 1.0890624999999999e-05 1.5 1.0895089285714284e-05 1.5 1.0895647321428571e-05 0.0 1.0907924107142856e-05 0.0 1.0908482142857143e-05 1.5 1.0912946428571428e-05 1.5 1.0913504464285713e-05 0.0 1.092578125e-05 0.0 1.0926339285714285e-05 1.5 1.093080357142857e-05 1.5 1.0931361607142856e-05 0.0 1.0943638392857142e-05 0.0 1.0944196428571427e-05 1.5 1.0948660714285713e-05 1.5 1.094921875e-05 0.0 1.0961495535714285e-05 0.0 1.0962053571428571e-05 1.5 1.096595982142857e-05 1.5 1.0966517857142857e-05 0.0 1.0979910714285714e-05 0.0 1.0980468749999999e-05 1.5 1.0983816964285714e-05 1.5 1.0984375e-05 0.0 1.0997767857142856e-05 0.0 1.0998325892857143e-05 1.5 1.1001674107142857e-05 1.5 1.1002232142857142e-05 0.0 1.1015624999999998e-05 0.0 1.1016183035714285e-05 1.5 1.1019531249999999e-05 1.5 1.1020089285714286e-05 0.0 1.1033482142857142e-05 0.0 1.1034040178571427e-05 1.5 1.1037388392857141e-05 1.5 1.1037946428571428e-05 0.0 1.1051339285714285e-05 0.0 1.105189732142857e-05 1.5 1.1055245535714285e-05 1.5 1.105580357142857e-05 0.0 1.1069196428571427e-05 0.0 1.1069754464285714e-05 1.5 1.1073102678571428e-05 1.5 1.1073660714285714e-05 0.0 1.1087053571428571e-05 0.0 1.1087611607142856e-05 1.5 1.109095982142857e-05 1.5 1.1091517857142857e-05 0.0 1.1104910714285713e-05 0.0 1.1105468749999998e-05 1.5 1.1108816964285714e-05 1.5 1.1109374999999999e-05 0.0 1.1122767857142856e-05 0.0 1.1123325892857142e-05 1.5 1.1126674107142856e-05 1.5 1.1127232142857141e-05 0.0 1.1140625e-05 0.0 1.1141183035714285e-05 1.5 1.1144531249999999e-05 1.5 1.1145089285714285e-05 0.0 1.1158482142857142e-05 0.0 1.1159040178571427e-05 1.5 1.1162388392857143e-05 1.5 1.1162946428571428e-05 0.0 1.1176339285714284e-05 0.0 1.1176897321428571e-05 1.5 1.1180245535714285e-05 1.5 1.118080357142857e-05 0.0 1.1194196428571428e-05 0.0 1.1194754464285713e-05 1.5 1.1198102678571427e-05 1.5 1.1198660714285714e-05 0.0 1.121205357142857e-05 0.0 1.1212611607142856e-05 1.5 1.1215959821428571e-05 1.5 1.1216517857142856e-05 0.0 1.1229910714285713e-05 0.0 1.123046875e-05 1.5 1.1233816964285714e-05 1.5 1.1234374999999999e-05 0.0 1.1247767857142857e-05 0.0 1.1248325892857142e-05 1.5 1.1251674107142856e-05 1.5 1.1252232142857143e-05 0.0 1.1265625e-05 0.0 1.1266183035714284e-05 1.5 1.126953125e-05 1.5 1.1270089285714285e-05 0.0 1.1283482142857142e-05 0.0 1.1284040178571428e-05 1.5 1.1287388392857142e-05 1.5 1.1287946428571427e-05 0.0 1.130189732142857e-05 0.0 1.1302455357142856e-05 1.5 1.13046875e-05 1.5 1.1305245535714285e-05 0.0 1.1319754464285713e-05 0.0 1.13203125e-05 1.5 1.1322544642857142e-05 1.5 1.1323102678571429e-05 0.0 1.1337611607142857e-05 0.0 1.1338169642857142e-05 1.5 1.1340401785714284e-05 1.5 1.1340959821428571e-05 0.0 1.135546875e-05 0.0 1.1356026785714285e-05 1.5 1.1358258928571428e-05 1.5 1.1358816964285713e-05 0.0 1.1373325892857142e-05 0.0 1.1373883928571429e-05 1.5 1.137611607142857e-05 1.5 1.1376674107142856e-05 0.0 1.1391183035714284e-05 0.0 1.1391741071428571e-05 1.5 1.1393973214285713e-05 1.5 1.139453125e-05 0.0 1.1409040178571428e-05 0.0 1.1409598214285713e-05 1.5 1.1411830357142857e-05 1.5 1.1412388392857142e-05 0.0 1.142689732142857e-05 0.0 1.1427455357142856e-05 1.5 1.1429687499999999e-05 1.5 1.1430245535714284e-05 0.0 1.1444754464285713e-05 0.0 1.14453125e-05 1.5 1.1447544642857141e-05 1.5 1.1448102678571428e-05 0.0 1.1462611607142857e-05 0.0 1.1463169642857142e-05 1.5 1.1465401785714285e-05 1.5 1.146595982142857e-05 0.0 1.1480468749999999e-05 0.0 1.1481026785714284e-05 1.5 1.1483258928571428e-05 1.5 1.1483816964285713e-05 0.0 1.1498325892857141e-05 0.0 1.1498883928571428e-05 1.5 1.150111607142857e-05 1.5 1.1501674107142857e-05 0.0 1.1516183035714285e-05 0.0 1.151674107142857e-05 1.5 1.1518973214285714e-05 1.5 1.151953125e-05 0.0 1.1534040178571428e-05 0.0 1.1534598214285713e-05 1.5 1.1536830357142856e-05 1.5 1.1537388392857142e-05 0.0 1.155189732142857e-05 0.0 1.1552455357142857e-05 1.5 1.1554687499999999e-05 1.5 1.1555245535714286e-05 0.0 1.1569754464285714e-05 0.0 1.15703125e-05 1.5 1.1572544642857143e-05 1.5 1.1573102678571428e-05 0.0 1.1587611607142856e-05 0.0 1.1588169642857142e-05 1.5 1.1590401785714285e-05 1.5 1.159095982142857e-05 0.0 1.1605468749999999e-05 0.0 1.1606026785714286e-05 1.5 1.1608258928571427e-05 1.5 1.1608816964285714e-05 0.0 1.1623325892857143e-05 0.0 1.1623883928571428e-05 1.5 1.162611607142857e-05 1.5 1.1626674107142857e-05 0.0 1.1641183035714285e-05 0.0 1.164174107142857e-05 1.5 1.1643973214285714e-05 1.5 1.1644531249999999e-05 0.0 1.1659040178571427e-05 0.0 1.1659598214285714e-05 1.5 1.1661830357142856e-05 1.5 1.1662388392857141e-05 0.0 1.167689732142857e-05 0.0 1.1677455357142857e-05 1.5 1.1679687499999998e-05 1.5 1.1680245535714285e-05 0.0 1.1694754464285714e-05 0.0 1.1695312499999999e-05 1.5 1.1697544642857142e-05 1.5 1.1698102678571428e-05 0.0 1.1712611607142856e-05 0.0 1.1713169642857143e-05 1.5 1.1715401785714285e-05 1.5 1.171595982142857e-05 0.0 1.1730468749999998e-05 0.0 1.1731026785714285e-05 1.5 1.1733258928571427e-05 1.5 1.1733816964285714e-05 0.0 1.1748325892857142e-05 0.0 1.1748883928571427e-05 1.5 1.1751116071428571e-05 1.5 1.1751674107142856e-05 0.0 1.1766183035714285e-05 0.0 1.176674107142857e-05 1.5 1.1768973214285713e-05 1.5 1.1769531249999999e-05 0.0 1.1784040178571427e-05 0.0 1.1784598214285714e-05 1.5 1.1786830357142856e-05 1.5 1.1787388392857143e-05 0.0 1.1801897321428571e-05 0.0 1.1802455357142856e-05 1.5 1.18046875e-05 1.5 1.1805245535714285e-05 0.0 1.1819754464285713e-05 0.0 1.1820312499999998e-05 1.5 1.1822544642857142e-05 1.5 1.1823102678571427e-05 0.0 1.1837611607142856e-05 0.0 1.1838169642857142e-05 1.5 1.1840401785714284e-05 1.5 1.1840959821428571e-05 0.0 1.185546875e-05 0.0 1.1856026785714285e-05 1.5 1.1858258928571428e-05 1.5 1.1858816964285714e-05 0.0 1.1873325892857142e-05 0.0 1.1873883928571427e-05 1.5 1.187611607142857e-05 1.5 1.1876674107142856e-05 0.0 1.1891183035714284e-05 0.0 1.1891741071428571e-05 1.5 1.1893973214285713e-05 1.5 1.189453125e-05 0.0 1.1909040178571428e-05 0.0 1.1909598214285713e-05 1.5 1.1911830357142857e-05 1.5 1.1912388392857142e-05 0.0 1.192689732142857e-05 0.0 1.1927455357142856e-05 1.5 1.19296875e-05 1.5 1.1930245535714285e-05 0.0 1.1944754464285713e-05 0.0 1.19453125e-05 1.5 1.1947544642857142e-05 1.5 1.1948102678571429e-05 0.0 1.1962611607142857e-05 0.0 1.1963169642857142e-05 1.5 1.1965401785714284e-05 1.5 1.196595982142857e-05 0.0 1.198046875e-05 0.0 1.1981026785714284e-05 1.5 1.1983258928571428e-05 1.5 1.1983816964285713e-05 0.0 1.1998325892857142e-05 0.0 1.1998883928571428e-05 1.5 1.200111607142857e-05 1.5 1.2001674107142855e-05 0.0 1.2016183035714284e-05 0.0 1.201674107142857e-05 1.5 1.2018973214285713e-05 1.5 1.201953125e-05 0.0 1.2034040178571428e-05 0.0 1.2034598214285713e-05 1.5 1.2036830357142857e-05 1.5 1.2037388392857142e-05 0.0 1.205189732142857e-05 0.0 1.2052455357142855e-05 1.5 1.2054687499999999e-05 1.5 1.2055245535714284e-05 0.0 1.2069754464285713e-05 0.0 1.20703125e-05 1.5 1.2072544642857141e-05 1.5 1.2073102678571428e-05 0.0 1.2087611607142857e-05 0.0 1.2088169642857142e-05 1.5 1.2090401785714285e-05 1.5 1.209095982142857e-05 0.0 1.2105468749999999e-05 0.0 1.2106026785714284e-05 1.5 1.2108258928571428e-05 1.5 1.2108816964285713e-05 0.0 1.2123325892857141e-05 0.0 1.2123883928571428e-05 1.5 1.212611607142857e-05 1.5 1.2126674107142857e-05 0.0 1.2141183035714285e-05 0.0 1.214174107142857e-05 1.5 1.2143973214285714e-05 1.5 1.214453125e-05 0.0 1.2159040178571428e-05 0.0 1.2159598214285713e-05 1.5 1.2161830357142856e-05 1.5 1.2162388392857141e-05 0.0 1.217689732142857e-05 0.0 1.2177455357142857e-05 1.5 1.2179687499999999e-05 1.5 1.2180245535714285e-05 0.0 1.2194754464285714e-05 0.0 1.2195312499999999e-05 1.5 1.2197544642857143e-05 1.5 1.2198102678571428e-05 0.0 1.2212611607142856e-05 0.0 1.2213169642857141e-05 1.5 1.2215401785714285e-05 1.5 1.221595982142857e-05 0.0 1.2230468749999999e-05 0.0 1.2231026785714285e-05 1.5 1.2233258928571427e-05 1.5 1.2233816964285714e-05 0.0 1.2248325892857143e-05 0.0 1.2248883928571428e-05 1.5 1.225111607142857e-05 1.5 1.2251674107142856e-05 0.0 1.2266183035714285e-05 0.0 1.226674107142857e-05 1.5 1.2268973214285714e-05 1.5 1.2269531249999999e-05 0.0 1.2284040178571427e-05 0.0 1.2284598214285714e-05 1.5 1.2286830357142856e-05 1.5 1.2287388392857141e-05 0.0 1.2301897321428571e-05 0.0 1.2302455357142856e-05 1.5 1.2304687499999998e-05 1.5 1.2305245535714285e-05 0.0 1.2319754464285714e-05 0.0 1.2320312499999999e-05 1.5 1.2322544642857142e-05 1.5 1.2323102678571427e-05 0.0 1.2337611607142856e-05 0.0 1.2338169642857143e-05 1.5 1.2340401785714285e-05 1.5 1.234095982142857e-05 0.0 1.2355468749999998e-05 0.0 1.2356026785714285e-05 1.5 1.2358258928571427e-05 1.5 1.2358816964285714e-05 0.0 1.2373325892857142e-05 0.0 1.2373883928571427e-05 1.5 1.2376116071428571e-05 1.5 1.2376674107142856e-05 0.0 1.2391183035714285e-05 0.0 1.239174107142857e-05 1.5 1.2393973214285713e-05 1.5 1.2394531249999998e-05 0.0 1.2409040178571427e-05 0.0 1.2409598214285714e-05 1.5 1.2411830357142856e-05 1.5 1.2412388392857142e-05 0.0 1.2426897321428571e-05 0.0 1.2427455357142856e-05 1.5 1.24296875e-05 1.5 1.2430245535714285e-05 0.0 1.2444754464285713e-05 0.0 1.2445312499999998e-05 1.5 1.2447544642857142e-05 1.5 1.2448102678571427e-05 0.0 1.2462611607142856e-05 0.0 1.2463169642857142e-05 1.5 1.2465401785714284e-05 1.5 1.2465959821428571e-05 0.0 1.248046875e-05 0.0 1.2481026785714285e-05 1.5 1.2483258928571428e-05 1.5 1.2483816964285713e-05 0.0 1.2498325892857142e-05 0.0 1.2498883928571427e-05 1.5 1.250111607142857e-05 1.5 1.2501674107142856e-05 0.0 1.2516183035714284e-05 0.0 1.2516741071428571e-05 1.5 1.2518973214285713e-05 1.5 1.251953125e-05 0.0 1.2534040178571428e-05 0.0 1.2534598214285713e-05 1.5 1.2536830357142857e-05 1.5 1.2537388392857142e-05 0.0 1.255189732142857e-05 0.0 1.2552455357142856e-05 1.5 1.25546875e-05 1.5 1.2555245535714284e-05 0.0 1.2569754464285713e-05 0.0 1.25703125e-05 1.5 1.2572544642857142e-05 1.5 1.2573102678571428e-05 0.0 1.2587611607142857e-05 0.0 1.2588169642857142e-05 1.5 1.2590401785714284e-05 1.5 1.259095982142857e-05 0.0 1.260546875e-05 0.0 1.2606026785714284e-05 1.5 1.2608258928571428e-05 1.5 1.2608816964285713e-05 0.0 1.2623325892857142e-05 0.0 1.2623883928571428e-05 1.5 1.262611607142857e-05 1.5 1.2626674107142855e-05 0.0 1.2641183035714284e-05 0.0 1.264174107142857e-05 1.5 1.2643973214285713e-05 1.5 1.264453125e-05 0.0 1.2659040178571428e-05 0.0 1.2659598214285713e-05 1.5 1.2661830357142857e-05 1.5 1.2662388392857142e-05 0.0 1.267689732142857e-05 0.0 1.2677455357142855e-05 1.5 1.2679687499999999e-05 1.5 1.2680245535714284e-05 0.0 1.2694754464285713e-05 0.0 1.26953125e-05 1.5 1.2697544642857141e-05 1.5 1.2698102678571428e-05 0.0 1.2712611607142857e-05 0.0 1.2713169642857142e-05 1.5 1.2715401785714285e-05 1.5 1.271595982142857e-05 0.0 1.2730468749999999e-05 0.0 1.2731026785714284e-05 1.5 1.2733258928571428e-05 1.5 1.2733816964285713e-05 0.0 1.2748325892857141e-05 0.0 1.2748883928571428e-05 1.5 1.275111607142857e-05 1.5 1.2751674107142857e-05 0.0 1.2766183035714285e-05 0.0 1.276674107142857e-05 1.5 1.2768973214285714e-05 1.5 1.2769531249999999e-05 0.0 1.2784040178571428e-05 0.0 1.2784598214285713e-05 1.5 1.2787388392857141e-05 1.5 1.2787946428571428e-05 0.0 1.2801339285714285e-05 0.0 1.280189732142857e-05 1.5 1.2805245535714285e-05 1.5 1.280580357142857e-05 0.0 1.2819196428571427e-05 0.0 1.2819754464285714e-05 1.5 1.2823102678571428e-05 1.5 1.2823660714285713e-05 0.0 1.2837053571428571e-05 0.0 1.2837611607142856e-05 1.5 1.284095982142857e-05 1.5 1.2841517857142857e-05 0.0 1.2854910714285714e-05 0.0 1.2855468749999999e-05 1.5 1.2858816964285714e-05 1.5 1.2859375e-05 0.0 1.2872767857142856e-05 0.0 1.2873325892857143e-05 1.5 1.2876674107142856e-05 1.5 1.2877232142857141e-05 0.0 1.2890624999999998e-05 0.0 1.2891183035714285e-05 1.5 1.2894531249999999e-05 1.5 1.2895089285714286e-05 0.0 1.2908482142857142e-05 0.0 1.2909040178571427e-05 1.5 1.2912388392857143e-05 1.5 1.2912946428571428e-05 0.0 1.2926339285714285e-05 0.0 1.2926897321428571e-05 1.5 1.2930245535714285e-05 1.5 1.293080357142857e-05 0.0 1.2944196428571427e-05 0.0 1.2944754464285714e-05 1.5 1.2948102678571427e-05 1.5 1.2948660714285714e-05 0.0 1.2962053571428571e-05 0.0 1.2962611607142856e-05 1.5 1.296595982142857e-05 1.5 1.2966517857142856e-05 0.0 1.2979910714285713e-05 0.0 1.2980468749999998e-05 1.5 1.2983816964285714e-05 1.5 1.2984374999999999e-05 0.0 1.2997767857142856e-05 0.0 1.2998325892857142e-05 1.5 1.3001674107142856e-05 1.5 1.3002232142857141e-05 0.0 1.3015625e-05 0.0 1.3016183035714285e-05 1.5 1.3019531249999998e-05 1.5 1.3020089285714285e-05 0.0 1.3033482142857142e-05 0.0 1.3034040178571427e-05 1.5 1.3037388392857142e-05 1.5 1.3037946428571427e-05 0.0 1.3051339285714284e-05 0.0 1.3051897321428571e-05 1.5 1.3055245535714285e-05 1.5 1.305580357142857e-05 0.0 1.3069196428571428e-05 0.0 1.3069754464285713e-05 1.5 1.3073102678571427e-05 1.5 1.3073660714285714e-05 0.0 1.308705357142857e-05 0.0 1.3087611607142856e-05 1.5 1.3090959821428571e-05 1.5 1.3091517857142856e-05 0.0 1.3104910714285713e-05 0.0 1.310546875e-05 1.5 1.3108816964285713e-05 1.5 1.3109374999999998e-05 0.0 1.312220982142857e-05 0.0 1.3122767857142857e-05 1.5 1.3127232142857142e-05 1.5 1.3127790178571428e-05 0.0 1.3140066964285714e-05 0.0 1.3140625e-05 1.5 1.3145089285714285e-05 1.5 1.314564732142857e-05 0.0 1.3157924107142856e-05 0.0 1.3158482142857142e-05 1.5 1.3162946428571427e-05 1.5 1.3163504464285714e-05 0.0 1.3175781249999999e-05 0.0 1.3176339285714286e-05 1.5 1.3180803571428571e-05 1.5 1.3181361607142856e-05 0.0 1.3193638392857141e-05 0.0 1.3194196428571428e-05 1.5 1.3198660714285713e-05 1.5 1.3199218749999999e-05 0.0 1.3211495535714285e-05 0.0 1.321205357142857e-05 1.5 1.3216517857142856e-05 1.5 1.3217075892857143e-05 0.0 1.3229352678571427e-05 0.0 1.3229910714285713e-05 1.5 1.3234375e-05 1.5 1.3234933035714285e-05 0.0 1.324720982142857e-05 0.0 1.3247767857142857e-05 1.5 1.3252232142857142e-05 1.5 1.3252790178571427e-05 0.0 1.3265066964285714e-05 0.0 1.3265624999999999e-05 1.5 1.3270089285714284e-05 1.5 1.3270647321428571e-05 0.0 1.3282924107142856e-05 0.0 1.3283482142857141e-05 1.5 1.3287946428571427e-05 1.5 1.3288504464285714e-05 0.0 1.3300781249999998e-05 0.0 1.3301339285714285e-05 1.5 1.330580357142857e-05 1.5 1.3306361607142856e-05 0.0 1.3318638392857142e-05 0.0 1.3319196428571428e-05 1.5 1.3323660714285713e-05 1.5 1.332421875e-05 0.0 1.3336495535714285e-05 0.0 1.333705357142857e-05 1.5 1.3341517857142855e-05 1.5 1.3342075892857142e-05 0.0 1.3354352678571427e-05 0.0 1.3354910714285714e-05 1.5 1.3359375e-05 1.5 1.3359933035714285e-05 0.0 1.3372209821428571e-05 0.0 1.3372767857142856e-05 1.5 1.3377790178571427e-05 1.5 1.3378348214285714e-05 0.0 1.3389508928571428e-05 0.0 1.3390066964285713e-05 1.5 1.3395647321428571e-05 1.5 1.3396205357142856e-05 0.0 1.340736607142857e-05 0.0 1.3407924107142856e-05 1.5 1.3413504464285713e-05 1.5 1.3414062499999998e-05 0.0 1.3425223214285713e-05 0.0 1.342578125e-05 1.5 1.3431361607142856e-05 1.5 1.3431919642857142e-05 0.0 1.3443080357142855e-05 0.0 1.3443638392857142e-05 1.5 1.344921875e-05 1.5 1.3449776785714285e-05 0.0 1.34609375e-05 0.0 1.3461495535714284e-05 1.5 1.3467075892857142e-05 1.5 1.3467633928571427e-05 0.0 1.3478794642857142e-05 0.0 1.3479352678571427e-05 1.5 1.3484933035714284e-05 1.5 1.3485491071428571e-05 0.0 1.3496651785714284e-05 0.0 1.349720982142857e-05 1.5 1.3502790178571428e-05 1.5 1.3503348214285713e-05 0.0 1.3514508928571428e-05 0.0 1.3515066964285713e-05 1.5 1.352064732142857e-05 1.5 1.3521205357142856e-05 0.0 1.353236607142857e-05 0.0 1.3532924107142855e-05 1.5 1.3538504464285713e-05 1.5 1.35390625e-05 0.0 1.3550223214285713e-05 0.0 1.355078125e-05 1.5 1.3556361607142857e-05 1.5 1.3556919642857142e-05 0.0 1.3568080357142857e-05 0.0 1.3568638392857142e-05 1.5 1.357421875e-05 1.5 1.3574776785714284e-05 0.0 1.3585937499999999e-05 0.0 1.3586495535714284e-05 1.5 1.3592075892857142e-05 1.5 1.3592633928571428e-05 0.0 1.3603794642857141e-05 0.0 1.3604352678571428e-05 1.5 1.3609933035714286e-05 1.5 1.361049107142857e-05 0.0 1.3621093749999999e-05 0.0 1.3621651785714285e-05 1.5 1.3628348214285713e-05 1.5 1.362890625e-05 0.0 1.3638950892857143e-05 0.0 1.3639508928571428e-05 1.5 1.3646205357142857e-05 1.5 1.3646763392857142e-05 0.0 1.3656808035714285e-05 0.0 1.365736607142857e-05 1.5 1.36640625e-05 1.5 1.3664620535714284e-05 0.0 1.3674665178571427e-05 0.0 1.3675223214285714e-05 1.5 1.3681919642857142e-05 1.5 1.3682477678571428e-05 0.0 1.369252232142857e-05 0.0 1.3693080357142856e-05 1.5 1.3699776785714284e-05 1.5 1.370033482142857e-05 0.0 1.3710379464285714e-05 0.0 1.3710937499999999e-05 1.5 1.3717633928571428e-05 1.5 1.3718191964285713e-05 0.0 1.3728236607142856e-05 0.0 1.3728794642857143e-05 1.5 1.373549107142857e-05 1.5 1.3736049107142857e-05 0.0 1.3746093749999998e-05 0.0 1.3746651785714285e-05 1.5 1.3753348214285713e-05 1.5 1.375390625e-05 0.0 1.3763950892857142e-05 0.0 1.3764508928571427e-05 1.5 1.3771205357142857e-05 1.5 1.3771763392857142e-05 0.0 1.3781808035714285e-05 0.0 1.378236607142857e-05 1.5 1.3789062499999999e-05 1.5 1.3789620535714284e-05 0.0 1.3799665178571427e-05 0.0 1.3800223214285714e-05 1.5 1.3806919642857141e-05 1.5 1.3807477678571428e-05 0.0 1.3817522321428571e-05 0.0 1.3818080357142856e-05 1.5 1.3824776785714285e-05 1.5 1.382533482142857e-05 0.0 1.3834821428571428e-05 0.0 1.3835379464285713e-05 1.5 1.3843191964285713e-05 1.5 1.384375e-05 0.0 1.385267857142857e-05 0.0 1.3853236607142856e-05 1.5 1.3861049107142857e-05 1.5 1.3861607142857142e-05 0.0 1.3870535714285713e-05 0.0 1.387109375e-05 1.5 1.3878906249999999e-05 1.5 1.3879464285714284e-05 0.0 1.3888392857142857e-05 0.0 1.3888950892857142e-05 1.5 1.3896763392857141e-05 1.5 1.3897321428571428e-05 0.0 1.390625e-05 0.0 1.3906808035714284e-05 1.5 1.3914620535714285e-05 1.5 1.391517857142857e-05 0.0 1.3924107142857142e-05 0.0 1.3924665178571428e-05 1.5 1.3932477678571428e-05 1.5 1.3933035714285713e-05 0.0 1.3941964285714286e-05 0.0 1.394252232142857e-05 1.5 1.395033482142857e-05 1.5 1.3950892857142857e-05 0.0 1.3959821428571428e-05 0.0 1.3960379464285713e-05 1.5 1.3968191964285714e-05 1.5 1.3968749999999999e-05 0.0 1.397767857142857e-05 0.0 1.3978236607142857e-05 1.5 1.3986049107142856e-05 1.5 1.3986607142857141e-05 0.0 1.3995535714285713e-05 0.0 1.399609375e-05 1.5 1.4003906249999999e-05 1.5 1.4004464285714285e-05 0.0 1.4013392857142857e-05 0.0 1.4013950892857142e-05 1.5 1.4021763392857143e-05 1.5 1.4022321428571428e-05 0.0 1.4031249999999999e-05 0.0 1.4031808035714284e-05 1.5 1.4039620535714285e-05 1.5 1.404017857142857e-05 0.0 1.4048549107142856e-05 0.0 1.4049107142857141e-05 1.5 1.4058035714285714e-05 1.5 1.4058593749999999e-05 0.0 1.4066406249999998e-05 0.0 1.4066964285714285e-05 1.5 1.4075892857142856e-05 1.5 1.4076450892857141e-05 0.0 1.4084263392857142e-05 0.0 1.4084821428571428e-05 1.5 1.4093749999999999e-05 1.5 1.4094308035714285e-05 0.0 1.4102120535714285e-05 0.0 1.410267857142857e-05 1.5 1.4111607142857141e-05 1.5 1.4112165178571428e-05 0.0 1.4119977678571427e-05 0.0 1.4120535714285714e-05 1.5 1.4129464285714285e-05 1.5 1.413002232142857e-05 0.0 1.4137834821428571e-05 0.0 1.4138392857142856e-05 1.5 1.4147321428571427e-05 1.5 1.4147879464285714e-05 0.0 1.4155691964285713e-05 0.0 1.4156249999999999e-05 1.5 1.416517857142857e-05 1.5 1.4165736607142856e-05 0.0 1.4173549107142856e-05 0.0 1.4174107142857143e-05 1.5 1.4183035714285714e-05 1.5 1.4183593749999999e-05 0.0 1.419140625e-05 0.0 1.4191964285714285e-05 1.5 1.4200892857142856e-05 1.5 1.4201450892857141e-05 0.0 1.4209263392857142e-05 0.0 1.4209821428571427e-05 1.5 1.4218749999999998e-05 1.5 1.4219308035714285e-05 0.0 1.4227120535714284e-05 0.0 1.4227678571428571e-05 1.5 1.4236607142857142e-05 1.5 1.4237165178571427e-05 0.0 1.4244977678571427e-05 0.0 1.4245535714285714e-05 1.5 1.4254464285714285e-05 1.5 1.425502232142857e-05 0.0 1.4262276785714284e-05 0.0 1.426283482142857e-05 1.5 1.4272879464285714e-05 1.5 1.4273437499999999e-05 0.0 1.4280133928571428e-05 0.0 1.4280691964285713e-05 1.5 1.4290736607142856e-05 1.5 1.4291294642857141e-05 0.0 1.429799107142857e-05 0.0 1.4298549107142855e-05 1.5 1.4308593749999998e-05 1.5 1.4309151785714285e-05 0.0 1.4315848214285713e-05 0.0 1.431640625e-05 1.5 1.4326450892857142e-05 1.5 1.4327008928571427e-05 0.0 1.4333705357142857e-05 0.0 1.4334263392857142e-05 1.5 1.4344308035714285e-05 1.5 1.434486607142857e-05 0.0 1.4351562499999999e-05 0.0 1.4352120535714284e-05 1.5 1.4362165178571427e-05 1.5 1.4362723214285714e-05 0.0 1.4369419642857141e-05 0.0 1.4369977678571428e-05 1.5 1.4380022321428571e-05 1.5 1.4380580357142856e-05 0.0 1.4387276785714285e-05 0.0 1.438783482142857e-05 1.5 1.4397879464285713e-05 1.5 1.4398437499999998e-05 0.0 1.4405133928571428e-05 0.0 1.4405691964285713e-05 1.5 1.4415736607142856e-05 1.5 1.4416294642857142e-05 0.0 1.442299107142857e-05 0.0 1.4423549107142857e-05 1.5 1.443359375e-05 1.5 1.4434151785714285e-05 0.0 1.4440848214285714e-05 0.0 1.4441406249999999e-05 1.5 1.4451450892857142e-05 1.5 1.4452008928571427e-05 0.0 1.4458705357142856e-05 0.0 1.4459263392857141e-05 1.5 1.4469308035714284e-05 1.5 1.4469866071428571e-05 0.0 1.4476562499999999e-05 0.0 1.4477120535714285e-05 1.5 1.4487723214285713e-05 1.5 1.4488281249999999e-05 0.0 1.4493861607142856e-05 0.0 1.4494419642857141e-05 1.5 1.4505580357142856e-05 1.5 1.4506138392857143e-05 0.0 1.4511718749999998e-05 0.0 1.4512276785714285e-05 1.5 1.4523437499999998e-05 1.5 1.4523995535714285e-05 0.0 1.4529575892857142e-05 0.0 1.4530133928571427e-05 1.5 1.4541294642857142e-05 1.5 1.4541852678571427e-05 0.0 1.4547433035714285e-05 0.0 1.454799107142857e-05 1.5 1.4559151785714284e-05 1.5 1.4559709821428571e-05 0.0 1.4565290178571427e-05 0.0 1.4565848214285714e-05 1.5 1.4577008928571427e-05 1.5 1.4577566964285714e-05 0.0 1.4583147321428571e-05 0.0 1.4583705357142856e-05 1.5 1.459486607142857e-05 1.5 1.4595424107142856e-05 0.0 1.4601004464285713e-05 0.0 1.4601562499999998e-05 1.5 1.4612723214285713e-05 1.5 1.4613281249999998e-05 0.0 1.4618861607142856e-05 0.0 1.4619419642857142e-05 1.5 1.4630580357142855e-05 1.5 1.4631138392857142e-05 0.0 1.463671875e-05 0.0 1.4637276785714285e-05 1.5 1.46484375e-05 1.5 1.4648995535714285e-05 0.0 1.4654575892857142e-05 0.0 1.4655133928571427e-05 1.5 1.4666294642857142e-05 1.5 1.4666852678571427e-05 0.0 1.4672433035714284e-05 0.0 1.4672991071428571e-05 1.5 1.4684151785714284e-05 1.5 1.4684709821428571e-05 0.0 1.4690290178571428e-05 0.0 1.4690848214285713e-05 1.5 1.4702008928571428e-05 1.5 1.4702566964285713e-05 0.0 1.470814732142857e-05 0.0 1.4708705357142856e-05 1.5 1.4720424107142856e-05 1.5 1.4720982142857142e-05 0.0 1.4725446428571428e-05 0.0 1.4726004464285713e-05 1.5 1.473828125e-05 1.5 1.4738839285714285e-05 0.0 1.474330357142857e-05 0.0 1.4743861607142857e-05 1.5 1.4756138392857142e-05 1.5 1.4756696428571427e-05 0.0 1.4761160714285712e-05 0.0 1.476171875e-05 1.5 1.4773995535714284e-05 1.5 1.4774553571428571e-05 0.0 1.4779017857142857e-05 0.0 1.4779575892857142e-05 1.5 1.4791852678571428e-05 1.5 1.4792410714285713e-05 0.0 1.4796874999999999e-05 0.0 1.4797433035714284e-05 1.5 1.480970982142857e-05 1.5 1.4810267857142856e-05 0.0 1.4814732142857141e-05 0.0 1.4815290178571428e-05 1.5 1.4827566964285713e-05 1.5 1.4828125e-05 0.0 1.4832589285714285e-05 0.0 1.483314732142857e-05 1.5 1.4845424107142857e-05 1.5 1.4845982142857142e-05 0.0 1.4850446428571427e-05 0.0 1.4851004464285713e-05 1.5 1.486328125e-05 1.5 1.4863839285714284e-05 0.0 1.486830357142857e-05 0.0 1.4868861607142857e-05 1.5 1.4881138392857141e-05 1.5 1.4881696428571428e-05 0.0 1.4886160714285714e-05 0.0 1.4886718749999999e-05 1.5 1.4898995535714284e-05 1.5 1.489955357142857e-05 0.0 1.4904017857142856e-05 0.0 1.4904575892857141e-05 1.5 1.4916852678571428e-05 1.5 1.4917410714285713e-05 0.0 1.4921874999999998e-05 0.0 1.4922433035714285e-05 1.5 1.493470982142857e-05 1.5 1.4935267857142857e-05 0.0 1.4939732142857142e-05 0.0 1.4940290178571428e-05 1.5 1.4952566964285712e-05 1.5 1.4953125e-05 0.0 1.4957589285714285e-05 0.0 1.495814732142857e-05 1.5 1.4970424107142857e-05 1.5 1.4970982142857142e-05 0.0 1.4975446428571427e-05 0.0 1.4976004464285714e-05 1.5 1.4988839285714284e-05 1.5 1.498939732142857e-05 0.0 1.4992745535714284e-05 0.0 1.4993303571428571e-05 1.5 1.5006696428571428e-05 1.5 1.5007254464285713e-05 0.0 1.5010602678571427e-05 0.0 1.5011160714285713e-05 1.5 1.502455357142857e-05 1.5 1.5025111607142855e-05 0.0 1.502845982142857e-05 0.0 1.5029017857142856e-05 1.5 1.5042410714285713e-05 1.5 1.504296875e-05 0.0 1.5046316964285713e-05 0.0 1.5046874999999998e-05 1.5 1.5060267857142857e-05 1.5 1.5060825892857142e-05 0.0 1.5064174107142855e-05 0.0 1.5064732142857142e-05 1.5 1.5078124999999999e-05 1.5 1.5078683035714284e-05 0.0 1.508203125e-05 0.0 1.5082589285714284e-05 1.5 1.5095982142857141e-05 1.5 1.5096540178571428e-05 0.0 1.5099888392857142e-05 0.0 1.5100446428571427e-05 1.5 1.5113839285714285e-05 1.5 1.511439732142857e-05 0.0 1.5117745535714284e-05 0.0 1.511830357142857e-05 1.5 1.5131696428571428e-05 1.5 1.5132254464285713e-05 0.0 1.5135602678571428e-05 0.0 1.5136160714285713e-05 1.5 1.514955357142857e-05 1.5 1.5150111607142857e-05 0.0 1.515345982142857e-05 0.0 1.5154017857142855e-05 1.5 1.5167410714285714e-05 1.5 1.5167968749999999e-05 0.0 1.5171316964285713e-05 0.0 1.5171875e-05 1.5 1.5185267857142856e-05 1.5 1.5185825892857141e-05 0.0 1.5189174107142857e-05 0.0 1.5189732142857142e-05 1.5 1.5203124999999999e-05 1.5 1.5203683035714285e-05 0.0 1.5207031249999999e-05 0.0 1.5207589285714284e-05 1.5 1.5220982142857143e-05 1.5 1.5221540178571428e-05 0.0 1.5224888392857141e-05 0.0 1.5225446428571428e-05 1.5 1.5238839285714285e-05 1.5 1.523939732142857e-05 0.0 1.5242745535714285e-05 0.0 1.524330357142857e-05 1.5 1.5256696428571427e-05 1.5 1.5257254464285714e-05 0.0 1.5260602678571426e-05 0.0 1.5261160714285713e-05 1.5 1.527455357142857e-05 1.5 1.5275111607142855e-05 0.0 1.5278459821428572e-05 0.0 1.5279017857142855e-05 1.5 1.5292410714285714e-05 1.5 1.529296875e-05 0.0 1.5296316964285714e-05 0.0 1.5296874999999997e-05 1.5 1.5310825892857143e-05 1.5 1.5311383928571426e-05 0.0 1.531361607142857e-05 0.0 1.5314174107142856e-05 1.5 1.5328683035714285e-05 1.5 1.5329241071428572e-05 0.0 1.5331473214285712e-05 0.0 1.533203125e-05 1.5 1.5346540178571427e-05 1.5 1.5347098214285714e-05 0.0 1.5349330357142858e-05 0.0 1.534988839285714e-05 1.5 1.536439732142857e-05 1.5 1.5364955357142856e-05 0.0 1.53671875e-05 0.0 1.5367745535714283e-05 1.5 1.5382254464285712e-05 1.5 1.53828125e-05 0.0 1.5385044642857142e-05 0.0 1.538560267857143e-05 1.5 1.5400111607142858e-05 1.5 1.540066964285714e-05 0.0 1.5402901785714285e-05 0.0 1.540345982142857e-05 1.5 1.541796875e-05 1.5 1.5418526785714283e-05 0.0 1.5420758928571427e-05 0.0 1.5421316964285714e-05 1.5 1.5435825892857142e-05 1.5 1.543638392857143e-05 0.0 1.543861607142857e-05 0.0 1.5439174107142856e-05 1.5 1.5453683035714285e-05 1.5 1.545424107142857e-05 0.0 1.545647321428571e-05 0.0 1.545703125e-05 1.5 1.5471540178571427e-05 1.5 1.5472098214285714e-05 0.0 1.5474330357142857e-05 0.0 1.547488839285714e-05 1.5 1.548939732142857e-05 1.5 1.5489955357142856e-05 0.0 1.54921875e-05 0.0 1.5492745535714283e-05 1.5 1.550725446428571e-05 1.5 1.55078125e-05 0.0 1.5510044642857142e-05 0.0 1.551060267857143e-05 1.5 1.5525111607142857e-05 1.5 1.552566964285714e-05 0.0 1.5527901785714284e-05 0.0 1.552845982142857e-05 1.5 1.554296875e-05 1.5 1.5543526785714283e-05 0.0 1.5545758928571427e-05 0.0 1.5546316964285713e-05 1.5 1.5560825892857142e-05 1.5 1.556138392857143e-05 0.0 1.556361607142857e-05 0.0 1.5564174107142856e-05 1.5 1.5578683035714284e-05 1.5 1.557924107142857e-05 0.0 1.5581473214285715e-05 0.0 1.5582031249999998e-05 1.5 1.5596540178571427e-05 1.5 1.5597098214285713e-05 0.0 1.5599330357142857e-05 0.0 1.559988839285714e-05 1.5 1.561439732142857e-05 1.5 1.5614955357142856e-05 0.0 1.56171875e-05 0.0 1.5617745535714286e-05 1.5 1.5632254464285715e-05 1.5 1.5632812499999998e-05 0.0 1.563504464285714e-05 0.0 1.563560267857143e-05 1.5 1.5650111607142857e-05 1.5 1.565066964285714e-05 0.0 1.5652901785714284e-05 0.0 1.565345982142857e-05 1.5 1.566796875e-05 1.5 1.5668526785714286e-05 0.0 1.5670758928571426e-05 0.0 1.5671316964285713e-05 1.5 1.568582589285714e-05 1.5 1.568638392857143e-05 0.0 1.5688616071428572e-05 0.0 1.5689174107142855e-05 1.5 1.5703683035714284e-05 1.5 1.570424107142857e-05 0.0 1.5706473214285714e-05 0.0 1.5707031249999998e-05 1.5 1.5721540178571426e-05 1.5 1.5722098214285713e-05 0.0 1.5724330357142857e-05 0.0 1.5724888392857143e-05 1.5 1.5739397321428572e-05 1.5 1.5739955357142855e-05 0.0 1.57421875e-05 0.0 1.5742745535714286e-05 1.5 1.5757254464285714e-05 1.5 1.5757812499999998e-05 0.0 1.576004464285714e-05 0.0 1.5760602678571428e-05 1.5 1.5775111607142857e-05 1.5 1.5775669642857143e-05 0.0 1.5777901785714284e-05 0.0 1.577845982142857e-05 1.5 1.579296875e-05 1.5 1.5793526785714286e-05 0.0 1.5795758928571426e-05 0.0 1.5796316964285713e-05 1.5 1.581082589285714e-05 1.5 1.5811383928571428e-05 0.0 1.581361607142857e-05 0.0 1.5814174107142855e-05 1.5 1.5828683035714284e-05 1.5 1.582924107142857e-05 0.0 1.5831473214285714e-05 0.0 1.5832031249999997e-05 1.5 1.5846540178571426e-05 1.5 1.5847098214285713e-05 0.0 1.5849330357142856e-05 0.0 1.5849888392857143e-05 1.5 1.586439732142857e-05 1.5 1.5864955357142855e-05 0.0 1.58671875e-05 0.0 1.5867745535714285e-05 1.5 1.5882254464285714e-05 1.5 1.5882812499999997e-05 0.0 1.588504464285714e-05 0.0 1.5885602678571428e-05 1.5 1.5900111607142856e-05 1.5 1.5900669642857143e-05 0.0 1.5902901785714283e-05 0.0 1.590345982142857e-05 1.5 1.591796875e-05 1.5 1.5918526785714285e-05 0.0 1.592075892857143e-05 0.0 1.5921316964285712e-05 1.5 1.593582589285714e-05 1.5 1.5936383928571428e-05 0.0 1.593861607142857e-05 0.0 1.5939174107142855e-05 1.5 1.5953683035714283e-05 1.5 1.595424107142857e-05 0.0 1.5956473214285714e-05 0.0 1.595703125e-05 1.5 1.597154017857143e-05 1.5 1.5972098214285712e-05 0.0 1.5974330357142856e-05 0.0 1.5974888392857143e-05 1.5 1.598939732142857e-05 1.5 1.5989955357142855e-05 0.0 1.5992187499999998e-05 0.0 1.5992745535714285e-05 1.5 1.6007254464285714e-05 1.5 1.60078125e-05 0.0 1.601004464285714e-05 0.0 1.6010602678571427e-05 1.5 1.6025111607142856e-05 1.5 1.6025669642857143e-05 0.0 1.6027901785714283e-05 0.0 1.602845982142857e-05 1.5 1.6042968749999998e-05 1.5 1.6043526785714285e-05 0.0 1.604575892857143e-05 0.0 1.6046316964285712e-05 1.5 1.606082589285714e-05 1.5 1.6061383928571427e-05 0.0 1.606361607142857e-05 0.0 1.6064174107142858e-05 1.5 1.6078683035714286e-05 1.5 1.607924107142857e-05 0.0 1.6081473214285713e-05 0.0 1.608203125e-05 1.5 1.609654017857143e-05 1.5 1.6097098214285712e-05 0.0 1.6099330357142856e-05 0.0 1.6099888392857142e-05 1.5 1.611439732142857e-05 1.5 1.6114955357142858e-05 0.0 1.6117187499999998e-05 0.0 1.6117745535714285e-05 1.5 1.6132254464285713e-05 1.5 1.61328125e-05 0.0 1.613504464285714e-05 0.0 1.6135602678571427e-05 1.5 1.6150111607142856e-05 1.5 1.6150669642857142e-05 0.0 1.6152901785714286e-05 0.0 1.615345982142857e-05 1.5 1.6167968749999998e-05 1.5 1.6168526785714285e-05 0.0 1.6170758928571428e-05 0.0 1.617131696428571e-05 1.5 1.618582589285714e-05 1.5 1.6186383928571427e-05 0.0 1.618861607142857e-05 0.0 1.6189174107142857e-05 1.5 1.6203683035714286e-05 1.5 1.620424107142857e-05 0.0 1.6206473214285713e-05 0.0 1.620703125e-05 1.5 1.6221540178571428e-05 1.5 1.622209821428571e-05 0.0 1.6224330357142855e-05 0.0 1.6224888392857142e-05 1.5 1.623939732142857e-05 1.5 1.6239955357142857e-05 0.0 1.6242187499999998e-05 0.0 1.6242745535714284e-05 1.5 1.6257254464285713e-05 1.5 1.62578125e-05 0.0 1.6260044642857143e-05 0.0 1.6260602678571427e-05 1.5 1.6275111607142855e-05 1.5 1.6275669642857142e-05 0.0 1.6277901785714286e-05 0.0 1.627845982142857e-05 1.5 1.6292968749999998e-05 1.5 1.6293526785714284e-05 0.0 1.6295758928571428e-05 0.0 1.6296316964285715e-05 1.5 1.6310825892857143e-05 1.5 1.6311383928571427e-05 0.0 1.631361607142857e-05 0.0 1.6314174107142857e-05 1.5 1.6328683035714286e-05 1.5 1.632924107142857e-05 0.0 1.6331473214285713e-05 0.0 1.633203125e-05 1.5 1.6346540178571428e-05 1.5 1.6347098214285715e-05 0.0 1.6349330357142855e-05 0.0 1.634988839285714e-05 1.5 1.636439732142857e-05 1.5 1.6364955357142857e-05 0.0 1.6367187499999997e-05 0.0 1.6367745535714284e-05 1.5 1.6382254464285713e-05 1.5 1.63828125e-05 0.0 1.6385044642857143e-05 0.0 1.6385602678571426e-05 1.5 1.6400111607142855e-05 1.5 1.640066964285714e-05 0.0 1.6402901785714285e-05 0.0 1.640345982142857e-05 1.5 1.6417968749999997e-05 1.5 1.6418526785714284e-05 0.0 1.6420758928571428e-05 0.0 1.6421316964285714e-05 1.5 1.6435825892857143e-05 1.5 1.6436383928571426e-05 0.0 1.643861607142857e-05 0.0 1.6439174107142857e-05 1.5 1.6453683035714285e-05 1.5 1.645424107142857e-05 0.0 1.6456473214285712e-05 0.0 1.645703125e-05 1.5 1.6471540178571428e-05 1.5 1.6472098214285714e-05 0.0 1.6474330357142855e-05 0.0 1.647488839285714e-05 1.5 1.648939732142857e-05 1.5 1.6489955357142857e-05 0.0 1.64921875e-05 0.0 1.6492745535714284e-05 1.5 1.6507254464285712e-05 1.5 1.65078125e-05 0.0 1.6510044642857143e-05 0.0 1.6510602678571426e-05 1.5 1.6525111607142854e-05 1.5 1.652566964285714e-05 0.0 1.6527901785714285e-05 0.0 1.652845982142857e-05 1.5 1.654296875e-05 1.5 1.6543526785714284e-05 0.0 1.6545758928571427e-05 0.0 1.6546316964285714e-05 1.5 1.6560825892857143e-05 1.5 1.6561383928571426e-05 0.0 1.656361607142857e-05 0.0 1.6564174107142856e-05 1.5 1.6578683035714285e-05 1.5 1.657924107142857e-05 0.0 1.6581473214285712e-05 0.0 1.658203125e-05 1.5 1.6596540178571427e-05 1.5 1.6597098214285714e-05 0.0 1.6599330357142858e-05 0.0 1.659988839285714e-05 1.5 1.661439732142857e-05 1.5 1.6614955357142856e-05 0.0 1.66171875e-05 0.0 1.6617745535714283e-05 1.5 1.6632254464285712e-05 1.5 1.66328125e-05 0.0 1.6635044642857142e-05 0.0 1.663560267857143e-05 1.5 1.6650111607142858e-05 1.5 1.665066964285714e-05 0.0 1.6652901785714285e-05 0.0 1.665345982142857e-05 1.5 1.666796875e-05 1.5 1.6668526785714283e-05 0.0 1.6670758928571427e-05 0.0 1.6671316964285714e-05 1.5 1.6685825892857142e-05 1.5 1.668638392857143e-05 0.0 1.668861607142857e-05 0.0 1.6689174107142856e-05 1.5 1.6703683035714284e-05 1.5 1.670424107142857e-05 0.0 1.670647321428571e-05 0.0 1.6707031249999998e-05 1.5 1.6721540178571427e-05 1.5 1.6722098214285714e-05 0.0 1.6724330357142857e-05 0.0 1.672488839285714e-05 1.5 1.673939732142857e-05 1.5 1.6739955357142856e-05 0.0 1.67421875e-05 0.0 1.6742745535714283e-05 1.5 1.675725446428571e-05 1.5 1.6757812499999998e-05 0.0 1.6760044642857142e-05 0.0 1.676060267857143e-05 1.5 1.6775111607142857e-05 1.5 1.677566964285714e-05 0.0 1.6777901785714284e-05 0.0 1.677845982142857e-05 1.5 1.679296875e-05 1.5 1.6793526785714283e-05 0.0 1.6795758928571426e-05 0.0 1.6796316964285713e-05 1.5 1.6810267857142855e-05 1.5 1.6810825892857142e-05 0.0 1.6814174107142856e-05 0.0 1.6814732142857142e-05 1.5 1.6828124999999997e-05 1.5 1.6828683035714284e-05 0.0 1.6832031249999998e-05 0.0 1.6832589285714285e-05 1.5 1.6845982142857143e-05 1.5 1.6846540178571426e-05 0.0 1.684988839285714e-05 0.0 1.6850446428571427e-05 1.5 1.6863839285714285e-05 1.5 1.686439732142857e-05 0.0 1.6867745535714286e-05 0.0 1.686830357142857e-05 1.5 1.6881696428571428e-05 1.5 1.6882254464285714e-05 0.0 1.6885602678571428e-05 0.0 1.688616071428571e-05 1.5 1.689955357142857e-05 1.5 1.6900111607142857e-05 0.0 1.690345982142857e-05 0.0 1.6904017857142857e-05 1.5 1.6917410714285712e-05 1.5 1.691796875e-05 0.0 1.6921316964285713e-05 0.0 1.6921875e-05 1.5 1.6935267857142855e-05 1.5 1.693582589285714e-05 0.0 1.6939174107142855e-05 0.0 1.6939732142857142e-05 1.5 1.6953125e-05 1.5 1.6953683035714284e-05 0.0 1.6957031249999998e-05 0.0 1.6957589285714284e-05 1.5 1.6970982142857143e-05 1.5 1.6971540178571426e-05 0.0 1.6974888392857143e-05 0.0 1.6975446428571427e-05 1.5 1.6988839285714285e-05 1.5 1.6989397321428572e-05 0.0 1.6992745535714286e-05 0.0 1.699330357142857e-05 1.5 1.7006696428571427e-05 1.5 1.7007254464285714e-05 0.0 1.7010602678571428e-05 0.0 1.7011160714285715e-05 1.5 1.702455357142857e-05 1.5 1.7025111607142856e-05 0.0 1.702845982142857e-05 0.0 1.7029017857142857e-05 1.5 1.7042410714285712e-05 1.5 1.704296875e-05 0.0 1.7046316964285713e-05 0.0 1.7046875e-05 1.5 1.7060267857142854e-05 1.5 1.706082589285714e-05 0.0 1.7064174107142855e-05 0.0 1.706473214285714e-05 1.5 1.7078125e-05 1.5 1.7078683035714283e-05 0.0 1.7082031249999997e-05 0.0 1.7082589285714284e-05 1.5 1.7095982142857142e-05 1.5 1.7096540178571426e-05 0.0 1.7099888392857143e-05 0.0 1.7100446428571426e-05 1.5 1.7113839285714285e-05 1.5 1.711439732142857e-05 0.0 1.7117745535714285e-05 0.0 1.711830357142857e-05 1.5 1.713113839285714e-05 1.5 1.7131696428571427e-05 0.0 1.7136160714285714e-05 0.0 1.7136718749999998e-05 1.5 1.7148995535714286e-05 1.5 1.714955357142857e-05 0.0 1.7154017857142857e-05 0.0 1.715457589285714e-05 1.5 1.716685267857143e-05 1.5 1.716741071428571e-05 0.0 1.7171875e-05 0.0 1.7172433035714286e-05 1.5 1.718470982142857e-05 1.5 1.7185267857142857e-05 0.0 1.718973214285714e-05 0.0 1.7190290178571428e-05 1.5 1.7202566964285713e-05 1.5 1.7203125e-05 0.0 1.7207589285714284e-05 0.0 1.720814732142857e-05 1.5 1.7220424107142855e-05 1.5 1.7220982142857142e-05 0.0 1.7225446428571426e-05 0.0 1.7226004464285713e-05 1.5 1.7238281249999998e-05 1.5 1.7238839285714284e-05 0.0 1.724330357142857e-05 0.0 1.7243861607142855e-05 1.5 1.725613839285714e-05 1.5 1.7256696428571427e-05 0.0 1.7261160714285714e-05 0.0 1.7261718749999997e-05 1.5 1.7273995535714286e-05 1.5 1.727455357142857e-05 0.0 1.7279017857142856e-05 0.0 1.7279575892857143e-05 1.5 1.7291852678571428e-05 1.5 1.7292410714285715e-05 0.0 1.7296875e-05 0.0 1.7297433035714285e-05 1.5 1.730970982142857e-05 1.5 1.7310267857142857e-05 0.0 1.731473214285714e-05 0.0 1.7315290178571428e-05 1.5 1.7327566964285713e-05 1.5 1.7328125e-05 0.0 1.7332589285714283e-05 0.0 1.733314732142857e-05 1.5 1.7345424107142855e-05 1.5 1.7345982142857142e-05 0.0 1.735044642857143e-05 0.0 1.7351004464285712e-05 1.5 1.7363281249999997e-05 1.5 1.7363839285714284e-05 0.0 1.736830357142857e-05 0.0 1.7368861607142855e-05 1.5 1.7381138392857143e-05 1.5 1.7381696428571426e-05 0.0 1.7386160714285714e-05 0.0 1.738671875e-05 1.5 1.73984375e-05 1.5 1.7398995535714285e-05 0.0 1.7404575892857143e-05 0.0 1.7405133928571426e-05 1.5 1.741629464285714e-05 1.5 1.7416852678571428e-05 0.0 1.7422433035714285e-05 0.0 1.7422991071428572e-05 1.5 1.7434151785714283e-05 1.5 1.743470982142857e-05 0.0 1.7440290178571427e-05 0.0 1.7440848214285714e-05 1.5 1.745200892857143e-05 1.5 1.7452566964285712e-05 0.0 1.745814732142857e-05 0.0 1.7458705357142856e-05 1.5 1.746986607142857e-05 1.5 1.7470424107142855e-05 0.0 1.7476004464285712e-05 0.0 1.74765625e-05 1.5 1.7487723214285714e-05 1.5 1.748828125e-05 0.0 1.7493861607142854e-05 0.0 1.749441964285714e-05 1.5 1.7505580357142856e-05 1.5 1.7506138392857143e-05 0.0 1.751171875e-05 0.0 1.7512276785714283e-05 1.5 1.7523437499999998e-05 1.5 1.7523995535714285e-05 0.0 1.7529575892857142e-05 0.0 1.7530133928571426e-05 1.5 1.754129464285714e-05 1.5 1.7541852678571427e-05 0.0 1.7547433035714285e-05 0.0 1.754799107142857e-05 1.5 1.7559151785714283e-05 1.5 1.755970982142857e-05 0.0 1.7565290178571427e-05 0.0 1.7565848214285714e-05 1.5 1.757700892857143e-05 1.5 1.7577566964285712e-05 0.0 1.758314732142857e-05 0.0 1.7583705357142856e-05 1.5 1.759486607142857e-05 1.5 1.7595424107142854e-05 0.0 1.760100446428571e-05 0.0 1.76015625e-05 1.5 1.7612723214285713e-05 1.5 1.761328125e-05 0.0 1.7618861607142857e-05 0.0 1.761941964285714e-05 1.5 1.763002232142857e-05 1.5 1.7630580357142856e-05 0.0 1.7637276785714283e-05 0.0 1.763783482142857e-05 1.5 1.7647879464285714e-05 1.5 1.7648437499999998e-05 0.0 1.765513392857143e-05 0.0 1.7655691964285712e-05 1.5 1.7665736607142857e-05 1.5 1.766629464285714e-05 0.0 1.767299107142857e-05 0.0 1.7673549107142854e-05 1.5 1.768359375e-05 1.5 1.7684151785714286e-05 0.0 1.7690848214285713e-05 0.0 1.769140625e-05 1.5 1.770145089285714e-05 1.5 1.7702008928571428e-05 0.0 1.7708705357142856e-05 0.0 1.7709263392857142e-05 1.5 1.7719308035714284e-05 1.5 1.771986607142857e-05 0.0 1.7726562499999998e-05 0.0 1.7727120535714285e-05 1.5 1.7737165178571426e-05 1.5 1.7737723214285713e-05 0.0 1.774441964285714e-05 0.0 1.7744977678571427e-05 1.5 1.7755022321428572e-05 1.5 1.7755580357142855e-05 0.0 1.7762276785714286e-05 0.0 1.776283482142857e-05 1.5 1.7772879464285714e-05 1.5 1.7773437499999997e-05 0.0 1.778013392857143e-05 0.0 1.7780691964285712e-05 1.5 1.7790736607142856e-05 1.5 1.7791294642857143e-05 0.0 1.779799107142857e-05 0.0 1.7798549107142857e-05 1.5 1.780859375e-05 1.5 1.7809151785714286e-05 0.0 1.7815848214285713e-05 0.0 1.781640625e-05 1.5 1.782645089285714e-05 1.5 1.7827008928571428e-05 0.0 1.7833705357142855e-05 0.0 1.7834263392857142e-05 1.5 1.784375e-05 1.5 1.7844308035714283e-05 0.0 1.7852120535714284e-05 0.0 1.785267857142857e-05 1.5 1.7861607142857142e-05 1.5 1.7862165178571426e-05 0.0 1.7869977678571427e-05 0.0 1.7870535714285714e-05 1.5 1.7879464285714285e-05 1.5 1.788002232142857e-05 0.0 1.788783482142857e-05 0.0 1.7888392857142856e-05 1.5 1.7897321428571427e-05 1.5 1.7897879464285714e-05 0.0 1.790569196428571e-05 0.0 1.7906249999999998e-05 1.5 1.791517857142857e-05 1.5 1.7915736607142856e-05 0.0 1.7923549107142857e-05 0.0 1.792410714285714e-05 1.5 1.793303571428571e-05 1.5 1.793359375e-05 0.0 1.794140625e-05 0.0 1.7941964285714283e-05 1.5 1.7950892857142857e-05 1.5 1.795145089285714e-05 0.0 1.7959263392857142e-05 0.0 1.795982142857143e-05 1.5 1.796875e-05 1.5 1.7969308035714283e-05 0.0 1.7977120535714284e-05 0.0 1.797767857142857e-05 1.5 1.7986607142857142e-05 1.5 1.798716517857143e-05 0.0 1.7994977678571426e-05 0.0 1.7995535714285713e-05 1.5 1.8004464285714284e-05 1.5 1.800502232142857e-05 0.0 1.801283482142857e-05 0.0 1.8013392857142856e-05 1.5 1.8022321428571427e-05 1.5 1.8022879464285713e-05 0.0 1.8030691964285714e-05 0.0 1.8031249999999998e-05 1.5 1.804017857142857e-05 1.5 1.8040736607142856e-05 0.0 1.8048549107142857e-05 0.0 1.804910714285714e-05 1.5 1.8057477678571428e-05 1.5 1.805803571428571e-05 0.0 1.8066964285714286e-05 0.0 1.806752232142857e-05 1.5 1.807533482142857e-05 1.5 1.8075892857142857e-05 0.0 1.8084821428571428e-05 0.0 1.808537946428571e-05 1.5 1.8093191964285713e-05 1.5 1.809375e-05 0.0 1.810267857142857e-05 0.0 1.8103236607142857e-05 1.5 1.8111049107142855e-05 1.5 1.811160714285714e-05 0.0 1.8120535714285713e-05 0.0 1.812109375e-05 1.5 1.8128906249999997e-05 1.5 1.8129464285714284e-05 0.0 1.8138392857142855e-05 0.0 1.8138950892857142e-05 1.5 1.8146763392857143e-05 1.5 1.8147321428571426e-05 0.0 1.8156249999999997e-05 0.0 1.8156808035714284e-05 1.5 1.8164620535714285e-05 1.5 1.816517857142857e-05 0.0 1.8174107142857143e-05 0.0 1.8174665178571427e-05 1.5 1.8182477678571428e-05 1.5 1.8183035714285714e-05 0.0 1.8191964285714286e-05 0.0 1.819252232142857e-05 1.5 1.820033482142857e-05 1.5 1.8200892857142857e-05 0.0 1.8209821428571428e-05 0.0 1.8210379464285715e-05 1.5 1.8218191964285712e-05 1.5 1.821875e-05 0.0 1.822767857142857e-05 0.0 1.8228236607142857e-05 1.5 1.8236049107142855e-05 1.5 1.823660714285714e-05 0.0 1.8245535714285712e-05 0.0 1.824609375e-05 1.5 1.825390625e-05 1.5 1.8254464285714284e-05 0.0 1.8263392857142855e-05 0.0 1.826395089285714e-05 1.5 1.8271205357142856e-05 1.5 1.8271763392857143e-05 0.0 1.8281808035714284e-05 0.0 1.828236607142857e-05 1.5 1.8289062499999998e-05 1.5 1.8289620535714285e-05 0.0 1.8299665178571426e-05 0.0 1.8300223214285713e-05 1.5 1.830691964285714e-05 1.5 1.8307477678571427e-05 0.0 1.831752232142857e-05 0.0 1.8318080357142855e-05 1.5 1.8324776785714283e-05 1.5 1.832533482142857e-05 0.0 1.8335379464285714e-05 0.0 1.8335937499999998e-05 1.5 1.834263392857143e-05 1.5 1.8343191964285712e-05 0.0 1.8353236607142857e-05 0.0 1.835379464285714e-05 1.5 1.836049107142857e-05 1.5 1.8361049107142854e-05 0.0 1.837109375e-05 0.0 1.8371651785714286e-05 1.5 1.8378348214285713e-05 1.5 1.837890625e-05 0.0 1.838895089285714e-05 0.0 1.8389508928571428e-05 1.5 1.8396205357142855e-05 1.5 1.8396763392857142e-05 0.0 1.8406808035714284e-05 0.0 1.840736607142857e-05 1.5 1.8414062499999998e-05 1.5 1.8414620535714285e-05 0.0 1.8424665178571426e-05 0.0 1.8425223214285713e-05 1.5 1.843191964285714e-05 1.5 1.8432477678571427e-05 0.0 1.844252232142857e-05 0.0 1.8443080357142855e-05 1.5 1.8449776785714286e-05 1.5 1.845033482142857e-05 0.0 1.8460379464285714e-05 0.0 1.8460937499999997e-05 1.5 1.8467633928571428e-05 1.5 1.846819196428571e-05 0.0 1.8478236607142856e-05 0.0 1.8478794642857143e-05 1.5 1.848549107142857e-05 1.5 1.8486049107142857e-05 0.0 1.8496651785714285e-05 0.0 1.849720982142857e-05 1.5 1.8502790178571426e-05 1.5 1.8503348214285713e-05 0.0 1.8514508928571428e-05 0.0 1.8515066964285714e-05 1.5 1.8520647321428572e-05 1.5 1.8521205357142855e-05 0.0 1.853236607142857e-05 0.0 1.8532924107142857e-05 1.5 1.8538504464285714e-05 1.5 1.8539062499999997e-05 0.0 1.8550223214285712e-05 0.0 1.855078125e-05 1.5 1.8556361607142856e-05 1.5 1.8556919642857143e-05 0.0 1.8568080357142855e-05 0.0 1.856863839285714e-05 1.5 1.857421875e-05 1.5 1.8574776785714285e-05 0.0 1.85859375e-05 0.0 1.8586495535714284e-05 1.5 1.859207589285714e-05 1.5 1.8592633928571428e-05 0.0 1.8603794642857143e-05 0.0 1.8604352678571426e-05 1.5 1.8609933035714283e-05 1.5 1.861049107142857e-05 0.0 1.8621651785714285e-05 0.0 1.8622209821428572e-05 1.5 1.8627790178571426e-05 1.5 1.8628348214285712e-05 0.0 1.8639508928571427e-05 0.0 1.8640066964285714e-05 1.5 1.864564732142857e-05 1.5 1.8646205357142855e-05 0.0 1.865736607142857e-05 0.0 1.8657924107142856e-05 1.5 1.8663504464285714e-05 1.5 1.8664062499999997e-05 0.0 1.8675223214285712e-05 0.0 1.867578125e-05 1.5 1.8681361607142856e-05 1.5 1.8681919642857143e-05 0.0 1.8693080357142854e-05 0.0 1.869363839285714e-05 1.5 1.869921875e-05 1.5 1.8699776785714285e-05 0.0 1.87109375e-05 0.0 1.8711495535714283e-05 1.5 1.871707589285714e-05 1.5 1.8717633928571427e-05 0.0 1.8729352678571426e-05 0.0 1.8729910714285712e-05 1.5 1.8734375e-05 1.5 1.8734933035714283e-05 0.0 1.874720982142857e-05 0.0 1.8747767857142855e-05 1.5 1.8752232142857142e-05 1.5 1.875279017857143e-05 0.0 1.8765066964285714e-05 0.0 1.8765624999999997e-05 1.5 1.8770089285714284e-05 1.5 1.877064732142857e-05 0.0 1.8782924107142856e-05 0.0 1.8783482142857143e-05 1.5 1.8787946428571427e-05 1.5 1.8788504464285713e-05 0.0 1.880078125e-05 0.0 1.8801339285714285e-05 1.5 1.880580357142857e-05 1.5 1.8806361607142856e-05 0.0 1.881863839285714e-05 0.0 1.8819196428571427e-05 1.5 1.882366071428571e-05 1.5 1.8824218749999998e-05 0.0 1.8836495535714283e-05 0.0 1.883705357142857e-05 1.5 1.8841517857142857e-05 1.5 1.884207589285714e-05 0.0 1.885435267857143e-05 0.0 1.8854910714285712e-05 1.5 1.8859375e-05 1.5 1.8859933035714283e-05 0.0 1.887220982142857e-05 0.0 1.8872767857142854e-05 1.5 1.887723214285714e-05 1.5 1.887779017857143e-05 0.0 1.8890066964285713e-05 0.0 1.8890625e-05 1.5 1.8895089285714284e-05 1.5 1.889564732142857e-05 0.0 1.8907924107142856e-05 0.0 1.8908482142857142e-05 1.5 1.8912946428571426e-05 1.5 1.8913504464285713e-05 0.0 1.8925781249999998e-05 0.0 1.8926339285714285e-05 1.5 1.893080357142857e-05 1.5 1.8931361607142855e-05 0.0 1.894363839285714e-05 0.0 1.8944196428571427e-05 1.5 1.8948660714285714e-05 1.5 1.8949218749999998e-05 0.0 1.8961495535714286e-05 0.0 1.896205357142857e-05 1.5 1.8966517857142857e-05 1.5 1.896707589285714e-05 0.0 1.897935267857143e-05 0.0 1.8979910714285712e-05 1.5 1.8984375e-05 1.5 1.8984933035714286e-05 0.0 1.8997767857142857e-05 0.0 1.899832589285714e-05 1.5 1.9001674107142855e-05 1.5 1.900223214285714e-05 0.0 1.9015625e-05 0.0 1.9016183035714283e-05 1.5 1.901953125e-05 1.5 1.9020089285714284e-05 0.0 1.9033482142857142e-05 0.0 1.903404017857143e-05 1.5 1.9037388392857143e-05 1.5 1.9037946428571426e-05 0.0 1.9051339285714284e-05 0.0 1.905189732142857e-05 1.5 1.9055245535714285e-05 1.5 1.905580357142857e-05 0.0 1.9069196428571427e-05 0.0 1.9069754464285713e-05 1.5 1.9073102678571427e-05 1.5 1.9073660714285714e-05 0.0 1.908705357142857e-05 0.0 1.9087611607142856e-05 1.5 1.909095982142857e-05 1.5 1.9091517857142856e-05 0.0 1.910491071428571e-05 0.0 1.9105468749999998e-05 1.5 1.9108816964285712e-05 1.5 1.9109375e-05 0.0 1.9122767857142857e-05 0.0 1.912332589285714e-05 1.5 1.9126674107142854e-05 1.5 1.912723214285714e-05 0.0 1.9140625e-05 0.0 1.9141183035714283e-05 1.5 1.914453125e-05 1.5 1.9145089285714283e-05 0.0 1.9158482142857142e-05 0.0 1.915904017857143e-05 1.5 1.9162388392857142e-05 1.5 1.9162946428571426e-05 0.0 1.9176339285714284e-05 0.0 1.917689732142857e-05 1.5 1.9180245535714285e-05 1.5 1.918080357142857e-05 0.0 1.9194196428571426e-05 0.0 1.9194754464285713e-05 1.5 1.9198102678571427e-05 1.5 1.9198660714285714e-05 0.0 1.921205357142857e-05 0.0 1.9212611607142855e-05 1.5 1.921595982142857e-05 1.5 1.9216517857142856e-05 0.0 1.9229910714285714e-05 0.0 1.9230468749999998e-05 1.5 1.923381696428571e-05 1.5 1.9234374999999998e-05 0.0 1.9247767857142857e-05 0.0 1.924832589285714e-05 1.5 1.9251674107142857e-05 1.5 1.925223214285714e-05 0.0 1.9265625e-05 0.0 1.9266183035714286e-05 1.5 1.926953125e-05 1.5 1.9270089285714283e-05 0.0 1.928348214285714e-05 0.0 1.9284040178571428e-05 1.5 1.9287388392857142e-05 1.5 1.928794642857143e-05 0.0 1.9301339285714284e-05 0.0 1.930189732142857e-05 1.5 1.9305245535714284e-05 1.5 1.930580357142857e-05 0.0 1.9319754464285713e-05 0.0 1.93203125e-05 1.5 1.9322544642857143e-05 1.5 1.9323102678571427e-05 0.0 1.9337611607142855e-05 0.0 1.9338169642857142e-05 1.5 1.9340401785714285e-05 1.5 1.934095982142857e-05 0.0 1.9355468749999997e-05 0.0 1.9356026785714284e-05 1.5 1.9358258928571428e-05 1.5 1.9358816964285715e-05 0.0 1.9373325892857143e-05 0.0 1.9373883928571426e-05 1.5 1.937611607142857e-05 1.5 1.9376674107142857e-05 0.0 1.9391183035714285e-05 0.0 1.939174107142857e-05 1.5 1.9393973214285712e-05 1.5 1.939453125e-05 0.0 1.9409040178571428e-05 0.0 1.9409598214285715e-05 1.5 1.9411830357142855e-05 1.5 1.941238839285714e-05 0.0 1.942689732142857e-05 0.0 1.9427455357142857e-05 1.5 1.9429687499999997e-05 1.5 1.9430245535714284e-05 0.0 1.9444754464285712e-05 0.0 1.94453125e-05 1.5 1.9447544642857143e-05 1.5 1.9448102678571426e-05 0.0 1.9462611607142855e-05 0.0 1.946316964285714e-05 1.5 1.9465401785714285e-05 1.5 1.946595982142857e-05 0.0 1.9480468749999997e-05 0.0 1.9481026785714284e-05 1.5 1.9483258928571427e-05 1.5 1.9483816964285714e-05 0.0 1.9498325892857143e-05 0.0 1.9498883928571426e-05 1.5 1.950111607142857e-05 1.5 1.9501674107142857e-05 0.0 1.9516183035714285e-05 0.0 1.951674107142857e-05 1.5 1.9518973214285712e-05 1.5 1.951953125e-05 0.0 1.9534040178571427e-05 0.0 1.9534598214285714e-05 1.5 1.9536830357142854e-05 1.5 1.953738839285714e-05 0.0 1.955189732142857e-05 0.0 1.9552455357142856e-05 1.5 1.95546875e-05 1.5 1.9555245535714283e-05 0.0 1.9569754464285712e-05 0.0 1.95703125e-05 1.5 1.9572544642857142e-05 1.5 1.9573102678571426e-05 0.0 1.9587611607142854e-05 0.0 1.958816964285714e-05 1.5 1.9590401785714285e-05 1.5 1.959095982142857e-05 0.0 1.960546875e-05 0.0 1.9606026785714283e-05 1.5 1.9608258928571427e-05 1.5 1.9608816964285714e-05 0.0 1.9623325892857142e-05 0.0 1.9623883928571426e-05 1.5 1.962611607142857e-05 1.5 1.9626674107142856e-05 0.0 1.9641183035714285e-05 0.0 1.964174107142857e-05 1.5 1.9643973214285712e-05 1.5 1.964453125e-05 0.0 1.9659040178571427e-05 0.0 1.9659598214285714e-05 1.5 1.9661830357142854e-05 1.5 1.966238839285714e-05 0.0 1.967689732142857e-05 0.0 1.9677455357142856e-05 1.5 1.96796875e-05 1.5 1.9680245535714283e-05 0.0 1.9694754464285712e-05 0.0 1.96953125e-05 1.5 1.9697544642857142e-05 1.5 1.9698102678571425e-05 0.0 1.9712611607142857e-05 0.0 1.971316964285714e-05 1.5 1.9715401785714284e-05 1.5 1.971595982142857e-05 0.0 1.973046875e-05 0.0 1.9731026785714283e-05 1.5 1.9733258928571427e-05 1.5 1.9733816964285714e-05 0.0 1.9748325892857142e-05 0.0 1.974888392857143e-05 1.5 1.975111607142857e-05 1.5 1.9751674107142856e-05 0.0 1.9766183035714284e-05 0.0 1.976674107142857e-05 1.5 1.976897321428571e-05 1.5 1.9769531249999998e-05 0.0 1.9784040178571427e-05 0.0 1.9784598214285713e-05 1.5 1.9786830357142857e-05 1.5 1.978738839285714e-05 0.0 1.980189732142857e-05 0.0 1.9802455357142856e-05 1.5 1.98046875e-05 1.5 1.9805245535714283e-05 0.0 1.981975446428571e-05 0.0 1.9820312499999998e-05 1.5 1.9822544642857142e-05 1.5 1.982310267857143e-05 0.0 1.9837611607142857e-05 0.0 1.983816964285714e-05 1.5 1.9840401785714284e-05 1.5 1.984095982142857e-05 0.0 1.985546875e-05 0.0 1.9856026785714283e-05 1.5 1.9858258928571426e-05 1.5 1.9858816964285713e-05 0.0 1.9873325892857142e-05 0.0 1.987388392857143e-05 1.5 1.987611607142857e-05 1.5 1.9876674107142855e-05 0.0 1.9891183035714284e-05 0.0 1.989174107142857e-05 1.5 1.9893973214285714e-05 1.5 1.9894531249999998e-05 0.0 1.9909040178571426e-05 0.0 1.9909598214285713e-05 1.5 1.9911830357142857e-05 1.5 1.991238839285714e-05 0.0 1.992689732142857e-05 0.0 1.9927455357142855e-05 1.5 1.99296875e-05 1.5 1.9930245535714286e-05 0.0 1.9944754464285714e-05 0.0 1.9945312499999998e-05 1.5 1.994754464285714e-05 1.5 1.9948102678571428e-05 0.0 1.9962611607142857e-05 0.0 1.996316964285714e-05 1.5 1.9965401785714284e-05 1.5 1.996595982142857e-05 0.0 1.998046875e-05 0.0 1.9981026785714286e-05 1.5 1.9983258928571426e-05 1.5 1.9983816964285713e-05 0.0 1.999832589285714e-05 0.0 1.9998883928571428e-05 1.5 2.000111607142857e-05 1.5 2.0001674107142855e-05 0.0 2.0016183035714284e-05 0.0 2.001674107142857e-05 1.5 2.0018973214285714e-05 1.5 2.0019531249999997e-05 0.0 2.0034040178571426e-05 0.0 2.0034598214285713e-05 1.5 2.0036830357142856e-05 1.5 2.003738839285714e-05 0.0 2.005189732142857e-05 0.0 2.0052455357142855e-05 1.5 2.00546875e-05 1.5 2.0055245535714285e-05 0.0 2.0069754464285714e-05 0.0 2.0070312499999997e-05 1.5 2.007254464285714e-05 1.5 2.0073102678571428e-05 0.0 2.0087611607142856e-05 0.0 2.008816964285714e-05 1.5 2.0090401785714283e-05 1.5 2.009095982142857e-05 0.0 2.010546875e-05 0.0 2.0106026785714285e-05 1.5 2.0108258928571426e-05 1.5 2.0108816964285712e-05 0.0 2.012332589285714e-05 0.0 2.0123883928571428e-05 1.5 2.012611607142857e-05 1.5 2.0126674107142855e-05 0.0 2.0141183035714283e-05 0.0 2.014174107142857e-05 1.5 2.0143973214285714e-05 1.5 2.0144531249999997e-05 0.0 2.0159040178571426e-05 0.0 2.0159598214285712e-05 1.5 2.0161830357142856e-05 1.5 2.0162388392857143e-05 0.0 2.017689732142857e-05 0.0 2.0177455357142855e-05 1.5 2.01796875e-05 1.5 2.0180245535714285e-05 0.0 2.0194754464285714e-05 0.0 2.0195312499999997e-05 1.5 2.019754464285714e-05 1.5 2.0198102678571427e-05 0.0 2.0212611607142856e-05 0.0 2.0213169642857143e-05 1.5 2.0215401785714283e-05 1.5 2.021595982142857e-05 0.0 2.023046875e-05 0.0 2.0231026785714285e-05 1.5 2.023325892857143e-05 1.5 2.0233816964285712e-05 0.0 2.024832589285714e-05 0.0 2.0248883928571427e-05 1.5 2.025111607142857e-05 1.5 2.0251674107142854e-05 0.0 2.0266183035714283e-05 0.0 2.026674107142857e-05 1.5 2.0268973214285713e-05 1.5 2.026953125e-05 0.0 2.028404017857143e-05 0.0 2.0284598214285712e-05 1.5 2.0286830357142856e-05 1.5 2.0287388392857142e-05 0.0 2.030189732142857e-05 0.0 2.0302455357142854e-05 1.5 2.0304687499999998e-05 1.5 2.0305245535714285e-05 0.0 2.0319754464285713e-05 0.0 2.03203125e-05 1.5 2.032254464285714e-05 1.5 2.0323102678571427e-05 0.0 2.0337611607142856e-05 0.0 2.0338169642857142e-05 1.5 2.0340401785714283e-05 1.5 2.034095982142857e-05 0.0 2.0355468749999998e-05 0.0 2.0356026785714285e-05 1.5 2.035825892857143e-05 1.5 2.0358816964285712e-05 0.0 2.037332589285714e-05 0.0 2.0373883928571427e-05 1.5 2.037611607142857e-05 1.5 2.0376674107142854e-05 0.0 2.0391183035714283e-05 0.0 2.039174107142857e-05 1.5 2.0393973214285713e-05 1.5 2.039453125e-05 0.0 2.040904017857143e-05 0.0 2.0409598214285712e-05 1.5 2.0411830357142855e-05 1.5 2.0412388392857142e-05 0.0 2.042689732142857e-05 0.0 2.0427455357142854e-05 1.5 2.0429687499999998e-05 1.5 2.0430245535714284e-05 0.0 2.0444754464285713e-05 0.0 2.04453125e-05 1.5 2.044754464285714e-05 1.5 2.0448102678571427e-05 0.0 2.0462611607142855e-05 0.0 2.0463169642857142e-05 1.5 2.0465401785714286e-05 1.5 2.046595982142857e-05 0.0 2.0480468749999998e-05 0.0 2.0481026785714284e-05 1.5 2.0483258928571428e-05 1.5 2.048381696428571e-05 0.0 2.049832589285714e-05 0.0 2.0498883928571427e-05 1.5 2.050111607142857e-05 1.5 2.0501674107142857e-05 0.0 2.0516183035714286e-05 0.0 2.051674107142857e-05 1.5 2.0518973214285713e-05 1.5 2.051953125e-05 0.0 2.0534040178571428e-05 0.0 2.053459821428571e-05 1.5 2.0536830357142855e-05 1.5 2.0537388392857142e-05 0.0 2.055189732142857e-05 0.0 2.0552455357142857e-05 1.5 2.0554687499999997e-05 1.5 2.0555245535714284e-05 0.0 2.0569754464285713e-05 0.0 2.05703125e-05 1.5 2.0572544642857143e-05 1.5 2.0573102678571426e-05 0.0 2.0587611607142855e-05 0.0 2.0588169642857142e-05 1.5 2.0590401785714285e-05 1.5 2.059095982142857e-05 0.0 2.0605468749999997e-05 0.0 2.0606026785714284e-05 1.5 2.0608258928571428e-05 1.5 2.0608816964285714e-05 0.0 2.0623325892857143e-05 0.0 2.0623883928571426e-05 1.5 2.062611607142857e-05 1.5 2.0626674107142857e-05 0.0 2.0641183035714285e-05 0.0 2.064174107142857e-05 1.5 2.0643973214285712e-05 1.5 2.064453125e-05 0.0 2.0659040178571428e-05 0.0 2.0659598214285714e-05 1.5 2.0661830357142855e-05 1.5 2.066238839285714e-05 0.0 2.067689732142857e-05 0.0 2.0677455357142857e-05 1.5 2.0679687499999997e-05 1.5 2.0680245535714284e-05 0.0 2.0694754464285712e-05 0.0 2.06953125e-05 1.5 2.0697544642857143e-05 1.5 2.0698102678571426e-05 0.0 2.0712611607142855e-05 0.0 2.071316964285714e-05 1.5 2.0715401785714285e-05 1.5 2.071595982142857e-05 0.0 2.0730468749999997e-05 0.0 2.0731026785714284e-05 1.5 2.0733258928571427e-05 1.5 2.0733816964285714e-05 0.0 2.0748325892857143e-05 0.0 2.0748883928571426e-05 1.5 2.075111607142857e-05 1.5 2.0751674107142856e-05 0.0 2.0766183035714285e-05 0.0 2.076674107142857e-05 1.5 2.0768973214285712e-05 1.5 2.076953125e-05 0.0 2.0784040178571427e-05 0.0 2.0784598214285714e-05 1.5 2.0786830357142854e-05 1.5 2.078738839285714e-05 0.0 2.080189732142857e-05 0.0 2.0802455357142856e-05 1.5 2.08046875e-05 1.5 2.0805245535714283e-05 0.0 2.081919642857143e-05 0.0 2.0819754464285712e-05 1.5 2.0823102678571426e-05 1.5 2.0823660714285712e-05 0.0 2.083705357142857e-05 0.0 2.0837611607142854e-05 1.5 2.084095982142857e-05 1.5 2.0841517857142855e-05 0.0 2.0854910714285713e-05 0.0 2.085546875e-05 1.5 2.0858816964285714e-05 1.5 2.0859374999999997e-05 0.0 2.0872767857142856e-05 0.0 2.0873325892857142e-05 1.5 2.0876674107142856e-05 1.5 2.0877232142857143e-05 0.0 2.0890624999999998e-05 0.0 2.0891183035714285e-05 1.5 2.089453125e-05 1.5 2.0895089285714285e-05 0.0 2.090848214285714e-05 0.0 2.0909040178571427e-05 1.5 2.091238839285714e-05 1.5 2.0912946428571427e-05 0.0 2.0926339285714283e-05 0.0 2.092689732142857e-05 1.5 2.0930245535714283e-05 1.5 2.093080357142857e-05 0.0 2.0944196428571428e-05 0.0 2.094475446428571e-05 1.5 2.094810267857143e-05 1.5 2.0948660714285712e-05 0.0 2.096205357142857e-05 0.0 2.0962611607142857e-05 1.5 2.096595982142857e-05 1.5 2.0966517857142854e-05 0.0 2.0979910714285713e-05 0.0 2.098046875e-05 1.5 2.0983816964285713e-05 1.5 2.0984375e-05 0.0 2.0997767857142855e-05 0.0 2.0998325892857142e-05 1.5 2.1001674107142856e-05 1.5 2.1002232142857142e-05 0.0 2.1015624999999998e-05 0.0 2.1016183035714284e-05 1.5 2.1019531249999998e-05 1.5 2.1020089285714285e-05 0.0 2.103348214285714e-05 0.0 2.1034040178571427e-05 1.5 2.103738839285714e-05 1.5 2.1037946428571427e-05 0.0 2.1051339285714286e-05 0.0 2.105189732142857e-05 1.5 2.1055245535714283e-05 1.5 2.105580357142857e-05 0.0 2.1069196428571428e-05 0.0 2.106975446428571e-05 1.5 2.107310267857143e-05 1.5 2.1073660714285712e-05 0.0 2.108705357142857e-05 0.0 2.1087611607142857e-05 1.5 2.109095982142857e-05 1.5 2.1091517857142854e-05 0.0 2.1104910714285713e-05 0.0 2.110546875e-05 1.5 2.1108816964285713e-05 1.5 2.1109375e-05 0.0 2.1122767857142855e-05 0.0 2.112332589285714e-05 1.5 2.1126674107142855e-05 1.5 2.1127232142857142e-05 0.0 2.1140066964285714e-05 0.0 2.1140624999999997e-05 1.5 2.1145089285714284e-05 1.5 2.114564732142857e-05 0.0 2.1157924107142856e-05 0.0 2.1158482142857143e-05 1.5 2.1162946428571427e-05 1.5 2.1163504464285714e-05 0.0 2.117578125e-05 0.0 2.1176339285714285e-05 1.5 2.118080357142857e-05 1.5 2.1181361607142856e-05 0.0 2.119363839285714e-05 0.0 2.1194196428571428e-05 1.5 2.119866071428571e-05 1.5 2.1199218749999998e-05 0.0 2.1211495535714283e-05 0.0 2.121205357142857e-05 1.5 2.1216517857142857e-05 1.5 2.121707589285714e-05 0.0 2.1229352678571425e-05 0.0 2.1229910714285712e-05 1.5 2.1234375e-05 1.5 2.1234933035714283e-05 0.0 2.124720982142857e-05 0.0 2.1247767857142855e-05 1.5 2.1252232142857142e-05 1.5 2.125279017857143e-05 0.0 2.1265066964285713e-05 0.0 2.1265624999999997e-05 1.5 2.1270089285714284e-05 1.5 2.127064732142857e-05 0.0 2.1282924107142856e-05 0.0 2.1283482142857143e-05 1.5 2.1287946428571426e-05 1.5 2.1288504464285713e-05 0.0 2.1300781249999998e-05 0.0 2.1301339285714285e-05 1.5 2.130580357142857e-05 1.5 2.1306361607142856e-05 0.0 2.131863839285714e-05 0.0 2.1319196428571427e-05 1.5 2.132366071428571e-05 1.5 2.1324218749999998e-05 0.0 2.1336495535714283e-05 0.0 2.133705357142857e-05 1.5 2.1341517857142857e-05 1.5 2.134207589285714e-05 0.0 2.135435267857143e-05 0.0 2.1354910714285712e-05 1.5 2.1359375e-05 1.5 2.1359933035714286e-05 0.0 2.137220982142857e-05 0.0 2.1372767857142854e-05 1.5 2.137723214285714e-05 1.5 2.1377790178571428e-05 0.0 2.1390066964285713e-05 0.0 2.1390625e-05 1.5 2.1395089285714284e-05 1.5 2.139564732142857e-05 0.0 2.140736607142857e-05 0.0 2.1407924107142855e-05 1.5 2.1413504464285713e-05 1.5 2.14140625e-05 0.0 2.1425223214285714e-05 0.0 2.1425781249999998e-05 1.5 2.1431361607142855e-05 1.5 2.1431919642857142e-05 0.0 2.1443080357142857e-05 0.0 2.144363839285714e-05 1.5 2.1449218749999997e-05 1.5 2.1449776785714284e-05 0.0 2.14609375e-05 0.0 2.1461495535714286e-05 1.5 2.146707589285714e-05 1.5 2.1467633928571427e-05 0.0 2.147879464285714e-05 0.0 2.1479352678571428e-05 1.5 2.1484933035714286e-05 1.5 2.148549107142857e-05 0.0 2.1496651785714284e-05 0.0 2.149720982142857e-05 1.5 2.1502790178571428e-05 1.5 2.150334821428571e-05 0.0 2.1514508928571426e-05 0.0 2.1515066964285713e-05 1.5 2.152064732142857e-05 1.5 2.1521205357142857e-05 0.0 2.153236607142857e-05 0.0 2.1532924107142855e-05 1.5 2.1538504464285712e-05 1.5 2.15390625e-05 0.0 2.1550223214285714e-05 0.0 2.1550781249999997e-05 1.5 2.1556361607142855e-05 1.5 2.155691964285714e-05 0.0 2.1568080357142856e-05 0.0 2.156863839285714e-05 1.5 2.1574218749999997e-05 1.5 2.1574776785714284e-05 0.0 2.15859375e-05 0.0 2.1586495535714285e-05 1.5 2.1592075892857143e-05 1.5 2.1592633928571426e-05 0.0 2.160379464285714e-05 0.0 2.1604352678571428e-05 1.5 2.1609933035714285e-05 1.5 2.161049107142857e-05 0.0 2.1621651785714283e-05 0.0 2.162220982142857e-05 1.5 2.1627790178571427e-05 1.5 2.1628348214285714e-05 0.0 2.1638950892857142e-05 0.0 2.1639508928571426e-05 1.5 2.1646205357142857e-05 1.5 2.164676339285714e-05 0.0 2.1656808035714285e-05 0.0 2.165736607142857e-05 1.5 2.16640625e-05 1.5 2.1664620535714286e-05 0.0 2.1674665178571427e-05 0.0 2.1675223214285714e-05 1.5 2.168191964285714e-05 1.5 2.1682477678571428e-05 0.0 2.169252232142857e-05 0.0 2.1693080357142856e-05 1.5 2.1699776785714284e-05 1.5 2.170033482142857e-05 0.0 2.171037946428571e-05 0.0 2.17109375e-05 1.5 2.1717633928571426e-05 1.5 2.1718191964285713e-05 0.0 2.1728236607142854e-05 0.0 2.172879464285714e-05 1.5 2.1735491071428568e-05 1.5 2.1736049107142855e-05 0.0 2.174609375e-05 0.0 2.1746651785714283e-05 1.5 2.1753348214285714e-05 1.5 2.1753906249999997e-05 0.0 2.1763950892857142e-05 0.0 2.176450892857143e-05 1.5 2.1771205357142856e-05 1.5 2.1771763392857143e-05 0.0 2.1781808035714284e-05 0.0 2.178236607142857e-05 1.5 2.17890625e-05 1.5 2.1789620535714285e-05 0.0 2.1799665178571427e-05 0.0 2.1800223214285713e-05 1.5 2.180691964285714e-05 1.5 2.1807477678571428e-05 0.0 2.181752232142857e-05 0.0 2.1818080357142856e-05 1.5 2.1824776785714283e-05 1.5 2.182533482142857e-05 0.0 2.183537946428571e-05 0.0 2.1835937499999998e-05 1.5 2.1842633928571426e-05 1.5 2.1843191964285712e-05 0.0 2.1853236607142857e-05 0.0 2.185379464285714e-05 1.5 2.1861049107142855e-05 1.5 2.186160714285714e-05 0.0 2.1870535714285713e-05 0.0 2.187109375e-05 1.5 2.1878906249999997e-05 1.5 2.1879464285714284e-05 0.0 2.1888392857142855e-05 0.0 2.188895089285714e-05 1.5 2.1896763392857143e-05 1.5 2.1897321428571426e-05 0.0 2.1906249999999997e-05 0.0 2.1906808035714284e-05 1.5 2.1914620535714285e-05 1.5 2.191517857142857e-05 0.0 2.1924107142857143e-05 0.0 2.1924665178571426e-05 1.5 2.1932477678571427e-05 1.5 2.1933035714285714e-05 0.0 2.1941964285714285e-05 0.0 2.194252232142857e-05 1.5 2.195033482142857e-05 1.5 2.1950892857142856e-05 0.0 2.1959821428571428e-05 0.0 2.1960379464285714e-05 1.5 2.1968191964285712e-05 1.5 2.196875e-05 0.0 2.197767857142857e-05 0.0 2.1978236607142857e-05 1.5 2.1986049107142854e-05 1.5 2.198660714285714e-05 0.0 2.1995535714285712e-05 0.0 2.199609375e-05 1.5 2.200390625e-05 1.5 2.2004464285714283e-05 0.0 2.2013392857142854e-05 0.0 2.201395089285714e-05 1.5 2.2021763392857142e-05 1.5 2.2022321428571426e-05 0.0 2.2031249999999997e-05 0.0 2.2031808035714284e-05 1.5 2.2039620535714285e-05 1.5 2.204017857142857e-05 0.0 2.2049107142857143e-05 0.0 2.2049665178571426e-05 1.5 2.2057477678571427e-05 1.5 2.2058035714285714e-05 0.0 2.2066964285714285e-05 0.0 2.2067522321428568e-05 1.5 2.2075892857142856e-05 1.5 2.2076450892857143e-05 0.0 2.208426339285714e-05 0.0 2.2084821428571427e-05 1.5 2.209375e-05 1.5 2.2094308035714285e-05 0.0 2.2102120535714283e-05 0.0 2.210267857142857e-05 1.5 2.211160714285714e-05 1.5 2.2112165178571427e-05 0.0 2.211997767857143e-05 0.0 2.2120535714285712e-05 1.5 2.2129464285714283e-05 1.5 2.213002232142857e-05 0.0 2.213783482142857e-05 0.0 2.2138392857142854e-05 1.5 2.214732142857143e-05 1.5 2.2147879464285712e-05 0.0 2.2155691964285713e-05 0.0 2.215625e-05 1.5 2.216517857142857e-05 1.5 2.2165736607142854e-05 0.0 2.2173549107142855e-05 0.0 2.2174107142857142e-05 1.5 2.2183035714285713e-05 1.5 2.218359375e-05 0.0 2.2191406249999998e-05 0.0 2.2191964285714284e-05 1.5 2.2200892857142856e-05 1.5 2.2201450892857142e-05 0.0 2.220926339285714e-05 0.0 2.2209821428571427e-05 1.5 2.2218749999999998e-05 1.5 2.2219308035714285e-05 0.0 2.2227120535714286e-05 0.0 2.222767857142857e-05 1.5 2.223660714285714e-05 1.5 2.2237165178571427e-05 0.0 2.2244977678571428e-05 0.0 2.224553571428571e-05 1.5 2.2254464285714283e-05 1.5 2.225502232142857e-05 0.0 2.226283482142857e-05 0.0 2.2263392857142857e-05 1.5 2.227232142857143e-05 1.5 2.2272879464285712e-05 0.0 2.2280691964285713e-05 0.0 2.228125e-05 1.5 2.2290736607142854e-05 1.5 2.229129464285714e-05 0.0 2.2297991071428568e-05 0.0 2.2298549107142855e-05 1.5 2.230859375e-05 1.5 2.2309151785714283e-05 0.0 2.2315848214285714e-05 0.0 2.2316406249999997e-05 1.5 2.2326450892857142e-05 1.5 2.2327008928571425e-05 0.0 2.2333705357142856e-05 0.0 2.233426339285714e-05 1.5 2.2344308035714284e-05 1.5 2.234486607142857e-05 0.0 2.23515625e-05 0.0 2.2352120535714285e-05 1.5 2.2362165178571427e-05 1.5 2.2362723214285713e-05 0.0 2.236941964285714e-05 0.0 2.2369977678571428e-05 1.5 2.238002232142857e-05 1.5 2.2380580357142856e-05 0.0 2.2387276785714283e-05 0.0 2.238783482142857e-05 1.5 2.239787946428571e-05 1.5 2.2398437499999998e-05 0.0 2.2405133928571426e-05 0.0 2.2405691964285712e-05 1.5 2.2415736607142857e-05 1.5 2.241629464285714e-05 0.0 2.242299107142857e-05 0.0 2.2423549107142855e-05 1.5 2.243359375e-05 1.5 2.2434151785714283e-05 0.0 2.2440848214285714e-05 0.0 2.2441406249999997e-05 1.5 2.2451450892857142e-05 1.5 2.245200892857143e-05 0.0 2.2458705357142856e-05 0.0 2.2459263392857143e-05 1.5 2.2469308035714284e-05 1.5 2.246986607142857e-05 0.0 2.24765625e-05 0.0 2.2477120535714285e-05 1.5 2.2487165178571426e-05 1.5 2.2487723214285713e-05 0.0 2.249441964285714e-05 0.0 2.2494977678571427e-05 1.5 2.2505580357142855e-05 1.5 2.2506138392857142e-05 0.0 2.251171875e-05 0.0 2.2512276785714283e-05 1.5 2.2523437499999998e-05 1.5 2.2523995535714285e-05 0.0 2.2529575892857142e-05 0.0 2.2530133928571425e-05 1.5 2.254129464285714e-05 1.5 2.2541852678571427e-05 0.0 2.2547433035714284e-05 0.0 2.254799107142857e-05 1.5 2.2559151785714286e-05 1.5 2.255970982142857e-05 0.0 2.2565290178571427e-05 0.0 2.2565848214285713e-05 1.5 2.2577008928571428e-05 1.5 2.257756696428571e-05 0.0 2.258314732142857e-05 0.0 2.2583705357142856e-05 1.5 2.259486607142857e-05 1.5 2.2595424107142857e-05 0.0 2.260100446428571e-05 0.0 2.2601562499999998e-05 1.5 2.2612723214285713e-05 1.5 2.261328125e-05 0.0 2.2618861607142857e-05 0.0 2.261941964285714e-05 1.5 2.2630580357142855e-05 1.5 2.2631138392857142e-05 0.0 2.263671875e-05 0.0 2.2637276785714283e-05 1.5 2.2648437499999997e-05 1.5 2.2648995535714284e-05 0.0 2.265457589285714e-05 0.0 2.265513392857143e-05 1.5 2.266629464285714e-05 1.5 2.2666852678571426e-05 0.0 2.2672433035714284e-05 0.0 2.267299107142857e-05 1.5 2.2684151785714285e-05 1.5 2.268470982142857e-05 0.0 2.2690290178571426e-05 0.0 2.2690848214285713e-05 1.5 2.2702008928571428e-05 1.5 2.270256696428571e-05 0.0 2.270814732142857e-05 0.0 2.2708705357142855e-05 1.5 2.271986607142857e-05 1.5 2.2720424107142857e-05 0.0 2.2726004464285714e-05 0.0 2.2726562499999998e-05 1.5 2.2737723214285712e-05 1.5 2.273828125e-05 0.0 2.274330357142857e-05 0.0 2.2743861607142857e-05 1.5 2.275613839285714e-05 1.5 2.2756696428571428e-05 0.0 2.2761160714285712e-05 0.0 2.276171875e-05 1.5 2.2773995535714284e-05 1.5 2.277455357142857e-05 0.0 2.2779017857142854e-05 0.0 2.277957589285714e-05 1.5 2.2791852678571426e-05 1.5 2.2792410714285713e-05 0.0 2.2796874999999997e-05 0.0 2.2797433035714284e-05 1.5 2.280970982142857e-05 1.5 2.2810267857142855e-05 0.0 2.2814732142857142e-05 0.0 2.2815290178571426e-05 1.5 2.2827566964285714e-05 1.5 2.2828124999999998e-05 0.0 2.2832589285714285e-05 0.0 2.2833147321428568e-05 1.5 2.2845424107142856e-05 1.5 2.284598214285714e-05 0.0 2.2850446428571427e-05 0.0 2.2851004464285714e-05 1.5 2.286328125e-05 1.5 2.2863839285714286e-05 0.0 2.286830357142857e-05 0.0 2.2868861607142856e-05 1.5 2.288113839285714e-05 1.5 2.2881696428571428e-05 0.0 2.2886160714285712e-05 0.0 2.288671875e-05 1.5 2.2898995535714283e-05 1.5 2.289955357142857e-05 0.0 2.2904017857142854e-05 0.0 2.290457589285714e-05 1.5 2.2916852678571426e-05 1.5 2.2917410714285713e-05 0.0 2.2921875e-05 0.0 2.2922433035714283e-05 1.5 2.2934709821428568e-05 1.5 2.2935267857142855e-05 0.0 2.2939732142857142e-05 0.0 2.2940290178571426e-05 1.5 2.2952566964285714e-05 1.5 2.2953124999999997e-05 0.0 2.2957589285714284e-05 0.0 2.295814732142857e-05 1.5 2.2970424107142856e-05 1.5 2.2970982142857143e-05 0.0 2.2975446428571427e-05 0.0 2.2976004464285714e-05 1.5 2.298828125e-05 1.5 2.2988839285714285e-05 0.0 2.299330357142857e-05 0.0 2.2993861607142856e-05 1.5 2.3006696428571428e-05 1.5 2.3007254464285714e-05 0.0 2.3010602678571428e-05 0.0 2.301116071428571e-05 1.5 2.302455357142857e-05 1.5 2.3025111607142857e-05 0.0 2.302845982142857e-05 0.0 2.3029017857142857e-05 1.5 2.3042410714285712e-05 1.5 2.304296875e-05 0.0 2.3046316964285713e-05 0.0 2.3046875e-05 1.5 2.3060267857142855e-05 1.5 2.306082589285714e-05 0.0 2.3064174107142855e-05 0.0 2.3064732142857142e-05 1.5 2.3078124999999997e-05 1.5 2.3078683035714284e-05 0.0 2.3082031249999997e-05 0.0 2.3082589285714284e-05 1.5 2.3095982142857143e-05 1.5 2.3096540178571426e-05 0.0 2.309988839285714e-05 0.0 2.3100446428571426e-05 1.5 2.3113839285714285e-05 1.5 2.3114397321428568e-05 0.0 2.3117745535714285e-05 0.0 2.311830357142857e-05 1.5 2.3131696428571427e-05 1.5 2.3132254464285714e-05 0.0 2.3135602678571428e-05 0.0 2.313616071428571e-05 1.5 2.314955357142857e-05 1.5 2.3150111607142856e-05 0.0 2.315345982142857e-05 0.0 2.3154017857142857e-05 1.5 2.3167410714285712e-05 1.5 2.316796875e-05 0.0 2.3171316964285712e-05 0.0 2.3171875e-05 1.5 2.3185267857142854e-05 1.5 2.318582589285714e-05 0.0 2.3189174107142855e-05 0.0 2.318973214285714e-05 1.5 2.3203125e-05 1.5 2.3203683035714283e-05 0.0 2.3207031249999997e-05 0.0 2.3207589285714284e-05 1.5 2.3220982142857142e-05 1.5 2.3221540178571426e-05 0.0 2.3224888392857143e-05 0.0 2.3225446428571426e-05 1.5 2.3238839285714285e-05 1.5 2.323939732142857e-05 0.0 2.3242745535714285e-05 0.0 2.324330357142857e-05 1.5 2.3256696428571427e-05 1.5 2.3257254464285714e-05 0.0 2.3260602678571427e-05 0.0 2.3261160714285714e-05 1.5 2.327455357142857e-05 1.5 2.3275111607142856e-05 0.0 2.327845982142857e-05 0.0 2.3279017857142856e-05 1.5 2.329241071428571e-05 1.5 2.3292968749999998e-05 0.0 2.3296316964285712e-05 0.0 2.3296875e-05 1.5 2.3310267857142854e-05 1.5 2.331082589285714e-05 0.0 2.3314174107142854e-05 0.0 2.331473214285714e-05 1.5 2.3328125e-05 1.5 2.3328683035714283e-05 0.0 2.3331473214285713e-05 0.0 2.3332031249999997e-05 1.5 2.3346540178571425e-05 1.5 2.3347098214285712e-05 0.0 2.3349330357142856e-05 0.0 2.3349888392857142e-05 1.5 2.336439732142857e-05 1.5 2.3364955357142854e-05 0.0 2.3367187499999998e-05 0.0 2.3367745535714285e-05 1.5 2.3382254464285713e-05 1.5 2.33828125e-05 0.0 2.338504464285714e-05 0.0 2.3385602678571427e-05 1.5 2.3400111607142856e-05 1.5 2.3400669642857142e-05 0.0 2.3402901785714283e-05 0.0 2.340345982142857e-05 1.5 2.3417968749999998e-05 1.5 2.3418526785714285e-05 0.0 2.3420758928571428e-05 0.0 2.342131696428571e-05 1.5 2.343582589285714e-05 1.5 2.3436383928571427e-05 0.0 2.343861607142857e-05 0.0 2.3439174107142854e-05 1.5 2.3453683035714283e-05 1.5 2.345424107142857e-05 0.0 2.3456473214285713e-05 0.0 2.345703125e-05 1.5 2.3471540178571428e-05 1.5 2.347209821428571e-05 0.0 2.3474330357142855e-05 0.0 2.3474888392857142e-05 1.5 2.348939732142857e-05 1.5 2.3489955357142854e-05 0.0 2.3492187499999998e-05 0.0 2.3492745535714284e-05 1.5 2.3507254464285713e-05 1.5 2.35078125e-05 0.0 2.351004464285714e-05 0.0 2.3510602678571427e-05 1.5 2.3525111607142855e-05 1.5 2.3525669642857142e-05 0.0 2.3527901785714286e-05 0.0 2.352845982142857e-05 1.5 2.3542968749999998e-05 1.5 2.3543526785714284e-05 0.0 2.3545758928571428e-05 0.0 2.354631696428571e-05 1.5 2.356082589285714e-05 1.5 2.3561383928571427e-05 0.0 2.356361607142857e-05 0.0 2.3564174107142857e-05 1.5 2.3578683035714286e-05 1.5 2.357924107142857e-05 0.0 2.3581473214285713e-05 0.0 2.358203125e-05 1.5 2.3596540178571428e-05 1.5 2.359709821428571e-05 0.0 2.3599330357142855e-05 0.0 2.359988839285714e-05 1.5 2.361439732142857e-05 1.5 2.3614955357142857e-05 0.0 2.3617187499999997e-05 0.0 2.3617745535714284e-05 1.5 2.3632254464285713e-05 1.5 2.36328125e-05 0.0 2.363504464285714e-05 0.0 2.3635602678571426e-05 1.5 2.3650111607142855e-05 1.5 2.365066964285714e-05 0.0 2.3652901785714285e-05 0.0 2.365345982142857e-05 1.5 2.3667968749999997e-05 1.5 2.3668526785714284e-05 0.0 2.3670758928571428e-05 0.0 2.367131696428571e-05 1.5 2.368582589285714e-05 1.5 2.3686383928571426e-05 0.0 2.368861607142857e-05 0.0 2.3689174107142857e-05 1.5 2.3703683035714285e-05 1.5 2.370424107142857e-05 0.0 2.3706473214285712e-05 0.0 2.370703125e-05 1.5 2.3721540178571428e-05 1.5 2.372209821428571e-05 0.0 2.3724330357142855e-05 0.0 2.372488839285714e-05 1.5 2.373939732142857e-05 1.5 2.3739955357142857e-05 0.0 2.3742187499999997e-05 0.0 2.3742745535714284e-05 1.5 2.3757254464285712e-05 1.5 2.37578125e-05 0.0 2.3760044642857143e-05 0.0 2.3760602678571426e-05 1.5 2.3775111607142855e-05 1.5 2.377566964285714e-05 0.0 2.3777901785714285e-05 0.0 2.3778459821428568e-05 1.5 2.3792968749999997e-05 1.5 2.3793526785714284e-05 0.0 2.3795758928571427e-05 0.0 2.3796316964285714e-05 1.5 2.3810825892857143e-05 1.5 2.3811383928571426e-05 0.0 2.381361607142857e-05 0.0 2.3814174107142856e-05 1.5 2.3828683035714285e-05 1.5 2.3829241071428568e-05 0.0 2.3831473214285712e-05 0.0 2.383203125e-05 1.5 2.3846540178571427e-05 1.5 2.3847098214285714e-05 0.0 2.3849330357142854e-05 0.0 2.384988839285714e-05 1.5 2.386439732142857e-05 1.5 2.3864955357142856e-05 0.0 2.38671875e-05 0.0 2.3867745535714283e-05 1.5 2.3882254464285712e-05 1.5 2.38828125e-05 0.0 2.3885044642857142e-05 0.0 2.3885602678571426e-05 1.5 2.3900111607142854e-05 1.5 2.390066964285714e-05 0.0 2.3902901785714285e-05 0.0 2.390345982142857e-05 1.5 2.391796875e-05 1.5 2.3918526785714283e-05 0.0 2.3920758928571427e-05 0.0 2.3921316964285714e-05 1.5 2.3935825892857142e-05 1.5 2.3936383928571426e-05 0.0 2.393861607142857e-05 0.0 2.3939174107142856e-05 1.5 2.3953683035714285e-05 1.5 2.395424107142857e-05 0.0 2.395647321428571e-05 0.0 2.3957031249999998e-05 1.5 2.3971540178571427e-05 1.5 2.3972098214285714e-05 0.0 2.3974330357142854e-05 0.0 2.397488839285714e-05 1.5 2.398939732142857e-05 1.5 2.3989955357142856e-05 0.0 2.39921875e-05 0.0 2.3992745535714283e-05 1.5 2.400725446428571e-05 1.5 2.4007812499999998e-05 0.0 2.4010044642857142e-05 0.0 2.4010602678571425e-05 1.5 2.4025111607142854e-05 1.5 2.402566964285714e-05 0.0 2.4027901785714284e-05 0.0 2.402845982142857e-05 1.5 2.404296875e-05 1.5 2.4043526785714283e-05 0.0 2.4045758928571427e-05 0.0 2.4046316964285713e-05 1.5 2.4060825892857142e-05 1.5 2.4061383928571425e-05 0.0 2.406361607142857e-05 0.0 2.4064174107142856e-05 1.5 2.4078683035714284e-05 1.5 2.407924107142857e-05 0.0 2.408147321428571e-05 0.0 2.4082031249999998e-05 1.5 2.4096540178571427e-05 1.5 2.4097098214285713e-05 0.0 2.4099330357142857e-05 0.0 2.409988839285714e-05 1.5 2.411439732142857e-05 1.5 2.4114955357142856e-05 0.0 2.41171875e-05 0.0 2.4117745535714283e-05 1.5 2.413225446428571e-05 1.5 2.4132812499999998e-05 0.0 2.413504464285714e-05 0.0 2.4135602678571428e-05 1.5 2.4150111607142857e-05 1.5 2.415066964285714e-05 0.0 2.4152901785714284e-05 0.0 2.415345982142857e-05 1.5 2.416796875e-05 1.5 2.4168526785714283e-05 0.0 2.4170758928571426e-05 0.0 2.4171316964285713e-05 1.5 2.418582589285714e-05 1.5 2.4186383928571428e-05 0.0 2.418861607142857e-05 0.0 2.4189174107142855e-05 1.5 2.4203683035714284e-05 1.5 2.420424107142857e-05 0.0 2.4206473214285714e-05 0.0 2.4207031249999998e-05 1.5 2.4221540178571426e-05 1.5 2.4222098214285713e-05 0.0 2.4224330357142857e-05 0.0 2.422488839285714e-05 1.5 2.423939732142857e-05 1.5 2.4239955357142855e-05 0.0 2.42421875e-05 0.0 2.4242745535714286e-05 1.5 2.4257254464285714e-05 1.5 2.4257812499999998e-05 0.0 2.426004464285714e-05 0.0 2.4260602678571428e-05 1.5 2.4275111607142857e-05 1.5 2.427566964285714e-05 0.0 2.4277901785714284e-05 0.0 2.427845982142857e-05 1.5 2.429296875e-05 1.5 2.4293526785714286e-05 0.0 2.4295758928571426e-05 0.0 2.4296316964285713e-05 1.5 2.431082589285714e-05 1.5 2.4311383928571428e-05 0.0 2.4313616071428568e-05 0.0 2.4314174107142855e-05 1.5 2.4328683035714283e-05 1.5 2.432924107142857e-05 0.0 2.4331473214285714e-05 0.0 2.4332031249999997e-05 1.5 2.4346540178571426e-05 1.5 2.4347098214285713e-05 0.0 2.4349330357142856e-05 0.0 2.434988839285714e-05 1.5 2.4364397321428568e-05 1.5 2.4364955357142855e-05 0.0 2.43671875e-05 0.0 2.4367745535714285e-05 1.5 2.4382254464285714e-05 1.5 2.4382812499999997e-05 0.0 2.438504464285714e-05 0.0 2.4385602678571428e-05 1.5 2.4400111607142856e-05 1.5 2.440066964285714e-05 0.0 2.4402901785714283e-05 0.0 2.440345982142857e-05 1.5 2.441796875e-05 1.5 2.4418526785714285e-05 0.0 2.4420758928571425e-05 0.0 2.4421316964285712e-05 1.5 2.443582589285714e-05 1.5 2.4436383928571428e-05 0.0 2.443861607142857e-05 0.0 2.4439174107142855e-05 1.5 2.4453683035714283e-05 1.5 2.445424107142857e-05 0.0 2.4456473214285714e-05 0.0 2.4457031249999997e-05 1.5 2.4471540178571425e-05 1.5 2.4472098214285712e-05 0.0 2.4474330357142856e-05 0.0 2.4474888392857143e-05 1.5 2.448939732142857e-05 1.5 2.4489955357142855e-05 0.0 2.4492187499999998e-05 0.0 2.4492745535714285e-05 1.5 2.4507254464285713e-05 1.5 2.4507812499999997e-05 0.0 2.451004464285714e-05 0.0 2.4510602678571427e-05 1.5 2.4525111607142856e-05 1.5 2.4525669642857143e-05 0.0 2.4527901785714283e-05 0.0 2.452845982142857e-05 1.5 2.4542968749999998e-05 1.5 2.4543526785714285e-05 0.0 2.4545758928571425e-05 0.0 2.4546316964285712e-05 1.5 2.456082589285714e-05 1.5 2.4561383928571427e-05 0.0 2.456361607142857e-05 0.0 2.4564174107142854e-05 1.5 2.4578683035714283e-05 1.5 2.457924107142857e-05 0.0 2.4581473214285713e-05 0.0 2.4582031249999997e-05 1.5 2.459654017857143e-05 1.5 2.4597098214285712e-05 0.0 2.4599330357142855e-05 0.0 2.4599888392857142e-05 1.5 2.461439732142857e-05 1.5 2.4614955357142854e-05 0.0 2.4617187499999998e-05 0.0 2.4617745535714285e-05 1.5 2.4632254464285713e-05 1.5 2.46328125e-05 0.0 2.463504464285714e-05 0.0 2.4635602678571427e-05 1.5 2.4650111607142855e-05 1.5 2.4650669642857142e-05 0.0 2.4652901785714282e-05 0.0 2.465345982142857e-05 1.5 2.4667968749999998e-05 1.5 2.4668526785714285e-05 0.0 2.4670758928571428e-05 0.0 2.467131696428571e-05 1.5 2.468582589285714e-05 1.5 2.4686383928571427e-05 0.0 2.468861607142857e-05 0.0 2.4689174107142854e-05 1.5 2.4703683035714282e-05 1.5 2.470424107142857e-05 0.0 2.4706473214285713e-05 0.0 2.470703125e-05 1.5 2.4721540178571428e-05 1.5 2.472209821428571e-05 0.0 2.4724330357142855e-05 0.0 2.4724888392857142e-05 1.5 2.473939732142857e-05 1.5 2.4739955357142854e-05 0.0 2.4742187499999997e-05 0.0 2.4742745535714284e-05 1.5 2.4757254464285713e-05 1.5 2.47578125e-05 0.0 2.476004464285714e-05 0.0 2.4760602678571427e-05 1.5 2.4775111607142855e-05 1.5 2.4775669642857142e-05 0.0 2.4777901785714286e-05 0.0 2.477845982142857e-05 1.5 2.4792968749999997e-05 1.5 2.4793526785714284e-05 0.0 2.4795758928571428e-05 0.0 2.479631696428571e-05 1.5 2.481082589285714e-05 1.5 2.4811383928571427e-05 0.0 2.481361607142857e-05 0.0 2.4814174107142857e-05 1.5 2.4828125e-05 1.5 2.4828683035714285e-05 0.0 2.483203125e-05 0.0 2.4832589285714283e-05 1.5 2.484598214285714e-05 1.5 2.4846540178571428e-05 0.0 2.484988839285714e-05 0.0 2.485044642857143e-05 1.5 2.4863839285714283e-05 1.5 2.486439732142857e-05 0.0 2.4867745535714284e-05 0.0 2.486830357142857e-05 1.5 2.4881696428571426e-05 1.5 2.4882254464285712e-05 0.0 2.4885602678571426e-05 0.0 2.4886160714285713e-05 1.5 2.4899553571428568e-05 1.5 2.4900111607142855e-05 0.0 2.490345982142857e-05 0.0 2.4904017857142855e-05 1.5 2.4917410714285714e-05 1.5 2.4917968749999997e-05 0.0 2.492131696428571e-05 0.0 2.4921874999999998e-05 1.5 2.4935267857142856e-05 1.5 2.493582589285714e-05 0.0 2.4939174107142857e-05 0.0 2.493973214285714e-05 1.5 2.4953125e-05 1.5 2.4953683035714285e-05 0.0 2.495703125e-05 0.0 2.4957589285714282e-05 1.5 2.497098214285714e-05 1.5 2.4971540178571427e-05 0.0 2.497488839285714e-05 0.0 2.4975446428571428e-05 1.5 2.4988839285714283e-05 1.5 2.498939732142857e-05 0.0 2.4992745535714284e-05 0.0 2.499330357142857e-05 1.5 2.5006696428571425e-05 1.5 2.5007254464285712e-05 0.0 2.5010602678571426e-05 0.0 2.5011160714285713e-05 1.5 2.502455357142857e-05 1.5 2.5025111607142854e-05 0.0 2.5028459821428568e-05 0.0 2.5029017857142855e-05 1.5 2.5042410714285713e-05 1.5 2.5042968749999997e-05 0.0 2.5046316964285714e-05 0.0 2.5046874999999997e-05 1.5 2.5060267857142856e-05 1.5 2.5060825892857142e-05 0.0 2.5064174107142856e-05 0.0 2.506473214285714e-05 1.5 2.5078124999999998e-05 1.5 2.5078683035714285e-05 0.0 2.508203125e-05 0.0 2.5082589285714285e-05 1.5 2.509598214285714e-05 1.5 2.5096540178571427e-05 0.0 2.509988839285714e-05 0.0 2.5100446428571428e-05 1.5 2.5113839285714283e-05 1.5 2.511439732142857e-05 0.0 2.5117745535714283e-05 0.0 2.511830357142857e-05 1.5 2.513169642857143e-05 1.5 2.5132254464285712e-05 0.0 2.5135602678571426e-05 0.0 2.5136160714285712e-05 1.5 2.514955357142857e-05 1.5 2.5150111607142854e-05 0.0 2.5154017857142855e-05 0.0 2.515457589285714e-05 1.5 2.5166852678571426e-05 1.5 2.5167410714285713e-05 0.0 2.5171874999999997e-05 0.0 2.5172433035714284e-05 1.5 2.518470982142857e-05 1.5 2.5185267857142855e-05 0.0 2.5189732142857143e-05 0.0 2.5190290178571426e-05 1.5 2.520256696428571e-05 1.5 2.5203124999999998e-05 0.0 2.5207589285714285e-05 0.0 2.520814732142857e-05 1.5 2.5220424107142857e-05 1.5 2.522098214285714e-05 0.0 2.5225446428571427e-05 0.0 2.5226004464285714e-05 1.5 2.523828125e-05 1.5 2.5238839285714282e-05 0.0 2.524330357142857e-05 0.0 2.5243861607142856e-05 1.5 2.525613839285714e-05 1.5 2.5256696428571428e-05 0.0 2.5261160714285712e-05 0.0 2.526171875e-05 1.5 2.5273995535714284e-05 1.5 2.527455357142857e-05 0.0 2.5279017857142854e-05 0.0 2.527957589285714e-05 1.5 2.5291852678571426e-05 1.5 2.5292410714285713e-05 0.0 2.5296874999999997e-05 0.0 2.5297433035714283e-05 1.5 2.5309709821428568e-05 1.5 2.5310267857142855e-05 0.0 2.5314732142857142e-05 0.0 2.5315290178571426e-05 1.5 2.5327566964285714e-05 1.5 2.5328124999999997e-05 0.0 2.5332589285714285e-05 0.0 2.5333147321428568e-05 1.5 2.5345424107142856e-05 1.5 2.534598214285714e-05 0.0 2.5350446428571427e-05 0.0 2.5351004464285714e-05 1.5 2.536328125e-05 1.5 2.5363839285714285e-05 0.0 2.536830357142857e-05 0.0 2.5368861607142856e-05 1.5 2.538113839285714e-05 1.5 2.5381696428571428e-05 0.0 2.538616071428571e-05 0.0 2.538671875e-05 1.5 2.5398995535714283e-05 1.5 2.539955357142857e-05 0.0 2.5404017857142854e-05 0.0 2.540457589285714e-05 1.5 2.5416294642857142e-05 1.5 2.5416852678571426e-05 0.0 2.5422433035714283e-05 0.0 2.542299107142857e-05 1.5 2.5434151785714285e-05 1.5 2.543470982142857e-05 0.0 2.5440290178571425e-05 0.0 2.5440848214285712e-05 1.5 2.5452008928571427e-05 1.5 2.5452566964285714e-05 0.0 2.545814732142857e-05 0.0 2.5458705357142854e-05 1.5 2.546986607142857e-05 1.5 2.5470424107142856e-05 0.0 2.5476004464285713e-05 0.0 2.5476562499999997e-05 1.5 2.548772321428571e-05 1.5 2.5488281249999998e-05 0.0 2.5493861607142856e-05 0.0 2.5494419642857142e-05 1.5 2.5505580357142854e-05 1.5 2.550613839285714e-05 0.0 2.5511718749999998e-05 0.0 2.5512276785714285e-05 1.5 2.55234375e-05 1.5 2.5523995535714283e-05 0.0 2.552957589285714e-05 0.0 2.5530133928571427e-05 1.5 2.5541294642857142e-05 1.5 2.5541852678571425e-05 0.0 2.5547433035714283e-05 0.0 2.554799107142857e-05 1.5 2.5559151785714284e-05 1.5 2.555970982142857e-05 0.0 2.556529017857143e-05 0.0 2.556584821428571e-05 1.5 2.5577008928571426e-05 1.5 2.5577566964285713e-05 0.0 2.558314732142857e-05 0.0 2.5583705357142854e-05 1.5 2.559486607142857e-05 1.5 2.5595424107142856e-05 0.0 2.5601004464285713e-05 0.0 2.56015625e-05 1.5 2.561272321428571e-05 1.5 2.5613281249999998e-05 0.0 2.5618861607142855e-05 0.0 2.5619419642857142e-05 1.5 2.5630580357142857e-05 1.5 2.563113839285714e-05 0.0 2.5636718749999998e-05 0.0 2.5637276785714284e-05 1.5 2.56484375e-05 1.5 2.5648995535714283e-05 0.0 2.5655133928571427e-05 0.0 2.5655691964285713e-05 1.5 2.5665736607142855e-05 1.5 2.566629464285714e-05 0.0 2.567299107142857e-05 0.0 2.5673549107142856e-05 1.5 2.5683593749999997e-05 1.5 2.5684151785714284e-05 0.0 2.569084821428571e-05 0.0 2.5691406249999998e-05 1.5 2.570145089285714e-05 1.5 2.5702008928571426e-05 0.0 2.5708705357142854e-05 0.0 2.570926339285714e-05 1.5 2.5719308035714285e-05 1.5 2.571986607142857e-05 0.0 2.57265625e-05 0.0 2.5727120535714283e-05 1.5 2.5737165178571427e-05 1.5 2.573772321428571e-05 0.0 2.5744419642857142e-05 0.0 2.5744977678571425e-05 1.5 2.575502232142857e-05 1.5 2.5755580357142856e-05 0.0 2.5762276785714284e-05 0.0 2.576283482142857e-05 1.5 2.5772879464285712e-05 1.5 2.57734375e-05 0.0 2.5780133928571426e-05 0.0 2.5780691964285713e-05 1.5 2.5790736607142854e-05 1.5 2.579129464285714e-05 0.0 2.579799107142857e-05 0.0 2.5798549107142855e-05 1.5 2.5808593749999997e-05 1.5 2.5809151785714283e-05 0.0 2.581584821428571e-05 0.0 2.5816406249999998e-05 1.5 2.5826450892857142e-05 1.5 2.5827008928571426e-05 0.0 2.5833705357142857e-05 0.0 2.583426339285714e-05 1.5 2.5844308035714285e-05 1.5 2.5844866071428568e-05 0.0 2.58515625e-05 0.0 2.5852120535714282e-05 1.5 2.5862165178571427e-05 1.5 2.5862723214285714e-05 0.0 2.5869977678571428e-05 0.0 2.587053571428571e-05 1.5 2.5879464285714283e-05 1.5 2.588002232142857e-05 0.0 2.588783482142857e-05 0.0 2.5888392857142854e-05 1.5 2.589732142857143e-05 1.5 2.5897879464285712e-05 0.0 2.5905691964285713e-05 0.0 2.590625e-05 1.5 2.591517857142857e-05 1.5 2.5915736607142854e-05 0.0 2.5923549107142855e-05 0.0 2.5924107142857142e-05 1.5 2.5933035714285713e-05 1.5 2.593359375e-05 0.0 2.5941406249999997e-05 0.0 2.5941964285714284e-05 1.5 2.5950892857142855e-05 1.5 2.5951450892857142e-05 0.0 2.595926339285714e-05 0.0 2.5959821428571426e-05 1.5 2.5968749999999998e-05 1.5 2.5969308035714284e-05 0.0 2.5977120535714285e-05 0.0 2.597767857142857e-05 1.5 2.598660714285714e-05 1.5 2.5987165178571427e-05 0.0 2.5994977678571428e-05 0.0 2.599553571428571e-05 1.5 2.6004464285714282e-05 1.5 2.600502232142857e-05 0.0 2.601283482142857e-05 0.0 2.6013392857142857e-05 1.5 2.6022321428571428e-05 1.5 2.602287946428571e-05 0.0 2.6030691964285712e-05 0.0 2.603125e-05 1.5 2.604017857142857e-05 1.5 2.6040736607142854e-05 0.0 2.6048549107142855e-05 0.0 2.604910714285714e-05 1.5 2.6058035714285713e-05 1.5 2.605859375e-05 0.0 2.6066406249999997e-05 0.0 2.6066964285714284e-05 1.5 2.6075892857142855e-05 1.5 2.6076450892857142e-05 0.0 2.6084821428571426e-05 0.0 2.6085379464285713e-05 1.5 2.6093191964285714e-05 1.5 2.6093749999999997e-05 0.0 2.610267857142857e-05 0.0 2.6103236607142855e-05 1.5 2.6111049107142856e-05 1.5 2.611160714285714e-05 0.0 2.612053571428571e-05 0.0 2.6121093749999998e-05 1.5 2.612890625e-05 1.5 2.6129464285714285e-05 0.0 2.6138392857142856e-05 0.0 2.613895089285714e-05 1.5 2.614676339285714e-05 1.5 2.6147321428571428e-05 0.0 2.615625e-05 0.0 2.6156808035714282e-05 1.5 2.6164620535714283e-05 1.5 2.616517857142857e-05 0.0 2.617410714285714e-05 0.0 2.6174665178571428e-05 1.5 2.6182477678571426e-05 1.5 2.6183035714285712e-05 0.0 2.6191964285714283e-05 0.0 2.619252232142857e-05 1.5 2.6200334821428568e-05 1.5 2.6200892857142855e-05 0.0 2.6209821428571426e-05 0.0 2.6210379464285713e-05 1.5 2.6218191964285714e-05 1.5 2.6218749999999997e-05 0.0 2.6227678571428568e-05 0.0 2.6228236607142855e-05 1.5 2.6236049107142856e-05 1.5 2.6236607142857143e-05 0.0 2.6245535714285714e-05 0.0 2.6246093749999997e-05 1.5 2.6253906249999998e-05 1.5 2.6254464285714285e-05 0.0 2.6263392857142856e-05 0.0 2.626395089285714e-05 1.5 2.627176339285714e-05 1.5 2.6272321428571427e-05 0.0 2.628125e-05 0.0 2.6281808035714285e-05 1.5 2.6289620535714283e-05 1.5 2.629017857142857e-05 0.0 2.6299665178571428e-05 0.0 2.630022321428571e-05 1.5 2.6306919642857142e-05 1.5 2.6307477678571425e-05 0.0 2.631752232142857e-05 0.0 2.6318080357142857e-05 1.5 2.6324776785714284e-05 1.5 2.632533482142857e-05 0.0 2.6335379464285712e-05 0.0 2.63359375e-05 1.5 2.6342633928571426e-05 1.5 2.6343191964285713e-05 0.0 2.6353236607142855e-05 0.0 2.635379464285714e-05 1.5 2.636049107142857e-05 1.5 2.6361049107142856e-05 0.0 2.6371093749999997e-05 0.0 2.6371651785714284e-05 1.5 2.637834821428571e-05 1.5 2.6378906249999998e-05 0.0 2.6388950892857143e-05 0.0 2.6389508928571426e-05 1.5 2.6396205357142857e-05 1.5 2.639676339285714e-05 0.0 2.6406808035714285e-05 0.0 2.6407366071428568e-05 1.5 2.64140625e-05 1.5 2.6414620535714283e-05 0.0 2.6424665178571427e-05 0.0 2.6425223214285714e-05 1.5 2.643191964285714e-05 1.5 2.6432477678571428e-05 0.0 2.644252232142857e-05 0.0 2.6443080357142856e-05 1.5 2.6449776785714284e-05 1.5 2.645033482142857e-05 0.0 2.6460379464285712e-05 0.0 2.64609375e-05 1.5 2.6467633928571426e-05 1.5 2.6468191964285713e-05 0.0 2.6478236607142854e-05 0.0 2.647879464285714e-05 1.5 2.648549107142857e-05 1.5 2.6486049107142855e-05 0.0 2.6496093749999996e-05 0.0 2.6496651785714283e-05 1.5 2.650334821428571e-05 1.5 2.6503906249999998e-05 0.0 2.6513950892857142e-05 0.0 2.6514508928571426e-05 1.5 2.652064732142857e-05 1.5 2.6521205357142856e-05 0.0 2.6532366071428568e-05 0.0 2.6532924107142855e-05 1.5 2.6538504464285712e-05 1.5 2.65390625e-05 0.0 2.6550223214285714e-05 0.0 2.6550781249999997e-05 1.5 2.6556361607142854e-05 1.5 2.655691964285714e-05 0.0 2.6568080357142856e-05 0.0 2.656863839285714e-05 1.5 2.6574218749999997e-05 1.5 2.6574776785714283e-05 0.0 2.6585937499999998e-05 0.0 2.6586495535714285e-05 1.5 2.6592075892857142e-05 1.5 2.6592633928571426e-05 0.0 2.660379464285714e-05 0.0 2.6604352678571427e-05 1.5 2.6609933035714285e-05 1.5 2.6610491071428568e-05 0.0 2.6621651785714283e-05 0.0 2.662220982142857e-05 1.5 2.6627790178571427e-05 1.5 2.6628348214285714e-05 0.0 2.6639508928571425e-05 0.0 2.6640066964285712e-05 1.5 2.664564732142857e-05 1.5 2.6646205357142856e-05 0.0 2.665736607142857e-05 0.0 2.6657924107142854e-05 1.5 2.666350446428571e-05 1.5 2.66640625e-05 0.0 2.6675223214285713e-05 0.0 2.6675781249999997e-05 1.5 2.6681361607142854e-05 1.5 2.668191964285714e-05 0.0 2.6693080357142856e-05 0.0 2.6693638392857142e-05 1.5 2.669921875e-05 1.5 2.6699776785714283e-05 0.0 2.6710937499999998e-05 0.0 2.6711495535714285e-05 1.5 2.6717075892857142e-05 1.5 2.6717633928571425e-05 0.0 2.672879464285714e-05 0.0 2.6729352678571427e-05 1.5 2.6734933035714284e-05 1.5 2.673549107142857e-05 0.0 2.6746651785714283e-05 0.0 2.674720982142857e-05 1.5 2.675223214285714e-05 1.5 2.6752790178571427e-05 0.0 2.676506696428571e-05 0.0 2.6765625e-05 1.5 2.6770089285714282e-05 1.5 2.677064732142857e-05 0.0 2.6782924107142854e-05 0.0 2.678348214285714e-05 1.5 2.6787946428571428e-05 1.5 2.678850446428571e-05 0.0 2.680078125e-05 0.0 2.6801339285714283e-05 1.5 2.680580357142857e-05 1.5 2.6806361607142854e-05 0.0 2.6818638392857142e-05 0.0 2.6819196428571425e-05 1.5 2.6823660714285713e-05 1.5 2.682421875e-05 0.0 2.6836495535714284e-05 0.0 2.683705357142857e-05 1.5 2.6841517857142855e-05 1.5 2.6842075892857142e-05 0.0 2.6854352678571427e-05 0.0 2.6854910714285713e-05 1.5 2.6859374999999997e-05 1.5 2.6859933035714284e-05 0.0 2.687220982142857e-05 0.0 2.6872767857142856e-05 1.5 2.687723214285714e-05 1.5 2.6877790178571426e-05 0.0 2.689006696428571e-05 0.0 2.6890624999999998e-05 1.5 2.6895089285714285e-05 1.5 2.689564732142857e-05 0.0 2.6907924107142854e-05 0.0 2.690848214285714e-05 1.5 2.6912946428571428e-05 1.5 2.691350446428571e-05 0.0 2.692578125e-05 0.0 2.6926339285714283e-05 1.5 2.693080357142857e-05 1.5 2.6931361607142857e-05 0.0 2.694363839285714e-05 0.0 2.6944196428571425e-05 1.5 2.6948660714285712e-05 1.5 2.694921875e-05 0.0 2.6961495535714284e-05 0.0 2.696205357142857e-05 1.5 2.6966517857142855e-05 1.5 2.696707589285714e-05 0.0 2.6979352678571426e-05 0.0 2.6979910714285713e-05 1.5 2.6984374999999997e-05 1.5 2.6984933035714284e-05 0.0 2.699720982142857e-05 0.0 2.6997767857142855e-05 1.5 2.700223214285714e-05 1.5 2.7002790178571426e-05 0.0 2.7015624999999998e-05 0.0 2.7016183035714284e-05 1.5 2.7019531249999998e-05 1.5 2.7020089285714285e-05 0.0 2.703348214285714e-05 0.0 2.7034040178571427e-05 1.5 2.703738839285714e-05 1.5 2.7037946428571427e-05 0.0 2.7051339285714282e-05 0.0 2.705189732142857e-05 1.5 2.7055245535714283e-05 1.5 2.705580357142857e-05 0.0 2.7069196428571428e-05 0.0 2.706975446428571e-05 1.5 2.7073102678571425e-05 1.5 2.7073660714285712e-05 0.0 2.708705357142857e-05 0.0 2.7087611607142854e-05 1.5 2.709095982142857e-05 1.5 2.7091517857142854e-05 0.0 2.7104910714285713e-05 0.0 2.710546875e-05 1.5 2.7108816964285713e-05 1.5 2.7109374999999997e-05 0.0 2.7122767857142855e-05 0.0 2.7123325892857142e-05 1.5 2.7126674107142856e-05 1.5 2.7127232142857142e-05 0.0 2.7140624999999997e-05 0.0 2.7141183035714284e-05 1.5 2.7144531249999998e-05 1.5 2.7145089285714285e-05 0.0 2.715848214285714e-05 0.0 2.7159040178571426e-05 1.5 2.716238839285714e-05 1.5 2.7162946428571427e-05 0.0 2.7176339285714285e-05 0.0 2.717689732142857e-05 1.5 2.7180245535714282e-05 1.5 2.718080357142857e-05 0.0 2.7194196428571428e-05 0.0 2.719475446428571e-05 1.5 2.7198102678571428e-05 1.5 2.719866071428571e-05 0.0 2.721205357142857e-05 0.0 2.7212611607142857e-05 1.5 2.721595982142857e-05 1.5 2.7216517857142854e-05 0.0 2.7229910714285712e-05 0.0 2.723046875e-05 1.5 2.7233816964285713e-05 1.5 2.7234375e-05 0.0 2.7247767857142855e-05 0.0 2.724832589285714e-05 1.5 2.7251674107142855e-05 1.5 2.7252232142857142e-05 0.0 2.7265624999999997e-05 0.0 2.7266183035714284e-05 1.5 2.7269531249999997e-05 1.5 2.7270089285714284e-05 0.0 2.728348214285714e-05 0.0 2.7284040178571426e-05 1.5 2.728738839285714e-05 1.5 2.7287946428571427e-05 0.0 2.7301339285714285e-05 0.0 2.730189732142857e-05 1.5 2.7305245535714282e-05 1.5 2.730580357142857e-05 0.0 2.7319196428571427e-05 0.0 2.731975446428571e-05 1.5 2.7323102678571428e-05 1.5 2.732366071428571e-05 0.0 2.733705357142857e-05 0.0 2.7337611607142856e-05 1.5 2.734095982142857e-05 1.5 2.7341517857142854e-05 0.0 2.735546875e-05 0.0 2.7356026785714282e-05 1.5 2.7358258928571426e-05 1.5 2.7358816964285712e-05 0.0 2.737332589285714e-05 0.0 2.7373883928571428e-05 1.5 2.7376116071428568e-05 1.5 2.7376674107142855e-05 0.0 2.7391183035714283e-05 0.0 2.739174107142857e-05 1.5 2.7393973214285714e-05 1.5 2.7394531249999997e-05 0.0 2.7409040178571426e-05 0.0 2.7409598214285712e-05 1.5 2.7411830357142856e-05 1.5 2.741238839285714e-05 0.0 2.7426897321428568e-05 0.0 2.7427455357142855e-05 1.5 2.74296875e-05 1.5 2.7430245535714285e-05 0.0 2.7444754464285714e-05 0.0 2.7445312499999997e-05 1.5 2.744754464285714e-05 1.5 2.7448102678571428e-05 0.0 2.7462611607142856e-05 0.0 2.746316964285714e-05 1.5 2.7465401785714283e-05 1.5 2.746595982142857e-05 0.0 2.748046875e-05 0.0 2.7481026785714285e-05 1.5 2.7483258928571425e-05 1.5 2.7483816964285712e-05 0.0 2.749832589285714e-05 0.0 2.7498883928571427e-05 1.5 2.750111607142857e-05 1.5 2.7501674107142854e-05 0.0 2.7516183035714283e-05 0.0 2.751674107142857e-05 1.5 2.7518973214285713e-05 1.5 2.7519531249999997e-05 0.0 2.7534040178571425e-05 0.0 2.7534598214285712e-05 1.5 2.7536830357142856e-05 1.5 2.7537388392857143e-05 0.0 2.755189732142857e-05 0.0 2.7552455357142854e-05 1.5 2.7554687499999998e-05 1.5 2.7555245535714285e-05 0.0 2.7569754464285713e-05 0.0 2.7570312499999997e-05 1.5 2.757254464285714e-05 1.5 2.7573102678571427e-05 0.0 2.7587611607142856e-05 0.0 2.7588169642857142e-05 1.5 2.7590401785714283e-05 1.5 2.759095982142857e-05 0.0 2.7605468749999998e-05 0.0 2.7606026785714285e-05 1.5 2.7608258928571425e-05 1.5 2.7608816964285712e-05 0.0 2.762332589285714e-05 0.0 2.7623883928571427e-05 1.5 2.762611607142857e-05 1.5 2.7626674107142854e-05 0.0 2.7641183035714283e-05 0.0 2.764174107142857e-05 1.5 2.7643973214285713e-05 1.5 2.7644531249999996e-05 0.0 2.7659040178571425e-05 0.0 2.7659598214285712e-05 1.5 2.7661830357142855e-05 1.5 2.7662388392857142e-05 0.0 2.767689732142857e-05 0.0 2.7677455357142854e-05 1.5 2.7679687499999998e-05 1.5 2.7680245535714284e-05 0.0 2.7694754464285713e-05 0.0 2.7695312499999996e-05 1.5 2.769754464285714e-05 1.5 2.7698102678571427e-05 0.0 2.7712611607142855e-05 0.0 2.7713169642857142e-05 1.5 2.7715401785714282e-05 1.5 2.771595982142857e-05 0.0 2.7730468749999998e-05 0.0 2.7731026785714284e-05 1.5 2.7733258928571428e-05 1.5 2.773381696428571e-05 0.0 2.774832589285714e-05 0.0 2.7748883928571427e-05 1.5 2.775111607142857e-05 1.5 2.7751674107142854e-05 0.0 2.7766183035714282e-05 0.0 2.776674107142857e-05 1.5 2.7768973214285713e-05 1.5 2.776953125e-05 0.0 2.7784040178571428e-05 0.0 2.778459821428571e-05 1.5 2.7786830357142855e-05 1.5 2.7787388392857142e-05 0.0 2.780189732142857e-05 0.0 2.7802455357142854e-05 1.5 2.7804687499999997e-05 1.5 2.7805245535714284e-05 0.0 2.7819754464285713e-05 0.0 2.78203125e-05 1.5 2.782254464285714e-05 1.5 2.7823102678571426e-05 0.0 2.7837611607142855e-05 0.0 2.7838169642857142e-05 1.5 2.7840401785714285e-05 1.5 2.784095982142857e-05 0.0 2.7855468749999997e-05 0.0 2.7856026785714284e-05 1.5 2.7858258928571428e-05 1.5 2.785881696428571e-05 0.0 2.787332589285714e-05 0.0 2.7873883928571426e-05 1.5 2.787611607142857e-05 1.5 2.7876674107142857e-05 0.0 2.7891183035714285e-05 0.0 2.789174107142857e-05 1.5 2.7893973214285712e-05 1.5 2.789453125e-05 0.0 2.7909040178571428e-05 0.0 2.790959821428571e-05 1.5 2.7911830357142855e-05 1.5 2.791238839285714e-05 0.0 2.792689732142857e-05 0.0 2.7927455357142857e-05 1.5 2.7929687499999997e-05 1.5 2.7930245535714284e-05 0.0 2.7944754464285712e-05 0.0 2.79453125e-05 1.5 2.794754464285714e-05 1.5 2.7948102678571426e-05 0.0 2.7962611607142855e-05 0.0 2.796316964285714e-05 1.5 2.7965401785714285e-05 1.5 2.796595982142857e-05 0.0 2.7980468749999997e-05 0.0 2.7981026785714284e-05 1.5 2.7983258928571427e-05 1.5 2.798381696428571e-05 0.0 2.799832589285714e-05 0.0 2.7998883928571426e-05 1.5 2.800111607142857e-05 1.5 2.8001674107142856e-05 0.0 2.8016183035714285e-05 0.0 2.801674107142857e-05 1.5 2.8018973214285712e-05 1.5 2.801953125e-05 0.0 2.8034040178571427e-05 0.0 2.803459821428571e-05 1.5 2.8036830357142854e-05 1.5 2.803738839285714e-05 0.0 2.805189732142857e-05 0.0 2.8052455357142856e-05 1.5 2.8054687499999997e-05 1.5 2.8055245535714283e-05 0.0 2.8069754464285712e-05 0.0 2.80703125e-05 1.5 2.8072544642857142e-05 1.5 2.8073102678571426e-05 0.0 2.8087611607142854e-05 0.0 2.808816964285714e-05 1.5 2.8090401785714285e-05 1.5 2.8090959821428568e-05 0.0 2.8105468749999997e-05 0.0 2.8106026785714283e-05 1.5 2.8108258928571427e-05 1.5 2.8108816964285714e-05 0.0 2.8123325892857142e-05 0.0 2.8123883928571426e-05 1.5 2.812611607142857e-05 1.5 2.8126674107142856e-05 0.0 2.8141183035714285e-05 0.0 2.8141741071428568e-05 1.5 2.814397321428571e-05 1.5 2.814453125e-05 0.0 2.8159040178571427e-05 0.0 2.8159598214285714e-05 1.5 2.8161830357142854e-05 1.5 2.816238839285714e-05 0.0 2.817689732142857e-05 0.0 2.8177455357142856e-05 1.5 2.8179687499999996e-05 1.5 2.8180245535714283e-05 0.0 2.819475446428571e-05 0.0 2.81953125e-05 1.5 2.8197544642857142e-05 1.5 2.8198102678571425e-05 0.0 2.8212611607142854e-05 0.0 2.821316964285714e-05 1.5 2.8215401785714284e-05 1.5 2.8215959821428568e-05 0.0 2.8230468749999996e-05 0.0 2.8231026785714283e-05 1.5 2.8233258928571427e-05 1.5 2.8233816964285713e-05 0.0 2.8248325892857142e-05 0.0 2.8248883928571425e-05 1.5 2.825111607142857e-05 1.5 2.8251674107142856e-05 0.0 2.8266183035714284e-05 0.0 2.826674107142857e-05 1.5 2.826897321428571e-05 1.5 2.8269531249999998e-05 0.0 2.8284040178571427e-05 0.0 2.8284598214285713e-05 1.5 2.8286830357142854e-05 1.5 2.828738839285714e-05 0.0 2.830189732142857e-05 0.0 2.8302455357142856e-05 1.5 2.83046875e-05 1.5 2.8305245535714283e-05 0.0 2.831975446428571e-05 0.0 2.8320312499999998e-05 1.5 2.832254464285714e-05 1.5 2.8323102678571425e-05 0.0 2.8337611607142854e-05 0.0 2.833816964285714e-05 1.5 2.8340401785714284e-05 1.5 2.834095982142857e-05 0.0 2.835546875e-05 0.0 2.8356026785714283e-05 1.5 2.8358258928571426e-05 1.5 2.8358816964285713e-05 0.0 2.837332589285714e-05 0.0 2.8373883928571425e-05 1.5 2.837611607142857e-05 1.5 2.8376674107142855e-05 0.0 2.8391183035714284e-05 0.0 2.839174107142857e-05 1.5 2.839397321428571e-05 1.5 2.8394531249999998e-05 0.0 2.8409040178571426e-05 0.0 2.8409598214285713e-05 1.5 2.8411830357142857e-05 1.5 2.841238839285714e-05 0.0 2.842689732142857e-05 0.0 2.8427455357142855e-05 1.5 2.84296875e-05 1.5 2.8430245535714282e-05 0.0 2.844475446428571e-05 0.0 2.8445312499999998e-05 1.5 2.844754464285714e-05 1.5 2.8448102678571428e-05 0.0 2.8462611607142857e-05 0.0 2.846316964285714e-05 1.5 2.8465401785714284e-05 1.5 2.846595982142857e-05 0.0 2.848046875e-05 0.0 2.8481026785714282e-05 1.5 2.8483258928571426e-05 1.5 2.8483816964285713e-05 0.0 2.849832589285714e-05 0.0 2.8498883928571428e-05 1.5 2.8501116071428568e-05 1.5 2.8501674107142855e-05 0.0 2.8516183035714284e-05 0.0 2.851674107142857e-05 1.5 2.851897321428571e-05 1.5 2.8519531249999997e-05 0.0 2.8534040178571426e-05 0.0 2.8534598214285713e-05 1.5 2.8536830357142856e-05 1.5 2.853738839285714e-05 0.0 2.8551897321428568e-05 0.0 2.8552455357142855e-05 1.5 2.85546875e-05 1.5 2.8555245535714282e-05 0.0 2.856975446428571e-05 0.0 2.8570312499999997e-05 1.5 2.857254464285714e-05 1.5 2.8573102678571428e-05 0.0 2.8587611607142856e-05 0.0 2.858816964285714e-05 1.5 2.8590401785714283e-05 1.5 2.859095982142857e-05 0.0 2.860546875e-05 0.0 2.8606026785714282e-05 1.5 2.8608258928571426e-05 1.5 2.8608816964285712e-05 0.0 2.862332589285714e-05 0.0 2.8623883928571428e-05 1.5 2.8626116071428568e-05 1.5 2.8626674107142855e-05 0.0 2.8641183035714283e-05 0.0 2.864174107142857e-05 1.5 2.8643973214285714e-05 1.5 2.8644531249999997e-05 0.0 2.8659040178571426e-05 0.0 2.8659598214285712e-05 1.5 2.8661830357142856e-05 1.5 2.866238839285714e-05 0.0 2.8676897321428568e-05 0.0 2.8677455357142855e-05 1.5 2.86796875e-05 1.5 2.8680245535714285e-05 0.0 2.8694754464285714e-05 0.0 2.8695312499999997e-05 1.5 2.869754464285714e-05 1.5 2.8698102678571427e-05 0.0 2.8712611607142856e-05 0.0 2.871316964285714e-05 1.5 2.8715401785714283e-05 1.5 2.871595982142857e-05 0.0 2.8730468749999998e-05 0.0 2.8731026785714285e-05 1.5 2.8733258928571425e-05 1.5 2.8733816964285712e-05 0.0 2.874832589285714e-05 0.0 2.8748883928571427e-05 1.5 2.875111607142857e-05 1.5 2.8751674107142854e-05 0.0 2.8766183035714283e-05 0.0 2.876674107142857e-05 1.5 2.8768973214285713e-05 1.5 2.8769531249999997e-05 0.0 2.8784040178571425e-05 0.0 2.8784598214285712e-05 1.5 2.8786830357142856e-05 1.5 2.8787388392857142e-05 0.0 2.880189732142857e-05 0.0 2.8802455357142854e-05 1.5 2.8804687499999998e-05 1.5 2.8805245535714285e-05 0.0 2.8819754464285713e-05 0.0 2.8820312499999997e-05 1.5 2.882254464285714e-05 1.5 2.8823102678571427e-05 0.0 2.8837611607142856e-05 0.0 2.8838169642857142e-05 1.5 2.884095982142857e-05 1.5 2.8841517857142856e-05 0.0 2.885491071428571e-05 0.0 2.8855468749999998e-05 1.5 2.885881696428571e-05 1.5 2.8859375e-05 0.0 2.8872767857142853e-05 0.0 2.887332589285714e-05 1.5 2.8876674107142854e-05 1.5 2.887723214285714e-05 0.0 2.8890625e-05 0.0 2.8891183035714283e-05 1.5 2.8894531249999996e-05 1.5 2.8895089285714283e-05 0.0 2.890848214285714e-05 0.0 2.8909040178571425e-05 1.5 2.8912388392857142e-05 1.5 2.8912946428571425e-05 0.0 2.8926339285714284e-05 0.0 2.892689732142857e-05 1.5 2.8930245535714284e-05 1.5 2.8930803571428568e-05 0.0 2.8944196428571426e-05 0.0 2.8944754464285713e-05 1.5 2.8948102678571427e-05 1.5 2.8948660714285713e-05 0.0 2.896205357142857e-05 0.0 2.8962611607142855e-05 1.5 2.896595982142857e-05 1.5 2.8966517857142856e-05 0.0 2.897991071428571e-05 0.0 2.8980468749999998e-05 1.5 2.898381696428571e-05 1.5 2.8984374999999998e-05 0.0 2.8997767857142857e-05 0.0 2.899832589285714e-05 1.5 2.9001674107142854e-05 1.5 2.900223214285714e-05 0.0 2.9015625e-05 0.0 2.9016183035714282e-05 1.5 2.901953125e-05 1.5 2.9020089285714283e-05 0.0 2.903348214285714e-05 0.0 2.9034040178571428e-05 1.5 2.9037388392857142e-05 1.5 2.9037946428571425e-05 0.0 2.9051339285714284e-05 0.0 2.905189732142857e-05 1.5 2.9055245535714284e-05 1.5 2.905580357142857e-05 0.0 2.9069196428571426e-05 0.0 2.9069754464285713e-05 1.5 2.9073102678571426e-05 1.5 2.9073660714285713e-05 0.0 2.9087053571428568e-05 0.0 2.9087611607142855e-05 1.5 2.909095982142857e-05 1.5 2.9091517857142855e-05 0.0 2.9104910714285714e-05 0.0 2.9105468749999997e-05 1.5 2.910881696428571e-05 1.5 2.9109374999999998e-05 0.0 2.9122767857142856e-05 0.0 2.912332589285714e-05 1.5 2.9126674107142857e-05 1.5 2.912723214285714e-05 0.0 2.9140625e-05 0.0 2.9141183035714285e-05 1.5 2.914453125e-05 1.5 2.9145089285714282e-05 0.0 2.915848214285714e-05 0.0 2.9159040178571428e-05 1.5 2.916238839285714e-05 1.5 2.9162946428571428e-05 0.0 2.9175781249999996e-05 0.0 2.9176339285714283e-05 1.5 2.918080357142857e-05 1.5 2.9181361607142854e-05 0.0 2.9193638392857142e-05 0.0 2.9194196428571425e-05 1.5 2.9198660714285713e-05 1.5 2.919921875e-05 0.0 2.9211495535714284e-05 0.0 2.9212053571428568e-05 1.5 2.9216517857142855e-05 1.5 2.9217075892857142e-05 0.0 2.9229352678571427e-05 0.0 2.9229910714285714e-05 1.5 2.9234374999999997e-05 1.5 2.9234933035714284e-05 0.0 2.924720982142857e-05 0.0 2.9247767857142856e-05 1.5 2.925223214285714e-05 1.5 2.9252790178571426e-05 0.0 2.926506696428571e-05 0.0 2.9265624999999998e-05 1.5 2.9270089285714282e-05 1.5 2.927064732142857e-05 0.0 2.9282924107142854e-05 0.0 2.928348214285714e-05 1.5 2.9287946428571428e-05 1.5 2.928850446428571e-05 0.0 2.930078125e-05 0.0 2.9301339285714283e-05 1.5 2.930580357142857e-05 1.5 2.9306361607142853e-05 0.0 2.9318638392857142e-05 0.0 2.9319196428571425e-05 1.5 2.9323660714285712e-05 1.5 2.932421875e-05 0.0 2.9336495535714284e-05 0.0 2.933705357142857e-05 1.5 2.9341517857142855e-05 1.5 2.934207589285714e-05 0.0 2.9354352678571426e-05 0.0 2.9354910714285713e-05 1.5 2.9359374999999997e-05 1.5 2.9359933035714284e-05 0.0 2.937220982142857e-05 0.0 2.9372767857142855e-05 1.5 2.937723214285714e-05 1.5 2.9377790178571426e-05 0.0 2.939006696428571e-05 0.0 2.9390624999999998e-05 1.5 2.9395089285714285e-05 1.5 2.939564732142857e-05 0.0 2.9407924107142853e-05 0.0 2.940848214285714e-05 1.5 2.9412946428571427e-05 1.5 2.941350446428571e-05 0.0 2.942578125e-05 0.0 2.9426339285714282e-05 1.5 2.9431361607142856e-05 1.5 2.943191964285714e-05 0.0 2.9443080357142855e-05 0.0 2.944363839285714e-05 1.5 2.944921875e-05 1.5 2.9449776785714282e-05 0.0 2.9460937499999997e-05 0.0 2.9461495535714284e-05 1.5 2.946707589285714e-05 1.5 2.9467633928571428e-05 0.0 2.947879464285714e-05 0.0 2.9479352678571426e-05 1.5 2.9484933035714283e-05 1.5 2.948549107142857e-05 0.0 2.9496651785714285e-05 0.0 2.949720982142857e-05 1.5 2.9502790178571426e-05 1.5 2.9503348214285713e-05 0.0 2.9514508928571427e-05 0.0 2.951506696428571e-05 1.5 2.9520647321428568e-05 1.5 2.9521205357142855e-05 0.0 2.953236607142857e-05 0.0 2.9532924107142856e-05 1.5 2.9538504464285714e-05 1.5 2.9539062499999997e-05 0.0 2.9550223214285712e-05 0.0 2.955078125e-05 1.5 2.9556361607142856e-05 1.5 2.955691964285714e-05 0.0 2.9568080357142854e-05 0.0 2.956863839285714e-05 1.5 2.957421875e-05 1.5 2.9574776785714285e-05 0.0 2.9585937499999997e-05 0.0 2.9586495535714283e-05 1.5 2.959207589285714e-05 1.5 2.9592633928571428e-05 0.0 2.9603794642857142e-05 0.0 2.9604352678571426e-05 1.5 2.9609933035714283e-05 1.5 2.961049107142857e-05 0.0 2.9621651785714285e-05 0.0 2.9622209821428568e-05 1.5 2.9627790178571425e-05 1.5 2.9628348214285712e-05 0.0 2.9639508928571427e-05 0.0 2.9640066964285714e-05 1.5 2.9645647321428568e-05 1.5 2.9646205357142855e-05 0.0 2.965736607142857e-05 0.0 2.9657924107142856e-05 1.5 2.9664062499999997e-05 1.5 2.9664620535714284e-05 0.0 2.9674665178571425e-05 0.0 2.967522321428571e-05 1.5 2.968191964285714e-05 1.5 2.9682477678571426e-05 0.0 2.969252232142857e-05 0.0 2.9693080357142854e-05 1.5 2.9699776785714285e-05 1.5 2.9700334821428568e-05 0.0 2.9710379464285713e-05 0.0 2.9710937499999996e-05 1.5 2.9717633928571427e-05 1.5 2.971819196428571e-05 0.0 2.9728236607142855e-05 0.0 2.9728794642857142e-05 1.5 2.973549107142857e-05 1.5 2.9736049107142856e-05 0.0 2.9746093749999998e-05 0.0 2.9746651785714284e-05 1.5 2.9753348214285712e-05 1.5 2.975390625e-05 0.0 2.976395089285714e-05 0.0 2.9764508928571427e-05 1.5 2.9771205357142854e-05 1.5 2.977176339285714e-05 0.0 2.9781808035714282e-05 0.0 2.978236607142857e-05 1.5 2.9789062499999996e-05 1.5 2.9789620535714283e-05 0.0 2.9799665178571428e-05 0.0 2.980022321428571e-05 1.5 2.9806919642857142e-05 1.5 2.9807477678571426e-05 0.0 2.981752232142857e-05 0.0 2.9818080357142854e-05 1.5 2.9824776785714285e-05 1.5 2.9825334821428568e-05 0.0 2.9835379464285713e-05 0.0 2.98359375e-05 1.5 2.9842633928571427e-05 1.5 2.9843191964285714e-05 0.0 2.9853236607142855e-05 0.0 2.985379464285714e-05 1.5 2.986049107142857e-05 1.5 2.9861049107142856e-05 0.0 2.9871093749999997e-05 0.0 2.9871651785714284e-05 1.5 2.987834821428571e-05 1.5 2.9878906249999998e-05 0.0 2.9888392857142856e-05 0.0 2.988895089285714e-05 1.5 2.989676339285714e-05 1.5 2.9897321428571427e-05 0.0 2.990625e-05 0.0 2.9906808035714285e-05 1.5 2.9914620535714283e-05 1.5 2.991517857142857e-05 0.0 2.992410714285714e-05 0.0 2.9924665178571428e-05 1.5 2.9932477678571425e-05 1.5 2.9933035714285712e-05 0.0 2.9941964285714283e-05 0.0 2.994252232142857e-05 1.5 2.995033482142857e-05 1.5 2.9950892857142854e-05 0.0 2.9959821428571425e-05 0.0 2.9960379464285712e-05 1.5 2.9968191964285713e-05 1.5 2.9968749999999997e-05 0.0 2.9977678571428568e-05 0.0 2.9978236607142855e-05 1.5 2.9986049107142856e-05 1.5 2.9986607142857142e-05 0.0 2.9995535714285713e-05 0.0 2.9996093749999997e-05 1.5 3.0003906249999998e-05 1.5 3.0004464285714285e-05 0.0 3.0013392857142856e-05 0.0 3.001395089285714e-05 1.5 3.002176339285714e-05 1.5 3.0022321428571427e-05 0.0 3.0031249999999998e-05 0.0 3.0031808035714285e-05 1.5 3.0039620535714283e-05 1.5 3.004017857142857e-05 0.0 3.004910714285714e-05 0.0 3.0049665178571427e-05 1.5 3.0057477678571425e-05 1.5 3.005803571428571e-05 0.0 3.0066964285714283e-05 0.0 3.006752232142857e-05 1.5 3.007533482142857e-05 1.5 3.0075892857142854e-05 0.0 3.0084821428571425e-05 0.0 3.0085379464285712e-05 1.5 3.0093191964285713e-05 1.5 3.0093749999999996e-05 0.0 3.0102120535714284e-05 0.0 3.010267857142857e-05 1.5 3.0111607142857142e-05 1.5 3.0112165178571425e-05 0.0 3.0119977678571426e-05 0.0 3.0120535714285713e-05 1.5 3.0129464285714284e-05 1.5 3.0130022321428568e-05 0.0 3.013783482142857e-05 0.0 3.0138392857142855e-05 1.5 3.0147321428571427e-05 1.5 3.0147879464285713e-05 0.0 3.015569196428571e-05 0.0 3.0156249999999998e-05 1.5 3.016517857142857e-05 1.5 3.0165736607142856e-05 0.0 3.0173549107142853e-05 0.0 3.017410714285714e-05 1.5 3.018303571428571e-05 1.5 3.0183593749999998e-05 0.0 3.019140625e-05 0.0 3.0191964285714282e-05 1.5 3.0200892857142854e-05 1.5 3.020145089285714e-05 0.0 3.020926339285714e-05 0.0 3.0209821428571425e-05 1.5 3.021875e-05 1.5 3.0219308035714283e-05 0.0 3.0227120535714284e-05 0.0 3.022767857142857e-05 1.5 3.023660714285714e-05 1.5 3.0237165178571425e-05 0.0 3.0244977678571426e-05 0.0 3.0245535714285713e-05 1.5 3.0254464285714284e-05 1.5 3.025502232142857e-05 0.0 3.026283482142857e-05 0.0 3.0263392857142855e-05 1.5 3.0272321428571426e-05 1.5 3.0272879464285713e-05 0.0 3.028069196428571e-05 0.0 3.0281249999999997e-05 1.5 3.029017857142857e-05 1.5 3.0290736607142855e-05 0.0 3.0298549107142856e-05 0.0 3.029910714285714e-05 1.5 3.030803571428571e-05 1.5 3.0308593749999998e-05 0.0 3.0315848214285712e-05 0.0 3.031640625e-05 1.5 3.032645089285714e-05 1.5 3.0327008928571427e-05 0.0 3.0333705357142854e-05 0.0 3.033426339285714e-05 1.5 3.0344308035714282e-05 1.5 3.034486607142857e-05 0.0 3.0351562499999997e-05 0.0 3.0352120535714283e-05 1.5 3.0362165178571428e-05 1.5 3.036272321428571e-05 0.0 3.0369419642857142e-05 0.0 3.0369977678571426e-05 1.5 3.038002232142857e-05 1.5 3.0380580357142854e-05 0.0 3.0387276785714285e-05 0.0 3.0387834821428568e-05 1.5 3.0397879464285713e-05 1.5 3.03984375e-05 0.0 3.0405133928571427e-05 0.0 3.0405691964285714e-05 1.5 3.0415736607142855e-05 1.5 3.0416294642857142e-05 0.0 3.042299107142857e-05 0.0 3.0423549107142856e-05 1.5 3.0433593749999997e-05 1.5 3.0434151785714284e-05 0.0 3.044084821428571e-05 0.0 3.044140625e-05 1.5 3.045145089285714e-05 1.5 3.0452008928571426e-05 0.0 3.0458705357142854e-05 0.0 3.045926339285714e-05 1.5 3.0469308035714282e-05 1.5 3.046986607142857e-05 0.0 3.0476562499999996e-05 0.0 3.0477120535714283e-05 1.5 3.0487165178571428e-05 1.5 3.048772321428571e-05 0.0 3.0494419642857142e-05 0.0 3.0494977678571425e-05 1.5 3.050502232142857e-05 1.5 3.0505580357142853e-05 0.0 3.0512276785714284e-05 0.0 3.0512834821428568e-05 1.5 3.052287946428571e-05 1.5 3.05234375e-05 0.0 3.0530133928571427e-05 0.0 3.053069196428571e-05 1.5 3.054129464285714e-05 1.5 3.0541852678571425e-05 0.0 3.0547433035714286e-05 0.0 3.054799107142857e-05 1.5 3.0559151785714284e-05 1.5 3.055970982142857e-05 0.0 3.056529017857143e-05 0.0 3.056584821428571e-05 1.5 3.0577008928571426e-05 1.5 3.057756696428571e-05 0.0 3.058314732142857e-05 0.0 3.0583705357142854e-05 1.5 3.059486607142857e-05 1.5 3.059542410714285e-05 0.0 3.060100446428571e-05 0.0 3.0601562499999996e-05 1.5 3.061272321428571e-05 1.5 3.061328125e-05 0.0 3.0618861607142855e-05 0.0 3.061941964285714e-05 1.5 3.063058035714285e-05 1.5 3.063113839285714e-05 0.0 3.063671875e-05 0.0 3.063727678571428e-05 1.5 3.0648437499999995e-05 1.5 3.0648995535714285e-05 0.0 3.065457589285714e-05 0.0 3.065513392857143e-05 1.5 3.066629464285714e-05 1.5 3.066685267857143e-05 0.0 3.067243303571428e-05 0.0 3.067299107142857e-05 1.5 3.068415178571429e-05 1.5 3.068470982142857e-05 0.0 3.0690290178571424e-05 0.0 3.0690848214285714e-05 1.5 3.070200892857143e-05 1.5 3.070256696428571e-05 0.0 3.0708147321428566e-05 0.0 3.070870535714286e-05 1.5 3.071986607142857e-05 1.5 3.0720424107142855e-05 0.0 3.072600446428571e-05 0.0 3.07265625e-05 1.5 3.0737723214285714e-05 1.5 3.073828125e-05 0.0 3.074386160714286e-05 0.0 3.074441964285714e-05 1.5 3.0755580357142856e-05 1.5 3.075613839285714e-05 0.0 3.076171875e-05 0.0 3.0762276785714284e-05 1.5 3.077399553571428e-05 1.5 3.077455357142857e-05 0.0 3.077901785714285e-05 0.0 3.077957589285714e-05 1.5 3.0791852678571424e-05 1.5 3.0792410714285714e-05 0.0 3.0796874999999995e-05 0.0 3.0797433035714285e-05 1.5 3.0809709821428566e-05 1.5 3.0810267857142857e-05 0.0 3.0814732142857144e-05 0.0 3.081529017857143e-05 1.5 3.082756696428571e-05 1.5 3.0828125e-05 0.0 3.0832589285714286e-05 0.0 3.083314732142857e-05 1.5 3.084542410714286e-05 1.5 3.084598214285714e-05 0.0 3.085044642857143e-05 0.0 3.085100446428571e-05 1.5 3.086328125e-05 1.5 3.0863839285714284e-05 0.0 3.086830357142857e-05 0.0 3.0868861607142854e-05 1.5 3.088113839285714e-05 1.5 3.0881696428571426e-05 0.0 3.088616071428571e-05 0.0 3.0886718749999996e-05 1.5 3.0898995535714285e-05 1.5 3.089955357142857e-05 0.0 3.0904017857142855e-05 0.0 3.090457589285714e-05 1.5 3.091685267857143e-05 1.5 3.091741071428571e-05 0.0 3.0921875e-05 0.0 3.092243303571428e-05 1.5 3.093470982142857e-05 1.5 3.093526785714285e-05 0.0 3.093973214285714e-05 0.0 3.0940290178571423e-05 1.5 3.095256696428571e-05 1.5 3.0953124999999995e-05 0.0 3.095758928571428e-05 0.0 3.095814732142857e-05 1.5 3.0970424107142854e-05 1.5 3.097098214285714e-05 0.0 3.0975446428571425e-05 0.0 3.0976004464285715e-05 1.5 3.0988281249999996e-05 1.5 3.0988839285714287e-05 0.0 3.099330357142857e-05 0.0 3.099386160714286e-05 1.5 3.100613839285714e-05 1.5 3.100669642857143e-05 0.0 3.101116071428571e-05 0.0 3.101171875e-05 1.5 3.102399553571428e-05 1.5 3.102455357142857e-05 0.0 3.102845982142857e-05 0.0 3.102901785714285e-05 1.5 3.1042410714285714e-05 1.5 3.104296875e-05 0.0 3.104631696428571e-05 0.0 3.1046875e-05 1.5 3.1060267857142856e-05 1.5 3.106082589285714e-05 0.0 3.106417410714285e-05 0.0 3.106473214285714e-05 1.5 3.1078125e-05 1.5 3.107868303571428e-05 0.0 3.1082031249999995e-05 0.0 3.1082589285714285e-05 1.5 3.109598214285714e-05 1.5 3.1096540178571424e-05 0.0 3.109988839285714e-05 0.0 3.110044642857143e-05 1.5 3.111383928571428e-05 1.5 3.1114397321428566e-05 0.0 3.111774553571429e-05 0.0 3.111830357142857e-05 1.5 3.1131696428571425e-05 1.5 3.1132254464285715e-05 0.0 3.113560267857143e-05 0.0 3.113616071428571e-05 1.5 3.114955357142857e-05 1.5 3.115011160714286e-05 0.0 3.115345982142857e-05 0.0 3.1154017857142855e-05 1.5 3.116741071428571e-05 1.5 3.116796875e-05 0.0 3.1171316964285714e-05 0.0 3.1171875e-05 1.5 3.118526785714285e-05 1.5 3.118582589285714e-05 0.0 3.1189174107142856e-05 0.0 3.118973214285714e-05 1.5 3.1203124999999994e-05 1.5 3.1203683035714285e-05 0.0 3.120703125e-05 0.0 3.120758928571428e-05 1.5 3.1220982142857144e-05 1.5 3.122154017857143e-05 0.0 3.122488839285714e-05 0.0 3.1225446428571424e-05 1.5 3.1238839285714286e-05 1.5 3.123939732142857e-05 0.0 3.124274553571428e-05 0.0 3.1243303571428566e-05 1.5 3.125669642857143e-05 1.5 3.125725446428571e-05 0.0 3.1260602678571425e-05 0.0 3.126116071428571e-05 1.5 3.127455357142857e-05 1.5 3.1275111607142854e-05 0.0 3.127845982142857e-05 0.0 3.127901785714286e-05 1.5 3.129241071428571e-05 1.5 3.1292968749999996e-05 0.0 3.129631696428571e-05 0.0 3.1296875e-05 1.5 3.1310267857142855e-05 1.5 3.131082589285714e-05 0.0 3.131417410714285e-05 0.0 3.131473214285714e-05 1.5 3.1328125e-05 1.5 3.132868303571428e-05 0.0 3.1332031249999995e-05 0.0 3.1332589285714285e-05 1.5 3.134598214285714e-05 1.5 3.134654017857142e-05 0.0 3.1349888392857144e-05 0.0 3.135044642857143e-05 1.5 3.136439732142857e-05 1.5 3.1364955357142856e-05 0.0 3.1367187499999996e-05 0.0 3.1367745535714286e-05 1.5 3.1382254464285715e-05 1.5 3.13828125e-05 0.0 3.138504464285714e-05 0.0 3.138560267857143e-05 1.5 3.140011160714286e-05 1.5 3.140066964285714e-05 0.0 3.140290178571428e-05 0.0 3.140345982142857e-05 1.5 3.141796875e-05 1.5 3.141852678571428e-05 0.0 3.142075892857143e-05 0.0 3.142131696428571e-05 1.5 3.143582589285714e-05 1.5 3.1436383928571425e-05 0.0 3.143861607142857e-05 0.0 3.1439174107142855e-05 1.5 3.1453683035714284e-05 1.5 3.145424107142857e-05 0.0 3.1456473214285714e-05 0.0 3.145703125e-05 1.5 3.1471540178571426e-05 1.5 3.147209821428571e-05 0.0 3.1474330357142857e-05 0.0 3.147488839285714e-05 1.5 3.148939732142857e-05 1.5 3.148995535714285e-05 0.0 3.14921875e-05 0.0 3.149274553571428e-05 1.5 3.150725446428571e-05 1.5 3.15078125e-05 0.0 3.151004464285714e-05 0.0 3.1510602678571425e-05 1.5 3.152511160714285e-05 1.5 3.152566964285714e-05 0.0 3.1527901785714284e-05 0.0 3.152845982142857e-05 1.5 3.1542968749999995e-05 1.5 3.1543526785714286e-05 0.0 3.1545758928571426e-05 0.0 3.154631696428571e-05 1.5 3.156082589285714e-05 1.5 3.156138392857143e-05 0.0 3.156361607142857e-05 0.0 3.156417410714285e-05 1.5 3.157868303571428e-05 1.5 3.157924107142857e-05 0.0 3.158147321428571e-05 0.0 3.158203125e-05 1.5 3.159654017857143e-05 1.5 3.159709821428571e-05 0.0 3.159933035714285e-05 0.0 3.159988839285714e-05 1.5 3.161439732142857e-05 1.5 3.1614955357142855e-05 0.0 3.1617187499999995e-05 0.0 3.1617745535714285e-05 1.5 3.1632254464285714e-05 1.5 3.16328125e-05 0.0 3.163504464285714e-05 0.0 3.163560267857143e-05 1.5 3.1650111607142856e-05 1.5 3.165066964285714e-05 0.0 3.1652901785714287e-05 0.0 3.165345982142857e-05 1.5 3.166796875e-05 1.5 3.166852678571428e-05 0.0 3.167075892857143e-05 0.0 3.167131696428571e-05 1.5 3.168582589285714e-05 1.5 3.1686383928571424e-05 0.0 3.168861607142857e-05 0.0 3.1689174107142855e-05 1.5 3.170368303571428e-05 1.5 3.1704241071428567e-05 0.0 3.1706473214285714e-05 0.0 3.170703125e-05 1.5 3.1721540178571425e-05 1.5 3.172209821428571e-05 0.0 3.1724330357142856e-05 0.0 3.172488839285714e-05 1.5 3.173939732142857e-05 1.5 3.173995535714286e-05 0.0 3.17421875e-05 0.0 3.174274553571428e-05 1.5 3.175725446428571e-05 1.5 3.17578125e-05 0.0 3.176004464285714e-05 0.0 3.1760602678571424e-05 1.5 3.177511160714285e-05 1.5 3.177566964285714e-05 0.0 3.177790178571428e-05 0.0 3.1778459821428566e-05 1.5 3.1792968749999995e-05 1.5 3.1793526785714285e-05 0.0 3.1795758928571425e-05 0.0 3.1796316964285715e-05 1.5 3.1810825892857144e-05 1.5 3.181138392857143e-05 0.0 3.181361607142857e-05 0.0 3.181417410714286e-05 1.5 3.1828683035714286e-05 1.5 3.182924107142857e-05 0.0 3.183147321428571e-05 0.0 3.183203125e-05 1.5 3.184654017857143e-05 1.5 3.184709821428571e-05 0.0 3.184933035714285e-05 0.0 3.184988839285714e-05 1.5 3.186439732142857e-05 1.5 3.1864955357142854e-05 0.0 3.1867187499999994e-05 0.0 3.1867745535714285e-05 1.5 3.188225446428571e-05 1.5 3.1882812499999997e-05 0.0 3.1885044642857144e-05 0.0 3.188560267857143e-05 1.5 3.1900111607142856e-05 1.5 3.190066964285714e-05 0.0 3.1902901785714286e-05 0.0 3.190345982142857e-05 1.5 3.191796875e-05 1.5 3.191852678571428e-05 0.0 3.192075892857143e-05 0.0 3.192131696428571e-05 1.5 3.193582589285714e-05 1.5 3.1936383928571424e-05 0.0 3.193861607142857e-05 0.0 3.1939174107142854e-05 1.5 3.195368303571428e-05 1.5 3.1954241071428566e-05 0.0 3.195647321428571e-05 0.0 3.1957031249999996e-05 1.5 3.1971540178571425e-05 1.5 3.1972098214285715e-05 0.0 3.1974330357142855e-05 0.0 3.197488839285714e-05 1.5 3.198939732142857e-05 1.5 3.198995535714286e-05 0.0 3.19921875e-05 0.0 3.199274553571428e-05 1.5 3.200725446428571e-05 1.5 3.20078125e-05 0.0 3.201004464285714e-05 0.0 3.201060267857142e-05 1.5 3.202511160714285e-05 1.5 3.202566964285714e-05 0.0 3.202790178571428e-05 0.0 3.202845982142857e-05 1.5 3.204296875e-05 1.5 3.2043526785714284e-05 0.0 3.2045758928571424e-05 0.0 3.2046316964285715e-05 1.5 3.206082589285714e-05 1.5 3.2061383928571427e-05 0.0 3.206361607142857e-05 0.0 3.206417410714286e-05 1.5 3.2078683035714286e-05 1.5 3.207924107142857e-05 0.0 3.208147321428571e-05 0.0 3.208203125e-05 1.5 3.209654017857143e-05 1.5 3.209709821428571e-05 0.0 3.209933035714285e-05 0.0 3.209988839285714e-05 1.5 )"
spice_ignore=true}
C {devices/gnd.sym} 480 -1540 0 0 {name=l29 lab=GND}
C {devices/gnd.sym} 400 -1540 0 0 {name=l30 lab=GND}
C {devices/gnd.sym} 760 -1540 0 0 {name=l31 lab=GND}
C {devices/vsource.sym} 940 -1630 0 0 {name=Vofs_Q value=\{VDD\}
}
C {devices/vcvs.sym} 940 -1750 0 0 {name=E3 value=1}
C {devices/gnd.sym} 940 -1540 0 0 {name=l32 lab=GND}
C {devices/gnd.sym} 860 -1540 0 0 {name=l33 lab=GND}
C {devices/gnd.sym} 560 -1540 0 0 {name=l45 lab=GND}
